VERSION 5.8 ;
BUSBITCHARS "[]" ;
DIVIDERCHAR "/" ;
UNITS
    DATABASE MICRONS 1000 ;
END UNITS

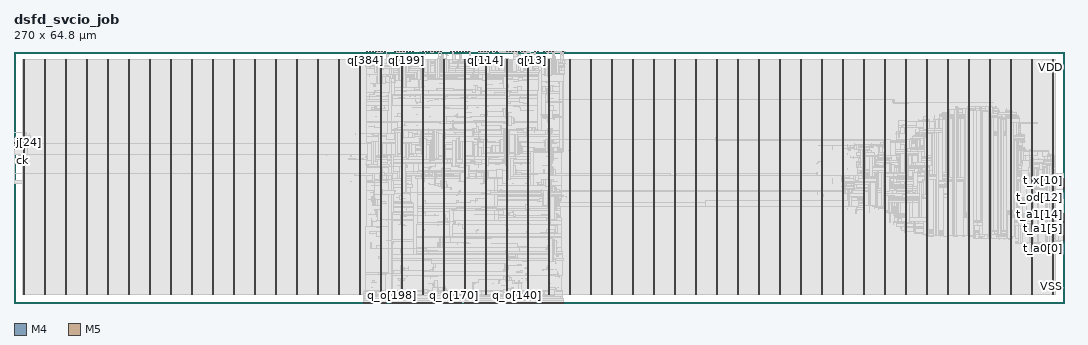
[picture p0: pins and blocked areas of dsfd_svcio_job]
MACRO dsfd_svcio_job
  FOREIGN dsfd_svcio_job 0 0 ;
  CLASS BLOCK ;
  SIZE 270 BY 64.8 ;
  PIN ck
    DIRECTION INPUT ;
    USE SIGNAL ;
    PORT
      LAYER M4 ;
        RECT  0 38.736 0.084 38.76 ;
    END
  END ck
  PIN j[0]
    DIRECTION INPUT ;
    USE SIGNAL ;
    PORT
      LAYER M4 ;
        RECT  0 38.832 0.084 38.856 ;
    END
  END j[0]
  PIN j[10]
    DIRECTION INPUT ;
    USE SIGNAL ;
    PORT
      LAYER M4 ;
        RECT  0 39.792 0.084 39.816 ;
    END
  END j[10]
  PIN j[11]
    DIRECTION INPUT ;
    USE SIGNAL ;
    PORT
      LAYER M4 ;
        RECT  0 39.888 0.084 39.912 ;
    END
  END j[11]
  PIN j[12]
    DIRECTION INPUT ;
    USE SIGNAL ;
    PORT
      LAYER M4 ;
        RECT  0 39.984 0.084 40.008 ;
    END
  END j[12]
  PIN j[13]
    DIRECTION INPUT ;
    USE SIGNAL ;
    PORT
      LAYER M4 ;
        RECT  0 40.08 0.084 40.104 ;
    END
  END j[13]
  PIN j[14]
    DIRECTION INPUT ;
    USE SIGNAL ;
    PORT
      LAYER M4 ;
        RECT  0 40.176 0.084 40.2 ;
    END
  END j[14]
  PIN j[15]
    DIRECTION INPUT ;
    USE SIGNAL ;
    PORT
      LAYER M4 ;
        RECT  0 40.272 0.084 40.296 ;
    END
  END j[15]
  PIN j[16]
    DIRECTION INPUT ;
    USE SIGNAL ;
    PORT
      LAYER M4 ;
        RECT  0 40.368 0.084 40.392 ;
    END
  END j[16]
  PIN j[17]
    DIRECTION INPUT ;
    USE SIGNAL ;
    PORT
      LAYER M4 ;
        RECT  0 40.464 0.084 40.488 ;
    END
  END j[17]
  PIN j[18]
    DIRECTION INPUT ;
    USE SIGNAL ;
    PORT
      LAYER M4 ;
        RECT  0 40.56 0.084 40.584 ;
    END
  END j[18]
  PIN j[19]
    DIRECTION INPUT ;
    USE SIGNAL ;
    PORT
      LAYER M4 ;
        RECT  0 40.656 0.084 40.68 ;
    END
  END j[19]
  PIN j[1]
    DIRECTION INPUT ;
    USE SIGNAL ;
    PORT
      LAYER M4 ;
        RECT  0 38.928 0.084 38.952 ;
    END
  END j[1]
  PIN j[20]
    DIRECTION INPUT ;
    USE SIGNAL ;
    PORT
      LAYER M4 ;
        RECT  0 40.752 0.084 40.776 ;
    END
  END j[20]
  PIN j[21]
    DIRECTION INPUT ;
    USE SIGNAL ;
    PORT
      LAYER M4 ;
        RECT  0 40.848 0.084 40.872 ;
    END
  END j[21]
  PIN j[22]
    DIRECTION INPUT ;
    USE SIGNAL ;
    PORT
      LAYER M4 ;
        RECT  0 40.944 0.084 40.968 ;
    END
  END j[22]
  PIN j[23]
    DIRECTION INPUT ;
    USE SIGNAL ;
    PORT
      LAYER M4 ;
        RECT  0 41.04 0.084 41.064 ;
    END
  END j[23]
  PIN j[24]
    DIRECTION INPUT ;
    USE SIGNAL ;
    PORT
      LAYER M4 ;
        RECT  0 41.136 0.084 41.16 ;
    END
  END j[24]
  PIN j[25]
    DIRECTION INPUT ;
    USE SIGNAL ;
    PORT
      LAYER M4 ;
        RECT  0 41.232 0.084 41.256 ;
    END
  END j[25]
  PIN j[26]
    DIRECTION INPUT ;
    USE SIGNAL ;
    PORT
      LAYER M4 ;
        RECT  0 41.328 0.084 41.352 ;
    END
  END j[26]
  PIN j[27]
    DIRECTION INPUT ;
    USE SIGNAL ;
    PORT
      LAYER M4 ;
        RECT  0 41.424 0.084 41.448 ;
    END
  END j[27]
  PIN j[28]
    DIRECTION INPUT ;
    USE SIGNAL ;
    PORT
      LAYER M4 ;
        RECT  0 41.52 0.084 41.544 ;
    END
  END j[28]
  PIN j[29]
    DIRECTION INPUT ;
    USE SIGNAL ;
    PORT
      LAYER M4 ;
        RECT  0 41.616 0.084 41.64 ;
    END
  END j[29]
  PIN j[2]
    DIRECTION INPUT ;
    USE SIGNAL ;
    PORT
      LAYER M4 ;
        RECT  0 39.024 0.084 39.048 ;
    END
  END j[2]
  PIN j[30]
    DIRECTION INPUT ;
    USE SIGNAL ;
    PORT
      LAYER M4 ;
        RECT  0 41.712 0.084 41.736 ;
    END
  END j[30]
  PIN j[31]
    DIRECTION INPUT ;
    USE SIGNAL ;
    PORT
      LAYER M4 ;
        RECT  0 38.256 0.084 38.28 ;
    END
  END j[31]
  PIN j[32]
    DIRECTION INPUT ;
    USE SIGNAL ;
    PORT
      LAYER M4 ;
        RECT  0 38.352 0.084 38.376 ;
    END
  END j[32]
  PIN j[3]
    DIRECTION INPUT ;
    USE SIGNAL ;
    PORT
      LAYER M4 ;
        RECT  0 39.12 0.084 39.144 ;
    END
  END j[3]
  PIN j[4]
    DIRECTION INPUT ;
    USE SIGNAL ;
    PORT
      LAYER M4 ;
        RECT  0 39.216 0.084 39.24 ;
    END
  END j[4]
  PIN j[5]
    DIRECTION INPUT ;
    USE SIGNAL ;
    PORT
      LAYER M4 ;
        RECT  0 39.312 0.084 39.336 ;
    END
  END j[5]
  PIN j[6]
    DIRECTION INPUT ;
    USE SIGNAL ;
    PORT
      LAYER M4 ;
        RECT  0 39.408 0.084 39.432 ;
    END
  END j[6]
  PIN j[7]
    DIRECTION INPUT ;
    USE SIGNAL ;
    PORT
      LAYER M4 ;
        RECT  0 39.504 0.084 39.528 ;
    END
  END j[7]
  PIN j[8]
    DIRECTION INPUT ;
    USE SIGNAL ;
    PORT
      LAYER M4 ;
        RECT  0 39.6 0.084 39.624 ;
    END
  END j[8]
  PIN j[9]
    DIRECTION INPUT ;
    USE SIGNAL ;
    PORT
      LAYER M4 ;
        RECT  0 39.696 0.084 39.72 ;
    END
  END j[9]
  PIN jd[0]
    DIRECTION OUTPUT ;
    USE SIGNAL ;
    PORT
      LAYER M4 ;
        RECT  0 38.448 0.084 38.472 ;
    END
  END jd[0]
  PIN jd[1]
    DIRECTION OUTPUT ;
    USE SIGNAL ;
    PORT
      LAYER M4 ;
        RECT  0 38.544 0.084 38.568 ;
    END
  END jd[1]
  PIN q[0]
    DIRECTION INPUT ;
    USE SIGNAL ;
    PORT
      LAYER M5 ;
        RECT  131.856 64.716 131.88 64.8 ;
    END
  END q[0]
  PIN q[100]
    DIRECTION INPUT ;
    USE SIGNAL ;
    PORT
      LAYER M5 ;
        RECT  119.952 64.716 119.976 64.8 ;
    END
  END q[100]
  PIN q[101]
    DIRECTION INPUT ;
    USE SIGNAL ;
    PORT
      LAYER M5 ;
        RECT  120.048 64.716 120.072 64.8 ;
    END
  END q[101]
  PIN q[102]
    DIRECTION INPUT ;
    USE SIGNAL ;
    PORT
      LAYER M5 ;
        RECT  120.144 64.716 120.168 64.8 ;
    END
  END q[102]
  PIN q[103]
    DIRECTION INPUT ;
    USE SIGNAL ;
    PORT
      LAYER M5 ;
        RECT  120.24 64.716 120.264 64.8 ;
    END
  END q[103]
  PIN q[104]
    DIRECTION INPUT ;
    USE SIGNAL ;
    PORT
      LAYER M5 ;
        RECT  120.336 64.716 120.36 64.8 ;
    END
  END q[104]
  PIN q[105]
    DIRECTION INPUT ;
    USE SIGNAL ;
    PORT
      LAYER M5 ;
        RECT  120.432 64.716 120.456 64.8 ;
    END
  END q[105]
  PIN q[106]
    DIRECTION INPUT ;
    USE SIGNAL ;
    PORT
      LAYER M5 ;
        RECT  120.528 64.716 120.552 64.8 ;
    END
  END q[106]
  PIN q[107]
    DIRECTION INPUT ;
    USE SIGNAL ;
    PORT
      LAYER M5 ;
        RECT  120.624 64.716 120.648 64.8 ;
    END
  END q[107]
  PIN q[108]
    DIRECTION INPUT ;
    USE SIGNAL ;
    PORT
      LAYER M5 ;
        RECT  120.72 64.716 120.744 64.8 ;
    END
  END q[108]
  PIN q[109]
    DIRECTION INPUT ;
    USE SIGNAL ;
    PORT
      LAYER M5 ;
        RECT  120.816 64.716 120.84 64.8 ;
    END
  END q[109]
  PIN q[10]
    DIRECTION INPUT ;
    USE SIGNAL ;
    PORT
      LAYER M5 ;
        RECT  132.816 64.716 132.84 64.8 ;
    END
  END q[10]
  PIN q[110]
    DIRECTION INPUT ;
    USE SIGNAL ;
    PORT
      LAYER M5 ;
        RECT  120.912 64.716 120.936 64.8 ;
    END
  END q[110]
  PIN q[111]
    DIRECTION INPUT ;
    USE SIGNAL ;
    PORT
      LAYER M5 ;
        RECT  121.008 64.716 121.032 64.8 ;
    END
  END q[111]
  PIN q[112]
    DIRECTION INPUT ;
    USE SIGNAL ;
    PORT
      LAYER M5 ;
        RECT  121.104 64.716 121.128 64.8 ;
    END
  END q[112]
  PIN q[113]
    DIRECTION INPUT ;
    USE SIGNAL ;
    PORT
      LAYER M5 ;
        RECT  121.2 64.716 121.224 64.8 ;
    END
  END q[113]
  PIN q[114]
    DIRECTION INPUT ;
    USE SIGNAL ;
    PORT
      LAYER M5 ;
        RECT  121.296 64.716 121.32 64.8 ;
    END
  END q[114]
  PIN q[115]
    DIRECTION INPUT ;
    USE SIGNAL ;
    PORT
      LAYER M5 ;
        RECT  121.392 64.716 121.416 64.8 ;
    END
  END q[115]
  PIN q[116]
    DIRECTION INPUT ;
    USE SIGNAL ;
    PORT
      LAYER M5 ;
        RECT  121.488 64.716 121.512 64.8 ;
    END
  END q[116]
  PIN q[117]
    DIRECTION INPUT ;
    USE SIGNAL ;
    PORT
      LAYER M5 ;
        RECT  121.584 64.716 121.608 64.8 ;
    END
  END q[117]
  PIN q[118]
    DIRECTION INPUT ;
    USE SIGNAL ;
    PORT
      LAYER M5 ;
        RECT  121.68 64.716 121.704 64.8 ;
    END
  END q[118]
  PIN q[119]
    DIRECTION INPUT ;
    USE SIGNAL ;
    PORT
      LAYER M5 ;
        RECT  121.776 64.716 121.8 64.8 ;
    END
  END q[119]
  PIN q[11]
    DIRECTION INPUT ;
    USE SIGNAL ;
    PORT
      LAYER M5 ;
        RECT  132.912 64.716 132.936 64.8 ;
    END
  END q[11]
  PIN q[120]
    DIRECTION INPUT ;
    USE SIGNAL ;
    PORT
      LAYER M5 ;
        RECT  121.872 64.716 121.896 64.8 ;
    END
  END q[120]
  PIN q[121]
    DIRECTION INPUT ;
    USE SIGNAL ;
    PORT
      LAYER M5 ;
        RECT  121.968 64.716 121.992 64.8 ;
    END
  END q[121]
  PIN q[122]
    DIRECTION INPUT ;
    USE SIGNAL ;
    PORT
      LAYER M5 ;
        RECT  122.064 64.716 122.088 64.8 ;
    END
  END q[122]
  PIN q[123]
    DIRECTION INPUT ;
    USE SIGNAL ;
    PORT
      LAYER M5 ;
        RECT  122.16 64.716 122.184 64.8 ;
    END
  END q[123]
  PIN q[124]
    DIRECTION INPUT ;
    USE SIGNAL ;
    PORT
      LAYER M5 ;
        RECT  122.256 64.716 122.28 64.8 ;
    END
  END q[124]
  PIN q[125]
    DIRECTION INPUT ;
    USE SIGNAL ;
    PORT
      LAYER M5 ;
        RECT  122.352 64.716 122.376 64.8 ;
    END
  END q[125]
  PIN q[126]
    DIRECTION INPUT ;
    USE SIGNAL ;
    PORT
      LAYER M5 ;
        RECT  122.448 64.716 122.472 64.8 ;
    END
  END q[126]
  PIN q[127]
    DIRECTION INPUT ;
    USE SIGNAL ;
    PORT
      LAYER M5 ;
        RECT  122.544 64.716 122.568 64.8 ;
    END
  END q[127]
  PIN q[128]
    DIRECTION INPUT ;
    USE SIGNAL ;
    PORT
      LAYER M5 ;
        RECT  122.64 64.716 122.664 64.8 ;
    END
  END q[128]
  PIN q[129]
    DIRECTION INPUT ;
    USE SIGNAL ;
    PORT
      LAYER M5 ;
        RECT  122.736 64.716 122.76 64.8 ;
    END
  END q[129]
  PIN q[12]
    DIRECTION INPUT ;
    USE SIGNAL ;
    PORT
      LAYER M5 ;
        RECT  133.008 64.716 133.032 64.8 ;
    END
  END q[12]
  PIN q[130]
    DIRECTION INPUT ;
    USE SIGNAL ;
    PORT
      LAYER M5 ;
        RECT  122.832 64.716 122.856 64.8 ;
    END
  END q[130]
  PIN q[131]
    DIRECTION INPUT ;
    USE SIGNAL ;
    PORT
      LAYER M5 ;
        RECT  122.928 64.716 122.952 64.8 ;
    END
  END q[131]
  PIN q[132]
    DIRECTION INPUT ;
    USE SIGNAL ;
    PORT
      LAYER M5 ;
        RECT  123.024 64.716 123.048 64.8 ;
    END
  END q[132]
  PIN q[133]
    DIRECTION INPUT ;
    USE SIGNAL ;
    PORT
      LAYER M5 ;
        RECT  123.12 64.716 123.144 64.8 ;
    END
  END q[133]
  PIN q[134]
    DIRECTION INPUT ;
    USE SIGNAL ;
    PORT
      LAYER M5 ;
        RECT  123.216 64.716 123.24 64.8 ;
    END
  END q[134]
  PIN q[135]
    DIRECTION INPUT ;
    USE SIGNAL ;
    PORT
      LAYER M5 ;
        RECT  123.312 64.716 123.336 64.8 ;
    END
  END q[135]
  PIN q[136]
    DIRECTION INPUT ;
    USE SIGNAL ;
    PORT
      LAYER M5 ;
        RECT  123.408 64.716 123.432 64.8 ;
    END
  END q[136]
  PIN q[137]
    DIRECTION INPUT ;
    USE SIGNAL ;
    PORT
      LAYER M5 ;
        RECT  123.504 64.716 123.528 64.8 ;
    END
  END q[137]
  PIN q[138]
    DIRECTION INPUT ;
    USE SIGNAL ;
    PORT
      LAYER M5 ;
        RECT  123.6 64.716 123.624 64.8 ;
    END
  END q[138]
  PIN q[139]
    DIRECTION INPUT ;
    USE SIGNAL ;
    PORT
      LAYER M5 ;
        RECT  123.696 64.716 123.72 64.8 ;
    END
  END q[139]
  PIN q[13]
    DIRECTION INPUT ;
    USE SIGNAL ;
    PORT
      LAYER M5 ;
        RECT  133.104 64.716 133.128 64.8 ;
    END
  END q[13]
  PIN q[140]
    DIRECTION INPUT ;
    USE SIGNAL ;
    PORT
      LAYER M5 ;
        RECT  123.792 64.716 123.816 64.8 ;
    END
  END q[140]
  PIN q[141]
    DIRECTION INPUT ;
    USE SIGNAL ;
    PORT
      LAYER M5 ;
        RECT  123.888 64.716 123.912 64.8 ;
    END
  END q[141]
  PIN q[142]
    DIRECTION INPUT ;
    USE SIGNAL ;
    PORT
      LAYER M5 ;
        RECT  123.984 64.716 124.008 64.8 ;
    END
  END q[142]
  PIN q[143]
    DIRECTION INPUT ;
    USE SIGNAL ;
    PORT
      LAYER M5 ;
        RECT  124.08 64.716 124.104 64.8 ;
    END
  END q[143]
  PIN q[144]
    DIRECTION INPUT ;
    USE SIGNAL ;
    PORT
      LAYER M5 ;
        RECT  124.176 64.716 124.2 64.8 ;
    END
  END q[144]
  PIN q[145]
    DIRECTION INPUT ;
    USE SIGNAL ;
    PORT
      LAYER M5 ;
        RECT  124.272 64.716 124.296 64.8 ;
    END
  END q[145]
  PIN q[146]
    DIRECTION INPUT ;
    USE SIGNAL ;
    PORT
      LAYER M5 ;
        RECT  124.368 64.716 124.392 64.8 ;
    END
  END q[146]
  PIN q[147]
    DIRECTION INPUT ;
    USE SIGNAL ;
    PORT
      LAYER M5 ;
        RECT  124.464 64.716 124.488 64.8 ;
    END
  END q[147]
  PIN q[148]
    DIRECTION INPUT ;
    USE SIGNAL ;
    PORT
      LAYER M5 ;
        RECT  124.56 64.716 124.584 64.8 ;
    END
  END q[148]
  PIN q[149]
    DIRECTION INPUT ;
    USE SIGNAL ;
    PORT
      LAYER M5 ;
        RECT  124.656 64.716 124.68 64.8 ;
    END
  END q[149]
  PIN q[14]
    DIRECTION INPUT ;
    USE SIGNAL ;
    PORT
      LAYER M5 ;
        RECT  133.2 64.716 133.224 64.8 ;
    END
  END q[14]
  PIN q[150]
    DIRECTION INPUT ;
    USE SIGNAL ;
    PORT
      LAYER M5 ;
        RECT  124.752 64.716 124.776 64.8 ;
    END
  END q[150]
  PIN q[151]
    DIRECTION INPUT ;
    USE SIGNAL ;
    PORT
      LAYER M5 ;
        RECT  124.848 64.716 124.872 64.8 ;
    END
  END q[151]
  PIN q[152]
    DIRECTION INPUT ;
    USE SIGNAL ;
    PORT
      LAYER M5 ;
        RECT  124.944 64.716 124.968 64.8 ;
    END
  END q[152]
  PIN q[153]
    DIRECTION INPUT ;
    USE SIGNAL ;
    PORT
      LAYER M5 ;
        RECT  125.04 64.716 125.064 64.8 ;
    END
  END q[153]
  PIN q[154]
    DIRECTION INPUT ;
    USE SIGNAL ;
    PORT
      LAYER M5 ;
        RECT  125.136 64.716 125.16 64.8 ;
    END
  END q[154]
  PIN q[155]
    DIRECTION INPUT ;
    USE SIGNAL ;
    PORT
      LAYER M5 ;
        RECT  125.232 64.716 125.256 64.8 ;
    END
  END q[155]
  PIN q[156]
    DIRECTION INPUT ;
    USE SIGNAL ;
    PORT
      LAYER M5 ;
        RECT  125.328 64.716 125.352 64.8 ;
    END
  END q[156]
  PIN q[157]
    DIRECTION INPUT ;
    USE SIGNAL ;
    PORT
      LAYER M5 ;
        RECT  125.424 64.716 125.448 64.8 ;
    END
  END q[157]
  PIN q[158]
    DIRECTION INPUT ;
    USE SIGNAL ;
    PORT
      LAYER M5 ;
        RECT  125.52 64.716 125.544 64.8 ;
    END
  END q[158]
  PIN q[159]
    DIRECTION INPUT ;
    USE SIGNAL ;
    PORT
      LAYER M5 ;
        RECT  125.616 64.716 125.64 64.8 ;
    END
  END q[159]
  PIN q[15]
    DIRECTION INPUT ;
    USE SIGNAL ;
    PORT
      LAYER M5 ;
        RECT  133.296 64.716 133.32 64.8 ;
    END
  END q[15]
  PIN q[160]
    DIRECTION INPUT ;
    USE SIGNAL ;
    PORT
      LAYER M5 ;
        RECT  112.656 64.716 112.68 64.8 ;
    END
  END q[160]
  PIN q[161]
    DIRECTION INPUT ;
    USE SIGNAL ;
    PORT
      LAYER M5 ;
        RECT  112.752 64.716 112.776 64.8 ;
    END
  END q[161]
  PIN q[162]
    DIRECTION INPUT ;
    USE SIGNAL ;
    PORT
      LAYER M5 ;
        RECT  112.848 64.716 112.872 64.8 ;
    END
  END q[162]
  PIN q[163]
    DIRECTION INPUT ;
    USE SIGNAL ;
    PORT
      LAYER M5 ;
        RECT  112.944 64.716 112.968 64.8 ;
    END
  END q[163]
  PIN q[164]
    DIRECTION INPUT ;
    USE SIGNAL ;
    PORT
      LAYER M5 ;
        RECT  113.04 64.716 113.064 64.8 ;
    END
  END q[164]
  PIN q[165]
    DIRECTION INPUT ;
    USE SIGNAL ;
    PORT
      LAYER M5 ;
        RECT  113.136 64.716 113.16 64.8 ;
    END
  END q[165]
  PIN q[166]
    DIRECTION INPUT ;
    USE SIGNAL ;
    PORT
      LAYER M5 ;
        RECT  113.232 64.716 113.256 64.8 ;
    END
  END q[166]
  PIN q[167]
    DIRECTION INPUT ;
    USE SIGNAL ;
    PORT
      LAYER M5 ;
        RECT  113.328 64.716 113.352 64.8 ;
    END
  END q[167]
  PIN q[168]
    DIRECTION INPUT ;
    USE SIGNAL ;
    PORT
      LAYER M5 ;
        RECT  113.424 64.716 113.448 64.8 ;
    END
  END q[168]
  PIN q[169]
    DIRECTION INPUT ;
    USE SIGNAL ;
    PORT
      LAYER M5 ;
        RECT  113.52 64.716 113.544 64.8 ;
    END
  END q[169]
  PIN q[16]
    DIRECTION INPUT ;
    USE SIGNAL ;
    PORT
      LAYER M5 ;
        RECT  133.392 64.716 133.416 64.8 ;
    END
  END q[16]
  PIN q[170]
    DIRECTION INPUT ;
    USE SIGNAL ;
    PORT
      LAYER M5 ;
        RECT  113.616 64.716 113.64 64.8 ;
    END
  END q[170]
  PIN q[171]
    DIRECTION INPUT ;
    USE SIGNAL ;
    PORT
      LAYER M5 ;
        RECT  113.712 64.716 113.736 64.8 ;
    END
  END q[171]
  PIN q[172]
    DIRECTION INPUT ;
    USE SIGNAL ;
    PORT
      LAYER M5 ;
        RECT  113.808 64.716 113.832 64.8 ;
    END
  END q[172]
  PIN q[173]
    DIRECTION INPUT ;
    USE SIGNAL ;
    PORT
      LAYER M5 ;
        RECT  113.904 64.716 113.928 64.8 ;
    END
  END q[173]
  PIN q[174]
    DIRECTION INPUT ;
    USE SIGNAL ;
    PORT
      LAYER M5 ;
        RECT  114 64.716 114.024 64.8 ;
    END
  END q[174]
  PIN q[175]
    DIRECTION INPUT ;
    USE SIGNAL ;
    PORT
      LAYER M5 ;
        RECT  114.096 64.716 114.12 64.8 ;
    END
  END q[175]
  PIN q[176]
    DIRECTION INPUT ;
    USE SIGNAL ;
    PORT
      LAYER M5 ;
        RECT  114.192 64.716 114.216 64.8 ;
    END
  END q[176]
  PIN q[177]
    DIRECTION INPUT ;
    USE SIGNAL ;
    PORT
      LAYER M5 ;
        RECT  114.288 64.716 114.312 64.8 ;
    END
  END q[177]
  PIN q[178]
    DIRECTION INPUT ;
    USE SIGNAL ;
    PORT
      LAYER M5 ;
        RECT  114.384 64.716 114.408 64.8 ;
    END
  END q[178]
  PIN q[179]
    DIRECTION INPUT ;
    USE SIGNAL ;
    PORT
      LAYER M5 ;
        RECT  114.48 64.716 114.504 64.8 ;
    END
  END q[179]
  PIN q[17]
    DIRECTION INPUT ;
    USE SIGNAL ;
    PORT
      LAYER M5 ;
        RECT  133.488 64.716 133.512 64.8 ;
    END
  END q[17]
  PIN q[180]
    DIRECTION INPUT ;
    USE SIGNAL ;
    PORT
      LAYER M5 ;
        RECT  114.576 64.716 114.6 64.8 ;
    END
  END q[180]
  PIN q[181]
    DIRECTION INPUT ;
    USE SIGNAL ;
    PORT
      LAYER M5 ;
        RECT  114.672 64.716 114.696 64.8 ;
    END
  END q[181]
  PIN q[182]
    DIRECTION INPUT ;
    USE SIGNAL ;
    PORT
      LAYER M5 ;
        RECT  114.768 64.716 114.792 64.8 ;
    END
  END q[182]
  PIN q[183]
    DIRECTION INPUT ;
    USE SIGNAL ;
    PORT
      LAYER M5 ;
        RECT  114.864 64.716 114.888 64.8 ;
    END
  END q[183]
  PIN q[184]
    DIRECTION INPUT ;
    USE SIGNAL ;
    PORT
      LAYER M5 ;
        RECT  114.96 64.716 114.984 64.8 ;
    END
  END q[184]
  PIN q[185]
    DIRECTION INPUT ;
    USE SIGNAL ;
    PORT
      LAYER M5 ;
        RECT  115.056 64.716 115.08 64.8 ;
    END
  END q[185]
  PIN q[186]
    DIRECTION INPUT ;
    USE SIGNAL ;
    PORT
      LAYER M5 ;
        RECT  115.152 64.716 115.176 64.8 ;
    END
  END q[186]
  PIN q[187]
    DIRECTION INPUT ;
    USE SIGNAL ;
    PORT
      LAYER M5 ;
        RECT  115.248 64.716 115.272 64.8 ;
    END
  END q[187]
  PIN q[188]
    DIRECTION INPUT ;
    USE SIGNAL ;
    PORT
      LAYER M5 ;
        RECT  115.344 64.716 115.368 64.8 ;
    END
  END q[188]
  PIN q[189]
    DIRECTION INPUT ;
    USE SIGNAL ;
    PORT
      LAYER M5 ;
        RECT  115.44 64.716 115.464 64.8 ;
    END
  END q[189]
  PIN q[18]
    DIRECTION INPUT ;
    USE SIGNAL ;
    PORT
      LAYER M5 ;
        RECT  133.584 64.716 133.608 64.8 ;
    END
  END q[18]
  PIN q[190]
    DIRECTION INPUT ;
    USE SIGNAL ;
    PORT
      LAYER M5 ;
        RECT  115.536 64.716 115.56 64.8 ;
    END
  END q[190]
  PIN q[191]
    DIRECTION INPUT ;
    USE SIGNAL ;
    PORT
      LAYER M5 ;
        RECT  115.632 64.716 115.656 64.8 ;
    END
  END q[191]
  PIN q[192]
    DIRECTION INPUT ;
    USE SIGNAL ;
    PORT
      LAYER M5 ;
        RECT  100.368 64.716 100.392 64.8 ;
    END
  END q[192]
  PIN q[193]
    DIRECTION INPUT ;
    USE SIGNAL ;
    PORT
      LAYER M5 ;
        RECT  100.464 64.716 100.488 64.8 ;
    END
  END q[193]
  PIN q[194]
    DIRECTION INPUT ;
    USE SIGNAL ;
    PORT
      LAYER M5 ;
        RECT  100.56 64.716 100.584 64.8 ;
    END
  END q[194]
  PIN q[195]
    DIRECTION INPUT ;
    USE SIGNAL ;
    PORT
      LAYER M5 ;
        RECT  100.656 64.716 100.68 64.8 ;
    END
  END q[195]
  PIN q[196]
    DIRECTION INPUT ;
    USE SIGNAL ;
    PORT
      LAYER M5 ;
        RECT  100.752 64.716 100.776 64.8 ;
    END
  END q[196]
  PIN q[197]
    DIRECTION INPUT ;
    USE SIGNAL ;
    PORT
      LAYER M5 ;
        RECT  100.848 64.716 100.872 64.8 ;
    END
  END q[197]
  PIN q[198]
    DIRECTION INPUT ;
    USE SIGNAL ;
    PORT
      LAYER M5 ;
        RECT  100.944 64.716 100.968 64.8 ;
    END
  END q[198]
  PIN q[199]
    DIRECTION INPUT ;
    USE SIGNAL ;
    PORT
      LAYER M5 ;
        RECT  101.04 64.716 101.064 64.8 ;
    END
  END q[199]
  PIN q[19]
    DIRECTION INPUT ;
    USE SIGNAL ;
    PORT
      LAYER M5 ;
        RECT  133.68 64.716 133.704 64.8 ;
    END
  END q[19]
  PIN q[1]
    DIRECTION INPUT ;
    USE SIGNAL ;
    PORT
      LAYER M5 ;
        RECT  131.952 64.716 131.976 64.8 ;
    END
  END q[1]
  PIN q[200]
    DIRECTION INPUT ;
    USE SIGNAL ;
    PORT
      LAYER M5 ;
        RECT  101.136 64.716 101.16 64.8 ;
    END
  END q[200]
  PIN q[201]
    DIRECTION INPUT ;
    USE SIGNAL ;
    PORT
      LAYER M5 ;
        RECT  101.232 64.716 101.256 64.8 ;
    END
  END q[201]
  PIN q[202]
    DIRECTION INPUT ;
    USE SIGNAL ;
    PORT
      LAYER M5 ;
        RECT  101.328 64.716 101.352 64.8 ;
    END
  END q[202]
  PIN q[203]
    DIRECTION INPUT ;
    USE SIGNAL ;
    PORT
      LAYER M5 ;
        RECT  101.424 64.716 101.448 64.8 ;
    END
  END q[203]
  PIN q[204]
    DIRECTION INPUT ;
    USE SIGNAL ;
    PORT
      LAYER M5 ;
        RECT  101.52 64.716 101.544 64.8 ;
    END
  END q[204]
  PIN q[205]
    DIRECTION INPUT ;
    USE SIGNAL ;
    PORT
      LAYER M5 ;
        RECT  101.616 64.716 101.64 64.8 ;
    END
  END q[205]
  PIN q[206]
    DIRECTION INPUT ;
    USE SIGNAL ;
    PORT
      LAYER M5 ;
        RECT  101.712 64.716 101.736 64.8 ;
    END
  END q[206]
  PIN q[207]
    DIRECTION INPUT ;
    USE SIGNAL ;
    PORT
      LAYER M5 ;
        RECT  101.808 64.716 101.832 64.8 ;
    END
  END q[207]
  PIN q[208]
    DIRECTION INPUT ;
    USE SIGNAL ;
    PORT
      LAYER M5 ;
        RECT  101.904 64.716 101.928 64.8 ;
    END
  END q[208]
  PIN q[209]
    DIRECTION INPUT ;
    USE SIGNAL ;
    PORT
      LAYER M5 ;
        RECT  102 64.716 102.024 64.8 ;
    END
  END q[209]
  PIN q[20]
    DIRECTION INPUT ;
    USE SIGNAL ;
    PORT
      LAYER M5 ;
        RECT  133.776 64.716 133.8 64.8 ;
    END
  END q[20]
  PIN q[210]
    DIRECTION INPUT ;
    USE SIGNAL ;
    PORT
      LAYER M5 ;
        RECT  102.096 64.716 102.12 64.8 ;
    END
  END q[210]
  PIN q[211]
    DIRECTION INPUT ;
    USE SIGNAL ;
    PORT
      LAYER M5 ;
        RECT  102.192 64.716 102.216 64.8 ;
    END
  END q[211]
  PIN q[212]
    DIRECTION INPUT ;
    USE SIGNAL ;
    PORT
      LAYER M5 ;
        RECT  102.288 64.716 102.312 64.8 ;
    END
  END q[212]
  PIN q[213]
    DIRECTION INPUT ;
    USE SIGNAL ;
    PORT
      LAYER M5 ;
        RECT  102.384 64.716 102.408 64.8 ;
    END
  END q[213]
  PIN q[214]
    DIRECTION INPUT ;
    USE SIGNAL ;
    PORT
      LAYER M5 ;
        RECT  102.48 64.716 102.504 64.8 ;
    END
  END q[214]
  PIN q[215]
    DIRECTION INPUT ;
    USE SIGNAL ;
    PORT
      LAYER M5 ;
        RECT  102.576 64.716 102.6 64.8 ;
    END
  END q[215]
  PIN q[216]
    DIRECTION INPUT ;
    USE SIGNAL ;
    PORT
      LAYER M5 ;
        RECT  102.672 64.716 102.696 64.8 ;
    END
  END q[216]
  PIN q[217]
    DIRECTION INPUT ;
    USE SIGNAL ;
    PORT
      LAYER M5 ;
        RECT  102.768 64.716 102.792 64.8 ;
    END
  END q[217]
  PIN q[218]
    DIRECTION INPUT ;
    USE SIGNAL ;
    PORT
      LAYER M5 ;
        RECT  102.864 64.716 102.888 64.8 ;
    END
  END q[218]
  PIN q[219]
    DIRECTION INPUT ;
    USE SIGNAL ;
    PORT
      LAYER M5 ;
        RECT  102.96 64.716 102.984 64.8 ;
    END
  END q[219]
  PIN q[21]
    DIRECTION INPUT ;
    USE SIGNAL ;
    PORT
      LAYER M5 ;
        RECT  133.872 64.716 133.896 64.8 ;
    END
  END q[21]
  PIN q[220]
    DIRECTION INPUT ;
    USE SIGNAL ;
    PORT
      LAYER M5 ;
        RECT  103.056 64.716 103.08 64.8 ;
    END
  END q[220]
  PIN q[221]
    DIRECTION INPUT ;
    USE SIGNAL ;
    PORT
      LAYER M5 ;
        RECT  103.152 64.716 103.176 64.8 ;
    END
  END q[221]
  PIN q[222]
    DIRECTION INPUT ;
    USE SIGNAL ;
    PORT
      LAYER M5 ;
        RECT  103.248 64.716 103.272 64.8 ;
    END
  END q[222]
  PIN q[223]
    DIRECTION INPUT ;
    USE SIGNAL ;
    PORT
      LAYER M5 ;
        RECT  103.344 64.716 103.368 64.8 ;
    END
  END q[223]
  PIN q[224]
    DIRECTION INPUT ;
    USE SIGNAL ;
    PORT
      LAYER M5 ;
        RECT  97.296 64.716 97.32 64.8 ;
    END
  END q[224]
  PIN q[225]
    DIRECTION INPUT ;
    USE SIGNAL ;
    PORT
      LAYER M5 ;
        RECT  97.392 64.716 97.416 64.8 ;
    END
  END q[225]
  PIN q[226]
    DIRECTION INPUT ;
    USE SIGNAL ;
    PORT
      LAYER M5 ;
        RECT  97.488 64.716 97.512 64.8 ;
    END
  END q[226]
  PIN q[227]
    DIRECTION INPUT ;
    USE SIGNAL ;
    PORT
      LAYER M5 ;
        RECT  97.584 64.716 97.608 64.8 ;
    END
  END q[227]
  PIN q[228]
    DIRECTION INPUT ;
    USE SIGNAL ;
    PORT
      LAYER M5 ;
        RECT  97.68 64.716 97.704 64.8 ;
    END
  END q[228]
  PIN q[229]
    DIRECTION INPUT ;
    USE SIGNAL ;
    PORT
      LAYER M5 ;
        RECT  97.776 64.716 97.8 64.8 ;
    END
  END q[229]
  PIN q[22]
    DIRECTION INPUT ;
    USE SIGNAL ;
    PORT
      LAYER M5 ;
        RECT  133.968 64.716 133.992 64.8 ;
    END
  END q[22]
  PIN q[230]
    DIRECTION INPUT ;
    USE SIGNAL ;
    PORT
      LAYER M5 ;
        RECT  97.872 64.716 97.896 64.8 ;
    END
  END q[230]
  PIN q[231]
    DIRECTION INPUT ;
    USE SIGNAL ;
    PORT
      LAYER M5 ;
        RECT  97.968 64.716 97.992 64.8 ;
    END
  END q[231]
  PIN q[232]
    DIRECTION INPUT ;
    USE SIGNAL ;
    PORT
      LAYER M5 ;
        RECT  98.064 64.716 98.088 64.8 ;
    END
  END q[232]
  PIN q[233]
    DIRECTION INPUT ;
    USE SIGNAL ;
    PORT
      LAYER M5 ;
        RECT  98.16 64.716 98.184 64.8 ;
    END
  END q[233]
  PIN q[234]
    DIRECTION INPUT ;
    USE SIGNAL ;
    PORT
      LAYER M5 ;
        RECT  98.256 64.716 98.28 64.8 ;
    END
  END q[234]
  PIN q[235]
    DIRECTION INPUT ;
    USE SIGNAL ;
    PORT
      LAYER M5 ;
        RECT  98.352 64.716 98.376 64.8 ;
    END
  END q[235]
  PIN q[236]
    DIRECTION INPUT ;
    USE SIGNAL ;
    PORT
      LAYER M5 ;
        RECT  98.448 64.716 98.472 64.8 ;
    END
  END q[236]
  PIN q[237]
    DIRECTION INPUT ;
    USE SIGNAL ;
    PORT
      LAYER M5 ;
        RECT  98.544 64.716 98.568 64.8 ;
    END
  END q[237]
  PIN q[238]
    DIRECTION INPUT ;
    USE SIGNAL ;
    PORT
      LAYER M5 ;
        RECT  98.64 64.716 98.664 64.8 ;
    END
  END q[238]
  PIN q[239]
    DIRECTION INPUT ;
    USE SIGNAL ;
    PORT
      LAYER M5 ;
        RECT  98.736 64.716 98.76 64.8 ;
    END
  END q[239]
  PIN q[23]
    DIRECTION INPUT ;
    USE SIGNAL ;
    PORT
      LAYER M5 ;
        RECT  134.064 64.716 134.088 64.8 ;
    END
  END q[23]
  PIN q[240]
    DIRECTION INPUT ;
    USE SIGNAL ;
    PORT
      LAYER M5 ;
        RECT  98.832 64.716 98.856 64.8 ;
    END
  END q[240]
  PIN q[241]
    DIRECTION INPUT ;
    USE SIGNAL ;
    PORT
      LAYER M5 ;
        RECT  98.928 64.716 98.952 64.8 ;
    END
  END q[241]
  PIN q[242]
    DIRECTION INPUT ;
    USE SIGNAL ;
    PORT
      LAYER M5 ;
        RECT  99.024 64.716 99.048 64.8 ;
    END
  END q[242]
  PIN q[243]
    DIRECTION INPUT ;
    USE SIGNAL ;
    PORT
      LAYER M5 ;
        RECT  99.12 64.716 99.144 64.8 ;
    END
  END q[243]
  PIN q[244]
    DIRECTION INPUT ;
    USE SIGNAL ;
    PORT
      LAYER M5 ;
        RECT  99.216 64.716 99.24 64.8 ;
    END
  END q[244]
  PIN q[245]
    DIRECTION INPUT ;
    USE SIGNAL ;
    PORT
      LAYER M5 ;
        RECT  99.312 64.716 99.336 64.8 ;
    END
  END q[245]
  PIN q[246]
    DIRECTION INPUT ;
    USE SIGNAL ;
    PORT
      LAYER M5 ;
        RECT  99.408 64.716 99.432 64.8 ;
    END
  END q[246]
  PIN q[247]
    DIRECTION INPUT ;
    USE SIGNAL ;
    PORT
      LAYER M5 ;
        RECT  99.504 64.716 99.528 64.8 ;
    END
  END q[247]
  PIN q[248]
    DIRECTION INPUT ;
    USE SIGNAL ;
    PORT
      LAYER M5 ;
        RECT  99.6 64.716 99.624 64.8 ;
    END
  END q[248]
  PIN q[249]
    DIRECTION INPUT ;
    USE SIGNAL ;
    PORT
      LAYER M5 ;
        RECT  99.696 64.716 99.72 64.8 ;
    END
  END q[249]
  PIN q[24]
    DIRECTION INPUT ;
    USE SIGNAL ;
    PORT
      LAYER M5 ;
        RECT  134.16 64.716 134.184 64.8 ;
    END
  END q[24]
  PIN q[250]
    DIRECTION INPUT ;
    USE SIGNAL ;
    PORT
      LAYER M5 ;
        RECT  99.792 64.716 99.816 64.8 ;
    END
  END q[250]
  PIN q[251]
    DIRECTION INPUT ;
    USE SIGNAL ;
    PORT
      LAYER M5 ;
        RECT  99.888 64.716 99.912 64.8 ;
    END
  END q[251]
  PIN q[252]
    DIRECTION INPUT ;
    USE SIGNAL ;
    PORT
      LAYER M5 ;
        RECT  99.984 64.716 100.008 64.8 ;
    END
  END q[252]
  PIN q[253]
    DIRECTION INPUT ;
    USE SIGNAL ;
    PORT
      LAYER M5 ;
        RECT  100.08 64.716 100.104 64.8 ;
    END
  END q[253]
  PIN q[254]
    DIRECTION INPUT ;
    USE SIGNAL ;
    PORT
      LAYER M5 ;
        RECT  100.176 64.716 100.2 64.8 ;
    END
  END q[254]
  PIN q[255]
    DIRECTION INPUT ;
    USE SIGNAL ;
    PORT
      LAYER M5 ;
        RECT  100.272 64.716 100.296 64.8 ;
    END
  END q[255]
  PIN q[256]
    DIRECTION INPUT ;
    USE SIGNAL ;
    PORT
      LAYER M5 ;
        RECT  103.44 64.716 103.464 64.8 ;
    END
  END q[256]
  PIN q[257]
    DIRECTION INPUT ;
    USE SIGNAL ;
    PORT
      LAYER M5 ;
        RECT  103.536 64.716 103.56 64.8 ;
    END
  END q[257]
  PIN q[258]
    DIRECTION INPUT ;
    USE SIGNAL ;
    PORT
      LAYER M5 ;
        RECT  103.632 64.716 103.656 64.8 ;
    END
  END q[258]
  PIN q[259]
    DIRECTION INPUT ;
    USE SIGNAL ;
    PORT
      LAYER M5 ;
        RECT  103.728 64.716 103.752 64.8 ;
    END
  END q[259]
  PIN q[25]
    DIRECTION INPUT ;
    USE SIGNAL ;
    PORT
      LAYER M5 ;
        RECT  134.256 64.716 134.28 64.8 ;
    END
  END q[25]
  PIN q[260]
    DIRECTION INPUT ;
    USE SIGNAL ;
    PORT
      LAYER M5 ;
        RECT  103.824 64.716 103.848 64.8 ;
    END
  END q[260]
  PIN q[261]
    DIRECTION INPUT ;
    USE SIGNAL ;
    PORT
      LAYER M5 ;
        RECT  103.92 64.716 103.944 64.8 ;
    END
  END q[261]
  PIN q[262]
    DIRECTION INPUT ;
    USE SIGNAL ;
    PORT
      LAYER M5 ;
        RECT  104.016 64.716 104.04 64.8 ;
    END
  END q[262]
  PIN q[263]
    DIRECTION INPUT ;
    USE SIGNAL ;
    PORT
      LAYER M5 ;
        RECT  104.112 64.716 104.136 64.8 ;
    END
  END q[263]
  PIN q[264]
    DIRECTION INPUT ;
    USE SIGNAL ;
    PORT
      LAYER M5 ;
        RECT  104.208 64.716 104.232 64.8 ;
    END
  END q[264]
  PIN q[265]
    DIRECTION INPUT ;
    USE SIGNAL ;
    PORT
      LAYER M5 ;
        RECT  104.304 64.716 104.328 64.8 ;
    END
  END q[265]
  PIN q[266]
    DIRECTION INPUT ;
    USE SIGNAL ;
    PORT
      LAYER M5 ;
        RECT  104.4 64.716 104.424 64.8 ;
    END
  END q[266]
  PIN q[267]
    DIRECTION INPUT ;
    USE SIGNAL ;
    PORT
      LAYER M5 ;
        RECT  104.496 64.716 104.52 64.8 ;
    END
  END q[267]
  PIN q[268]
    DIRECTION INPUT ;
    USE SIGNAL ;
    PORT
      LAYER M5 ;
        RECT  104.592 64.716 104.616 64.8 ;
    END
  END q[268]
  PIN q[269]
    DIRECTION INPUT ;
    USE SIGNAL ;
    PORT
      LAYER M5 ;
        RECT  104.688 64.716 104.712 64.8 ;
    END
  END q[269]
  PIN q[26]
    DIRECTION INPUT ;
    USE SIGNAL ;
    PORT
      LAYER M5 ;
        RECT  134.352 64.716 134.376 64.8 ;
    END
  END q[26]
  PIN q[270]
    DIRECTION INPUT ;
    USE SIGNAL ;
    PORT
      LAYER M5 ;
        RECT  104.784 64.716 104.808 64.8 ;
    END
  END q[270]
  PIN q[271]
    DIRECTION INPUT ;
    USE SIGNAL ;
    PORT
      LAYER M5 ;
        RECT  104.88 64.716 104.904 64.8 ;
    END
  END q[271]
  PIN q[272]
    DIRECTION INPUT ;
    USE SIGNAL ;
    PORT
      LAYER M5 ;
        RECT  104.976 64.716 105 64.8 ;
    END
  END q[272]
  PIN q[273]
    DIRECTION INPUT ;
    USE SIGNAL ;
    PORT
      LAYER M5 ;
        RECT  105.072 64.716 105.096 64.8 ;
    END
  END q[273]
  PIN q[274]
    DIRECTION INPUT ;
    USE SIGNAL ;
    PORT
      LAYER M5 ;
        RECT  105.168 64.716 105.192 64.8 ;
    END
  END q[274]
  PIN q[275]
    DIRECTION INPUT ;
    USE SIGNAL ;
    PORT
      LAYER M5 ;
        RECT  105.264 64.716 105.288 64.8 ;
    END
  END q[275]
  PIN q[276]
    DIRECTION INPUT ;
    USE SIGNAL ;
    PORT
      LAYER M5 ;
        RECT  105.36 64.716 105.384 64.8 ;
    END
  END q[276]
  PIN q[277]
    DIRECTION INPUT ;
    USE SIGNAL ;
    PORT
      LAYER M5 ;
        RECT  105.456 64.716 105.48 64.8 ;
    END
  END q[277]
  PIN q[278]
    DIRECTION INPUT ;
    USE SIGNAL ;
    PORT
      LAYER M5 ;
        RECT  105.552 64.716 105.576 64.8 ;
    END
  END q[278]
  PIN q[279]
    DIRECTION INPUT ;
    USE SIGNAL ;
    PORT
      LAYER M5 ;
        RECT  105.648 64.716 105.672 64.8 ;
    END
  END q[279]
  PIN q[27]
    DIRECTION INPUT ;
    USE SIGNAL ;
    PORT
      LAYER M5 ;
        RECT  134.448 64.716 134.472 64.8 ;
    END
  END q[27]
  PIN q[280]
    DIRECTION INPUT ;
    USE SIGNAL ;
    PORT
      LAYER M5 ;
        RECT  105.744 64.716 105.768 64.8 ;
    END
  END q[280]
  PIN q[281]
    DIRECTION INPUT ;
    USE SIGNAL ;
    PORT
      LAYER M5 ;
        RECT  105.84 64.716 105.864 64.8 ;
    END
  END q[281]
  PIN q[282]
    DIRECTION INPUT ;
    USE SIGNAL ;
    PORT
      LAYER M5 ;
        RECT  105.936 64.716 105.96 64.8 ;
    END
  END q[282]
  PIN q[283]
    DIRECTION INPUT ;
    USE SIGNAL ;
    PORT
      LAYER M5 ;
        RECT  106.032 64.716 106.056 64.8 ;
    END
  END q[283]
  PIN q[284]
    DIRECTION INPUT ;
    USE SIGNAL ;
    PORT
      LAYER M5 ;
        RECT  106.128 64.716 106.152 64.8 ;
    END
  END q[284]
  PIN q[285]
    DIRECTION INPUT ;
    USE SIGNAL ;
    PORT
      LAYER M5 ;
        RECT  106.224 64.716 106.248 64.8 ;
    END
  END q[285]
  PIN q[286]
    DIRECTION INPUT ;
    USE SIGNAL ;
    PORT
      LAYER M5 ;
        RECT  106.32 64.716 106.344 64.8 ;
    END
  END q[286]
  PIN q[287]
    DIRECTION INPUT ;
    USE SIGNAL ;
    PORT
      LAYER M5 ;
        RECT  106.416 64.716 106.44 64.8 ;
    END
  END q[287]
  PIN q[288]
    DIRECTION INPUT ;
    USE SIGNAL ;
    PORT
      LAYER M5 ;
        RECT  106.512 64.716 106.536 64.8 ;
    END
  END q[288]
  PIN q[289]
    DIRECTION INPUT ;
    USE SIGNAL ;
    PORT
      LAYER M5 ;
        RECT  106.608 64.716 106.632 64.8 ;
    END
  END q[289]
  PIN q[28]
    DIRECTION INPUT ;
    USE SIGNAL ;
    PORT
      LAYER M5 ;
        RECT  134.544 64.716 134.568 64.8 ;
    END
  END q[28]
  PIN q[290]
    DIRECTION INPUT ;
    USE SIGNAL ;
    PORT
      LAYER M5 ;
        RECT  106.704 64.716 106.728 64.8 ;
    END
  END q[290]
  PIN q[291]
    DIRECTION INPUT ;
    USE SIGNAL ;
    PORT
      LAYER M5 ;
        RECT  106.8 64.716 106.824 64.8 ;
    END
  END q[291]
  PIN q[292]
    DIRECTION INPUT ;
    USE SIGNAL ;
    PORT
      LAYER M5 ;
        RECT  106.896 64.716 106.92 64.8 ;
    END
  END q[292]
  PIN q[293]
    DIRECTION INPUT ;
    USE SIGNAL ;
    PORT
      LAYER M5 ;
        RECT  106.992 64.716 107.016 64.8 ;
    END
  END q[293]
  PIN q[294]
    DIRECTION INPUT ;
    USE SIGNAL ;
    PORT
      LAYER M5 ;
        RECT  107.088 64.716 107.112 64.8 ;
    END
  END q[294]
  PIN q[295]
    DIRECTION INPUT ;
    USE SIGNAL ;
    PORT
      LAYER M5 ;
        RECT  107.184 64.716 107.208 64.8 ;
    END
  END q[295]
  PIN q[296]
    DIRECTION INPUT ;
    USE SIGNAL ;
    PORT
      LAYER M5 ;
        RECT  107.28 64.716 107.304 64.8 ;
    END
  END q[296]
  PIN q[297]
    DIRECTION INPUT ;
    USE SIGNAL ;
    PORT
      LAYER M5 ;
        RECT  107.376 64.716 107.4 64.8 ;
    END
  END q[297]
  PIN q[298]
    DIRECTION INPUT ;
    USE SIGNAL ;
    PORT
      LAYER M5 ;
        RECT  107.472 64.716 107.496 64.8 ;
    END
  END q[298]
  PIN q[299]
    DIRECTION INPUT ;
    USE SIGNAL ;
    PORT
      LAYER M5 ;
        RECT  107.568 64.716 107.592 64.8 ;
    END
  END q[299]
  PIN q[29]
    DIRECTION INPUT ;
    USE SIGNAL ;
    PORT
      LAYER M5 ;
        RECT  134.64 64.716 134.664 64.8 ;
    END
  END q[29]
  PIN q[2]
    DIRECTION INPUT ;
    USE SIGNAL ;
    PORT
      LAYER M5 ;
        RECT  132.048 64.716 132.072 64.8 ;
    END
  END q[2]
  PIN q[300]
    DIRECTION INPUT ;
    USE SIGNAL ;
    PORT
      LAYER M5 ;
        RECT  107.664 64.716 107.688 64.8 ;
    END
  END q[300]
  PIN q[301]
    DIRECTION INPUT ;
    USE SIGNAL ;
    PORT
      LAYER M5 ;
        RECT  107.76 64.716 107.784 64.8 ;
    END
  END q[301]
  PIN q[302]
    DIRECTION INPUT ;
    USE SIGNAL ;
    PORT
      LAYER M5 ;
        RECT  107.856 64.716 107.88 64.8 ;
    END
  END q[302]
  PIN q[303]
    DIRECTION INPUT ;
    USE SIGNAL ;
    PORT
      LAYER M5 ;
        RECT  107.952 64.716 107.976 64.8 ;
    END
  END q[303]
  PIN q[304]
    DIRECTION INPUT ;
    USE SIGNAL ;
    PORT
      LAYER M5 ;
        RECT  108.048 64.716 108.072 64.8 ;
    END
  END q[304]
  PIN q[305]
    DIRECTION INPUT ;
    USE SIGNAL ;
    PORT
      LAYER M5 ;
        RECT  108.144 64.716 108.168 64.8 ;
    END
  END q[305]
  PIN q[306]
    DIRECTION INPUT ;
    USE SIGNAL ;
    PORT
      LAYER M5 ;
        RECT  108.24 64.716 108.264 64.8 ;
    END
  END q[306]
  PIN q[307]
    DIRECTION INPUT ;
    USE SIGNAL ;
    PORT
      LAYER M5 ;
        RECT  108.336 64.716 108.36 64.8 ;
    END
  END q[307]
  PIN q[308]
    DIRECTION INPUT ;
    USE SIGNAL ;
    PORT
      LAYER M5 ;
        RECT  108.432 64.716 108.456 64.8 ;
    END
  END q[308]
  PIN q[309]
    DIRECTION INPUT ;
    USE SIGNAL ;
    PORT
      LAYER M5 ;
        RECT  108.528 64.716 108.552 64.8 ;
    END
  END q[309]
  PIN q[30]
    DIRECTION INPUT ;
    USE SIGNAL ;
    PORT
      LAYER M5 ;
        RECT  134.736 64.716 134.76 64.8 ;
    END
  END q[30]
  PIN q[310]
    DIRECTION INPUT ;
    USE SIGNAL ;
    PORT
      LAYER M5 ;
        RECT  108.624 64.716 108.648 64.8 ;
    END
  END q[310]
  PIN q[311]
    DIRECTION INPUT ;
    USE SIGNAL ;
    PORT
      LAYER M5 ;
        RECT  108.72 64.716 108.744 64.8 ;
    END
  END q[311]
  PIN q[312]
    DIRECTION INPUT ;
    USE SIGNAL ;
    PORT
      LAYER M5 ;
        RECT  108.816 64.716 108.84 64.8 ;
    END
  END q[312]
  PIN q[313]
    DIRECTION INPUT ;
    USE SIGNAL ;
    PORT
      LAYER M5 ;
        RECT  108.912 64.716 108.936 64.8 ;
    END
  END q[313]
  PIN q[314]
    DIRECTION INPUT ;
    USE SIGNAL ;
    PORT
      LAYER M5 ;
        RECT  109.008 64.716 109.032 64.8 ;
    END
  END q[314]
  PIN q[315]
    DIRECTION INPUT ;
    USE SIGNAL ;
    PORT
      LAYER M5 ;
        RECT  109.104 64.716 109.128 64.8 ;
    END
  END q[315]
  PIN q[316]
    DIRECTION INPUT ;
    USE SIGNAL ;
    PORT
      LAYER M5 ;
        RECT  109.2 64.716 109.224 64.8 ;
    END
  END q[316]
  PIN q[317]
    DIRECTION INPUT ;
    USE SIGNAL ;
    PORT
      LAYER M5 ;
        RECT  109.296 64.716 109.32 64.8 ;
    END
  END q[317]
  PIN q[318]
    DIRECTION INPUT ;
    USE SIGNAL ;
    PORT
      LAYER M5 ;
        RECT  109.392 64.716 109.416 64.8 ;
    END
  END q[318]
  PIN q[319]
    DIRECTION INPUT ;
    USE SIGNAL ;
    PORT
      LAYER M5 ;
        RECT  109.488 64.716 109.512 64.8 ;
    END
  END q[319]
  PIN q[31]
    DIRECTION INPUT ;
    USE SIGNAL ;
    PORT
      LAYER M5 ;
        RECT  134.832 64.716 134.856 64.8 ;
    END
  END q[31]
  PIN q[320]
    DIRECTION INPUT ;
    USE SIGNAL ;
    PORT
      LAYER M5 ;
        RECT  109.584 64.716 109.608 64.8 ;
    END
  END q[320]
  PIN q[321]
    DIRECTION INPUT ;
    USE SIGNAL ;
    PORT
      LAYER M5 ;
        RECT  109.68 64.716 109.704 64.8 ;
    END
  END q[321]
  PIN q[322]
    DIRECTION INPUT ;
    USE SIGNAL ;
    PORT
      LAYER M5 ;
        RECT  109.776 64.716 109.8 64.8 ;
    END
  END q[322]
  PIN q[323]
    DIRECTION INPUT ;
    USE SIGNAL ;
    PORT
      LAYER M5 ;
        RECT  109.872 64.716 109.896 64.8 ;
    END
  END q[323]
  PIN q[324]
    DIRECTION INPUT ;
    USE SIGNAL ;
    PORT
      LAYER M5 ;
        RECT  109.968 64.716 109.992 64.8 ;
    END
  END q[324]
  PIN q[325]
    DIRECTION INPUT ;
    USE SIGNAL ;
    PORT
      LAYER M5 ;
        RECT  110.064 64.716 110.088 64.8 ;
    END
  END q[325]
  PIN q[326]
    DIRECTION INPUT ;
    USE SIGNAL ;
    PORT
      LAYER M5 ;
        RECT  110.16 64.716 110.184 64.8 ;
    END
  END q[326]
  PIN q[327]
    DIRECTION INPUT ;
    USE SIGNAL ;
    PORT
      LAYER M5 ;
        RECT  110.256 64.716 110.28 64.8 ;
    END
  END q[327]
  PIN q[328]
    DIRECTION INPUT ;
    USE SIGNAL ;
    PORT
      LAYER M5 ;
        RECT  110.352 64.716 110.376 64.8 ;
    END
  END q[328]
  PIN q[329]
    DIRECTION INPUT ;
    USE SIGNAL ;
    PORT
      LAYER M5 ;
        RECT  110.448 64.716 110.472 64.8 ;
    END
  END q[329]
  PIN q[32]
    DIRECTION INPUT ;
    USE SIGNAL ;
    PORT
      LAYER M5 ;
        RECT  128.784 64.716 128.808 64.8 ;
    END
  END q[32]
  PIN q[330]
    DIRECTION INPUT ;
    USE SIGNAL ;
    PORT
      LAYER M5 ;
        RECT  110.544 64.716 110.568 64.8 ;
    END
  END q[330]
  PIN q[331]
    DIRECTION INPUT ;
    USE SIGNAL ;
    PORT
      LAYER M5 ;
        RECT  110.64 64.716 110.664 64.8 ;
    END
  END q[331]
  PIN q[332]
    DIRECTION INPUT ;
    USE SIGNAL ;
    PORT
      LAYER M5 ;
        RECT  110.736 64.716 110.76 64.8 ;
    END
  END q[332]
  PIN q[333]
    DIRECTION INPUT ;
    USE SIGNAL ;
    PORT
      LAYER M5 ;
        RECT  110.832 64.716 110.856 64.8 ;
    END
  END q[333]
  PIN q[334]
    DIRECTION INPUT ;
    USE SIGNAL ;
    PORT
      LAYER M5 ;
        RECT  110.928 64.716 110.952 64.8 ;
    END
  END q[334]
  PIN q[335]
    DIRECTION INPUT ;
    USE SIGNAL ;
    PORT
      LAYER M5 ;
        RECT  111.024 64.716 111.048 64.8 ;
    END
  END q[335]
  PIN q[336]
    DIRECTION INPUT ;
    USE SIGNAL ;
    PORT
      LAYER M5 ;
        RECT  111.12 64.716 111.144 64.8 ;
    END
  END q[336]
  PIN q[337]
    DIRECTION INPUT ;
    USE SIGNAL ;
    PORT
      LAYER M5 ;
        RECT  111.216 64.716 111.24 64.8 ;
    END
  END q[337]
  PIN q[338]
    DIRECTION INPUT ;
    USE SIGNAL ;
    PORT
      LAYER M5 ;
        RECT  111.312 64.716 111.336 64.8 ;
    END
  END q[338]
  PIN q[339]
    DIRECTION INPUT ;
    USE SIGNAL ;
    PORT
      LAYER M5 ;
        RECT  111.408 64.716 111.432 64.8 ;
    END
  END q[339]
  PIN q[33]
    DIRECTION INPUT ;
    USE SIGNAL ;
    PORT
      LAYER M5 ;
        RECT  128.88 64.716 128.904 64.8 ;
    END
  END q[33]
  PIN q[340]
    DIRECTION INPUT ;
    USE SIGNAL ;
    PORT
      LAYER M5 ;
        RECT  111.504 64.716 111.528 64.8 ;
    END
  END q[340]
  PIN q[341]
    DIRECTION INPUT ;
    USE SIGNAL ;
    PORT
      LAYER M5 ;
        RECT  111.6 64.716 111.624 64.8 ;
    END
  END q[341]
  PIN q[342]
    DIRECTION INPUT ;
    USE SIGNAL ;
    PORT
      LAYER M5 ;
        RECT  111.696 64.716 111.72 64.8 ;
    END
  END q[342]
  PIN q[343]
    DIRECTION INPUT ;
    USE SIGNAL ;
    PORT
      LAYER M5 ;
        RECT  111.792 64.716 111.816 64.8 ;
    END
  END q[343]
  PIN q[344]
    DIRECTION INPUT ;
    USE SIGNAL ;
    PORT
      LAYER M5 ;
        RECT  111.888 64.716 111.912 64.8 ;
    END
  END q[344]
  PIN q[345]
    DIRECTION INPUT ;
    USE SIGNAL ;
    PORT
      LAYER M5 ;
        RECT  111.984 64.716 112.008 64.8 ;
    END
  END q[345]
  PIN q[346]
    DIRECTION INPUT ;
    USE SIGNAL ;
    PORT
      LAYER M5 ;
        RECT  112.08 64.716 112.104 64.8 ;
    END
  END q[346]
  PIN q[347]
    DIRECTION INPUT ;
    USE SIGNAL ;
    PORT
      LAYER M5 ;
        RECT  112.176 64.716 112.2 64.8 ;
    END
  END q[347]
  PIN q[348]
    DIRECTION INPUT ;
    USE SIGNAL ;
    PORT
      LAYER M5 ;
        RECT  112.272 64.716 112.296 64.8 ;
    END
  END q[348]
  PIN q[349]
    DIRECTION INPUT ;
    USE SIGNAL ;
    PORT
      LAYER M5 ;
        RECT  112.368 64.716 112.392 64.8 ;
    END
  END q[349]
  PIN q[34]
    DIRECTION INPUT ;
    USE SIGNAL ;
    PORT
      LAYER M5 ;
        RECT  128.976 64.716 129 64.8 ;
    END
  END q[34]
  PIN q[350]
    DIRECTION INPUT ;
    USE SIGNAL ;
    PORT
      LAYER M5 ;
        RECT  112.464 64.716 112.488 64.8 ;
    END
  END q[350]
  PIN q[351]
    DIRECTION INPUT ;
    USE SIGNAL ;
    PORT
      LAYER M5 ;
        RECT  112.56 64.716 112.584 64.8 ;
    END
  END q[351]
  PIN q[352]
    DIRECTION INPUT ;
    USE SIGNAL ;
    PORT
      LAYER M5 ;
        RECT  116.496 64.716 116.52 64.8 ;
    END
  END q[352]
  PIN q[353]
    DIRECTION INPUT ;
    USE SIGNAL ;
    PORT
      LAYER M5 ;
        RECT  116.592 64.716 116.616 64.8 ;
    END
  END q[353]
  PIN q[354]
    DIRECTION INPUT ;
    USE SIGNAL ;
    PORT
      LAYER M5 ;
        RECT  116.688 64.716 116.712 64.8 ;
    END
  END q[354]
  PIN q[355]
    DIRECTION INPUT ;
    USE SIGNAL ;
    PORT
      LAYER M5 ;
        RECT  116.784 64.716 116.808 64.8 ;
    END
  END q[355]
  PIN q[356]
    DIRECTION INPUT ;
    USE SIGNAL ;
    PORT
      LAYER M5 ;
        RECT  116.88 64.716 116.904 64.8 ;
    END
  END q[356]
  PIN q[357]
    DIRECTION INPUT ;
    USE SIGNAL ;
    PORT
      LAYER M5 ;
        RECT  116.976 64.716 117 64.8 ;
    END
  END q[357]
  PIN q[358]
    DIRECTION INPUT ;
    USE SIGNAL ;
    PORT
      LAYER M5 ;
        RECT  117.072 64.716 117.096 64.8 ;
    END
  END q[358]
  PIN q[359]
    DIRECTION INPUT ;
    USE SIGNAL ;
    PORT
      LAYER M5 ;
        RECT  117.168 64.716 117.192 64.8 ;
    END
  END q[359]
  PIN q[35]
    DIRECTION INPUT ;
    USE SIGNAL ;
    PORT
      LAYER M5 ;
        RECT  129.072 64.716 129.096 64.8 ;
    END
  END q[35]
  PIN q[360]
    DIRECTION INPUT ;
    USE SIGNAL ;
    PORT
      LAYER M5 ;
        RECT  117.264 64.716 117.288 64.8 ;
    END
  END q[360]
  PIN q[361]
    DIRECTION INPUT ;
    USE SIGNAL ;
    PORT
      LAYER M5 ;
        RECT  117.36 64.716 117.384 64.8 ;
    END
  END q[361]
  PIN q[362]
    DIRECTION INPUT ;
    USE SIGNAL ;
    PORT
      LAYER M5 ;
        RECT  117.456 64.716 117.48 64.8 ;
    END
  END q[362]
  PIN q[363]
    DIRECTION INPUT ;
    USE SIGNAL ;
    PORT
      LAYER M5 ;
        RECT  117.552 64.716 117.576 64.8 ;
    END
  END q[363]
  PIN q[364]
    DIRECTION INPUT ;
    USE SIGNAL ;
    PORT
      LAYER M5 ;
        RECT  117.648 64.716 117.672 64.8 ;
    END
  END q[364]
  PIN q[365]
    DIRECTION INPUT ;
    USE SIGNAL ;
    PORT
      LAYER M5 ;
        RECT  117.744 64.716 117.768 64.8 ;
    END
  END q[365]
  PIN q[366]
    DIRECTION INPUT ;
    USE SIGNAL ;
    PORT
      LAYER M5 ;
        RECT  117.84 64.716 117.864 64.8 ;
    END
  END q[366]
  PIN q[367]
    DIRECTION INPUT ;
    USE SIGNAL ;
    PORT
      LAYER M5 ;
        RECT  117.936 64.716 117.96 64.8 ;
    END
  END q[367]
  PIN q[368]
    DIRECTION INPUT ;
    USE SIGNAL ;
    PORT
      LAYER M5 ;
        RECT  118.032 64.716 118.056 64.8 ;
    END
  END q[368]
  PIN q[369]
    DIRECTION INPUT ;
    USE SIGNAL ;
    PORT
      LAYER M5 ;
        RECT  118.128 64.716 118.152 64.8 ;
    END
  END q[369]
  PIN q[36]
    DIRECTION INPUT ;
    USE SIGNAL ;
    PORT
      LAYER M5 ;
        RECT  129.168 64.716 129.192 64.8 ;
    END
  END q[36]
  PIN q[370]
    DIRECTION INPUT ;
    USE SIGNAL ;
    PORT
      LAYER M5 ;
        RECT  118.224 64.716 118.248 64.8 ;
    END
  END q[370]
  PIN q[371]
    DIRECTION INPUT ;
    USE SIGNAL ;
    PORT
      LAYER M5 ;
        RECT  118.32 64.716 118.344 64.8 ;
    END
  END q[371]
  PIN q[372]
    DIRECTION INPUT ;
    USE SIGNAL ;
    PORT
      LAYER M5 ;
        RECT  118.416 64.716 118.44 64.8 ;
    END
  END q[372]
  PIN q[373]
    DIRECTION INPUT ;
    USE SIGNAL ;
    PORT
      LAYER M5 ;
        RECT  118.512 64.716 118.536 64.8 ;
    END
  END q[373]
  PIN q[374]
    DIRECTION INPUT ;
    USE SIGNAL ;
    PORT
      LAYER M5 ;
        RECT  118.608 64.716 118.632 64.8 ;
    END
  END q[374]
  PIN q[375]
    DIRECTION INPUT ;
    USE SIGNAL ;
    PORT
      LAYER M5 ;
        RECT  118.704 64.716 118.728 64.8 ;
    END
  END q[375]
  PIN q[376]
    DIRECTION INPUT ;
    USE SIGNAL ;
    PORT
      LAYER M5 ;
        RECT  118.8 64.716 118.824 64.8 ;
    END
  END q[376]
  PIN q[377]
    DIRECTION INPUT ;
    USE SIGNAL ;
    PORT
      LAYER M5 ;
        RECT  118.896 64.716 118.92 64.8 ;
    END
  END q[377]
  PIN q[378]
    DIRECTION INPUT ;
    USE SIGNAL ;
    PORT
      LAYER M5 ;
        RECT  118.992 64.716 119.016 64.8 ;
    END
  END q[378]
  PIN q[379]
    DIRECTION INPUT ;
    USE SIGNAL ;
    PORT
      LAYER M5 ;
        RECT  119.088 64.716 119.112 64.8 ;
    END
  END q[379]
  PIN q[37]
    DIRECTION INPUT ;
    USE SIGNAL ;
    PORT
      LAYER M5 ;
        RECT  129.264 64.716 129.288 64.8 ;
    END
  END q[37]
  PIN q[380]
    DIRECTION INPUT ;
    USE SIGNAL ;
    PORT
      LAYER M5 ;
        RECT  119.184 64.716 119.208 64.8 ;
    END
  END q[380]
  PIN q[381]
    DIRECTION INPUT ;
    USE SIGNAL ;
    PORT
      LAYER M5 ;
        RECT  119.28 64.716 119.304 64.8 ;
    END
  END q[381]
  PIN q[382]
    DIRECTION INPUT ;
    USE SIGNAL ;
    PORT
      LAYER M5 ;
        RECT  119.376 64.716 119.4 64.8 ;
    END
  END q[382]
  PIN q[383]
    DIRECTION INPUT ;
    USE SIGNAL ;
    PORT
      LAYER M5 ;
        RECT  119.472 64.716 119.496 64.8 ;
    END
  END q[383]
  PIN q[384]
    DIRECTION INPUT ;
    USE SIGNAL ;
    PORT
      LAYER M5 ;
        RECT  90.384 64.716 90.408 64.8 ;
    END
  END q[384]
  PIN q[385]
    DIRECTION INPUT ;
    USE SIGNAL ;
    PORT
      LAYER M5 ;
        RECT  90.48 64.716 90.504 64.8 ;
    END
  END q[385]
  PIN q[386]
    DIRECTION INPUT ;
    USE SIGNAL ;
    PORT
      LAYER M5 ;
        RECT  90.576 64.716 90.6 64.8 ;
    END
  END q[386]
  PIN q[387]
    DIRECTION INPUT ;
    USE SIGNAL ;
    PORT
      LAYER M5 ;
        RECT  90.672 64.716 90.696 64.8 ;
    END
  END q[387]
  PIN q[388]
    DIRECTION INPUT ;
    USE SIGNAL ;
    PORT
      LAYER M5 ;
        RECT  90.768 64.716 90.792 64.8 ;
    END
  END q[388]
  PIN q[389]
    DIRECTION INPUT ;
    USE SIGNAL ;
    PORT
      LAYER M5 ;
        RECT  90.864 64.716 90.888 64.8 ;
    END
  END q[389]
  PIN q[38]
    DIRECTION INPUT ;
    USE SIGNAL ;
    PORT
      LAYER M5 ;
        RECT  129.36 64.716 129.384 64.8 ;
    END
  END q[38]
  PIN q[390]
    DIRECTION INPUT ;
    USE SIGNAL ;
    PORT
      LAYER M5 ;
        RECT  90.96 64.716 90.984 64.8 ;
    END
  END q[390]
  PIN q[391]
    DIRECTION INPUT ;
    USE SIGNAL ;
    PORT
      LAYER M5 ;
        RECT  91.056 64.716 91.08 64.8 ;
    END
  END q[391]
  PIN q[392]
    DIRECTION INPUT ;
    USE SIGNAL ;
    PORT
      LAYER M5 ;
        RECT  91.152 64.716 91.176 64.8 ;
    END
  END q[392]
  PIN q[393]
    DIRECTION INPUT ;
    USE SIGNAL ;
    PORT
      LAYER M5 ;
        RECT  91.248 64.716 91.272 64.8 ;
    END
  END q[393]
  PIN q[394]
    DIRECTION INPUT ;
    USE SIGNAL ;
    PORT
      LAYER M5 ;
        RECT  91.344 64.716 91.368 64.8 ;
    END
  END q[394]
  PIN q[395]
    DIRECTION INPUT ;
    USE SIGNAL ;
    PORT
      LAYER M5 ;
        RECT  91.44 64.716 91.464 64.8 ;
    END
  END q[395]
  PIN q[396]
    DIRECTION INPUT ;
    USE SIGNAL ;
    PORT
      LAYER M5 ;
        RECT  91.536 64.716 91.56 64.8 ;
    END
  END q[396]
  PIN q[397]
    DIRECTION INPUT ;
    USE SIGNAL ;
    PORT
      LAYER M5 ;
        RECT  91.632 64.716 91.656 64.8 ;
    END
  END q[397]
  PIN q[398]
    DIRECTION INPUT ;
    USE SIGNAL ;
    PORT
      LAYER M5 ;
        RECT  91.728 64.716 91.752 64.8 ;
    END
  END q[398]
  PIN q[399]
    DIRECTION INPUT ;
    USE SIGNAL ;
    PORT
      LAYER M5 ;
        RECT  91.824 64.716 91.848 64.8 ;
    END
  END q[399]
  PIN q[39]
    DIRECTION INPUT ;
    USE SIGNAL ;
    PORT
      LAYER M5 ;
        RECT  129.456 64.716 129.48 64.8 ;
    END
  END q[39]
  PIN q[3]
    DIRECTION INPUT ;
    USE SIGNAL ;
    PORT
      LAYER M5 ;
        RECT  132.144 64.716 132.168 64.8 ;
    END
  END q[3]
  PIN q[400]
    DIRECTION INPUT ;
    USE SIGNAL ;
    PORT
      LAYER M5 ;
        RECT  91.92 64.716 91.944 64.8 ;
    END
  END q[400]
  PIN q[401]
    DIRECTION INPUT ;
    USE SIGNAL ;
    PORT
      LAYER M5 ;
        RECT  92.016 64.716 92.04 64.8 ;
    END
  END q[401]
  PIN q[402]
    DIRECTION INPUT ;
    USE SIGNAL ;
    PORT
      LAYER M5 ;
        RECT  92.112 64.716 92.136 64.8 ;
    END
  END q[402]
  PIN q[403]
    DIRECTION INPUT ;
    USE SIGNAL ;
    PORT
      LAYER M5 ;
        RECT  92.208 64.716 92.232 64.8 ;
    END
  END q[403]
  PIN q[404]
    DIRECTION INPUT ;
    USE SIGNAL ;
    PORT
      LAYER M5 ;
        RECT  92.304 64.716 92.328 64.8 ;
    END
  END q[404]
  PIN q[405]
    DIRECTION INPUT ;
    USE SIGNAL ;
    PORT
      LAYER M5 ;
        RECT  92.4 64.716 92.424 64.8 ;
    END
  END q[405]
  PIN q[406]
    DIRECTION INPUT ;
    USE SIGNAL ;
    PORT
      LAYER M5 ;
        RECT  92.496 64.716 92.52 64.8 ;
    END
  END q[406]
  PIN q[407]
    DIRECTION INPUT ;
    USE SIGNAL ;
    PORT
      LAYER M5 ;
        RECT  92.592 64.716 92.616 64.8 ;
    END
  END q[407]
  PIN q[408]
    DIRECTION INPUT ;
    USE SIGNAL ;
    PORT
      LAYER M5 ;
        RECT  92.688 64.716 92.712 64.8 ;
    END
  END q[408]
  PIN q[409]
    DIRECTION INPUT ;
    USE SIGNAL ;
    PORT
      LAYER M5 ;
        RECT  92.784 64.716 92.808 64.8 ;
    END
  END q[409]
  PIN q[40]
    DIRECTION INPUT ;
    USE SIGNAL ;
    PORT
      LAYER M5 ;
        RECT  129.552 64.716 129.576 64.8 ;
    END
  END q[40]
  PIN q[410]
    DIRECTION INPUT ;
    USE SIGNAL ;
    PORT
      LAYER M5 ;
        RECT  92.88 64.716 92.904 64.8 ;
    END
  END q[410]
  PIN q[411]
    DIRECTION INPUT ;
    USE SIGNAL ;
    PORT
      LAYER M5 ;
        RECT  92.976 64.716 93 64.8 ;
    END
  END q[411]
  PIN q[412]
    DIRECTION INPUT ;
    USE SIGNAL ;
    PORT
      LAYER M5 ;
        RECT  93.072 64.716 93.096 64.8 ;
    END
  END q[412]
  PIN q[413]
    DIRECTION INPUT ;
    USE SIGNAL ;
    PORT
      LAYER M5 ;
        RECT  93.168 64.716 93.192 64.8 ;
    END
  END q[413]
  PIN q[414]
    DIRECTION INPUT ;
    USE SIGNAL ;
    PORT
      LAYER M5 ;
        RECT  93.264 64.716 93.288 64.8 ;
    END
  END q[414]
  PIN q[415]
    DIRECTION INPUT ;
    USE SIGNAL ;
    PORT
      LAYER M5 ;
        RECT  93.36 64.716 93.384 64.8 ;
    END
  END q[415]
  PIN q[416]
    DIRECTION INPUT ;
    USE SIGNAL ;
    PORT
      LAYER M5 ;
        RECT  93.456 64.716 93.48 64.8 ;
    END
  END q[416]
  PIN q[417]
    DIRECTION INPUT ;
    USE SIGNAL ;
    PORT
      LAYER M5 ;
        RECT  93.552 64.716 93.576 64.8 ;
    END
  END q[417]
  PIN q[418]
    DIRECTION INPUT ;
    USE SIGNAL ;
    PORT
      LAYER M5 ;
        RECT  93.648 64.716 93.672 64.8 ;
    END
  END q[418]
  PIN q[419]
    DIRECTION INPUT ;
    USE SIGNAL ;
    PORT
      LAYER M5 ;
        RECT  93.744 64.716 93.768 64.8 ;
    END
  END q[419]
  PIN q[41]
    DIRECTION INPUT ;
    USE SIGNAL ;
    PORT
      LAYER M5 ;
        RECT  129.648 64.716 129.672 64.8 ;
    END
  END q[41]
  PIN q[420]
    DIRECTION INPUT ;
    USE SIGNAL ;
    PORT
      LAYER M5 ;
        RECT  93.84 64.716 93.864 64.8 ;
    END
  END q[420]
  PIN q[421]
    DIRECTION INPUT ;
    USE SIGNAL ;
    PORT
      LAYER M5 ;
        RECT  93.936 64.716 93.96 64.8 ;
    END
  END q[421]
  PIN q[422]
    DIRECTION INPUT ;
    USE SIGNAL ;
    PORT
      LAYER M5 ;
        RECT  94.032 64.716 94.056 64.8 ;
    END
  END q[422]
  PIN q[423]
    DIRECTION INPUT ;
    USE SIGNAL ;
    PORT
      LAYER M5 ;
        RECT  94.128 64.716 94.152 64.8 ;
    END
  END q[423]
  PIN q[424]
    DIRECTION INPUT ;
    USE SIGNAL ;
    PORT
      LAYER M5 ;
        RECT  94.224 64.716 94.248 64.8 ;
    END
  END q[424]
  PIN q[425]
    DIRECTION INPUT ;
    USE SIGNAL ;
    PORT
      LAYER M5 ;
        RECT  94.32 64.716 94.344 64.8 ;
    END
  END q[425]
  PIN q[426]
    DIRECTION INPUT ;
    USE SIGNAL ;
    PORT
      LAYER M5 ;
        RECT  94.416 64.716 94.44 64.8 ;
    END
  END q[426]
  PIN q[427]
    DIRECTION INPUT ;
    USE SIGNAL ;
    PORT
      LAYER M5 ;
        RECT  94.512 64.716 94.536 64.8 ;
    END
  END q[427]
  PIN q[428]
    DIRECTION INPUT ;
    USE SIGNAL ;
    PORT
      LAYER M5 ;
        RECT  94.608 64.716 94.632 64.8 ;
    END
  END q[428]
  PIN q[429]
    DIRECTION INPUT ;
    USE SIGNAL ;
    PORT
      LAYER M5 ;
        RECT  94.704 64.716 94.728 64.8 ;
    END
  END q[429]
  PIN q[42]
    DIRECTION INPUT ;
    USE SIGNAL ;
    PORT
      LAYER M5 ;
        RECT  129.744 64.716 129.768 64.8 ;
    END
  END q[42]
  PIN q[430]
    DIRECTION INPUT ;
    USE SIGNAL ;
    PORT
      LAYER M5 ;
        RECT  94.8 64.716 94.824 64.8 ;
    END
  END q[430]
  PIN q[431]
    DIRECTION INPUT ;
    USE SIGNAL ;
    PORT
      LAYER M5 ;
        RECT  94.896 64.716 94.92 64.8 ;
    END
  END q[431]
  PIN q[432]
    DIRECTION INPUT ;
    USE SIGNAL ;
    PORT
      LAYER M5 ;
        RECT  94.992 64.716 95.016 64.8 ;
    END
  END q[432]
  PIN q[433]
    DIRECTION INPUT ;
    USE SIGNAL ;
    PORT
      LAYER M5 ;
        RECT  95.088 64.716 95.112 64.8 ;
    END
  END q[433]
  PIN q[434]
    DIRECTION INPUT ;
    USE SIGNAL ;
    PORT
      LAYER M5 ;
        RECT  95.184 64.716 95.208 64.8 ;
    END
  END q[434]
  PIN q[435]
    DIRECTION INPUT ;
    USE SIGNAL ;
    PORT
      LAYER M5 ;
        RECT  95.28 64.716 95.304 64.8 ;
    END
  END q[435]
  PIN q[436]
    DIRECTION INPUT ;
    USE SIGNAL ;
    PORT
      LAYER M5 ;
        RECT  95.376 64.716 95.4 64.8 ;
    END
  END q[436]
  PIN q[437]
    DIRECTION INPUT ;
    USE SIGNAL ;
    PORT
      LAYER M5 ;
        RECT  95.472 64.716 95.496 64.8 ;
    END
  END q[437]
  PIN q[438]
    DIRECTION INPUT ;
    USE SIGNAL ;
    PORT
      LAYER M5 ;
        RECT  95.568 64.716 95.592 64.8 ;
    END
  END q[438]
  PIN q[439]
    DIRECTION INPUT ;
    USE SIGNAL ;
    PORT
      LAYER M5 ;
        RECT  95.664 64.716 95.688 64.8 ;
    END
  END q[439]
  PIN q[43]
    DIRECTION INPUT ;
    USE SIGNAL ;
    PORT
      LAYER M5 ;
        RECT  129.84 64.716 129.864 64.8 ;
    END
  END q[43]
  PIN q[440]
    DIRECTION INPUT ;
    USE SIGNAL ;
    PORT
      LAYER M5 ;
        RECT  95.76 64.716 95.784 64.8 ;
    END
  END q[440]
  PIN q[441]
    DIRECTION INPUT ;
    USE SIGNAL ;
    PORT
      LAYER M5 ;
        RECT  95.856 64.716 95.88 64.8 ;
    END
  END q[441]
  PIN q[442]
    DIRECTION INPUT ;
    USE SIGNAL ;
    PORT
      LAYER M5 ;
        RECT  95.952 64.716 95.976 64.8 ;
    END
  END q[442]
  PIN q[443]
    DIRECTION INPUT ;
    USE SIGNAL ;
    PORT
      LAYER M5 ;
        RECT  96.048 64.716 96.072 64.8 ;
    END
  END q[443]
  PIN q[444]
    DIRECTION INPUT ;
    USE SIGNAL ;
    PORT
      LAYER M5 ;
        RECT  96.144 64.716 96.168 64.8 ;
    END
  END q[444]
  PIN q[445]
    DIRECTION INPUT ;
    USE SIGNAL ;
    PORT
      LAYER M5 ;
        RECT  96.24 64.716 96.264 64.8 ;
    END
  END q[445]
  PIN q[446]
    DIRECTION INPUT ;
    USE SIGNAL ;
    PORT
      LAYER M5 ;
        RECT  96.336 64.716 96.36 64.8 ;
    END
  END q[446]
  PIN q[447]
    DIRECTION INPUT ;
    USE SIGNAL ;
    PORT
      LAYER M5 ;
        RECT  96.432 64.716 96.456 64.8 ;
    END
  END q[447]
  PIN q[448]
    DIRECTION INPUT ;
    USE SIGNAL ;
    PORT
      LAYER M5 ;
        RECT  138.768 64.716 138.792 64.8 ;
    END
  END q[448]
  PIN q[449]
    DIRECTION INPUT ;
    USE SIGNAL ;
    PORT
      LAYER M5 ;
        RECT  138.864 64.716 138.888 64.8 ;
    END
  END q[449]
  PIN q[44]
    DIRECTION INPUT ;
    USE SIGNAL ;
    PORT
      LAYER M5 ;
        RECT  129.936 64.716 129.96 64.8 ;
    END
  END q[44]
  PIN q[450]
    DIRECTION INPUT ;
    USE SIGNAL ;
    PORT
      LAYER M5 ;
        RECT  138.96 64.716 138.984 64.8 ;
    END
  END q[450]
  PIN q[451]
    DIRECTION INPUT ;
    USE SIGNAL ;
    PORT
      LAYER M5 ;
        RECT  139.056 64.716 139.08 64.8 ;
    END
  END q[451]
  PIN q[452]
    DIRECTION INPUT ;
    USE SIGNAL ;
    PORT
      LAYER M5 ;
        RECT  139.152 64.716 139.176 64.8 ;
    END
  END q[452]
  PIN q[453]
    DIRECTION INPUT ;
    USE SIGNAL ;
    PORT
      LAYER M5 ;
        RECT  139.248 64.716 139.272 64.8 ;
    END
  END q[453]
  PIN q[454]
    DIRECTION INPUT ;
    USE SIGNAL ;
    PORT
      LAYER M5 ;
        RECT  139.344 64.716 139.368 64.8 ;
    END
  END q[454]
  PIN q[455]
    DIRECTION INPUT ;
    USE SIGNAL ;
    PORT
      LAYER M5 ;
        RECT  139.44 64.716 139.464 64.8 ;
    END
  END q[455]
  PIN q[456]
    DIRECTION INPUT ;
    USE SIGNAL ;
    PORT
      LAYER M5 ;
        RECT  139.536 64.716 139.56 64.8 ;
    END
  END q[456]
  PIN q[457]
    DIRECTION INPUT ;
    USE SIGNAL ;
    PORT
      LAYER M5 ;
        RECT  139.632 64.716 139.656 64.8 ;
    END
  END q[457]
  PIN q[458]
    DIRECTION INPUT ;
    USE SIGNAL ;
    PORT
      LAYER M5 ;
        RECT  139.728 64.716 139.752 64.8 ;
    END
  END q[458]
  PIN q[459]
    DIRECTION INPUT ;
    USE SIGNAL ;
    PORT
      LAYER M5 ;
        RECT  139.824 64.716 139.848 64.8 ;
    END
  END q[459]
  PIN q[45]
    DIRECTION INPUT ;
    USE SIGNAL ;
    PORT
      LAYER M5 ;
        RECT  130.032 64.716 130.056 64.8 ;
    END
  END q[45]
  PIN q[460]
    DIRECTION INPUT ;
    USE SIGNAL ;
    PORT
      LAYER M5 ;
        RECT  139.92 64.716 139.944 64.8 ;
    END
  END q[460]
  PIN q[461]
    DIRECTION INPUT ;
    USE SIGNAL ;
    PORT
      LAYER M5 ;
        RECT  140.016 64.716 140.04 64.8 ;
    END
  END q[461]
  PIN q[462]
    DIRECTION INPUT ;
    USE SIGNAL ;
    PORT
      LAYER M5 ;
        RECT  140.112 64.716 140.136 64.8 ;
    END
  END q[462]
  PIN q[463]
    DIRECTION INPUT ;
    USE SIGNAL ;
    PORT
      LAYER M5 ;
        RECT  140.208 64.716 140.232 64.8 ;
    END
  END q[463]
  PIN q[464]
    DIRECTION INPUT ;
    USE SIGNAL ;
    PORT
      LAYER M5 ;
        RECT  140.304 64.716 140.328 64.8 ;
    END
  END q[464]
  PIN q[465]
    DIRECTION INPUT ;
    USE SIGNAL ;
    PORT
      LAYER M5 ;
        RECT  140.4 64.716 140.424 64.8 ;
    END
  END q[465]
  PIN q[466]
    DIRECTION INPUT ;
    USE SIGNAL ;
    PORT
      LAYER M5 ;
        RECT  140.496 64.716 140.52 64.8 ;
    END
  END q[466]
  PIN q[467]
    DIRECTION INPUT ;
    USE SIGNAL ;
    PORT
      LAYER M5 ;
        RECT  140.592 64.716 140.616 64.8 ;
    END
  END q[467]
  PIN q[468]
    DIRECTION INPUT ;
    USE SIGNAL ;
    PORT
      LAYER M5 ;
        RECT  140.688 64.716 140.712 64.8 ;
    END
  END q[468]
  PIN q[469]
    DIRECTION INPUT ;
    USE SIGNAL ;
    PORT
      LAYER M5 ;
        RECT  140.784 64.716 140.808 64.8 ;
    END
  END q[469]
  PIN q[46]
    DIRECTION INPUT ;
    USE SIGNAL ;
    PORT
      LAYER M5 ;
        RECT  130.128 64.716 130.152 64.8 ;
    END
  END q[46]
  PIN q[470]
    DIRECTION INPUT ;
    USE SIGNAL ;
    PORT
      LAYER M5 ;
        RECT  140.88 64.716 140.904 64.8 ;
    END
  END q[470]
  PIN q[471]
    DIRECTION INPUT ;
    USE SIGNAL ;
    PORT
      LAYER M5 ;
        RECT  140.976 64.716 141 64.8 ;
    END
  END q[471]
  PIN q[472]
    DIRECTION INPUT ;
    USE SIGNAL ;
    PORT
      LAYER M5 ;
        RECT  141.072 64.716 141.096 64.8 ;
    END
  END q[472]
  PIN q[473]
    DIRECTION INPUT ;
    USE SIGNAL ;
    PORT
      LAYER M5 ;
        RECT  141.168 64.716 141.192 64.8 ;
    END
  END q[473]
  PIN q[474]
    DIRECTION INPUT ;
    USE SIGNAL ;
    PORT
      LAYER M5 ;
        RECT  141.264 64.716 141.288 64.8 ;
    END
  END q[474]
  PIN q[475]
    DIRECTION INPUT ;
    USE SIGNAL ;
    PORT
      LAYER M5 ;
        RECT  141.36 64.716 141.384 64.8 ;
    END
  END q[475]
  PIN q[476]
    DIRECTION INPUT ;
    USE SIGNAL ;
    PORT
      LAYER M5 ;
        RECT  141.456 64.716 141.48 64.8 ;
    END
  END q[476]
  PIN q[477]
    DIRECTION INPUT ;
    USE SIGNAL ;
    PORT
      LAYER M5 ;
        RECT  141.552 64.716 141.576 64.8 ;
    END
  END q[477]
  PIN q[478]
    DIRECTION INPUT ;
    USE SIGNAL ;
    PORT
      LAYER M5 ;
        RECT  141.648 64.716 141.672 64.8 ;
    END
  END q[478]
  PIN q[479]
    DIRECTION INPUT ;
    USE SIGNAL ;
    PORT
      LAYER M5 ;
        RECT  141.744 64.716 141.768 64.8 ;
    END
  END q[479]
  PIN q[47]
    DIRECTION INPUT ;
    USE SIGNAL ;
    PORT
      LAYER M5 ;
        RECT  130.224 64.716 130.248 64.8 ;
    END
  END q[47]
  PIN q[480]
    DIRECTION INPUT ;
    USE SIGNAL ;
    PORT
      LAYER M5 ;
        RECT  135.696 64.716 135.72 64.8 ;
    END
  END q[480]
  PIN q[481]
    DIRECTION INPUT ;
    USE SIGNAL ;
    PORT
      LAYER M5 ;
        RECT  135.792 64.716 135.816 64.8 ;
    END
  END q[481]
  PIN q[482]
    DIRECTION INPUT ;
    USE SIGNAL ;
    PORT
      LAYER M5 ;
        RECT  135.888 64.716 135.912 64.8 ;
    END
  END q[482]
  PIN q[483]
    DIRECTION INPUT ;
    USE SIGNAL ;
    PORT
      LAYER M5 ;
        RECT  135.984 64.716 136.008 64.8 ;
    END
  END q[483]
  PIN q[484]
    DIRECTION INPUT ;
    USE SIGNAL ;
    PORT
      LAYER M5 ;
        RECT  136.08 64.716 136.104 64.8 ;
    END
  END q[484]
  PIN q[485]
    DIRECTION INPUT ;
    USE SIGNAL ;
    PORT
      LAYER M5 ;
        RECT  136.176 64.716 136.2 64.8 ;
    END
  END q[485]
  PIN q[486]
    DIRECTION INPUT ;
    USE SIGNAL ;
    PORT
      LAYER M5 ;
        RECT  136.272 64.716 136.296 64.8 ;
    END
  END q[486]
  PIN q[487]
    DIRECTION INPUT ;
    USE SIGNAL ;
    PORT
      LAYER M5 ;
        RECT  136.368 64.716 136.392 64.8 ;
    END
  END q[487]
  PIN q[488]
    DIRECTION INPUT ;
    USE SIGNAL ;
    PORT
      LAYER M5 ;
        RECT  136.464 64.716 136.488 64.8 ;
    END
  END q[488]
  PIN q[489]
    DIRECTION INPUT ;
    USE SIGNAL ;
    PORT
      LAYER M5 ;
        RECT  136.56 64.716 136.584 64.8 ;
    END
  END q[489]
  PIN q[48]
    DIRECTION INPUT ;
    USE SIGNAL ;
    PORT
      LAYER M5 ;
        RECT  130.32 64.716 130.344 64.8 ;
    END
  END q[48]
  PIN q[490]
    DIRECTION INPUT ;
    USE SIGNAL ;
    PORT
      LAYER M5 ;
        RECT  136.656 64.716 136.68 64.8 ;
    END
  END q[490]
  PIN q[491]
    DIRECTION INPUT ;
    USE SIGNAL ;
    PORT
      LAYER M5 ;
        RECT  136.752 64.716 136.776 64.8 ;
    END
  END q[491]
  PIN q[492]
    DIRECTION INPUT ;
    USE SIGNAL ;
    PORT
      LAYER M5 ;
        RECT  136.848 64.716 136.872 64.8 ;
    END
  END q[492]
  PIN q[493]
    DIRECTION INPUT ;
    USE SIGNAL ;
    PORT
      LAYER M5 ;
        RECT  136.944 64.716 136.968 64.8 ;
    END
  END q[493]
  PIN q[494]
    DIRECTION INPUT ;
    USE SIGNAL ;
    PORT
      LAYER M5 ;
        RECT  137.04 64.716 137.064 64.8 ;
    END
  END q[494]
  PIN q[495]
    DIRECTION INPUT ;
    USE SIGNAL ;
    PORT
      LAYER M5 ;
        RECT  137.136 64.716 137.16 64.8 ;
    END
  END q[495]
  PIN q[496]
    DIRECTION INPUT ;
    USE SIGNAL ;
    PORT
      LAYER M5 ;
        RECT  137.232 64.716 137.256 64.8 ;
    END
  END q[496]
  PIN q[497]
    DIRECTION INPUT ;
    USE SIGNAL ;
    PORT
      LAYER M5 ;
        RECT  137.328 64.716 137.352 64.8 ;
    END
  END q[497]
  PIN q[498]
    DIRECTION INPUT ;
    USE SIGNAL ;
    PORT
      LAYER M5 ;
        RECT  137.424 64.716 137.448 64.8 ;
    END
  END q[498]
  PIN q[499]
    DIRECTION INPUT ;
    USE SIGNAL ;
    PORT
      LAYER M5 ;
        RECT  137.52 64.716 137.544 64.8 ;
    END
  END q[499]
  PIN q[49]
    DIRECTION INPUT ;
    USE SIGNAL ;
    PORT
      LAYER M5 ;
        RECT  130.416 64.716 130.44 64.8 ;
    END
  END q[49]
  PIN q[4]
    DIRECTION INPUT ;
    USE SIGNAL ;
    PORT
      LAYER M5 ;
        RECT  132.24 64.716 132.264 64.8 ;
    END
  END q[4]
  PIN q[500]
    DIRECTION INPUT ;
    USE SIGNAL ;
    PORT
      LAYER M5 ;
        RECT  137.616 64.716 137.64 64.8 ;
    END
  END q[500]
  PIN q[501]
    DIRECTION INPUT ;
    USE SIGNAL ;
    PORT
      LAYER M5 ;
        RECT  137.712 64.716 137.736 64.8 ;
    END
  END q[501]
  PIN q[502]
    DIRECTION INPUT ;
    USE SIGNAL ;
    PORT
      LAYER M5 ;
        RECT  137.808 64.716 137.832 64.8 ;
    END
  END q[502]
  PIN q[503]
    DIRECTION INPUT ;
    USE SIGNAL ;
    PORT
      LAYER M5 ;
        RECT  137.904 64.716 137.928 64.8 ;
    END
  END q[503]
  PIN q[504]
    DIRECTION INPUT ;
    USE SIGNAL ;
    PORT
      LAYER M5 ;
        RECT  138 64.716 138.024 64.8 ;
    END
  END q[504]
  PIN q[505]
    DIRECTION INPUT ;
    USE SIGNAL ;
    PORT
      LAYER M5 ;
        RECT  138.096 64.716 138.12 64.8 ;
    END
  END q[505]
  PIN q[506]
    DIRECTION INPUT ;
    USE SIGNAL ;
    PORT
      LAYER M5 ;
        RECT  138.192 64.716 138.216 64.8 ;
    END
  END q[506]
  PIN q[507]
    DIRECTION INPUT ;
    USE SIGNAL ;
    PORT
      LAYER M5 ;
        RECT  138.288 64.716 138.312 64.8 ;
    END
  END q[507]
  PIN q[508]
    DIRECTION INPUT ;
    USE SIGNAL ;
    PORT
      LAYER M5 ;
        RECT  138.384 64.716 138.408 64.8 ;
    END
  END q[508]
  PIN q[509]
    DIRECTION INPUT ;
    USE SIGNAL ;
    PORT
      LAYER M5 ;
        RECT  138.48 64.716 138.504 64.8 ;
    END
  END q[509]
  PIN q[50]
    DIRECTION INPUT ;
    USE SIGNAL ;
    PORT
      LAYER M5 ;
        RECT  130.512 64.716 130.536 64.8 ;
    END
  END q[50]
  PIN q[510]
    DIRECTION INPUT ;
    USE SIGNAL ;
    PORT
      LAYER M5 ;
        RECT  138.576 64.716 138.6 64.8 ;
    END
  END q[510]
  PIN q[511]
    DIRECTION INPUT ;
    USE SIGNAL ;
    PORT
      LAYER M5 ;
        RECT  138.672 64.716 138.696 64.8 ;
    END
  END q[511]
  PIN q[512]
    DIRECTION INPUT ;
    USE SIGNAL ;
    PORT
      LAYER M5 ;
        RECT  116.208 64.716 116.232 64.8 ;
    END
  END q[512]
  PIN q[513]
    DIRECTION INPUT ;
    USE SIGNAL ;
    PORT
      LAYER M5 ;
        RECT  116.304 64.716 116.328 64.8 ;
    END
  END q[513]
  PIN q[514]
    DIRECTION INPUT ;
    USE SIGNAL ;
    PORT
      LAYER M5 ;
        RECT  116.4 64.716 116.424 64.8 ;
    END
  END q[514]
  PIN q[51]
    DIRECTION INPUT ;
    USE SIGNAL ;
    PORT
      LAYER M5 ;
        RECT  130.608 64.716 130.632 64.8 ;
    END
  END q[51]
  PIN q[52]
    DIRECTION INPUT ;
    USE SIGNAL ;
    PORT
      LAYER M5 ;
        RECT  130.704 64.716 130.728 64.8 ;
    END
  END q[52]
  PIN q[53]
    DIRECTION INPUT ;
    USE SIGNAL ;
    PORT
      LAYER M5 ;
        RECT  130.8 64.716 130.824 64.8 ;
    END
  END q[53]
  PIN q[54]
    DIRECTION INPUT ;
    USE SIGNAL ;
    PORT
      LAYER M5 ;
        RECT  130.896 64.716 130.92 64.8 ;
    END
  END q[54]
  PIN q[55]
    DIRECTION INPUT ;
    USE SIGNAL ;
    PORT
      LAYER M5 ;
        RECT  130.992 64.716 131.016 64.8 ;
    END
  END q[55]
  PIN q[56]
    DIRECTION INPUT ;
    USE SIGNAL ;
    PORT
      LAYER M5 ;
        RECT  131.088 64.716 131.112 64.8 ;
    END
  END q[56]
  PIN q[57]
    DIRECTION INPUT ;
    USE SIGNAL ;
    PORT
      LAYER M5 ;
        RECT  131.184 64.716 131.208 64.8 ;
    END
  END q[57]
  PIN q[58]
    DIRECTION INPUT ;
    USE SIGNAL ;
    PORT
      LAYER M5 ;
        RECT  131.28 64.716 131.304 64.8 ;
    END
  END q[58]
  PIN q[59]
    DIRECTION INPUT ;
    USE SIGNAL ;
    PORT
      LAYER M5 ;
        RECT  131.376 64.716 131.4 64.8 ;
    END
  END q[59]
  PIN q[5]
    DIRECTION INPUT ;
    USE SIGNAL ;
    PORT
      LAYER M5 ;
        RECT  132.336 64.716 132.36 64.8 ;
    END
  END q[5]
  PIN q[60]
    DIRECTION INPUT ;
    USE SIGNAL ;
    PORT
      LAYER M5 ;
        RECT  131.472 64.716 131.496 64.8 ;
    END
  END q[60]
  PIN q[61]
    DIRECTION INPUT ;
    USE SIGNAL ;
    PORT
      LAYER M5 ;
        RECT  131.568 64.716 131.592 64.8 ;
    END
  END q[61]
  PIN q[62]
    DIRECTION INPUT ;
    USE SIGNAL ;
    PORT
      LAYER M5 ;
        RECT  131.664 64.716 131.688 64.8 ;
    END
  END q[62]
  PIN q[63]
    DIRECTION INPUT ;
    USE SIGNAL ;
    PORT
      LAYER M5 ;
        RECT  131.76 64.716 131.784 64.8 ;
    END
  END q[63]
  PIN q[64]
    DIRECTION INPUT ;
    USE SIGNAL ;
    PORT
      LAYER M5 ;
        RECT  125.712 64.716 125.736 64.8 ;
    END
  END q[64]
  PIN q[65]
    DIRECTION INPUT ;
    USE SIGNAL ;
    PORT
      LAYER M5 ;
        RECT  125.808 64.716 125.832 64.8 ;
    END
  END q[65]
  PIN q[66]
    DIRECTION INPUT ;
    USE SIGNAL ;
    PORT
      LAYER M5 ;
        RECT  125.904 64.716 125.928 64.8 ;
    END
  END q[66]
  PIN q[67]
    DIRECTION INPUT ;
    USE SIGNAL ;
    PORT
      LAYER M5 ;
        RECT  126 64.716 126.024 64.8 ;
    END
  END q[67]
  PIN q[68]
    DIRECTION INPUT ;
    USE SIGNAL ;
    PORT
      LAYER M5 ;
        RECT  126.096 64.716 126.12 64.8 ;
    END
  END q[68]
  PIN q[69]
    DIRECTION INPUT ;
    USE SIGNAL ;
    PORT
      LAYER M5 ;
        RECT  126.192 64.716 126.216 64.8 ;
    END
  END q[69]
  PIN q[6]
    DIRECTION INPUT ;
    USE SIGNAL ;
    PORT
      LAYER M5 ;
        RECT  132.432 64.716 132.456 64.8 ;
    END
  END q[6]
  PIN q[70]
    DIRECTION INPUT ;
    USE SIGNAL ;
    PORT
      LAYER M5 ;
        RECT  126.288 64.716 126.312 64.8 ;
    END
  END q[70]
  PIN q[71]
    DIRECTION INPUT ;
    USE SIGNAL ;
    PORT
      LAYER M5 ;
        RECT  126.384 64.716 126.408 64.8 ;
    END
  END q[71]
  PIN q[72]
    DIRECTION INPUT ;
    USE SIGNAL ;
    PORT
      LAYER M5 ;
        RECT  126.48 64.716 126.504 64.8 ;
    END
  END q[72]
  PIN q[73]
    DIRECTION INPUT ;
    USE SIGNAL ;
    PORT
      LAYER M5 ;
        RECT  126.576 64.716 126.6 64.8 ;
    END
  END q[73]
  PIN q[74]
    DIRECTION INPUT ;
    USE SIGNAL ;
    PORT
      LAYER M5 ;
        RECT  126.672 64.716 126.696 64.8 ;
    END
  END q[74]
  PIN q[75]
    DIRECTION INPUT ;
    USE SIGNAL ;
    PORT
      LAYER M5 ;
        RECT  126.768 64.716 126.792 64.8 ;
    END
  END q[75]
  PIN q[76]
    DIRECTION INPUT ;
    USE SIGNAL ;
    PORT
      LAYER M5 ;
        RECT  126.864 64.716 126.888 64.8 ;
    END
  END q[76]
  PIN q[77]
    DIRECTION INPUT ;
    USE SIGNAL ;
    PORT
      LAYER M5 ;
        RECT  126.96 64.716 126.984 64.8 ;
    END
  END q[77]
  PIN q[78]
    DIRECTION INPUT ;
    USE SIGNAL ;
    PORT
      LAYER M5 ;
        RECT  127.056 64.716 127.08 64.8 ;
    END
  END q[78]
  PIN q[79]
    DIRECTION INPUT ;
    USE SIGNAL ;
    PORT
      LAYER M5 ;
        RECT  127.152 64.716 127.176 64.8 ;
    END
  END q[79]
  PIN q[7]
    DIRECTION INPUT ;
    USE SIGNAL ;
    PORT
      LAYER M5 ;
        RECT  132.528 64.716 132.552 64.8 ;
    END
  END q[7]
  PIN q[80]
    DIRECTION INPUT ;
    USE SIGNAL ;
    PORT
      LAYER M5 ;
        RECT  127.248 64.716 127.272 64.8 ;
    END
  END q[80]
  PIN q[81]
    DIRECTION INPUT ;
    USE SIGNAL ;
    PORT
      LAYER M5 ;
        RECT  127.344 64.716 127.368 64.8 ;
    END
  END q[81]
  PIN q[82]
    DIRECTION INPUT ;
    USE SIGNAL ;
    PORT
      LAYER M5 ;
        RECT  127.44 64.716 127.464 64.8 ;
    END
  END q[82]
  PIN q[83]
    DIRECTION INPUT ;
    USE SIGNAL ;
    PORT
      LAYER M5 ;
        RECT  127.536 64.716 127.56 64.8 ;
    END
  END q[83]
  PIN q[84]
    DIRECTION INPUT ;
    USE SIGNAL ;
    PORT
      LAYER M5 ;
        RECT  127.632 64.716 127.656 64.8 ;
    END
  END q[84]
  PIN q[85]
    DIRECTION INPUT ;
    USE SIGNAL ;
    PORT
      LAYER M5 ;
        RECT  127.728 64.716 127.752 64.8 ;
    END
  END q[85]
  PIN q[86]
    DIRECTION INPUT ;
    USE SIGNAL ;
    PORT
      LAYER M5 ;
        RECT  127.824 64.716 127.848 64.8 ;
    END
  END q[86]
  PIN q[87]
    DIRECTION INPUT ;
    USE SIGNAL ;
    PORT
      LAYER M5 ;
        RECT  127.92 64.716 127.944 64.8 ;
    END
  END q[87]
  PIN q[88]
    DIRECTION INPUT ;
    USE SIGNAL ;
    PORT
      LAYER M5 ;
        RECT  128.016 64.716 128.04 64.8 ;
    END
  END q[88]
  PIN q[89]
    DIRECTION INPUT ;
    USE SIGNAL ;
    PORT
      LAYER M5 ;
        RECT  128.112 64.716 128.136 64.8 ;
    END
  END q[89]
  PIN q[8]
    DIRECTION INPUT ;
    USE SIGNAL ;
    PORT
      LAYER M5 ;
        RECT  132.624 64.716 132.648 64.8 ;
    END
  END q[8]
  PIN q[90]
    DIRECTION INPUT ;
    USE SIGNAL ;
    PORT
      LAYER M5 ;
        RECT  128.208 64.716 128.232 64.8 ;
    END
  END q[90]
  PIN q[91]
    DIRECTION INPUT ;
    USE SIGNAL ;
    PORT
      LAYER M5 ;
        RECT  128.304 64.716 128.328 64.8 ;
    END
  END q[91]
  PIN q[92]
    DIRECTION INPUT ;
    USE SIGNAL ;
    PORT
      LAYER M5 ;
        RECT  128.4 64.716 128.424 64.8 ;
    END
  END q[92]
  PIN q[93]
    DIRECTION INPUT ;
    USE SIGNAL ;
    PORT
      LAYER M5 ;
        RECT  128.496 64.716 128.52 64.8 ;
    END
  END q[93]
  PIN q[94]
    DIRECTION INPUT ;
    USE SIGNAL ;
    PORT
      LAYER M5 ;
        RECT  128.592 64.716 128.616 64.8 ;
    END
  END q[94]
  PIN q[95]
    DIRECTION INPUT ;
    USE SIGNAL ;
    PORT
      LAYER M5 ;
        RECT  128.688 64.716 128.712 64.8 ;
    END
  END q[95]
  PIN q[96]
    DIRECTION INPUT ;
    USE SIGNAL ;
    PORT
      LAYER M5 ;
        RECT  119.568 64.716 119.592 64.8 ;
    END
  END q[96]
  PIN q[97]
    DIRECTION INPUT ;
    USE SIGNAL ;
    PORT
      LAYER M5 ;
        RECT  119.664 64.716 119.688 64.8 ;
    END
  END q[97]
  PIN q[98]
    DIRECTION INPUT ;
    USE SIGNAL ;
    PORT
      LAYER M5 ;
        RECT  119.76 64.716 119.784 64.8 ;
    END
  END q[98]
  PIN q[99]
    DIRECTION INPUT ;
    USE SIGNAL ;
    PORT
      LAYER M5 ;
        RECT  119.856 64.716 119.88 64.8 ;
    END
  END q[99]
  PIN q[9]
    DIRECTION INPUT ;
    USE SIGNAL ;
    PORT
      LAYER M5 ;
        RECT  132.72 64.716 132.744 64.8 ;
    END
  END q[9]
  PIN q_o[0]
    DIRECTION OUTPUT ;
    USE SIGNAL ;
    PORT
      LAYER M5 ;
        RECT  125.136 0 125.16 0.084 ;
    END
  END q_o[0]
  PIN q_o[100]
    DIRECTION OUTPUT ;
    USE SIGNAL ;
    PORT
      LAYER M5 ;
        RECT  119.376 0 119.4 0.084 ;
    END
  END q_o[100]
  PIN q_o[101]
    DIRECTION OUTPUT ;
    USE SIGNAL ;
    PORT
      LAYER M5 ;
        RECT  119.472 0 119.496 0.084 ;
    END
  END q_o[101]
  PIN q_o[102]
    DIRECTION OUTPUT ;
    USE SIGNAL ;
    PORT
      LAYER M5 ;
        RECT  119.568 0 119.592 0.084 ;
    END
  END q_o[102]
  PIN q_o[103]
    DIRECTION OUTPUT ;
    USE SIGNAL ;
    PORT
      LAYER M5 ;
        RECT  119.664 0 119.688 0.084 ;
    END
  END q_o[103]
  PIN q_o[104]
    DIRECTION OUTPUT ;
    USE SIGNAL ;
    PORT
      LAYER M5 ;
        RECT  119.76 0 119.784 0.084 ;
    END
  END q_o[104]
  PIN q_o[105]
    DIRECTION OUTPUT ;
    USE SIGNAL ;
    PORT
      LAYER M5 ;
        RECT  119.856 0 119.88 0.084 ;
    END
  END q_o[105]
  PIN q_o[106]
    DIRECTION OUTPUT ;
    USE SIGNAL ;
    PORT
      LAYER M5 ;
        RECT  119.952 0 119.976 0.084 ;
    END
  END q_o[106]
  PIN q_o[107]
    DIRECTION OUTPUT ;
    USE SIGNAL ;
    PORT
      LAYER M5 ;
        RECT  120.048 0 120.072 0.084 ;
    END
  END q_o[107]
  PIN q_o[108]
    DIRECTION OUTPUT ;
    USE SIGNAL ;
    PORT
      LAYER M5 ;
        RECT  120.144 0 120.168 0.084 ;
    END
  END q_o[108]
  PIN q_o[109]
    DIRECTION OUTPUT ;
    USE SIGNAL ;
    PORT
      LAYER M5 ;
        RECT  120.24 0 120.264 0.084 ;
    END
  END q_o[109]
  PIN q_o[10]
    DIRECTION OUTPUT ;
    USE SIGNAL ;
    PORT
      LAYER M5 ;
        RECT  126.096 0 126.12 0.084 ;
    END
  END q_o[10]
  PIN q_o[110]
    DIRECTION OUTPUT ;
    USE SIGNAL ;
    PORT
      LAYER M5 ;
        RECT  120.336 0 120.36 0.084 ;
    END
  END q_o[110]
  PIN q_o[111]
    DIRECTION OUTPUT ;
    USE SIGNAL ;
    PORT
      LAYER M5 ;
        RECT  120.432 0 120.456 0.084 ;
    END
  END q_o[111]
  PIN q_o[112]
    DIRECTION OUTPUT ;
    USE SIGNAL ;
    PORT
      LAYER M5 ;
        RECT  120.528 0 120.552 0.084 ;
    END
  END q_o[112]
  PIN q_o[113]
    DIRECTION OUTPUT ;
    USE SIGNAL ;
    PORT
      LAYER M5 ;
        RECT  120.624 0 120.648 0.084 ;
    END
  END q_o[113]
  PIN q_o[114]
    DIRECTION OUTPUT ;
    USE SIGNAL ;
    PORT
      LAYER M5 ;
        RECT  120.72 0 120.744 0.084 ;
    END
  END q_o[114]
  PIN q_o[115]
    DIRECTION OUTPUT ;
    USE SIGNAL ;
    PORT
      LAYER M5 ;
        RECT  120.816 0 120.84 0.084 ;
    END
  END q_o[115]
  PIN q_o[116]
    DIRECTION OUTPUT ;
    USE SIGNAL ;
    PORT
      LAYER M5 ;
        RECT  120.912 0 120.936 0.084 ;
    END
  END q_o[116]
  PIN q_o[117]
    DIRECTION OUTPUT ;
    USE SIGNAL ;
    PORT
      LAYER M5 ;
        RECT  121.008 0 121.032 0.084 ;
    END
  END q_o[117]
  PIN q_o[118]
    DIRECTION OUTPUT ;
    USE SIGNAL ;
    PORT
      LAYER M5 ;
        RECT  121.104 0 121.128 0.084 ;
    END
  END q_o[118]
  PIN q_o[119]
    DIRECTION OUTPUT ;
    USE SIGNAL ;
    PORT
      LAYER M5 ;
        RECT  121.2 0 121.224 0.084 ;
    END
  END q_o[119]
  PIN q_o[11]
    DIRECTION OUTPUT ;
    USE SIGNAL ;
    PORT
      LAYER M5 ;
        RECT  126.192 0 126.216 0.084 ;
    END
  END q_o[11]
  PIN q_o[120]
    DIRECTION OUTPUT ;
    USE SIGNAL ;
    PORT
      LAYER M5 ;
        RECT  121.296 0 121.32 0.084 ;
    END
  END q_o[120]
  PIN q_o[121]
    DIRECTION OUTPUT ;
    USE SIGNAL ;
    PORT
      LAYER M5 ;
        RECT  121.392 0 121.416 0.084 ;
    END
  END q_o[121]
  PIN q_o[122]
    DIRECTION OUTPUT ;
    USE SIGNAL ;
    PORT
      LAYER M5 ;
        RECT  121.488 0 121.512 0.084 ;
    END
  END q_o[122]
  PIN q_o[123]
    DIRECTION OUTPUT ;
    USE SIGNAL ;
    PORT
      LAYER M5 ;
        RECT  121.584 0 121.608 0.084 ;
    END
  END q_o[123]
  PIN q_o[124]
    DIRECTION OUTPUT ;
    USE SIGNAL ;
    PORT
      LAYER M5 ;
        RECT  121.68 0 121.704 0.084 ;
    END
  END q_o[124]
  PIN q_o[125]
    DIRECTION OUTPUT ;
    USE SIGNAL ;
    PORT
      LAYER M5 ;
        RECT  121.776 0 121.8 0.084 ;
    END
  END q_o[125]
  PIN q_o[126]
    DIRECTION OUTPUT ;
    USE SIGNAL ;
    PORT
      LAYER M5 ;
        RECT  121.872 0 121.896 0.084 ;
    END
  END q_o[126]
  PIN q_o[127]
    DIRECTION OUTPUT ;
    USE SIGNAL ;
    PORT
      LAYER M5 ;
        RECT  121.968 0 121.992 0.084 ;
    END
  END q_o[127]
  PIN q_o[128]
    DIRECTION OUTPUT ;
    USE SIGNAL ;
    PORT
      LAYER M5 ;
        RECT  128.208 0 128.232 0.084 ;
    END
  END q_o[128]
  PIN q_o[129]
    DIRECTION OUTPUT ;
    USE SIGNAL ;
    PORT
      LAYER M5 ;
        RECT  128.304 0 128.328 0.084 ;
    END
  END q_o[129]
  PIN q_o[12]
    DIRECTION OUTPUT ;
    USE SIGNAL ;
    PORT
      LAYER M5 ;
        RECT  126.288 0 126.312 0.084 ;
    END
  END q_o[12]
  PIN q_o[130]
    DIRECTION OUTPUT ;
    USE SIGNAL ;
    PORT
      LAYER M5 ;
        RECT  128.4 0 128.424 0.084 ;
    END
  END q_o[130]
  PIN q_o[131]
    DIRECTION OUTPUT ;
    USE SIGNAL ;
    PORT
      LAYER M5 ;
        RECT  128.496 0 128.52 0.084 ;
    END
  END q_o[131]
  PIN q_o[132]
    DIRECTION OUTPUT ;
    USE SIGNAL ;
    PORT
      LAYER M5 ;
        RECT  128.592 0 128.616 0.084 ;
    END
  END q_o[132]
  PIN q_o[133]
    DIRECTION OUTPUT ;
    USE SIGNAL ;
    PORT
      LAYER M5 ;
        RECT  128.688 0 128.712 0.084 ;
    END
  END q_o[133]
  PIN q_o[134]
    DIRECTION OUTPUT ;
    USE SIGNAL ;
    PORT
      LAYER M5 ;
        RECT  128.784 0 128.808 0.084 ;
    END
  END q_o[134]
  PIN q_o[135]
    DIRECTION OUTPUT ;
    USE SIGNAL ;
    PORT
      LAYER M5 ;
        RECT  128.88 0 128.904 0.084 ;
    END
  END q_o[135]
  PIN q_o[136]
    DIRECTION OUTPUT ;
    USE SIGNAL ;
    PORT
      LAYER M5 ;
        RECT  128.976 0 129 0.084 ;
    END
  END q_o[136]
  PIN q_o[137]
    DIRECTION OUTPUT ;
    USE SIGNAL ;
    PORT
      LAYER M5 ;
        RECT  129.072 0 129.096 0.084 ;
    END
  END q_o[137]
  PIN q_o[138]
    DIRECTION OUTPUT ;
    USE SIGNAL ;
    PORT
      LAYER M5 ;
        RECT  129.168 0 129.192 0.084 ;
    END
  END q_o[138]
  PIN q_o[139]
    DIRECTION OUTPUT ;
    USE SIGNAL ;
    PORT
      LAYER M5 ;
        RECT  129.264 0 129.288 0.084 ;
    END
  END q_o[139]
  PIN q_o[13]
    DIRECTION OUTPUT ;
    USE SIGNAL ;
    PORT
      LAYER M5 ;
        RECT  126.384 0 126.408 0.084 ;
    END
  END q_o[13]
  PIN q_o[140]
    DIRECTION OUTPUT ;
    USE SIGNAL ;
    PORT
      LAYER M5 ;
        RECT  129.36 0 129.384 0.084 ;
    END
  END q_o[140]
  PIN q_o[141]
    DIRECTION OUTPUT ;
    USE SIGNAL ;
    PORT
      LAYER M5 ;
        RECT  129.456 0 129.48 0.084 ;
    END
  END q_o[141]
  PIN q_o[142]
    DIRECTION OUTPUT ;
    USE SIGNAL ;
    PORT
      LAYER M5 ;
        RECT  129.552 0 129.576 0.084 ;
    END
  END q_o[142]
  PIN q_o[143]
    DIRECTION OUTPUT ;
    USE SIGNAL ;
    PORT
      LAYER M5 ;
        RECT  129.648 0 129.672 0.084 ;
    END
  END q_o[143]
  PIN q_o[144]
    DIRECTION OUTPUT ;
    USE SIGNAL ;
    PORT
      LAYER M5 ;
        RECT  129.744 0 129.768 0.084 ;
    END
  END q_o[144]
  PIN q_o[145]
    DIRECTION OUTPUT ;
    USE SIGNAL ;
    PORT
      LAYER M5 ;
        RECT  129.84 0 129.864 0.084 ;
    END
  END q_o[145]
  PIN q_o[146]
    DIRECTION OUTPUT ;
    USE SIGNAL ;
    PORT
      LAYER M5 ;
        RECT  129.936 0 129.96 0.084 ;
    END
  END q_o[146]
  PIN q_o[147]
    DIRECTION OUTPUT ;
    USE SIGNAL ;
    PORT
      LAYER M5 ;
        RECT  130.032 0 130.056 0.084 ;
    END
  END q_o[147]
  PIN q_o[148]
    DIRECTION OUTPUT ;
    USE SIGNAL ;
    PORT
      LAYER M5 ;
        RECT  130.128 0 130.152 0.084 ;
    END
  END q_o[148]
  PIN q_o[149]
    DIRECTION OUTPUT ;
    USE SIGNAL ;
    PORT
      LAYER M5 ;
        RECT  130.224 0 130.248 0.084 ;
    END
  END q_o[149]
  PIN q_o[14]
    DIRECTION OUTPUT ;
    USE SIGNAL ;
    PORT
      LAYER M5 ;
        RECT  126.48 0 126.504 0.084 ;
    END
  END q_o[14]
  PIN q_o[150]
    DIRECTION OUTPUT ;
    USE SIGNAL ;
    PORT
      LAYER M5 ;
        RECT  130.32 0 130.344 0.084 ;
    END
  END q_o[150]
  PIN q_o[151]
    DIRECTION OUTPUT ;
    USE SIGNAL ;
    PORT
      LAYER M5 ;
        RECT  130.416 0 130.44 0.084 ;
    END
  END q_o[151]
  PIN q_o[152]
    DIRECTION OUTPUT ;
    USE SIGNAL ;
    PORT
      LAYER M5 ;
        RECT  130.512 0 130.536 0.084 ;
    END
  END q_o[152]
  PIN q_o[153]
    DIRECTION OUTPUT ;
    USE SIGNAL ;
    PORT
      LAYER M5 ;
        RECT  130.608 0 130.632 0.084 ;
    END
  END q_o[153]
  PIN q_o[154]
    DIRECTION OUTPUT ;
    USE SIGNAL ;
    PORT
      LAYER M5 ;
        RECT  130.704 0 130.728 0.084 ;
    END
  END q_o[154]
  PIN q_o[155]
    DIRECTION OUTPUT ;
    USE SIGNAL ;
    PORT
      LAYER M5 ;
        RECT  130.8 0 130.824 0.084 ;
    END
  END q_o[155]
  PIN q_o[156]
    DIRECTION OUTPUT ;
    USE SIGNAL ;
    PORT
      LAYER M5 ;
        RECT  130.896 0 130.92 0.084 ;
    END
  END q_o[156]
  PIN q_o[157]
    DIRECTION OUTPUT ;
    USE SIGNAL ;
    PORT
      LAYER M5 ;
        RECT  130.992 0 131.016 0.084 ;
    END
  END q_o[157]
  PIN q_o[158]
    DIRECTION OUTPUT ;
    USE SIGNAL ;
    PORT
      LAYER M5 ;
        RECT  131.088 0 131.112 0.084 ;
    END
  END q_o[158]
  PIN q_o[159]
    DIRECTION OUTPUT ;
    USE SIGNAL ;
    PORT
      LAYER M5 ;
        RECT  131.184 0 131.208 0.084 ;
    END
  END q_o[159]
  PIN q_o[15]
    DIRECTION OUTPUT ;
    USE SIGNAL ;
    PORT
      LAYER M5 ;
        RECT  126.576 0 126.6 0.084 ;
    END
  END q_o[15]
  PIN q_o[160]
    DIRECTION OUTPUT ;
    USE SIGNAL ;
    PORT
      LAYER M5 ;
        RECT  112.08 0 112.104 0.084 ;
    END
  END q_o[160]
  PIN q_o[161]
    DIRECTION OUTPUT ;
    USE SIGNAL ;
    PORT
      LAYER M5 ;
        RECT  112.176 0 112.2 0.084 ;
    END
  END q_o[161]
  PIN q_o[162]
    DIRECTION OUTPUT ;
    USE SIGNAL ;
    PORT
      LAYER M5 ;
        RECT  112.272 0 112.296 0.084 ;
    END
  END q_o[162]
  PIN q_o[163]
    DIRECTION OUTPUT ;
    USE SIGNAL ;
    PORT
      LAYER M5 ;
        RECT  112.368 0 112.392 0.084 ;
    END
  END q_o[163]
  PIN q_o[164]
    DIRECTION OUTPUT ;
    USE SIGNAL ;
    PORT
      LAYER M5 ;
        RECT  112.464 0 112.488 0.084 ;
    END
  END q_o[164]
  PIN q_o[165]
    DIRECTION OUTPUT ;
    USE SIGNAL ;
    PORT
      LAYER M5 ;
        RECT  112.56 0 112.584 0.084 ;
    END
  END q_o[165]
  PIN q_o[166]
    DIRECTION OUTPUT ;
    USE SIGNAL ;
    PORT
      LAYER M5 ;
        RECT  112.656 0 112.68 0.084 ;
    END
  END q_o[166]
  PIN q_o[167]
    DIRECTION OUTPUT ;
    USE SIGNAL ;
    PORT
      LAYER M5 ;
        RECT  112.752 0 112.776 0.084 ;
    END
  END q_o[167]
  PIN q_o[168]
    DIRECTION OUTPUT ;
    USE SIGNAL ;
    PORT
      LAYER M5 ;
        RECT  112.848 0 112.872 0.084 ;
    END
  END q_o[168]
  PIN q_o[169]
    DIRECTION OUTPUT ;
    USE SIGNAL ;
    PORT
      LAYER M5 ;
        RECT  112.944 0 112.968 0.084 ;
    END
  END q_o[169]
  PIN q_o[16]
    DIRECTION OUTPUT ;
    USE SIGNAL ;
    PORT
      LAYER M5 ;
        RECT  126.672 0 126.696 0.084 ;
    END
  END q_o[16]
  PIN q_o[170]
    DIRECTION OUTPUT ;
    USE SIGNAL ;
    PORT
      LAYER M5 ;
        RECT  113.04 0 113.064 0.084 ;
    END
  END q_o[170]
  PIN q_o[171]
    DIRECTION OUTPUT ;
    USE SIGNAL ;
    PORT
      LAYER M5 ;
        RECT  113.136 0 113.16 0.084 ;
    END
  END q_o[171]
  PIN q_o[172]
    DIRECTION OUTPUT ;
    USE SIGNAL ;
    PORT
      LAYER M5 ;
        RECT  113.232 0 113.256 0.084 ;
    END
  END q_o[172]
  PIN q_o[173]
    DIRECTION OUTPUT ;
    USE SIGNAL ;
    PORT
      LAYER M5 ;
        RECT  113.328 0 113.352 0.084 ;
    END
  END q_o[173]
  PIN q_o[174]
    DIRECTION OUTPUT ;
    USE SIGNAL ;
    PORT
      LAYER M5 ;
        RECT  113.424 0 113.448 0.084 ;
    END
  END q_o[174]
  PIN q_o[175]
    DIRECTION OUTPUT ;
    USE SIGNAL ;
    PORT
      LAYER M5 ;
        RECT  113.52 0 113.544 0.084 ;
    END
  END q_o[175]
  PIN q_o[176]
    DIRECTION OUTPUT ;
    USE SIGNAL ;
    PORT
      LAYER M5 ;
        RECT  113.616 0 113.64 0.084 ;
    END
  END q_o[176]
  PIN q_o[177]
    DIRECTION OUTPUT ;
    USE SIGNAL ;
    PORT
      LAYER M5 ;
        RECT  113.712 0 113.736 0.084 ;
    END
  END q_o[177]
  PIN q_o[178]
    DIRECTION OUTPUT ;
    USE SIGNAL ;
    PORT
      LAYER M5 ;
        RECT  113.808 0 113.832 0.084 ;
    END
  END q_o[178]
  PIN q_o[179]
    DIRECTION OUTPUT ;
    USE SIGNAL ;
    PORT
      LAYER M5 ;
        RECT  113.904 0 113.928 0.084 ;
    END
  END q_o[179]
  PIN q_o[17]
    DIRECTION OUTPUT ;
    USE SIGNAL ;
    PORT
      LAYER M5 ;
        RECT  126.768 0 126.792 0.084 ;
    END
  END q_o[17]
  PIN q_o[180]
    DIRECTION OUTPUT ;
    USE SIGNAL ;
    PORT
      LAYER M5 ;
        RECT  114 0 114.024 0.084 ;
    END
  END q_o[180]
  PIN q_o[181]
    DIRECTION OUTPUT ;
    USE SIGNAL ;
    PORT
      LAYER M5 ;
        RECT  114.096 0 114.12 0.084 ;
    END
  END q_o[181]
  PIN q_o[182]
    DIRECTION OUTPUT ;
    USE SIGNAL ;
    PORT
      LAYER M5 ;
        RECT  114.192 0 114.216 0.084 ;
    END
  END q_o[182]
  PIN q_o[183]
    DIRECTION OUTPUT ;
    USE SIGNAL ;
    PORT
      LAYER M5 ;
        RECT  114.288 0 114.312 0.084 ;
    END
  END q_o[183]
  PIN q_o[184]
    DIRECTION OUTPUT ;
    USE SIGNAL ;
    PORT
      LAYER M5 ;
        RECT  114.384 0 114.408 0.084 ;
    END
  END q_o[184]
  PIN q_o[185]
    DIRECTION OUTPUT ;
    USE SIGNAL ;
    PORT
      LAYER M5 ;
        RECT  114.48 0 114.504 0.084 ;
    END
  END q_o[185]
  PIN q_o[186]
    DIRECTION OUTPUT ;
    USE SIGNAL ;
    PORT
      LAYER M5 ;
        RECT  114.576 0 114.6 0.084 ;
    END
  END q_o[186]
  PIN q_o[187]
    DIRECTION OUTPUT ;
    USE SIGNAL ;
    PORT
      LAYER M5 ;
        RECT  114.672 0 114.696 0.084 ;
    END
  END q_o[187]
  PIN q_o[188]
    DIRECTION OUTPUT ;
    USE SIGNAL ;
    PORT
      LAYER M5 ;
        RECT  114.768 0 114.792 0.084 ;
    END
  END q_o[188]
  PIN q_o[189]
    DIRECTION OUTPUT ;
    USE SIGNAL ;
    PORT
      LAYER M5 ;
        RECT  114.864 0 114.888 0.084 ;
    END
  END q_o[189]
  PIN q_o[18]
    DIRECTION OUTPUT ;
    USE SIGNAL ;
    PORT
      LAYER M5 ;
        RECT  126.864 0 126.888 0.084 ;
    END
  END q_o[18]
  PIN q_o[190]
    DIRECTION OUTPUT ;
    USE SIGNAL ;
    PORT
      LAYER M5 ;
        RECT  114.96 0 114.984 0.084 ;
    END
  END q_o[190]
  PIN q_o[191]
    DIRECTION OUTPUT ;
    USE SIGNAL ;
    PORT
      LAYER M5 ;
        RECT  115.056 0 115.08 0.084 ;
    END
  END q_o[191]
  PIN q_o[192]
    DIRECTION OUTPUT ;
    USE SIGNAL ;
    PORT
      LAYER M5 ;
        RECT  96.72 0 96.744 0.084 ;
    END
  END q_o[192]
  PIN q_o[193]
    DIRECTION OUTPUT ;
    USE SIGNAL ;
    PORT
      LAYER M5 ;
        RECT  96.816 0 96.84 0.084 ;
    END
  END q_o[193]
  PIN q_o[194]
    DIRECTION OUTPUT ;
    USE SIGNAL ;
    PORT
      LAYER M5 ;
        RECT  96.912 0 96.936 0.084 ;
    END
  END q_o[194]
  PIN q_o[195]
    DIRECTION OUTPUT ;
    USE SIGNAL ;
    PORT
      LAYER M5 ;
        RECT  97.008 0 97.032 0.084 ;
    END
  END q_o[195]
  PIN q_o[196]
    DIRECTION OUTPUT ;
    USE SIGNAL ;
    PORT
      LAYER M5 ;
        RECT  97.104 0 97.128 0.084 ;
    END
  END q_o[196]
  PIN q_o[197]
    DIRECTION OUTPUT ;
    USE SIGNAL ;
    PORT
      LAYER M5 ;
        RECT  97.2 0 97.224 0.084 ;
    END
  END q_o[197]
  PIN q_o[198]
    DIRECTION OUTPUT ;
    USE SIGNAL ;
    PORT
      LAYER M5 ;
        RECT  97.296 0 97.32 0.084 ;
    END
  END q_o[198]
  PIN q_o[199]
    DIRECTION OUTPUT ;
    USE SIGNAL ;
    PORT
      LAYER M5 ;
        RECT  97.392 0 97.416 0.084 ;
    END
  END q_o[199]
  PIN q_o[19]
    DIRECTION OUTPUT ;
    USE SIGNAL ;
    PORT
      LAYER M5 ;
        RECT  126.96 0 126.984 0.084 ;
    END
  END q_o[19]
  PIN q_o[1]
    DIRECTION OUTPUT ;
    USE SIGNAL ;
    PORT
      LAYER M5 ;
        RECT  125.232 0 125.256 0.084 ;
    END
  END q_o[1]
  PIN q_o[200]
    DIRECTION OUTPUT ;
    USE SIGNAL ;
    PORT
      LAYER M5 ;
        RECT  97.488 0 97.512 0.084 ;
    END
  END q_o[200]
  PIN q_o[201]
    DIRECTION OUTPUT ;
    USE SIGNAL ;
    PORT
      LAYER M5 ;
        RECT  97.584 0 97.608 0.084 ;
    END
  END q_o[201]
  PIN q_o[202]
    DIRECTION OUTPUT ;
    USE SIGNAL ;
    PORT
      LAYER M5 ;
        RECT  97.68 0 97.704 0.084 ;
    END
  END q_o[202]
  PIN q_o[203]
    DIRECTION OUTPUT ;
    USE SIGNAL ;
    PORT
      LAYER M5 ;
        RECT  97.776 0 97.8 0.084 ;
    END
  END q_o[203]
  PIN q_o[204]
    DIRECTION OUTPUT ;
    USE SIGNAL ;
    PORT
      LAYER M5 ;
        RECT  97.872 0 97.896 0.084 ;
    END
  END q_o[204]
  PIN q_o[205]
    DIRECTION OUTPUT ;
    USE SIGNAL ;
    PORT
      LAYER M5 ;
        RECT  97.968 0 97.992 0.084 ;
    END
  END q_o[205]
  PIN q_o[206]
    DIRECTION OUTPUT ;
    USE SIGNAL ;
    PORT
      LAYER M5 ;
        RECT  98.064 0 98.088 0.084 ;
    END
  END q_o[206]
  PIN q_o[207]
    DIRECTION OUTPUT ;
    USE SIGNAL ;
    PORT
      LAYER M5 ;
        RECT  98.16 0 98.184 0.084 ;
    END
  END q_o[207]
  PIN q_o[208]
    DIRECTION OUTPUT ;
    USE SIGNAL ;
    PORT
      LAYER M5 ;
        RECT  98.256 0 98.28 0.084 ;
    END
  END q_o[208]
  PIN q_o[209]
    DIRECTION OUTPUT ;
    USE SIGNAL ;
    PORT
      LAYER M5 ;
        RECT  98.352 0 98.376 0.084 ;
    END
  END q_o[209]
  PIN q_o[20]
    DIRECTION OUTPUT ;
    USE SIGNAL ;
    PORT
      LAYER M5 ;
        RECT  127.056 0 127.08 0.084 ;
    END
  END q_o[20]
  PIN q_o[210]
    DIRECTION OUTPUT ;
    USE SIGNAL ;
    PORT
      LAYER M5 ;
        RECT  98.448 0 98.472 0.084 ;
    END
  END q_o[210]
  PIN q_o[211]
    DIRECTION OUTPUT ;
    USE SIGNAL ;
    PORT
      LAYER M5 ;
        RECT  98.544 0 98.568 0.084 ;
    END
  END q_o[211]
  PIN q_o[212]
    DIRECTION OUTPUT ;
    USE SIGNAL ;
    PORT
      LAYER M5 ;
        RECT  98.64 0 98.664 0.084 ;
    END
  END q_o[212]
  PIN q_o[213]
    DIRECTION OUTPUT ;
    USE SIGNAL ;
    PORT
      LAYER M5 ;
        RECT  98.736 0 98.76 0.084 ;
    END
  END q_o[213]
  PIN q_o[214]
    DIRECTION OUTPUT ;
    USE SIGNAL ;
    PORT
      LAYER M5 ;
        RECT  98.832 0 98.856 0.084 ;
    END
  END q_o[214]
  PIN q_o[215]
    DIRECTION OUTPUT ;
    USE SIGNAL ;
    PORT
      LAYER M5 ;
        RECT  98.928 0 98.952 0.084 ;
    END
  END q_o[215]
  PIN q_o[216]
    DIRECTION OUTPUT ;
    USE SIGNAL ;
    PORT
      LAYER M5 ;
        RECT  99.024 0 99.048 0.084 ;
    END
  END q_o[216]
  PIN q_o[217]
    DIRECTION OUTPUT ;
    USE SIGNAL ;
    PORT
      LAYER M5 ;
        RECT  99.12 0 99.144 0.084 ;
    END
  END q_o[217]
  PIN q_o[218]
    DIRECTION OUTPUT ;
    USE SIGNAL ;
    PORT
      LAYER M5 ;
        RECT  99.216 0 99.24 0.084 ;
    END
  END q_o[218]
  PIN q_o[219]
    DIRECTION OUTPUT ;
    USE SIGNAL ;
    PORT
      LAYER M5 ;
        RECT  99.312 0 99.336 0.084 ;
    END
  END q_o[219]
  PIN q_o[21]
    DIRECTION OUTPUT ;
    USE SIGNAL ;
    PORT
      LAYER M5 ;
        RECT  127.152 0 127.176 0.084 ;
    END
  END q_o[21]
  PIN q_o[220]
    DIRECTION OUTPUT ;
    USE SIGNAL ;
    PORT
      LAYER M5 ;
        RECT  99.408 0 99.432 0.084 ;
    END
  END q_o[220]
  PIN q_o[221]
    DIRECTION OUTPUT ;
    USE SIGNAL ;
    PORT
      LAYER M5 ;
        RECT  99.504 0 99.528 0.084 ;
    END
  END q_o[221]
  PIN q_o[222]
    DIRECTION OUTPUT ;
    USE SIGNAL ;
    PORT
      LAYER M5 ;
        RECT  99.6 0 99.624 0.084 ;
    END
  END q_o[222]
  PIN q_o[223]
    DIRECTION OUTPUT ;
    USE SIGNAL ;
    PORT
      LAYER M5 ;
        RECT  99.696 0 99.72 0.084 ;
    END
  END q_o[223]
  PIN q_o[224]
    DIRECTION OUTPUT ;
    USE SIGNAL ;
    PORT
      LAYER M5 ;
        RECT  99.792 0 99.816 0.084 ;
    END
  END q_o[224]
  PIN q_o[225]
    DIRECTION OUTPUT ;
    USE SIGNAL ;
    PORT
      LAYER M5 ;
        RECT  99.888 0 99.912 0.084 ;
    END
  END q_o[225]
  PIN q_o[226]
    DIRECTION OUTPUT ;
    USE SIGNAL ;
    PORT
      LAYER M5 ;
        RECT  99.984 0 100.008 0.084 ;
    END
  END q_o[226]
  PIN q_o[227]
    DIRECTION OUTPUT ;
    USE SIGNAL ;
    PORT
      LAYER M5 ;
        RECT  100.08 0 100.104 0.084 ;
    END
  END q_o[227]
  PIN q_o[228]
    DIRECTION OUTPUT ;
    USE SIGNAL ;
    PORT
      LAYER M5 ;
        RECT  100.176 0 100.2 0.084 ;
    END
  END q_o[228]
  PIN q_o[229]
    DIRECTION OUTPUT ;
    USE SIGNAL ;
    PORT
      LAYER M5 ;
        RECT  100.272 0 100.296 0.084 ;
    END
  END q_o[229]
  PIN q_o[22]
    DIRECTION OUTPUT ;
    USE SIGNAL ;
    PORT
      LAYER M5 ;
        RECT  127.248 0 127.272 0.084 ;
    END
  END q_o[22]
  PIN q_o[230]
    DIRECTION OUTPUT ;
    USE SIGNAL ;
    PORT
      LAYER M5 ;
        RECT  100.368 0 100.392 0.084 ;
    END
  END q_o[230]
  PIN q_o[231]
    DIRECTION OUTPUT ;
    USE SIGNAL ;
    PORT
      LAYER M5 ;
        RECT  100.464 0 100.488 0.084 ;
    END
  END q_o[231]
  PIN q_o[232]
    DIRECTION OUTPUT ;
    USE SIGNAL ;
    PORT
      LAYER M5 ;
        RECT  100.56 0 100.584 0.084 ;
    END
  END q_o[232]
  PIN q_o[233]
    DIRECTION OUTPUT ;
    USE SIGNAL ;
    PORT
      LAYER M5 ;
        RECT  100.656 0 100.68 0.084 ;
    END
  END q_o[233]
  PIN q_o[234]
    DIRECTION OUTPUT ;
    USE SIGNAL ;
    PORT
      LAYER M5 ;
        RECT  100.752 0 100.776 0.084 ;
    END
  END q_o[234]
  PIN q_o[235]
    DIRECTION OUTPUT ;
    USE SIGNAL ;
    PORT
      LAYER M5 ;
        RECT  100.848 0 100.872 0.084 ;
    END
  END q_o[235]
  PIN q_o[236]
    DIRECTION OUTPUT ;
    USE SIGNAL ;
    PORT
      LAYER M5 ;
        RECT  100.944 0 100.968 0.084 ;
    END
  END q_o[236]
  PIN q_o[237]
    DIRECTION OUTPUT ;
    USE SIGNAL ;
    PORT
      LAYER M5 ;
        RECT  101.04 0 101.064 0.084 ;
    END
  END q_o[237]
  PIN q_o[238]
    DIRECTION OUTPUT ;
    USE SIGNAL ;
    PORT
      LAYER M5 ;
        RECT  101.136 0 101.16 0.084 ;
    END
  END q_o[238]
  PIN q_o[239]
    DIRECTION OUTPUT ;
    USE SIGNAL ;
    PORT
      LAYER M5 ;
        RECT  101.232 0 101.256 0.084 ;
    END
  END q_o[239]
  PIN q_o[23]
    DIRECTION OUTPUT ;
    USE SIGNAL ;
    PORT
      LAYER M5 ;
        RECT  127.344 0 127.368 0.084 ;
    END
  END q_o[23]
  PIN q_o[240]
    DIRECTION OUTPUT ;
    USE SIGNAL ;
    PORT
      LAYER M5 ;
        RECT  101.328 0 101.352 0.084 ;
    END
  END q_o[240]
  PIN q_o[241]
    DIRECTION OUTPUT ;
    USE SIGNAL ;
    PORT
      LAYER M5 ;
        RECT  101.424 0 101.448 0.084 ;
    END
  END q_o[241]
  PIN q_o[242]
    DIRECTION OUTPUT ;
    USE SIGNAL ;
    PORT
      LAYER M5 ;
        RECT  101.52 0 101.544 0.084 ;
    END
  END q_o[242]
  PIN q_o[243]
    DIRECTION OUTPUT ;
    USE SIGNAL ;
    PORT
      LAYER M5 ;
        RECT  101.616 0 101.64 0.084 ;
    END
  END q_o[243]
  PIN q_o[244]
    DIRECTION OUTPUT ;
    USE SIGNAL ;
    PORT
      LAYER M5 ;
        RECT  101.712 0 101.736 0.084 ;
    END
  END q_o[244]
  PIN q_o[245]
    DIRECTION OUTPUT ;
    USE SIGNAL ;
    PORT
      LAYER M5 ;
        RECT  101.808 0 101.832 0.084 ;
    END
  END q_o[245]
  PIN q_o[246]
    DIRECTION OUTPUT ;
    USE SIGNAL ;
    PORT
      LAYER M5 ;
        RECT  101.904 0 101.928 0.084 ;
    END
  END q_o[246]
  PIN q_o[247]
    DIRECTION OUTPUT ;
    USE SIGNAL ;
    PORT
      LAYER M5 ;
        RECT  102 0 102.024 0.084 ;
    END
  END q_o[247]
  PIN q_o[248]
    DIRECTION OUTPUT ;
    USE SIGNAL ;
    PORT
      LAYER M5 ;
        RECT  102.096 0 102.12 0.084 ;
    END
  END q_o[248]
  PIN q_o[249]
    DIRECTION OUTPUT ;
    USE SIGNAL ;
    PORT
      LAYER M5 ;
        RECT  102.192 0 102.216 0.084 ;
    END
  END q_o[249]
  PIN q_o[24]
    DIRECTION OUTPUT ;
    USE SIGNAL ;
    PORT
      LAYER M5 ;
        RECT  127.44 0 127.464 0.084 ;
    END
  END q_o[24]
  PIN q_o[250]
    DIRECTION OUTPUT ;
    USE SIGNAL ;
    PORT
      LAYER M5 ;
        RECT  102.288 0 102.312 0.084 ;
    END
  END q_o[250]
  PIN q_o[251]
    DIRECTION OUTPUT ;
    USE SIGNAL ;
    PORT
      LAYER M5 ;
        RECT  102.384 0 102.408 0.084 ;
    END
  END q_o[251]
  PIN q_o[252]
    DIRECTION OUTPUT ;
    USE SIGNAL ;
    PORT
      LAYER M5 ;
        RECT  102.48 0 102.504 0.084 ;
    END
  END q_o[252]
  PIN q_o[253]
    DIRECTION OUTPUT ;
    USE SIGNAL ;
    PORT
      LAYER M5 ;
        RECT  102.576 0 102.6 0.084 ;
    END
  END q_o[253]
  PIN q_o[254]
    DIRECTION OUTPUT ;
    USE SIGNAL ;
    PORT
      LAYER M5 ;
        RECT  102.672 0 102.696 0.084 ;
    END
  END q_o[254]
  PIN q_o[255]
    DIRECTION OUTPUT ;
    USE SIGNAL ;
    PORT
      LAYER M5 ;
        RECT  102.768 0 102.792 0.084 ;
    END
  END q_o[255]
  PIN q_o[256]
    DIRECTION OUTPUT ;
    USE SIGNAL ;
    PORT
      LAYER M5 ;
        RECT  105.936 0 105.96 0.084 ;
    END
  END q_o[256]
  PIN q_o[257]
    DIRECTION OUTPUT ;
    USE SIGNAL ;
    PORT
      LAYER M5 ;
        RECT  106.032 0 106.056 0.084 ;
    END
  END q_o[257]
  PIN q_o[258]
    DIRECTION OUTPUT ;
    USE SIGNAL ;
    PORT
      LAYER M5 ;
        RECT  106.128 0 106.152 0.084 ;
    END
  END q_o[258]
  PIN q_o[259]
    DIRECTION OUTPUT ;
    USE SIGNAL ;
    PORT
      LAYER M5 ;
        RECT  106.224 0 106.248 0.084 ;
    END
  END q_o[259]
  PIN q_o[25]
    DIRECTION OUTPUT ;
    USE SIGNAL ;
    PORT
      LAYER M5 ;
        RECT  127.536 0 127.56 0.084 ;
    END
  END q_o[25]
  PIN q_o[260]
    DIRECTION OUTPUT ;
    USE SIGNAL ;
    PORT
      LAYER M5 ;
        RECT  106.32 0 106.344 0.084 ;
    END
  END q_o[260]
  PIN q_o[261]
    DIRECTION OUTPUT ;
    USE SIGNAL ;
    PORT
      LAYER M5 ;
        RECT  106.416 0 106.44 0.084 ;
    END
  END q_o[261]
  PIN q_o[262]
    DIRECTION OUTPUT ;
    USE SIGNAL ;
    PORT
      LAYER M5 ;
        RECT  106.512 0 106.536 0.084 ;
    END
  END q_o[262]
  PIN q_o[263]
    DIRECTION OUTPUT ;
    USE SIGNAL ;
    PORT
      LAYER M5 ;
        RECT  106.608 0 106.632 0.084 ;
    END
  END q_o[263]
  PIN q_o[264]
    DIRECTION OUTPUT ;
    USE SIGNAL ;
    PORT
      LAYER M5 ;
        RECT  106.704 0 106.728 0.084 ;
    END
  END q_o[264]
  PIN q_o[265]
    DIRECTION OUTPUT ;
    USE SIGNAL ;
    PORT
      LAYER M5 ;
        RECT  106.8 0 106.824 0.084 ;
    END
  END q_o[265]
  PIN q_o[266]
    DIRECTION OUTPUT ;
    USE SIGNAL ;
    PORT
      LAYER M5 ;
        RECT  106.896 0 106.92 0.084 ;
    END
  END q_o[266]
  PIN q_o[267]
    DIRECTION OUTPUT ;
    USE SIGNAL ;
    PORT
      LAYER M5 ;
        RECT  106.992 0 107.016 0.084 ;
    END
  END q_o[267]
  PIN q_o[268]
    DIRECTION OUTPUT ;
    USE SIGNAL ;
    PORT
      LAYER M5 ;
        RECT  107.088 0 107.112 0.084 ;
    END
  END q_o[268]
  PIN q_o[269]
    DIRECTION OUTPUT ;
    USE SIGNAL ;
    PORT
      LAYER M5 ;
        RECT  107.184 0 107.208 0.084 ;
    END
  END q_o[269]
  PIN q_o[26]
    DIRECTION OUTPUT ;
    USE SIGNAL ;
    PORT
      LAYER M5 ;
        RECT  127.632 0 127.656 0.084 ;
    END
  END q_o[26]
  PIN q_o[270]
    DIRECTION OUTPUT ;
    USE SIGNAL ;
    PORT
      LAYER M5 ;
        RECT  107.28 0 107.304 0.084 ;
    END
  END q_o[270]
  PIN q_o[271]
    DIRECTION OUTPUT ;
    USE SIGNAL ;
    PORT
      LAYER M5 ;
        RECT  107.376 0 107.4 0.084 ;
    END
  END q_o[271]
  PIN q_o[272]
    DIRECTION OUTPUT ;
    USE SIGNAL ;
    PORT
      LAYER M5 ;
        RECT  107.472 0 107.496 0.084 ;
    END
  END q_o[272]
  PIN q_o[273]
    DIRECTION OUTPUT ;
    USE SIGNAL ;
    PORT
      LAYER M5 ;
        RECT  107.568 0 107.592 0.084 ;
    END
  END q_o[273]
  PIN q_o[274]
    DIRECTION OUTPUT ;
    USE SIGNAL ;
    PORT
      LAYER M5 ;
        RECT  107.664 0 107.688 0.084 ;
    END
  END q_o[274]
  PIN q_o[275]
    DIRECTION OUTPUT ;
    USE SIGNAL ;
    PORT
      LAYER M5 ;
        RECT  107.76 0 107.784 0.084 ;
    END
  END q_o[275]
  PIN q_o[276]
    DIRECTION OUTPUT ;
    USE SIGNAL ;
    PORT
      LAYER M5 ;
        RECT  107.856 0 107.88 0.084 ;
    END
  END q_o[276]
  PIN q_o[277]
    DIRECTION OUTPUT ;
    USE SIGNAL ;
    PORT
      LAYER M5 ;
        RECT  107.952 0 107.976 0.084 ;
    END
  END q_o[277]
  PIN q_o[278]
    DIRECTION OUTPUT ;
    USE SIGNAL ;
    PORT
      LAYER M5 ;
        RECT  108.048 0 108.072 0.084 ;
    END
  END q_o[278]
  PIN q_o[279]
    DIRECTION OUTPUT ;
    USE SIGNAL ;
    PORT
      LAYER M5 ;
        RECT  108.144 0 108.168 0.084 ;
    END
  END q_o[279]
  PIN q_o[27]
    DIRECTION OUTPUT ;
    USE SIGNAL ;
    PORT
      LAYER M5 ;
        RECT  127.728 0 127.752 0.084 ;
    END
  END q_o[27]
  PIN q_o[280]
    DIRECTION OUTPUT ;
    USE SIGNAL ;
    PORT
      LAYER M5 ;
        RECT  108.24 0 108.264 0.084 ;
    END
  END q_o[280]
  PIN q_o[281]
    DIRECTION OUTPUT ;
    USE SIGNAL ;
    PORT
      LAYER M5 ;
        RECT  108.336 0 108.36 0.084 ;
    END
  END q_o[281]
  PIN q_o[282]
    DIRECTION OUTPUT ;
    USE SIGNAL ;
    PORT
      LAYER M5 ;
        RECT  108.432 0 108.456 0.084 ;
    END
  END q_o[282]
  PIN q_o[283]
    DIRECTION OUTPUT ;
    USE SIGNAL ;
    PORT
      LAYER M5 ;
        RECT  108.528 0 108.552 0.084 ;
    END
  END q_o[283]
  PIN q_o[284]
    DIRECTION OUTPUT ;
    USE SIGNAL ;
    PORT
      LAYER M5 ;
        RECT  108.624 0 108.648 0.084 ;
    END
  END q_o[284]
  PIN q_o[285]
    DIRECTION OUTPUT ;
    USE SIGNAL ;
    PORT
      LAYER M5 ;
        RECT  108.72 0 108.744 0.084 ;
    END
  END q_o[285]
  PIN q_o[286]
    DIRECTION OUTPUT ;
    USE SIGNAL ;
    PORT
      LAYER M5 ;
        RECT  108.816 0 108.84 0.084 ;
    END
  END q_o[286]
  PIN q_o[287]
    DIRECTION OUTPUT ;
    USE SIGNAL ;
    PORT
      LAYER M5 ;
        RECT  108.912 0 108.936 0.084 ;
    END
  END q_o[287]
  PIN q_o[288]
    DIRECTION OUTPUT ;
    USE SIGNAL ;
    PORT
      LAYER M5 ;
        RECT  109.008 0 109.032 0.084 ;
    END
  END q_o[288]
  PIN q_o[289]
    DIRECTION OUTPUT ;
    USE SIGNAL ;
    PORT
      LAYER M5 ;
        RECT  109.104 0 109.128 0.084 ;
    END
  END q_o[289]
  PIN q_o[28]
    DIRECTION OUTPUT ;
    USE SIGNAL ;
    PORT
      LAYER M5 ;
        RECT  127.824 0 127.848 0.084 ;
    END
  END q_o[28]
  PIN q_o[290]
    DIRECTION OUTPUT ;
    USE SIGNAL ;
    PORT
      LAYER M5 ;
        RECT  109.2 0 109.224 0.084 ;
    END
  END q_o[290]
  PIN q_o[291]
    DIRECTION OUTPUT ;
    USE SIGNAL ;
    PORT
      LAYER M5 ;
        RECT  109.296 0 109.32 0.084 ;
    END
  END q_o[291]
  PIN q_o[292]
    DIRECTION OUTPUT ;
    USE SIGNAL ;
    PORT
      LAYER M5 ;
        RECT  109.392 0 109.416 0.084 ;
    END
  END q_o[292]
  PIN q_o[293]
    DIRECTION OUTPUT ;
    USE SIGNAL ;
    PORT
      LAYER M5 ;
        RECT  109.488 0 109.512 0.084 ;
    END
  END q_o[293]
  PIN q_o[294]
    DIRECTION OUTPUT ;
    USE SIGNAL ;
    PORT
      LAYER M5 ;
        RECT  109.584 0 109.608 0.084 ;
    END
  END q_o[294]
  PIN q_o[295]
    DIRECTION OUTPUT ;
    USE SIGNAL ;
    PORT
      LAYER M5 ;
        RECT  109.68 0 109.704 0.084 ;
    END
  END q_o[295]
  PIN q_o[296]
    DIRECTION OUTPUT ;
    USE SIGNAL ;
    PORT
      LAYER M5 ;
        RECT  109.776 0 109.8 0.084 ;
    END
  END q_o[296]
  PIN q_o[297]
    DIRECTION OUTPUT ;
    USE SIGNAL ;
    PORT
      LAYER M5 ;
        RECT  109.872 0 109.896 0.084 ;
    END
  END q_o[297]
  PIN q_o[298]
    DIRECTION OUTPUT ;
    USE SIGNAL ;
    PORT
      LAYER M5 ;
        RECT  109.968 0 109.992 0.084 ;
    END
  END q_o[298]
  PIN q_o[299]
    DIRECTION OUTPUT ;
    USE SIGNAL ;
    PORT
      LAYER M5 ;
        RECT  110.064 0 110.088 0.084 ;
    END
  END q_o[299]
  PIN q_o[29]
    DIRECTION OUTPUT ;
    USE SIGNAL ;
    PORT
      LAYER M5 ;
        RECT  127.92 0 127.944 0.084 ;
    END
  END q_o[29]
  PIN q_o[2]
    DIRECTION OUTPUT ;
    USE SIGNAL ;
    PORT
      LAYER M5 ;
        RECT  125.328 0 125.352 0.084 ;
    END
  END q_o[2]
  PIN q_o[300]
    DIRECTION OUTPUT ;
    USE SIGNAL ;
    PORT
      LAYER M5 ;
        RECT  110.16 0 110.184 0.084 ;
    END
  END q_o[300]
  PIN q_o[301]
    DIRECTION OUTPUT ;
    USE SIGNAL ;
    PORT
      LAYER M5 ;
        RECT  110.256 0 110.28 0.084 ;
    END
  END q_o[301]
  PIN q_o[302]
    DIRECTION OUTPUT ;
    USE SIGNAL ;
    PORT
      LAYER M5 ;
        RECT  110.352 0 110.376 0.084 ;
    END
  END q_o[302]
  PIN q_o[303]
    DIRECTION OUTPUT ;
    USE SIGNAL ;
    PORT
      LAYER M5 ;
        RECT  110.448 0 110.472 0.084 ;
    END
  END q_o[303]
  PIN q_o[304]
    DIRECTION OUTPUT ;
    USE SIGNAL ;
    PORT
      LAYER M5 ;
        RECT  110.544 0 110.568 0.084 ;
    END
  END q_o[304]
  PIN q_o[305]
    DIRECTION OUTPUT ;
    USE SIGNAL ;
    PORT
      LAYER M5 ;
        RECT  110.64 0 110.664 0.084 ;
    END
  END q_o[305]
  PIN q_o[306]
    DIRECTION OUTPUT ;
    USE SIGNAL ;
    PORT
      LAYER M5 ;
        RECT  110.736 0 110.76 0.084 ;
    END
  END q_o[306]
  PIN q_o[307]
    DIRECTION OUTPUT ;
    USE SIGNAL ;
    PORT
      LAYER M5 ;
        RECT  110.832 0 110.856 0.084 ;
    END
  END q_o[307]
  PIN q_o[308]
    DIRECTION OUTPUT ;
    USE SIGNAL ;
    PORT
      LAYER M5 ;
        RECT  110.928 0 110.952 0.084 ;
    END
  END q_o[308]
  PIN q_o[309]
    DIRECTION OUTPUT ;
    USE SIGNAL ;
    PORT
      LAYER M5 ;
        RECT  111.024 0 111.048 0.084 ;
    END
  END q_o[309]
  PIN q_o[30]
    DIRECTION OUTPUT ;
    USE SIGNAL ;
    PORT
      LAYER M5 ;
        RECT  128.016 0 128.04 0.084 ;
    END
  END q_o[30]
  PIN q_o[310]
    DIRECTION OUTPUT ;
    USE SIGNAL ;
    PORT
      LAYER M5 ;
        RECT  111.12 0 111.144 0.084 ;
    END
  END q_o[310]
  PIN q_o[311]
    DIRECTION OUTPUT ;
    USE SIGNAL ;
    PORT
      LAYER M5 ;
        RECT  111.216 0 111.24 0.084 ;
    END
  END q_o[311]
  PIN q_o[312]
    DIRECTION OUTPUT ;
    USE SIGNAL ;
    PORT
      LAYER M5 ;
        RECT  111.312 0 111.336 0.084 ;
    END
  END q_o[312]
  PIN q_o[313]
    DIRECTION OUTPUT ;
    USE SIGNAL ;
    PORT
      LAYER M5 ;
        RECT  111.408 0 111.432 0.084 ;
    END
  END q_o[313]
  PIN q_o[314]
    DIRECTION OUTPUT ;
    USE SIGNAL ;
    PORT
      LAYER M5 ;
        RECT  111.504 0 111.528 0.084 ;
    END
  END q_o[314]
  PIN q_o[315]
    DIRECTION OUTPUT ;
    USE SIGNAL ;
    PORT
      LAYER M5 ;
        RECT  111.6 0 111.624 0.084 ;
    END
  END q_o[315]
  PIN q_o[316]
    DIRECTION OUTPUT ;
    USE SIGNAL ;
    PORT
      LAYER M5 ;
        RECT  111.696 0 111.72 0.084 ;
    END
  END q_o[316]
  PIN q_o[317]
    DIRECTION OUTPUT ;
    USE SIGNAL ;
    PORT
      LAYER M5 ;
        RECT  111.792 0 111.816 0.084 ;
    END
  END q_o[317]
  PIN q_o[318]
    DIRECTION OUTPUT ;
    USE SIGNAL ;
    PORT
      LAYER M5 ;
        RECT  111.888 0 111.912 0.084 ;
    END
  END q_o[318]
  PIN q_o[319]
    DIRECTION OUTPUT ;
    USE SIGNAL ;
    PORT
      LAYER M5 ;
        RECT  111.984 0 112.008 0.084 ;
    END
  END q_o[319]
  PIN q_o[31]
    DIRECTION OUTPUT ;
    USE SIGNAL ;
    PORT
      LAYER M5 ;
        RECT  128.112 0 128.136 0.084 ;
    END
  END q_o[31]
  PIN q_o[320]
    DIRECTION OUTPUT ;
    USE SIGNAL ;
    PORT
      LAYER M5 ;
        RECT  102.864 0 102.888 0.084 ;
    END
  END q_o[320]
  PIN q_o[321]
    DIRECTION OUTPUT ;
    USE SIGNAL ;
    PORT
      LAYER M5 ;
        RECT  102.96 0 102.984 0.084 ;
    END
  END q_o[321]
  PIN q_o[322]
    DIRECTION OUTPUT ;
    USE SIGNAL ;
    PORT
      LAYER M5 ;
        RECT  103.056 0 103.08 0.084 ;
    END
  END q_o[322]
  PIN q_o[323]
    DIRECTION OUTPUT ;
    USE SIGNAL ;
    PORT
      LAYER M5 ;
        RECT  103.152 0 103.176 0.084 ;
    END
  END q_o[323]
  PIN q_o[324]
    DIRECTION OUTPUT ;
    USE SIGNAL ;
    PORT
      LAYER M5 ;
        RECT  103.248 0 103.272 0.084 ;
    END
  END q_o[324]
  PIN q_o[325]
    DIRECTION OUTPUT ;
    USE SIGNAL ;
    PORT
      LAYER M5 ;
        RECT  103.344 0 103.368 0.084 ;
    END
  END q_o[325]
  PIN q_o[326]
    DIRECTION OUTPUT ;
    USE SIGNAL ;
    PORT
      LAYER M5 ;
        RECT  103.44 0 103.464 0.084 ;
    END
  END q_o[326]
  PIN q_o[327]
    DIRECTION OUTPUT ;
    USE SIGNAL ;
    PORT
      LAYER M5 ;
        RECT  103.536 0 103.56 0.084 ;
    END
  END q_o[327]
  PIN q_o[328]
    DIRECTION OUTPUT ;
    USE SIGNAL ;
    PORT
      LAYER M5 ;
        RECT  103.632 0 103.656 0.084 ;
    END
  END q_o[328]
  PIN q_o[329]
    DIRECTION OUTPUT ;
    USE SIGNAL ;
    PORT
      LAYER M5 ;
        RECT  103.728 0 103.752 0.084 ;
    END
  END q_o[329]
  PIN q_o[32]
    DIRECTION OUTPUT ;
    USE SIGNAL ;
    PORT
      LAYER M5 ;
        RECT  122.064 0 122.088 0.084 ;
    END
  END q_o[32]
  PIN q_o[330]
    DIRECTION OUTPUT ;
    USE SIGNAL ;
    PORT
      LAYER M5 ;
        RECT  103.824 0 103.848 0.084 ;
    END
  END q_o[330]
  PIN q_o[331]
    DIRECTION OUTPUT ;
    USE SIGNAL ;
    PORT
      LAYER M5 ;
        RECT  103.92 0 103.944 0.084 ;
    END
  END q_o[331]
  PIN q_o[332]
    DIRECTION OUTPUT ;
    USE SIGNAL ;
    PORT
      LAYER M5 ;
        RECT  104.016 0 104.04 0.084 ;
    END
  END q_o[332]
  PIN q_o[333]
    DIRECTION OUTPUT ;
    USE SIGNAL ;
    PORT
      LAYER M5 ;
        RECT  104.112 0 104.136 0.084 ;
    END
  END q_o[333]
  PIN q_o[334]
    DIRECTION OUTPUT ;
    USE SIGNAL ;
    PORT
      LAYER M5 ;
        RECT  104.208 0 104.232 0.084 ;
    END
  END q_o[334]
  PIN q_o[335]
    DIRECTION OUTPUT ;
    USE SIGNAL ;
    PORT
      LAYER M5 ;
        RECT  104.304 0 104.328 0.084 ;
    END
  END q_o[335]
  PIN q_o[336]
    DIRECTION OUTPUT ;
    USE SIGNAL ;
    PORT
      LAYER M5 ;
        RECT  104.4 0 104.424 0.084 ;
    END
  END q_o[336]
  PIN q_o[337]
    DIRECTION OUTPUT ;
    USE SIGNAL ;
    PORT
      LAYER M5 ;
        RECT  104.496 0 104.52 0.084 ;
    END
  END q_o[337]
  PIN q_o[338]
    DIRECTION OUTPUT ;
    USE SIGNAL ;
    PORT
      LAYER M5 ;
        RECT  104.592 0 104.616 0.084 ;
    END
  END q_o[338]
  PIN q_o[339]
    DIRECTION OUTPUT ;
    USE SIGNAL ;
    PORT
      LAYER M5 ;
        RECT  104.688 0 104.712 0.084 ;
    END
  END q_o[339]
  PIN q_o[33]
    DIRECTION OUTPUT ;
    USE SIGNAL ;
    PORT
      LAYER M5 ;
        RECT  122.16 0 122.184 0.084 ;
    END
  END q_o[33]
  PIN q_o[340]
    DIRECTION OUTPUT ;
    USE SIGNAL ;
    PORT
      LAYER M5 ;
        RECT  104.784 0 104.808 0.084 ;
    END
  END q_o[340]
  PIN q_o[341]
    DIRECTION OUTPUT ;
    USE SIGNAL ;
    PORT
      LAYER M5 ;
        RECT  104.88 0 104.904 0.084 ;
    END
  END q_o[341]
  PIN q_o[342]
    DIRECTION OUTPUT ;
    USE SIGNAL ;
    PORT
      LAYER M5 ;
        RECT  104.976 0 105 0.084 ;
    END
  END q_o[342]
  PIN q_o[343]
    DIRECTION OUTPUT ;
    USE SIGNAL ;
    PORT
      LAYER M5 ;
        RECT  105.072 0 105.096 0.084 ;
    END
  END q_o[343]
  PIN q_o[344]
    DIRECTION OUTPUT ;
    USE SIGNAL ;
    PORT
      LAYER M5 ;
        RECT  105.168 0 105.192 0.084 ;
    END
  END q_o[344]
  PIN q_o[345]
    DIRECTION OUTPUT ;
    USE SIGNAL ;
    PORT
      LAYER M5 ;
        RECT  105.264 0 105.288 0.084 ;
    END
  END q_o[345]
  PIN q_o[346]
    DIRECTION OUTPUT ;
    USE SIGNAL ;
    PORT
      LAYER M5 ;
        RECT  105.36 0 105.384 0.084 ;
    END
  END q_o[346]
  PIN q_o[347]
    DIRECTION OUTPUT ;
    USE SIGNAL ;
    PORT
      LAYER M5 ;
        RECT  105.456 0 105.48 0.084 ;
    END
  END q_o[347]
  PIN q_o[348]
    DIRECTION OUTPUT ;
    USE SIGNAL ;
    PORT
      LAYER M5 ;
        RECT  105.552 0 105.576 0.084 ;
    END
  END q_o[348]
  PIN q_o[349]
    DIRECTION OUTPUT ;
    USE SIGNAL ;
    PORT
      LAYER M5 ;
        RECT  105.648 0 105.672 0.084 ;
    END
  END q_o[349]
  PIN q_o[34]
    DIRECTION OUTPUT ;
    USE SIGNAL ;
    PORT
      LAYER M5 ;
        RECT  122.256 0 122.28 0.084 ;
    END
  END q_o[34]
  PIN q_o[350]
    DIRECTION OUTPUT ;
    USE SIGNAL ;
    PORT
      LAYER M5 ;
        RECT  105.744 0 105.768 0.084 ;
    END
  END q_o[350]
  PIN q_o[351]
    DIRECTION OUTPUT ;
    USE SIGNAL ;
    PORT
      LAYER M5 ;
        RECT  105.84 0 105.864 0.084 ;
    END
  END q_o[351]
  PIN q_o[352]
    DIRECTION OUTPUT ;
    USE SIGNAL ;
    PORT
      LAYER M5 ;
        RECT  115.92 0 115.944 0.084 ;
    END
  END q_o[352]
  PIN q_o[353]
    DIRECTION OUTPUT ;
    USE SIGNAL ;
    PORT
      LAYER M5 ;
        RECT  116.016 0 116.04 0.084 ;
    END
  END q_o[353]
  PIN q_o[354]
    DIRECTION OUTPUT ;
    USE SIGNAL ;
    PORT
      LAYER M5 ;
        RECT  116.112 0 116.136 0.084 ;
    END
  END q_o[354]
  PIN q_o[355]
    DIRECTION OUTPUT ;
    USE SIGNAL ;
    PORT
      LAYER M5 ;
        RECT  116.208 0 116.232 0.084 ;
    END
  END q_o[355]
  PIN q_o[356]
    DIRECTION OUTPUT ;
    USE SIGNAL ;
    PORT
      LAYER M5 ;
        RECT  116.304 0 116.328 0.084 ;
    END
  END q_o[356]
  PIN q_o[357]
    DIRECTION OUTPUT ;
    USE SIGNAL ;
    PORT
      LAYER M5 ;
        RECT  116.4 0 116.424 0.084 ;
    END
  END q_o[357]
  PIN q_o[358]
    DIRECTION OUTPUT ;
    USE SIGNAL ;
    PORT
      LAYER M5 ;
        RECT  116.496 0 116.52 0.084 ;
    END
  END q_o[358]
  PIN q_o[359]
    DIRECTION OUTPUT ;
    USE SIGNAL ;
    PORT
      LAYER M5 ;
        RECT  116.592 0 116.616 0.084 ;
    END
  END q_o[359]
  PIN q_o[35]
    DIRECTION OUTPUT ;
    USE SIGNAL ;
    PORT
      LAYER M5 ;
        RECT  122.352 0 122.376 0.084 ;
    END
  END q_o[35]
  PIN q_o[360]
    DIRECTION OUTPUT ;
    USE SIGNAL ;
    PORT
      LAYER M5 ;
        RECT  116.688 0 116.712 0.084 ;
    END
  END q_o[360]
  PIN q_o[361]
    DIRECTION OUTPUT ;
    USE SIGNAL ;
    PORT
      LAYER M5 ;
        RECT  116.784 0 116.808 0.084 ;
    END
  END q_o[361]
  PIN q_o[362]
    DIRECTION OUTPUT ;
    USE SIGNAL ;
    PORT
      LAYER M5 ;
        RECT  116.88 0 116.904 0.084 ;
    END
  END q_o[362]
  PIN q_o[363]
    DIRECTION OUTPUT ;
    USE SIGNAL ;
    PORT
      LAYER M5 ;
        RECT  116.976 0 117 0.084 ;
    END
  END q_o[363]
  PIN q_o[364]
    DIRECTION OUTPUT ;
    USE SIGNAL ;
    PORT
      LAYER M5 ;
        RECT  117.072 0 117.096 0.084 ;
    END
  END q_o[364]
  PIN q_o[365]
    DIRECTION OUTPUT ;
    USE SIGNAL ;
    PORT
      LAYER M5 ;
        RECT  117.168 0 117.192 0.084 ;
    END
  END q_o[365]
  PIN q_o[366]
    DIRECTION OUTPUT ;
    USE SIGNAL ;
    PORT
      LAYER M5 ;
        RECT  117.264 0 117.288 0.084 ;
    END
  END q_o[366]
  PIN q_o[367]
    DIRECTION OUTPUT ;
    USE SIGNAL ;
    PORT
      LAYER M5 ;
        RECT  117.36 0 117.384 0.084 ;
    END
  END q_o[367]
  PIN q_o[368]
    DIRECTION OUTPUT ;
    USE SIGNAL ;
    PORT
      LAYER M5 ;
        RECT  117.456 0 117.48 0.084 ;
    END
  END q_o[368]
  PIN q_o[369]
    DIRECTION OUTPUT ;
    USE SIGNAL ;
    PORT
      LAYER M5 ;
        RECT  117.552 0 117.576 0.084 ;
    END
  END q_o[369]
  PIN q_o[36]
    DIRECTION OUTPUT ;
    USE SIGNAL ;
    PORT
      LAYER M5 ;
        RECT  122.448 0 122.472 0.084 ;
    END
  END q_o[36]
  PIN q_o[370]
    DIRECTION OUTPUT ;
    USE SIGNAL ;
    PORT
      LAYER M5 ;
        RECT  117.648 0 117.672 0.084 ;
    END
  END q_o[370]
  PIN q_o[371]
    DIRECTION OUTPUT ;
    USE SIGNAL ;
    PORT
      LAYER M5 ;
        RECT  117.744 0 117.768 0.084 ;
    END
  END q_o[371]
  PIN q_o[372]
    DIRECTION OUTPUT ;
    USE SIGNAL ;
    PORT
      LAYER M5 ;
        RECT  117.84 0 117.864 0.084 ;
    END
  END q_o[372]
  PIN q_o[373]
    DIRECTION OUTPUT ;
    USE SIGNAL ;
    PORT
      LAYER M5 ;
        RECT  117.936 0 117.96 0.084 ;
    END
  END q_o[373]
  PIN q_o[374]
    DIRECTION OUTPUT ;
    USE SIGNAL ;
    PORT
      LAYER M5 ;
        RECT  118.032 0 118.056 0.084 ;
    END
  END q_o[374]
  PIN q_o[375]
    DIRECTION OUTPUT ;
    USE SIGNAL ;
    PORT
      LAYER M5 ;
        RECT  118.128 0 118.152 0.084 ;
    END
  END q_o[375]
  PIN q_o[376]
    DIRECTION OUTPUT ;
    USE SIGNAL ;
    PORT
      LAYER M5 ;
        RECT  118.224 0 118.248 0.084 ;
    END
  END q_o[376]
  PIN q_o[377]
    DIRECTION OUTPUT ;
    USE SIGNAL ;
    PORT
      LAYER M5 ;
        RECT  118.32 0 118.344 0.084 ;
    END
  END q_o[377]
  PIN q_o[378]
    DIRECTION OUTPUT ;
    USE SIGNAL ;
    PORT
      LAYER M5 ;
        RECT  118.416 0 118.44 0.084 ;
    END
  END q_o[378]
  PIN q_o[379]
    DIRECTION OUTPUT ;
    USE SIGNAL ;
    PORT
      LAYER M5 ;
        RECT  118.512 0 118.536 0.084 ;
    END
  END q_o[379]
  PIN q_o[37]
    DIRECTION OUTPUT ;
    USE SIGNAL ;
    PORT
      LAYER M5 ;
        RECT  122.544 0 122.568 0.084 ;
    END
  END q_o[37]
  PIN q_o[380]
    DIRECTION OUTPUT ;
    USE SIGNAL ;
    PORT
      LAYER M5 ;
        RECT  118.608 0 118.632 0.084 ;
    END
  END q_o[380]
  PIN q_o[381]
    DIRECTION OUTPUT ;
    USE SIGNAL ;
    PORT
      LAYER M5 ;
        RECT  118.704 0 118.728 0.084 ;
    END
  END q_o[381]
  PIN q_o[382]
    DIRECTION OUTPUT ;
    USE SIGNAL ;
    PORT
      LAYER M5 ;
        RECT  118.8 0 118.824 0.084 ;
    END
  END q_o[382]
  PIN q_o[383]
    DIRECTION OUTPUT ;
    USE SIGNAL ;
    PORT
      LAYER M5 ;
        RECT  118.896 0 118.92 0.084 ;
    END
  END q_o[383]
  PIN q_o[384]
    DIRECTION OUTPUT ;
    USE SIGNAL ;
    PORT
      LAYER M5 ;
        RECT  92.88 0 92.904 0.084 ;
    END
  END q_o[384]
  PIN q_o[385]
    DIRECTION OUTPUT ;
    USE SIGNAL ;
    PORT
      LAYER M5 ;
        RECT  92.976 0 93 0.084 ;
    END
  END q_o[385]
  PIN q_o[386]
    DIRECTION OUTPUT ;
    USE SIGNAL ;
    PORT
      LAYER M5 ;
        RECT  93.072 0 93.096 0.084 ;
    END
  END q_o[386]
  PIN q_o[387]
    DIRECTION OUTPUT ;
    USE SIGNAL ;
    PORT
      LAYER M5 ;
        RECT  93.168 0 93.192 0.084 ;
    END
  END q_o[387]
  PIN q_o[388]
    DIRECTION OUTPUT ;
    USE SIGNAL ;
    PORT
      LAYER M5 ;
        RECT  93.264 0 93.288 0.084 ;
    END
  END q_o[388]
  PIN q_o[389]
    DIRECTION OUTPUT ;
    USE SIGNAL ;
    PORT
      LAYER M5 ;
        RECT  93.36 0 93.384 0.084 ;
    END
  END q_o[389]
  PIN q_o[38]
    DIRECTION OUTPUT ;
    USE SIGNAL ;
    PORT
      LAYER M5 ;
        RECT  122.64 0 122.664 0.084 ;
    END
  END q_o[38]
  PIN q_o[390]
    DIRECTION OUTPUT ;
    USE SIGNAL ;
    PORT
      LAYER M5 ;
        RECT  93.456 0 93.48 0.084 ;
    END
  END q_o[390]
  PIN q_o[391]
    DIRECTION OUTPUT ;
    USE SIGNAL ;
    PORT
      LAYER M5 ;
        RECT  93.552 0 93.576 0.084 ;
    END
  END q_o[391]
  PIN q_o[392]
    DIRECTION OUTPUT ;
    USE SIGNAL ;
    PORT
      LAYER M5 ;
        RECT  93.648 0 93.672 0.084 ;
    END
  END q_o[392]
  PIN q_o[393]
    DIRECTION OUTPUT ;
    USE SIGNAL ;
    PORT
      LAYER M5 ;
        RECT  93.744 0 93.768 0.084 ;
    END
  END q_o[393]
  PIN q_o[394]
    DIRECTION OUTPUT ;
    USE SIGNAL ;
    PORT
      LAYER M5 ;
        RECT  93.84 0 93.864 0.084 ;
    END
  END q_o[394]
  PIN q_o[395]
    DIRECTION OUTPUT ;
    USE SIGNAL ;
    PORT
      LAYER M5 ;
        RECT  93.936 0 93.96 0.084 ;
    END
  END q_o[395]
  PIN q_o[396]
    DIRECTION OUTPUT ;
    USE SIGNAL ;
    PORT
      LAYER M5 ;
        RECT  94.032 0 94.056 0.084 ;
    END
  END q_o[396]
  PIN q_o[397]
    DIRECTION OUTPUT ;
    USE SIGNAL ;
    PORT
      LAYER M5 ;
        RECT  94.128 0 94.152 0.084 ;
    END
  END q_o[397]
  PIN q_o[398]
    DIRECTION OUTPUT ;
    USE SIGNAL ;
    PORT
      LAYER M5 ;
        RECT  94.224 0 94.248 0.084 ;
    END
  END q_o[398]
  PIN q_o[399]
    DIRECTION OUTPUT ;
    USE SIGNAL ;
    PORT
      LAYER M5 ;
        RECT  94.32 0 94.344 0.084 ;
    END
  END q_o[399]
  PIN q_o[39]
    DIRECTION OUTPUT ;
    USE SIGNAL ;
    PORT
      LAYER M5 ;
        RECT  122.736 0 122.76 0.084 ;
    END
  END q_o[39]
  PIN q_o[3]
    DIRECTION OUTPUT ;
    USE SIGNAL ;
    PORT
      LAYER M5 ;
        RECT  125.424 0 125.448 0.084 ;
    END
  END q_o[3]
  PIN q_o[400]
    DIRECTION OUTPUT ;
    USE SIGNAL ;
    PORT
      LAYER M5 ;
        RECT  94.416 0 94.44 0.084 ;
    END
  END q_o[400]
  PIN q_o[401]
    DIRECTION OUTPUT ;
    USE SIGNAL ;
    PORT
      LAYER M5 ;
        RECT  94.512 0 94.536 0.084 ;
    END
  END q_o[401]
  PIN q_o[402]
    DIRECTION OUTPUT ;
    USE SIGNAL ;
    PORT
      LAYER M5 ;
        RECT  94.608 0 94.632 0.084 ;
    END
  END q_o[402]
  PIN q_o[403]
    DIRECTION OUTPUT ;
    USE SIGNAL ;
    PORT
      LAYER M5 ;
        RECT  94.704 0 94.728 0.084 ;
    END
  END q_o[403]
  PIN q_o[404]
    DIRECTION OUTPUT ;
    USE SIGNAL ;
    PORT
      LAYER M5 ;
        RECT  94.8 0 94.824 0.084 ;
    END
  END q_o[404]
  PIN q_o[405]
    DIRECTION OUTPUT ;
    USE SIGNAL ;
    PORT
      LAYER M5 ;
        RECT  94.896 0 94.92 0.084 ;
    END
  END q_o[405]
  PIN q_o[406]
    DIRECTION OUTPUT ;
    USE SIGNAL ;
    PORT
      LAYER M5 ;
        RECT  94.992 0 95.016 0.084 ;
    END
  END q_o[406]
  PIN q_o[407]
    DIRECTION OUTPUT ;
    USE SIGNAL ;
    PORT
      LAYER M5 ;
        RECT  95.088 0 95.112 0.084 ;
    END
  END q_o[407]
  PIN q_o[408]
    DIRECTION OUTPUT ;
    USE SIGNAL ;
    PORT
      LAYER M5 ;
        RECT  95.184 0 95.208 0.084 ;
    END
  END q_o[408]
  PIN q_o[409]
    DIRECTION OUTPUT ;
    USE SIGNAL ;
    PORT
      LAYER M5 ;
        RECT  95.28 0 95.304 0.084 ;
    END
  END q_o[409]
  PIN q_o[40]
    DIRECTION OUTPUT ;
    USE SIGNAL ;
    PORT
      LAYER M5 ;
        RECT  122.832 0 122.856 0.084 ;
    END
  END q_o[40]
  PIN q_o[410]
    DIRECTION OUTPUT ;
    USE SIGNAL ;
    PORT
      LAYER M5 ;
        RECT  95.376 0 95.4 0.084 ;
    END
  END q_o[410]
  PIN q_o[411]
    DIRECTION OUTPUT ;
    USE SIGNAL ;
    PORT
      LAYER M5 ;
        RECT  95.472 0 95.496 0.084 ;
    END
  END q_o[411]
  PIN q_o[412]
    DIRECTION OUTPUT ;
    USE SIGNAL ;
    PORT
      LAYER M5 ;
        RECT  95.568 0 95.592 0.084 ;
    END
  END q_o[412]
  PIN q_o[413]
    DIRECTION OUTPUT ;
    USE SIGNAL ;
    PORT
      LAYER M5 ;
        RECT  95.664 0 95.688 0.084 ;
    END
  END q_o[413]
  PIN q_o[414]
    DIRECTION OUTPUT ;
    USE SIGNAL ;
    PORT
      LAYER M5 ;
        RECT  95.76 0 95.784 0.084 ;
    END
  END q_o[414]
  PIN q_o[415]
    DIRECTION OUTPUT ;
    USE SIGNAL ;
    PORT
      LAYER M5 ;
        RECT  95.856 0 95.88 0.084 ;
    END
  END q_o[415]
  PIN q_o[416]
    DIRECTION OUTPUT ;
    USE SIGNAL ;
    PORT
      LAYER M5 ;
        RECT  89.808 0 89.832 0.084 ;
    END
  END q_o[416]
  PIN q_o[417]
    DIRECTION OUTPUT ;
    USE SIGNAL ;
    PORT
      LAYER M5 ;
        RECT  89.904 0 89.928 0.084 ;
    END
  END q_o[417]
  PIN q_o[418]
    DIRECTION OUTPUT ;
    USE SIGNAL ;
    PORT
      LAYER M5 ;
        RECT  90 0 90.024 0.084 ;
    END
  END q_o[418]
  PIN q_o[419]
    DIRECTION OUTPUT ;
    USE SIGNAL ;
    PORT
      LAYER M5 ;
        RECT  90.096 0 90.12 0.084 ;
    END
  END q_o[419]
  PIN q_o[41]
    DIRECTION OUTPUT ;
    USE SIGNAL ;
    PORT
      LAYER M5 ;
        RECT  122.928 0 122.952 0.084 ;
    END
  END q_o[41]
  PIN q_o[420]
    DIRECTION OUTPUT ;
    USE SIGNAL ;
    PORT
      LAYER M5 ;
        RECT  90.192 0 90.216 0.084 ;
    END
  END q_o[420]
  PIN q_o[421]
    DIRECTION OUTPUT ;
    USE SIGNAL ;
    PORT
      LAYER M5 ;
        RECT  90.288 0 90.312 0.084 ;
    END
  END q_o[421]
  PIN q_o[422]
    DIRECTION OUTPUT ;
    USE SIGNAL ;
    PORT
      LAYER M5 ;
        RECT  90.384 0 90.408 0.084 ;
    END
  END q_o[422]
  PIN q_o[423]
    DIRECTION OUTPUT ;
    USE SIGNAL ;
    PORT
      LAYER M5 ;
        RECT  90.48 0 90.504 0.084 ;
    END
  END q_o[423]
  PIN q_o[424]
    DIRECTION OUTPUT ;
    USE SIGNAL ;
    PORT
      LAYER M5 ;
        RECT  90.576 0 90.6 0.084 ;
    END
  END q_o[424]
  PIN q_o[425]
    DIRECTION OUTPUT ;
    USE SIGNAL ;
    PORT
      LAYER M5 ;
        RECT  90.672 0 90.696 0.084 ;
    END
  END q_o[425]
  PIN q_o[426]
    DIRECTION OUTPUT ;
    USE SIGNAL ;
    PORT
      LAYER M5 ;
        RECT  90.768 0 90.792 0.084 ;
    END
  END q_o[426]
  PIN q_o[427]
    DIRECTION OUTPUT ;
    USE SIGNAL ;
    PORT
      LAYER M5 ;
        RECT  90.864 0 90.888 0.084 ;
    END
  END q_o[427]
  PIN q_o[428]
    DIRECTION OUTPUT ;
    USE SIGNAL ;
    PORT
      LAYER M5 ;
        RECT  90.96 0 90.984 0.084 ;
    END
  END q_o[428]
  PIN q_o[429]
    DIRECTION OUTPUT ;
    USE SIGNAL ;
    PORT
      LAYER M5 ;
        RECT  91.056 0 91.08 0.084 ;
    END
  END q_o[429]
  PIN q_o[42]
    DIRECTION OUTPUT ;
    USE SIGNAL ;
    PORT
      LAYER M5 ;
        RECT  123.024 0 123.048 0.084 ;
    END
  END q_o[42]
  PIN q_o[430]
    DIRECTION OUTPUT ;
    USE SIGNAL ;
    PORT
      LAYER M5 ;
        RECT  91.152 0 91.176 0.084 ;
    END
  END q_o[430]
  PIN q_o[431]
    DIRECTION OUTPUT ;
    USE SIGNAL ;
    PORT
      LAYER M5 ;
        RECT  91.248 0 91.272 0.084 ;
    END
  END q_o[431]
  PIN q_o[432]
    DIRECTION OUTPUT ;
    USE SIGNAL ;
    PORT
      LAYER M5 ;
        RECT  91.344 0 91.368 0.084 ;
    END
  END q_o[432]
  PIN q_o[433]
    DIRECTION OUTPUT ;
    USE SIGNAL ;
    PORT
      LAYER M5 ;
        RECT  91.44 0 91.464 0.084 ;
    END
  END q_o[433]
  PIN q_o[434]
    DIRECTION OUTPUT ;
    USE SIGNAL ;
    PORT
      LAYER M5 ;
        RECT  91.536 0 91.56 0.084 ;
    END
  END q_o[434]
  PIN q_o[435]
    DIRECTION OUTPUT ;
    USE SIGNAL ;
    PORT
      LAYER M5 ;
        RECT  91.632 0 91.656 0.084 ;
    END
  END q_o[435]
  PIN q_o[436]
    DIRECTION OUTPUT ;
    USE SIGNAL ;
    PORT
      LAYER M5 ;
        RECT  91.728 0 91.752 0.084 ;
    END
  END q_o[436]
  PIN q_o[437]
    DIRECTION OUTPUT ;
    USE SIGNAL ;
    PORT
      LAYER M5 ;
        RECT  91.824 0 91.848 0.084 ;
    END
  END q_o[437]
  PIN q_o[438]
    DIRECTION OUTPUT ;
    USE SIGNAL ;
    PORT
      LAYER M5 ;
        RECT  91.92 0 91.944 0.084 ;
    END
  END q_o[438]
  PIN q_o[439]
    DIRECTION OUTPUT ;
    USE SIGNAL ;
    PORT
      LAYER M5 ;
        RECT  92.016 0 92.04 0.084 ;
    END
  END q_o[439]
  PIN q_o[43]
    DIRECTION OUTPUT ;
    USE SIGNAL ;
    PORT
      LAYER M5 ;
        RECT  123.12 0 123.144 0.084 ;
    END
  END q_o[43]
  PIN q_o[440]
    DIRECTION OUTPUT ;
    USE SIGNAL ;
    PORT
      LAYER M5 ;
        RECT  92.112 0 92.136 0.084 ;
    END
  END q_o[440]
  PIN q_o[441]
    DIRECTION OUTPUT ;
    USE SIGNAL ;
    PORT
      LAYER M5 ;
        RECT  92.208 0 92.232 0.084 ;
    END
  END q_o[441]
  PIN q_o[442]
    DIRECTION OUTPUT ;
    USE SIGNAL ;
    PORT
      LAYER M5 ;
        RECT  92.304 0 92.328 0.084 ;
    END
  END q_o[442]
  PIN q_o[443]
    DIRECTION OUTPUT ;
    USE SIGNAL ;
    PORT
      LAYER M5 ;
        RECT  92.4 0 92.424 0.084 ;
    END
  END q_o[443]
  PIN q_o[444]
    DIRECTION OUTPUT ;
    USE SIGNAL ;
    PORT
      LAYER M5 ;
        RECT  92.496 0 92.52 0.084 ;
    END
  END q_o[444]
  PIN q_o[445]
    DIRECTION OUTPUT ;
    USE SIGNAL ;
    PORT
      LAYER M5 ;
        RECT  92.592 0 92.616 0.084 ;
    END
  END q_o[445]
  PIN q_o[446]
    DIRECTION OUTPUT ;
    USE SIGNAL ;
    PORT
      LAYER M5 ;
        RECT  92.688 0 92.712 0.084 ;
    END
  END q_o[446]
  PIN q_o[447]
    DIRECTION OUTPUT ;
    USE SIGNAL ;
    PORT
      LAYER M5 ;
        RECT  92.784 0 92.808 0.084 ;
    END
  END q_o[447]
  PIN q_o[448]
    DIRECTION OUTPUT ;
    USE SIGNAL ;
    PORT
      LAYER M5 ;
        RECT  135.12 0 135.144 0.084 ;
    END
  END q_o[448]
  PIN q_o[449]
    DIRECTION OUTPUT ;
    USE SIGNAL ;
    PORT
      LAYER M5 ;
        RECT  135.216 0 135.24 0.084 ;
    END
  END q_o[449]
  PIN q_o[44]
    DIRECTION OUTPUT ;
    USE SIGNAL ;
    PORT
      LAYER M5 ;
        RECT  123.216 0 123.24 0.084 ;
    END
  END q_o[44]
  PIN q_o[450]
    DIRECTION OUTPUT ;
    USE SIGNAL ;
    PORT
      LAYER M5 ;
        RECT  135.312 0 135.336 0.084 ;
    END
  END q_o[450]
  PIN q_o[451]
    DIRECTION OUTPUT ;
    USE SIGNAL ;
    PORT
      LAYER M5 ;
        RECT  135.408 0 135.432 0.084 ;
    END
  END q_o[451]
  PIN q_o[452]
    DIRECTION OUTPUT ;
    USE SIGNAL ;
    PORT
      LAYER M5 ;
        RECT  135.504 0 135.528 0.084 ;
    END
  END q_o[452]
  PIN q_o[453]
    DIRECTION OUTPUT ;
    USE SIGNAL ;
    PORT
      LAYER M5 ;
        RECT  135.6 0 135.624 0.084 ;
    END
  END q_o[453]
  PIN q_o[454]
    DIRECTION OUTPUT ;
    USE SIGNAL ;
    PORT
      LAYER M5 ;
        RECT  135.696 0 135.72 0.084 ;
    END
  END q_o[454]
  PIN q_o[455]
    DIRECTION OUTPUT ;
    USE SIGNAL ;
    PORT
      LAYER M5 ;
        RECT  135.792 0 135.816 0.084 ;
    END
  END q_o[455]
  PIN q_o[456]
    DIRECTION OUTPUT ;
    USE SIGNAL ;
    PORT
      LAYER M5 ;
        RECT  135.888 0 135.912 0.084 ;
    END
  END q_o[456]
  PIN q_o[457]
    DIRECTION OUTPUT ;
    USE SIGNAL ;
    PORT
      LAYER M5 ;
        RECT  135.984 0 136.008 0.084 ;
    END
  END q_o[457]
  PIN q_o[458]
    DIRECTION OUTPUT ;
    USE SIGNAL ;
    PORT
      LAYER M5 ;
        RECT  136.08 0 136.104 0.084 ;
    END
  END q_o[458]
  PIN q_o[459]
    DIRECTION OUTPUT ;
    USE SIGNAL ;
    PORT
      LAYER M5 ;
        RECT  136.176 0 136.2 0.084 ;
    END
  END q_o[459]
  PIN q_o[45]
    DIRECTION OUTPUT ;
    USE SIGNAL ;
    PORT
      LAYER M5 ;
        RECT  123.312 0 123.336 0.084 ;
    END
  END q_o[45]
  PIN q_o[460]
    DIRECTION OUTPUT ;
    USE SIGNAL ;
    PORT
      LAYER M5 ;
        RECT  136.272 0 136.296 0.084 ;
    END
  END q_o[460]
  PIN q_o[461]
    DIRECTION OUTPUT ;
    USE SIGNAL ;
    PORT
      LAYER M5 ;
        RECT  136.368 0 136.392 0.084 ;
    END
  END q_o[461]
  PIN q_o[462]
    DIRECTION OUTPUT ;
    USE SIGNAL ;
    PORT
      LAYER M5 ;
        RECT  136.464 0 136.488 0.084 ;
    END
  END q_o[462]
  PIN q_o[463]
    DIRECTION OUTPUT ;
    USE SIGNAL ;
    PORT
      LAYER M5 ;
        RECT  136.56 0 136.584 0.084 ;
    END
  END q_o[463]
  PIN q_o[464]
    DIRECTION OUTPUT ;
    USE SIGNAL ;
    PORT
      LAYER M5 ;
        RECT  136.656 0 136.68 0.084 ;
    END
  END q_o[464]
  PIN q_o[465]
    DIRECTION OUTPUT ;
    USE SIGNAL ;
    PORT
      LAYER M5 ;
        RECT  136.752 0 136.776 0.084 ;
    END
  END q_o[465]
  PIN q_o[466]
    DIRECTION OUTPUT ;
    USE SIGNAL ;
    PORT
      LAYER M5 ;
        RECT  136.848 0 136.872 0.084 ;
    END
  END q_o[466]
  PIN q_o[467]
    DIRECTION OUTPUT ;
    USE SIGNAL ;
    PORT
      LAYER M5 ;
        RECT  136.944 0 136.968 0.084 ;
    END
  END q_o[467]
  PIN q_o[468]
    DIRECTION OUTPUT ;
    USE SIGNAL ;
    PORT
      LAYER M5 ;
        RECT  137.04 0 137.064 0.084 ;
    END
  END q_o[468]
  PIN q_o[469]
    DIRECTION OUTPUT ;
    USE SIGNAL ;
    PORT
      LAYER M5 ;
        RECT  137.136 0 137.16 0.084 ;
    END
  END q_o[469]
  PIN q_o[46]
    DIRECTION OUTPUT ;
    USE SIGNAL ;
    PORT
      LAYER M5 ;
        RECT  123.408 0 123.432 0.084 ;
    END
  END q_o[46]
  PIN q_o[470]
    DIRECTION OUTPUT ;
    USE SIGNAL ;
    PORT
      LAYER M5 ;
        RECT  137.232 0 137.256 0.084 ;
    END
  END q_o[470]
  PIN q_o[471]
    DIRECTION OUTPUT ;
    USE SIGNAL ;
    PORT
      LAYER M5 ;
        RECT  137.328 0 137.352 0.084 ;
    END
  END q_o[471]
  PIN q_o[472]
    DIRECTION OUTPUT ;
    USE SIGNAL ;
    PORT
      LAYER M5 ;
        RECT  137.424 0 137.448 0.084 ;
    END
  END q_o[472]
  PIN q_o[473]
    DIRECTION OUTPUT ;
    USE SIGNAL ;
    PORT
      LAYER M5 ;
        RECT  137.52 0 137.544 0.084 ;
    END
  END q_o[473]
  PIN q_o[474]
    DIRECTION OUTPUT ;
    USE SIGNAL ;
    PORT
      LAYER M5 ;
        RECT  137.616 0 137.64 0.084 ;
    END
  END q_o[474]
  PIN q_o[475]
    DIRECTION OUTPUT ;
    USE SIGNAL ;
    PORT
      LAYER M5 ;
        RECT  137.712 0 137.736 0.084 ;
    END
  END q_o[475]
  PIN q_o[476]
    DIRECTION OUTPUT ;
    USE SIGNAL ;
    PORT
      LAYER M5 ;
        RECT  137.808 0 137.832 0.084 ;
    END
  END q_o[476]
  PIN q_o[477]
    DIRECTION OUTPUT ;
    USE SIGNAL ;
    PORT
      LAYER M5 ;
        RECT  137.904 0 137.928 0.084 ;
    END
  END q_o[477]
  PIN q_o[478]
    DIRECTION OUTPUT ;
    USE SIGNAL ;
    PORT
      LAYER M5 ;
        RECT  138 0 138.024 0.084 ;
    END
  END q_o[478]
  PIN q_o[479]
    DIRECTION OUTPUT ;
    USE SIGNAL ;
    PORT
      LAYER M5 ;
        RECT  138.096 0 138.12 0.084 ;
    END
  END q_o[479]
  PIN q_o[47]
    DIRECTION OUTPUT ;
    USE SIGNAL ;
    PORT
      LAYER M5 ;
        RECT  123.504 0 123.528 0.084 ;
    END
  END q_o[47]
  PIN q_o[480]
    DIRECTION OUTPUT ;
    USE SIGNAL ;
    PORT
      LAYER M5 ;
        RECT  138.192 0 138.216 0.084 ;
    END
  END q_o[480]
  PIN q_o[481]
    DIRECTION OUTPUT ;
    USE SIGNAL ;
    PORT
      LAYER M5 ;
        RECT  138.288 0 138.312 0.084 ;
    END
  END q_o[481]
  PIN q_o[482]
    DIRECTION OUTPUT ;
    USE SIGNAL ;
    PORT
      LAYER M5 ;
        RECT  138.384 0 138.408 0.084 ;
    END
  END q_o[482]
  PIN q_o[483]
    DIRECTION OUTPUT ;
    USE SIGNAL ;
    PORT
      LAYER M5 ;
        RECT  138.48 0 138.504 0.084 ;
    END
  END q_o[483]
  PIN q_o[484]
    DIRECTION OUTPUT ;
    USE SIGNAL ;
    PORT
      LAYER M5 ;
        RECT  138.576 0 138.6 0.084 ;
    END
  END q_o[484]
  PIN q_o[485]
    DIRECTION OUTPUT ;
    USE SIGNAL ;
    PORT
      LAYER M5 ;
        RECT  138.672 0 138.696 0.084 ;
    END
  END q_o[485]
  PIN q_o[486]
    DIRECTION OUTPUT ;
    USE SIGNAL ;
    PORT
      LAYER M5 ;
        RECT  138.768 0 138.792 0.084 ;
    END
  END q_o[486]
  PIN q_o[487]
    DIRECTION OUTPUT ;
    USE SIGNAL ;
    PORT
      LAYER M5 ;
        RECT  138.864 0 138.888 0.084 ;
    END
  END q_o[487]
  PIN q_o[488]
    DIRECTION OUTPUT ;
    USE SIGNAL ;
    PORT
      LAYER M5 ;
        RECT  138.96 0 138.984 0.084 ;
    END
  END q_o[488]
  PIN q_o[489]
    DIRECTION OUTPUT ;
    USE SIGNAL ;
    PORT
      LAYER M5 ;
        RECT  139.056 0 139.08 0.084 ;
    END
  END q_o[489]
  PIN q_o[48]
    DIRECTION OUTPUT ;
    USE SIGNAL ;
    PORT
      LAYER M5 ;
        RECT  123.6 0 123.624 0.084 ;
    END
  END q_o[48]
  PIN q_o[490]
    DIRECTION OUTPUT ;
    USE SIGNAL ;
    PORT
      LAYER M5 ;
        RECT  139.152 0 139.176 0.084 ;
    END
  END q_o[490]
  PIN q_o[491]
    DIRECTION OUTPUT ;
    USE SIGNAL ;
    PORT
      LAYER M5 ;
        RECT  139.248 0 139.272 0.084 ;
    END
  END q_o[491]
  PIN q_o[492]
    DIRECTION OUTPUT ;
    USE SIGNAL ;
    PORT
      LAYER M5 ;
        RECT  139.344 0 139.368 0.084 ;
    END
  END q_o[492]
  PIN q_o[493]
    DIRECTION OUTPUT ;
    USE SIGNAL ;
    PORT
      LAYER M5 ;
        RECT  139.44 0 139.464 0.084 ;
    END
  END q_o[493]
  PIN q_o[494]
    DIRECTION OUTPUT ;
    USE SIGNAL ;
    PORT
      LAYER M5 ;
        RECT  139.536 0 139.56 0.084 ;
    END
  END q_o[494]
  PIN q_o[495]
    DIRECTION OUTPUT ;
    USE SIGNAL ;
    PORT
      LAYER M5 ;
        RECT  139.632 0 139.656 0.084 ;
    END
  END q_o[495]
  PIN q_o[496]
    DIRECTION OUTPUT ;
    USE SIGNAL ;
    PORT
      LAYER M5 ;
        RECT  139.728 0 139.752 0.084 ;
    END
  END q_o[496]
  PIN q_o[497]
    DIRECTION OUTPUT ;
    USE SIGNAL ;
    PORT
      LAYER M5 ;
        RECT  139.824 0 139.848 0.084 ;
    END
  END q_o[497]
  PIN q_o[498]
    DIRECTION OUTPUT ;
    USE SIGNAL ;
    PORT
      LAYER M5 ;
        RECT  139.92 0 139.944 0.084 ;
    END
  END q_o[498]
  PIN q_o[499]
    DIRECTION OUTPUT ;
    USE SIGNAL ;
    PORT
      LAYER M5 ;
        RECT  140.016 0 140.04 0.084 ;
    END
  END q_o[499]
  PIN q_o[49]
    DIRECTION OUTPUT ;
    USE SIGNAL ;
    PORT
      LAYER M5 ;
        RECT  123.696 0 123.72 0.084 ;
    END
  END q_o[49]
  PIN q_o[4]
    DIRECTION OUTPUT ;
    USE SIGNAL ;
    PORT
      LAYER M5 ;
        RECT  125.52 0 125.544 0.084 ;
    END
  END q_o[4]
  PIN q_o[500]
    DIRECTION OUTPUT ;
    USE SIGNAL ;
    PORT
      LAYER M5 ;
        RECT  140.112 0 140.136 0.084 ;
    END
  END q_o[500]
  PIN q_o[501]
    DIRECTION OUTPUT ;
    USE SIGNAL ;
    PORT
      LAYER M5 ;
        RECT  140.208 0 140.232 0.084 ;
    END
  END q_o[501]
  PIN q_o[502]
    DIRECTION OUTPUT ;
    USE SIGNAL ;
    PORT
      LAYER M5 ;
        RECT  140.304 0 140.328 0.084 ;
    END
  END q_o[502]
  PIN q_o[503]
    DIRECTION OUTPUT ;
    USE SIGNAL ;
    PORT
      LAYER M5 ;
        RECT  140.4 0 140.424 0.084 ;
    END
  END q_o[503]
  PIN q_o[504]
    DIRECTION OUTPUT ;
    USE SIGNAL ;
    PORT
      LAYER M5 ;
        RECT  140.496 0 140.52 0.084 ;
    END
  END q_o[504]
  PIN q_o[505]
    DIRECTION OUTPUT ;
    USE SIGNAL ;
    PORT
      LAYER M5 ;
        RECT  140.592 0 140.616 0.084 ;
    END
  END q_o[505]
  PIN q_o[506]
    DIRECTION OUTPUT ;
    USE SIGNAL ;
    PORT
      LAYER M5 ;
        RECT  140.688 0 140.712 0.084 ;
    END
  END q_o[506]
  PIN q_o[507]
    DIRECTION OUTPUT ;
    USE SIGNAL ;
    PORT
      LAYER M5 ;
        RECT  140.784 0 140.808 0.084 ;
    END
  END q_o[507]
  PIN q_o[508]
    DIRECTION OUTPUT ;
    USE SIGNAL ;
    PORT
      LAYER M5 ;
        RECT  140.88 0 140.904 0.084 ;
    END
  END q_o[508]
  PIN q_o[509]
    DIRECTION OUTPUT ;
    USE SIGNAL ;
    PORT
      LAYER M5 ;
        RECT  140.976 0 141 0.084 ;
    END
  END q_o[509]
  PIN q_o[50]
    DIRECTION OUTPUT ;
    USE SIGNAL ;
    PORT
      LAYER M5 ;
        RECT  123.792 0 123.816 0.084 ;
    END
  END q_o[50]
  PIN q_o[510]
    DIRECTION OUTPUT ;
    USE SIGNAL ;
    PORT
      LAYER M5 ;
        RECT  141.072 0 141.096 0.084 ;
    END
  END q_o[510]
  PIN q_o[511]
    DIRECTION OUTPUT ;
    USE SIGNAL ;
    PORT
      LAYER M5 ;
        RECT  141.168 0 141.192 0.084 ;
    END
  END q_o[511]
  PIN q_o[512]
    DIRECTION OUTPUT ;
    USE SIGNAL ;
    PORT
      LAYER M5 ;
        RECT  134.352 0 134.376 0.084 ;
    END
  END q_o[512]
  PIN q_o[513]
    DIRECTION OUTPUT ;
    USE SIGNAL ;
    PORT
      LAYER M5 ;
        RECT  134.448 0 134.472 0.084 ;
    END
  END q_o[513]
  PIN q_o[514]
    DIRECTION OUTPUT ;
    USE SIGNAL ;
    PORT
      LAYER M5 ;
        RECT  134.544 0 134.568 0.084 ;
    END
  END q_o[514]
  PIN q_o[51]
    DIRECTION OUTPUT ;
    USE SIGNAL ;
    PORT
      LAYER M5 ;
        RECT  123.888 0 123.912 0.084 ;
    END
  END q_o[51]
  PIN q_o[52]
    DIRECTION OUTPUT ;
    USE SIGNAL ;
    PORT
      LAYER M5 ;
        RECT  123.984 0 124.008 0.084 ;
    END
  END q_o[52]
  PIN q_o[53]
    DIRECTION OUTPUT ;
    USE SIGNAL ;
    PORT
      LAYER M5 ;
        RECT  124.08 0 124.104 0.084 ;
    END
  END q_o[53]
  PIN q_o[54]
    DIRECTION OUTPUT ;
    USE SIGNAL ;
    PORT
      LAYER M5 ;
        RECT  124.176 0 124.2 0.084 ;
    END
  END q_o[54]
  PIN q_o[55]
    DIRECTION OUTPUT ;
    USE SIGNAL ;
    PORT
      LAYER M5 ;
        RECT  124.272 0 124.296 0.084 ;
    END
  END q_o[55]
  PIN q_o[56]
    DIRECTION OUTPUT ;
    USE SIGNAL ;
    PORT
      LAYER M5 ;
        RECT  124.368 0 124.392 0.084 ;
    END
  END q_o[56]
  PIN q_o[57]
    DIRECTION OUTPUT ;
    USE SIGNAL ;
    PORT
      LAYER M5 ;
        RECT  124.464 0 124.488 0.084 ;
    END
  END q_o[57]
  PIN q_o[58]
    DIRECTION OUTPUT ;
    USE SIGNAL ;
    PORT
      LAYER M5 ;
        RECT  124.56 0 124.584 0.084 ;
    END
  END q_o[58]
  PIN q_o[59]
    DIRECTION OUTPUT ;
    USE SIGNAL ;
    PORT
      LAYER M5 ;
        RECT  124.656 0 124.68 0.084 ;
    END
  END q_o[59]
  PIN q_o[5]
    DIRECTION OUTPUT ;
    USE SIGNAL ;
    PORT
      LAYER M5 ;
        RECT  125.616 0 125.64 0.084 ;
    END
  END q_o[5]
  PIN q_o[60]
    DIRECTION OUTPUT ;
    USE SIGNAL ;
    PORT
      LAYER M5 ;
        RECT  124.752 0 124.776 0.084 ;
    END
  END q_o[60]
  PIN q_o[61]
    DIRECTION OUTPUT ;
    USE SIGNAL ;
    PORT
      LAYER M5 ;
        RECT  124.848 0 124.872 0.084 ;
    END
  END q_o[61]
  PIN q_o[62]
    DIRECTION OUTPUT ;
    USE SIGNAL ;
    PORT
      LAYER M5 ;
        RECT  124.944 0 124.968 0.084 ;
    END
  END q_o[62]
  PIN q_o[63]
    DIRECTION OUTPUT ;
    USE SIGNAL ;
    PORT
      LAYER M5 ;
        RECT  125.04 0 125.064 0.084 ;
    END
  END q_o[63]
  PIN q_o[64]
    DIRECTION OUTPUT ;
    USE SIGNAL ;
    PORT
      LAYER M5 ;
        RECT  131.28 0 131.304 0.084 ;
    END
  END q_o[64]
  PIN q_o[65]
    DIRECTION OUTPUT ;
    USE SIGNAL ;
    PORT
      LAYER M5 ;
        RECT  131.376 0 131.4 0.084 ;
    END
  END q_o[65]
  PIN q_o[66]
    DIRECTION OUTPUT ;
    USE SIGNAL ;
    PORT
      LAYER M5 ;
        RECT  131.472 0 131.496 0.084 ;
    END
  END q_o[66]
  PIN q_o[67]
    DIRECTION OUTPUT ;
    USE SIGNAL ;
    PORT
      LAYER M5 ;
        RECT  131.568 0 131.592 0.084 ;
    END
  END q_o[67]
  PIN q_o[68]
    DIRECTION OUTPUT ;
    USE SIGNAL ;
    PORT
      LAYER M5 ;
        RECT  131.664 0 131.688 0.084 ;
    END
  END q_o[68]
  PIN q_o[69]
    DIRECTION OUTPUT ;
    USE SIGNAL ;
    PORT
      LAYER M5 ;
        RECT  131.76 0 131.784 0.084 ;
    END
  END q_o[69]
  PIN q_o[6]
    DIRECTION OUTPUT ;
    USE SIGNAL ;
    PORT
      LAYER M5 ;
        RECT  125.712 0 125.736 0.084 ;
    END
  END q_o[6]
  PIN q_o[70]
    DIRECTION OUTPUT ;
    USE SIGNAL ;
    PORT
      LAYER M5 ;
        RECT  131.856 0 131.88 0.084 ;
    END
  END q_o[70]
  PIN q_o[71]
    DIRECTION OUTPUT ;
    USE SIGNAL ;
    PORT
      LAYER M5 ;
        RECT  131.952 0 131.976 0.084 ;
    END
  END q_o[71]
  PIN q_o[72]
    DIRECTION OUTPUT ;
    USE SIGNAL ;
    PORT
      LAYER M5 ;
        RECT  132.048 0 132.072 0.084 ;
    END
  END q_o[72]
  PIN q_o[73]
    DIRECTION OUTPUT ;
    USE SIGNAL ;
    PORT
      LAYER M5 ;
        RECT  132.144 0 132.168 0.084 ;
    END
  END q_o[73]
  PIN q_o[74]
    DIRECTION OUTPUT ;
    USE SIGNAL ;
    PORT
      LAYER M5 ;
        RECT  132.24 0 132.264 0.084 ;
    END
  END q_o[74]
  PIN q_o[75]
    DIRECTION OUTPUT ;
    USE SIGNAL ;
    PORT
      LAYER M5 ;
        RECT  132.336 0 132.36 0.084 ;
    END
  END q_o[75]
  PIN q_o[76]
    DIRECTION OUTPUT ;
    USE SIGNAL ;
    PORT
      LAYER M5 ;
        RECT  132.432 0 132.456 0.084 ;
    END
  END q_o[76]
  PIN q_o[77]
    DIRECTION OUTPUT ;
    USE SIGNAL ;
    PORT
      LAYER M5 ;
        RECT  132.528 0 132.552 0.084 ;
    END
  END q_o[77]
  PIN q_o[78]
    DIRECTION OUTPUT ;
    USE SIGNAL ;
    PORT
      LAYER M5 ;
        RECT  132.624 0 132.648 0.084 ;
    END
  END q_o[78]
  PIN q_o[79]
    DIRECTION OUTPUT ;
    USE SIGNAL ;
    PORT
      LAYER M5 ;
        RECT  132.72 0 132.744 0.084 ;
    END
  END q_o[79]
  PIN q_o[7]
    DIRECTION OUTPUT ;
    USE SIGNAL ;
    PORT
      LAYER M5 ;
        RECT  125.808 0 125.832 0.084 ;
    END
  END q_o[7]
  PIN q_o[80]
    DIRECTION OUTPUT ;
    USE SIGNAL ;
    PORT
      LAYER M5 ;
        RECT  132.816 0 132.84 0.084 ;
    END
  END q_o[80]
  PIN q_o[81]
    DIRECTION OUTPUT ;
    USE SIGNAL ;
    PORT
      LAYER M5 ;
        RECT  132.912 0 132.936 0.084 ;
    END
  END q_o[81]
  PIN q_o[82]
    DIRECTION OUTPUT ;
    USE SIGNAL ;
    PORT
      LAYER M5 ;
        RECT  133.008 0 133.032 0.084 ;
    END
  END q_o[82]
  PIN q_o[83]
    DIRECTION OUTPUT ;
    USE SIGNAL ;
    PORT
      LAYER M5 ;
        RECT  133.104 0 133.128 0.084 ;
    END
  END q_o[83]
  PIN q_o[84]
    DIRECTION OUTPUT ;
    USE SIGNAL ;
    PORT
      LAYER M5 ;
        RECT  133.2 0 133.224 0.084 ;
    END
  END q_o[84]
  PIN q_o[85]
    DIRECTION OUTPUT ;
    USE SIGNAL ;
    PORT
      LAYER M5 ;
        RECT  133.296 0 133.32 0.084 ;
    END
  END q_o[85]
  PIN q_o[86]
    DIRECTION OUTPUT ;
    USE SIGNAL ;
    PORT
      LAYER M5 ;
        RECT  133.392 0 133.416 0.084 ;
    END
  END q_o[86]
  PIN q_o[87]
    DIRECTION OUTPUT ;
    USE SIGNAL ;
    PORT
      LAYER M5 ;
        RECT  133.488 0 133.512 0.084 ;
    END
  END q_o[87]
  PIN q_o[88]
    DIRECTION OUTPUT ;
    USE SIGNAL ;
    PORT
      LAYER M5 ;
        RECT  133.584 0 133.608 0.084 ;
    END
  END q_o[88]
  PIN q_o[89]
    DIRECTION OUTPUT ;
    USE SIGNAL ;
    PORT
      LAYER M5 ;
        RECT  133.68 0 133.704 0.084 ;
    END
  END q_o[89]
  PIN q_o[8]
    DIRECTION OUTPUT ;
    USE SIGNAL ;
    PORT
      LAYER M5 ;
        RECT  125.904 0 125.928 0.084 ;
    END
  END q_o[8]
  PIN q_o[90]
    DIRECTION OUTPUT ;
    USE SIGNAL ;
    PORT
      LAYER M5 ;
        RECT  133.776 0 133.8 0.084 ;
    END
  END q_o[90]
  PIN q_o[91]
    DIRECTION OUTPUT ;
    USE SIGNAL ;
    PORT
      LAYER M5 ;
        RECT  133.872 0 133.896 0.084 ;
    END
  END q_o[91]
  PIN q_o[92]
    DIRECTION OUTPUT ;
    USE SIGNAL ;
    PORT
      LAYER M5 ;
        RECT  133.968 0 133.992 0.084 ;
    END
  END q_o[92]
  PIN q_o[93]
    DIRECTION OUTPUT ;
    USE SIGNAL ;
    PORT
      LAYER M5 ;
        RECT  134.064 0 134.088 0.084 ;
    END
  END q_o[93]
  PIN q_o[94]
    DIRECTION OUTPUT ;
    USE SIGNAL ;
    PORT
      LAYER M5 ;
        RECT  134.16 0 134.184 0.084 ;
    END
  END q_o[94]
  PIN q_o[95]
    DIRECTION OUTPUT ;
    USE SIGNAL ;
    PORT
      LAYER M5 ;
        RECT  134.256 0 134.28 0.084 ;
    END
  END q_o[95]
  PIN q_o[96]
    DIRECTION OUTPUT ;
    USE SIGNAL ;
    PORT
      LAYER M5 ;
        RECT  118.992 0 119.016 0.084 ;
    END
  END q_o[96]
  PIN q_o[97]
    DIRECTION OUTPUT ;
    USE SIGNAL ;
    PORT
      LAYER M5 ;
        RECT  119.088 0 119.112 0.084 ;
    END
  END q_o[97]
  PIN q_o[98]
    DIRECTION OUTPUT ;
    USE SIGNAL ;
    PORT
      LAYER M5 ;
        RECT  119.184 0 119.208 0.084 ;
    END
  END q_o[98]
  PIN q_o[99]
    DIRECTION OUTPUT ;
    USE SIGNAL ;
    PORT
      LAYER M5 ;
        RECT  119.28 0 119.304 0.084 ;
    END
  END q_o[99]
  PIN q_o[9]
    DIRECTION OUTPUT ;
    USE SIGNAL ;
    PORT
      LAYER M5 ;
        RECT  126 0 126.024 0.084 ;
    END
  END q_o[9]
  PIN rst
    DIRECTION INPUT ;
    USE SIGNAL ;
    PORT
      LAYER M4 ;
        RECT  0 38.64 0.084 38.664 ;
    END
  END rst
  PIN t_a0[0]
    DIRECTION INPUT ;
    USE SIGNAL ;
    PORT
      LAYER M4 ;
        RECT  269.916 16.08 270 16.104 ;
    END
  END t_a0[0]
  PIN t_a0[10]
    DIRECTION INPUT ;
    USE SIGNAL ;
    PORT
      LAYER M4 ;
        RECT  269.916 17.04 270 17.064 ;
    END
  END t_a0[10]
  PIN t_a0[11]
    DIRECTION INPUT ;
    USE SIGNAL ;
    PORT
      LAYER M4 ;
        RECT  269.916 17.136 270 17.16 ;
    END
  END t_a0[11]
  PIN t_a0[12]
    DIRECTION INPUT ;
    USE SIGNAL ;
    PORT
      LAYER M4 ;
        RECT  269.916 17.232 270 17.256 ;
    END
  END t_a0[12]
  PIN t_a0[13]
    DIRECTION INPUT ;
    USE SIGNAL ;
    PORT
      LAYER M4 ;
        RECT  269.916 17.328 270 17.352 ;
    END
  END t_a0[13]
  PIN t_a0[14]
    DIRECTION INPUT ;
    USE SIGNAL ;
    PORT
      LAYER M4 ;
        RECT  269.916 17.424 270 17.448 ;
    END
  END t_a0[14]
  PIN t_a0[15]
    DIRECTION INPUT ;
    USE SIGNAL ;
    PORT
      LAYER M4 ;
        RECT  269.916 17.52 270 17.544 ;
    END
  END t_a0[15]
  PIN t_a0[16]
    DIRECTION INPUT ;
    USE SIGNAL ;
    PORT
      LAYER M4 ;
        RECT  269.916 17.616 270 17.64 ;
    END
  END t_a0[16]
  PIN t_a0[17]
    DIRECTION INPUT ;
    USE SIGNAL ;
    PORT
      LAYER M4 ;
        RECT  269.916 17.712 270 17.736 ;
    END
  END t_a0[17]
  PIN t_a0[18]
    DIRECTION INPUT ;
    USE SIGNAL ;
    PORT
      LAYER M4 ;
        RECT  269.916 17.808 270 17.832 ;
    END
  END t_a0[18]
  PIN t_a0[19]
    DIRECTION INPUT ;
    USE SIGNAL ;
    PORT
      LAYER M4 ;
        RECT  269.916 17.904 270 17.928 ;
    END
  END t_a0[19]
  PIN t_a0[1]
    DIRECTION INPUT ;
    USE SIGNAL ;
    PORT
      LAYER M4 ;
        RECT  269.916 16.176 270 16.2 ;
    END
  END t_a0[1]
  PIN t_a0[20]
    DIRECTION INPUT ;
    USE SIGNAL ;
    PORT
      LAYER M4 ;
        RECT  269.916 18 270 18.024 ;
    END
  END t_a0[20]
  PIN t_a0[21]
    DIRECTION INPUT ;
    USE SIGNAL ;
    PORT
      LAYER M4 ;
        RECT  269.916 18.096 270 18.12 ;
    END
  END t_a0[21]
  PIN t_a0[22]
    DIRECTION INPUT ;
    USE SIGNAL ;
    PORT
      LAYER M4 ;
        RECT  269.916 18.192 270 18.216 ;
    END
  END t_a0[22]
  PIN t_a0[23]
    DIRECTION INPUT ;
    USE SIGNAL ;
    PORT
      LAYER M4 ;
        RECT  269.916 18.288 270 18.312 ;
    END
  END t_a0[23]
  PIN t_a0[24]
    DIRECTION INPUT ;
    USE SIGNAL ;
    PORT
      LAYER M4 ;
        RECT  269.916 18.384 270 18.408 ;
    END
  END t_a0[24]
  PIN t_a0[25]
    DIRECTION INPUT ;
    USE SIGNAL ;
    PORT
      LAYER M4 ;
        RECT  269.916 18.48 270 18.504 ;
    END
  END t_a0[25]
  PIN t_a0[2]
    DIRECTION INPUT ;
    USE SIGNAL ;
    PORT
      LAYER M4 ;
        RECT  269.916 16.272 270 16.296 ;
    END
  END t_a0[2]
  PIN t_a0[3]
    DIRECTION INPUT ;
    USE SIGNAL ;
    PORT
      LAYER M4 ;
        RECT  269.916 16.368 270 16.392 ;
    END
  END t_a0[3]
  PIN t_a0[4]
    DIRECTION INPUT ;
    USE SIGNAL ;
    PORT
      LAYER M4 ;
        RECT  269.916 16.464 270 16.488 ;
    END
  END t_a0[4]
  PIN t_a0[5]
    DIRECTION INPUT ;
    USE SIGNAL ;
    PORT
      LAYER M4 ;
        RECT  269.916 16.56 270 16.584 ;
    END
  END t_a0[5]
  PIN t_a0[6]
    DIRECTION INPUT ;
    USE SIGNAL ;
    PORT
      LAYER M4 ;
        RECT  269.916 16.656 270 16.68 ;
    END
  END t_a0[6]
  PIN t_a0[7]
    DIRECTION INPUT ;
    USE SIGNAL ;
    PORT
      LAYER M4 ;
        RECT  269.916 16.752 270 16.776 ;
    END
  END t_a0[7]
  PIN t_a0[8]
    DIRECTION INPUT ;
    USE SIGNAL ;
    PORT
      LAYER M4 ;
        RECT  269.916 16.848 270 16.872 ;
    END
  END t_a0[8]
  PIN t_a0[9]
    DIRECTION INPUT ;
    USE SIGNAL ;
    PORT
      LAYER M4 ;
        RECT  269.916 16.944 270 16.968 ;
    END
  END t_a0[9]
  PIN t_a1[0]
    DIRECTION INPUT ;
    USE SIGNAL ;
    PORT
      LAYER M4 ;
        RECT  269.916 18.576 270 18.6 ;
    END
  END t_a1[0]
  PIN t_a1[10]
    DIRECTION INPUT ;
    USE SIGNAL ;
    PORT
      LAYER M4 ;
        RECT  269.916 20.304 270 20.328 ;
    END
  END t_a1[10]
  PIN t_a1[11]
    DIRECTION INPUT ;
    USE SIGNAL ;
    PORT
      LAYER M4 ;
        RECT  269.916 20.4 270 20.424 ;
    END
  END t_a1[11]
  PIN t_a1[12]
    DIRECTION INPUT ;
    USE SIGNAL ;
    PORT
      LAYER M4 ;
        RECT  269.916 20.496 270 20.52 ;
    END
  END t_a1[12]
  PIN t_a1[13]
    DIRECTION INPUT ;
    USE SIGNAL ;
    PORT
      LAYER M4 ;
        RECT  269.916 20.592 270 20.616 ;
    END
  END t_a1[13]
  PIN t_a1[14]
    DIRECTION INPUT ;
    USE SIGNAL ;
    PORT
      LAYER M4 ;
        RECT  269.916 20.688 270 20.712 ;
    END
  END t_a1[14]
  PIN t_a1[15]
    DIRECTION INPUT ;
    USE SIGNAL ;
    PORT
      LAYER M4 ;
        RECT  269.916 20.784 270 20.808 ;
    END
  END t_a1[15]
  PIN t_a1[16]
    DIRECTION INPUT ;
    USE SIGNAL ;
    PORT
      LAYER M4 ;
        RECT  269.916 20.88 270 20.904 ;
    END
  END t_a1[16]
  PIN t_a1[17]
    DIRECTION INPUT ;
    USE SIGNAL ;
    PORT
      LAYER M4 ;
        RECT  269.916 20.976 270 21 ;
    END
  END t_a1[17]
  PIN t_a1[18]
    DIRECTION INPUT ;
    USE SIGNAL ;
    PORT
      LAYER M4 ;
        RECT  269.916 21.072 270 21.096 ;
    END
  END t_a1[18]
  PIN t_a1[19]
    DIRECTION INPUT ;
    USE SIGNAL ;
    PORT
      LAYER M4 ;
        RECT  269.916 21.168 270 21.192 ;
    END
  END t_a1[19]
  PIN t_a1[1]
    DIRECTION INPUT ;
    USE SIGNAL ;
    PORT
      LAYER M4 ;
        RECT  269.916 18.672 270 18.696 ;
    END
  END t_a1[1]
  PIN t_a1[20]
    DIRECTION INPUT ;
    USE SIGNAL ;
    PORT
      LAYER M4 ;
        RECT  269.916 21.264 270 21.288 ;
    END
  END t_a1[20]
  PIN t_a1[21]
    DIRECTION INPUT ;
    USE SIGNAL ;
    PORT
      LAYER M4 ;
        RECT  269.916 21.36 270 21.384 ;
    END
  END t_a1[21]
  PIN t_a1[22]
    DIRECTION INPUT ;
    USE SIGNAL ;
    PORT
      LAYER M4 ;
        RECT  269.916 21.456 270 21.48 ;
    END
  END t_a1[22]
  PIN t_a1[23]
    DIRECTION INPUT ;
    USE SIGNAL ;
    PORT
      LAYER M4 ;
        RECT  269.916 21.552 270 21.576 ;
    END
  END t_a1[23]
  PIN t_a1[24]
    DIRECTION INPUT ;
    USE SIGNAL ;
    PORT
      LAYER M4 ;
        RECT  269.916 21.648 270 21.672 ;
    END
  END t_a1[24]
  PIN t_a1[25]
    DIRECTION INPUT ;
    USE SIGNAL ;
    PORT
      LAYER M4 ;
        RECT  269.916 21.744 270 21.768 ;
    END
  END t_a1[25]
  PIN t_a1[2]
    DIRECTION INPUT ;
    USE SIGNAL ;
    PORT
      LAYER M4 ;
        RECT  269.916 18.768 270 18.792 ;
    END
  END t_a1[2]
  PIN t_a1[3]
    DIRECTION INPUT ;
    USE SIGNAL ;
    PORT
      LAYER M4 ;
        RECT  269.916 18.864 270 18.888 ;
    END
  END t_a1[3]
  PIN t_a1[4]
    DIRECTION INPUT ;
    USE SIGNAL ;
    PORT
      LAYER M4 ;
        RECT  269.916 18.96 270 18.984 ;
    END
  END t_a1[4]
  PIN t_a1[5]
    DIRECTION INPUT ;
    USE SIGNAL ;
    PORT
      LAYER M4 ;
        RECT  269.916 19.056 270 19.08 ;
    END
  END t_a1[5]
  PIN t_a1[6]
    DIRECTION INPUT ;
    USE SIGNAL ;
    PORT
      LAYER M4 ;
        RECT  269.916 19.92 270 19.944 ;
    END
  END t_a1[6]
  PIN t_a1[7]
    DIRECTION INPUT ;
    USE SIGNAL ;
    PORT
      LAYER M4 ;
        RECT  269.916 20.016 270 20.04 ;
    END
  END t_a1[7]
  PIN t_a1[8]
    DIRECTION INPUT ;
    USE SIGNAL ;
    PORT
      LAYER M4 ;
        RECT  269.916 20.112 270 20.136 ;
    END
  END t_a1[8]
  PIN t_a1[9]
    DIRECTION INPUT ;
    USE SIGNAL ;
    PORT
      LAYER M4 ;
        RECT  269.916 20.208 270 20.232 ;
    END
  END t_a1[9]
  PIN t_od[0]
    DIRECTION INPUT ;
    USE SIGNAL ;
    PORT
      LAYER M4 ;
        RECT  269.916 21.84 270 21.864 ;
    END
  END t_od[0]
  PIN t_od[10]
    DIRECTION INPUT ;
    USE SIGNAL ;
    PORT
      LAYER M4 ;
        RECT  269.916 22.8 270 22.824 ;
    END
  END t_od[10]
  PIN t_od[11]
    DIRECTION INPUT ;
    USE SIGNAL ;
    PORT
      LAYER M4 ;
        RECT  269.916 22.896 270 22.92 ;
    END
  END t_od[11]
  PIN t_od[12]
    DIRECTION INPUT ;
    USE SIGNAL ;
    PORT
      LAYER M4 ;
        RECT  269.916 29.136 270 29.16 ;
    END
  END t_od[12]
  PIN t_od[13]
    DIRECTION INPUT ;
    USE SIGNAL ;
    PORT
      LAYER M4 ;
        RECT  269.916 29.232 270 29.256 ;
    END
  END t_od[13]
  PIN t_od[14]
    DIRECTION INPUT ;
    USE SIGNAL ;
    PORT
      LAYER M4 ;
        RECT  269.916 29.328 270 29.352 ;
    END
  END t_od[14]
  PIN t_od[15]
    DIRECTION INPUT ;
    USE SIGNAL ;
    PORT
      LAYER M4 ;
        RECT  269.916 29.424 270 29.448 ;
    END
  END t_od[15]
  PIN t_od[16]
    DIRECTION INPUT ;
    USE SIGNAL ;
    PORT
      LAYER M4 ;
        RECT  269.916 29.52 270 29.544 ;
    END
  END t_od[16]
  PIN t_od[17]
    DIRECTION INPUT ;
    USE SIGNAL ;
    PORT
      LAYER M4 ;
        RECT  269.916 29.616 270 29.64 ;
    END
  END t_od[17]
  PIN t_od[18]
    DIRECTION INPUT ;
    USE SIGNAL ;
    PORT
      LAYER M4 ;
        RECT  269.916 29.712 270 29.736 ;
    END
  END t_od[18]
  PIN t_od[19]
    DIRECTION INPUT ;
    USE SIGNAL ;
    PORT
      LAYER M4 ;
        RECT  269.916 29.808 270 29.832 ;
    END
  END t_od[19]
  PIN t_od[1]
    DIRECTION INPUT ;
    USE SIGNAL ;
    PORT
      LAYER M4 ;
        RECT  269.916 21.936 270 21.96 ;
    END
  END t_od[1]
  PIN t_od[20]
    DIRECTION INPUT ;
    USE SIGNAL ;
    PORT
      LAYER M4 ;
        RECT  269.916 29.904 270 29.928 ;
    END
  END t_od[20]
  PIN t_od[21]
    DIRECTION INPUT ;
    USE SIGNAL ;
    PORT
      LAYER M4 ;
        RECT  269.916 30 270 30.024 ;
    END
  END t_od[21]
  PIN t_od[22]
    DIRECTION INPUT ;
    USE SIGNAL ;
    PORT
      LAYER M4 ;
        RECT  269.916 30.096 270 30.12 ;
    END
  END t_od[22]
  PIN t_od[23]
    DIRECTION INPUT ;
    USE SIGNAL ;
    PORT
      LAYER M4 ;
        RECT  269.916 30.192 270 30.216 ;
    END
  END t_od[23]
  PIN t_od[24]
    DIRECTION INPUT ;
    USE SIGNAL ;
    PORT
      LAYER M4 ;
        RECT  269.916 30.288 270 30.312 ;
    END
  END t_od[24]
  PIN t_od[25]
    DIRECTION INPUT ;
    USE SIGNAL ;
    PORT
      LAYER M4 ;
        RECT  269.916 30.384 270 30.408 ;
    END
  END t_od[25]
  PIN t_od[2]
    DIRECTION INPUT ;
    USE SIGNAL ;
    PORT
      LAYER M4 ;
        RECT  269.916 22.032 270 22.056 ;
    END
  END t_od[2]
  PIN t_od[3]
    DIRECTION INPUT ;
    USE SIGNAL ;
    PORT
      LAYER M4 ;
        RECT  269.916 22.128 270 22.152 ;
    END
  END t_od[3]
  PIN t_od[4]
    DIRECTION INPUT ;
    USE SIGNAL ;
    PORT
      LAYER M4 ;
        RECT  269.916 22.224 270 22.248 ;
    END
  END t_od[4]
  PIN t_od[5]
    DIRECTION INPUT ;
    USE SIGNAL ;
    PORT
      LAYER M4 ;
        RECT  269.916 22.32 270 22.344 ;
    END
  END t_od[5]
  PIN t_od[6]
    DIRECTION INPUT ;
    USE SIGNAL ;
    PORT
      LAYER M4 ;
        RECT  269.916 22.416 270 22.44 ;
    END
  END t_od[6]
  PIN t_od[7]
    DIRECTION INPUT ;
    USE SIGNAL ;
    PORT
      LAYER M4 ;
        RECT  269.916 22.512 270 22.536 ;
    END
  END t_od[7]
  PIN t_od[8]
    DIRECTION INPUT ;
    USE SIGNAL ;
    PORT
      LAYER M4 ;
        RECT  269.916 22.608 270 22.632 ;
    END
  END t_od[8]
  PIN t_od[9]
    DIRECTION INPUT ;
    USE SIGNAL ;
    PORT
      LAYER M4 ;
        RECT  269.916 22.704 270 22.728 ;
    END
  END t_od[9]
  PIN t_x[0]
    DIRECTION INPUT ;
    USE SIGNAL ;
    PORT
      LAYER M4 ;
        RECT  269.916 30.48 270 30.504 ;
    END
  END t_x[0]
  PIN t_x[10]
    DIRECTION INPUT ;
    USE SIGNAL ;
    PORT
      LAYER M4 ;
        RECT  269.916 31.44 270 31.464 ;
    END
  END t_x[10]
  PIN t_x[11]
    DIRECTION INPUT ;
    USE SIGNAL ;
    PORT
      LAYER M4 ;
        RECT  269.916 31.536 270 31.56 ;
    END
  END t_x[11]
  PIN t_x[12]
    DIRECTION INPUT ;
    USE SIGNAL ;
    PORT
      LAYER M4 ;
        RECT  269.916 31.632 270 31.656 ;
    END
  END t_x[12]
  PIN t_x[13]
    DIRECTION INPUT ;
    USE SIGNAL ;
    PORT
      LAYER M4 ;
        RECT  269.916 31.728 270 31.752 ;
    END
  END t_x[13]
  PIN t_x[14]
    DIRECTION INPUT ;
    USE SIGNAL ;
    PORT
      LAYER M4 ;
        RECT  269.916 31.824 270 31.848 ;
    END
  END t_x[14]
  PIN t_x[15]
    DIRECTION INPUT ;
    USE SIGNAL ;
    PORT
      LAYER M4 ;
        RECT  269.916 31.92 270 31.944 ;
    END
  END t_x[15]
  PIN t_x[16]
    DIRECTION INPUT ;
    USE SIGNAL ;
    PORT
      LAYER M4 ;
        RECT  269.916 32.016 270 32.04 ;
    END
  END t_x[16]
  PIN t_x[17]
    DIRECTION INPUT ;
    USE SIGNAL ;
    PORT
      LAYER M4 ;
        RECT  269.916 32.112 270 32.136 ;
    END
  END t_x[17]
  PIN t_x[18]
    DIRECTION INPUT ;
    USE SIGNAL ;
    PORT
      LAYER M4 ;
        RECT  269.916 19.152 270 19.176 ;
    END
  END t_x[18]
  PIN t_x[19]
    DIRECTION INPUT ;
    USE SIGNAL ;
    PORT
      LAYER M4 ;
        RECT  269.916 19.248 270 19.272 ;
    END
  END t_x[19]
  PIN t_x[1]
    DIRECTION INPUT ;
    USE SIGNAL ;
    PORT
      LAYER M4 ;
        RECT  269.916 30.576 270 30.6 ;
    END
  END t_x[1]
  PIN t_x[20]
    DIRECTION INPUT ;
    USE SIGNAL ;
    PORT
      LAYER M4 ;
        RECT  269.916 19.344 270 19.368 ;
    END
  END t_x[20]
  PIN t_x[21]
    DIRECTION INPUT ;
    USE SIGNAL ;
    PORT
      LAYER M4 ;
        RECT  269.916 19.44 270 19.464 ;
    END
  END t_x[21]
  PIN t_x[22]
    DIRECTION INPUT ;
    USE SIGNAL ;
    PORT
      LAYER M4 ;
        RECT  269.916 19.536 270 19.56 ;
    END
  END t_x[22]
  PIN t_x[23]
    DIRECTION INPUT ;
    USE SIGNAL ;
    PORT
      LAYER M4 ;
        RECT  269.916 19.632 270 19.656 ;
    END
  END t_x[23]
  PIN t_x[24]
    DIRECTION INPUT ;
    USE SIGNAL ;
    PORT
      LAYER M4 ;
        RECT  269.916 19.728 270 19.752 ;
    END
  END t_x[24]
  PIN t_x[25]
    DIRECTION INPUT ;
    USE SIGNAL ;
    PORT
      LAYER M4 ;
        RECT  269.916 19.824 270 19.848 ;
    END
  END t_x[25]
  PIN t_x[2]
    DIRECTION INPUT ;
    USE SIGNAL ;
    PORT
      LAYER M4 ;
        RECT  269.916 30.672 270 30.696 ;
    END
  END t_x[2]
  PIN t_x[3]
    DIRECTION INPUT ;
    USE SIGNAL ;
    PORT
      LAYER M4 ;
        RECT  269.916 30.768 270 30.792 ;
    END
  END t_x[3]
  PIN t_x[4]
    DIRECTION INPUT ;
    USE SIGNAL ;
    PORT
      LAYER M4 ;
        RECT  269.916 30.864 270 30.888 ;
    END
  END t_x[4]
  PIN t_x[5]
    DIRECTION INPUT ;
    USE SIGNAL ;
    PORT
      LAYER M4 ;
        RECT  269.916 30.96 270 30.984 ;
    END
  END t_x[5]
  PIN t_x[6]
    DIRECTION INPUT ;
    USE SIGNAL ;
    PORT
      LAYER M4 ;
        RECT  269.916 31.056 270 31.08 ;
    END
  END t_x[6]
  PIN t_x[7]
    DIRECTION INPUT ;
    USE SIGNAL ;
    PORT
      LAYER M4 ;
        RECT  269.916 31.152 270 31.176 ;
    END
  END t_x[7]
  PIN t_x[8]
    DIRECTION INPUT ;
    USE SIGNAL ;
    PORT
      LAYER M4 ;
        RECT  269.916 31.248 270 31.272 ;
    END
  END t_x[8]
  PIN t_x[9]
    DIRECTION INPUT ;
    USE SIGNAL ;
    PORT
      LAYER M4 ;
        RECT  269.916 31.344 270 31.368 ;
    END
  END t_x[9]
  PIN VDD
    DIRECTION INOUT ;
    USE POWER ;
    PORT
      LAYER M5 ;
        RECT  267.192 2.151 267.312 62.649 ;
        RECT  261.792 2.151 261.912 62.649 ;
        RECT  256.392 2.151 256.512 62.649 ;
        RECT  250.992 2.151 251.112 62.649 ;
        RECT  245.592 2.151 245.712 62.649 ;
        RECT  240.192 2.151 240.312 62.649 ;
        RECT  234.792 2.151 234.912 62.649 ;
        RECT  229.392 2.151 229.512 62.649 ;
        RECT  223.992 2.151 224.112 62.649 ;
        RECT  218.592 2.151 218.712 62.649 ;
        RECT  213.192 2.151 213.312 62.649 ;
        RECT  207.792 2.151 207.912 62.649 ;
        RECT  202.392 2.151 202.512 62.649 ;
        RECT  196.992 2.151 197.112 62.649 ;
        RECT  191.592 2.151 191.712 62.649 ;
        RECT  186.192 2.151 186.312 62.649 ;
        RECT  180.792 2.151 180.912 62.649 ;
        RECT  175.392 2.151 175.512 62.649 ;
        RECT  169.992 2.151 170.112 62.649 ;
        RECT  164.592 2.151 164.712 62.649 ;
        RECT  159.192 2.151 159.312 62.649 ;
        RECT  153.792 2.151 153.912 62.649 ;
        RECT  148.392 2.151 148.512 62.649 ;
        RECT  142.992 2.151 143.112 62.649 ;
        RECT  137.592 2.151 137.712 62.649 ;
        RECT  132.192 2.151 132.312 62.649 ;
        RECT  126.792 2.151 126.912 62.649 ;
        RECT  121.392 2.151 121.512 62.649 ;
        RECT  115.992 2.151 116.112 62.649 ;
        RECT  110.592 2.151 110.712 62.649 ;
        RECT  105.192 2.151 105.312 62.649 ;
        RECT  99.792 2.151 99.912 62.649 ;
        RECT  94.392 2.151 94.512 62.649 ;
        RECT  88.992 2.151 89.112 62.649 ;
        RECT  83.592 2.151 83.712 62.649 ;
        RECT  78.192 2.151 78.312 62.649 ;
        RECT  72.792 2.151 72.912 62.649 ;
        RECT  67.392 2.151 67.512 62.649 ;
        RECT  61.992 2.151 62.112 62.649 ;
        RECT  56.592 2.151 56.712 62.649 ;
        RECT  51.192 2.151 51.312 62.649 ;
        RECT  45.792 2.151 45.912 62.649 ;
        RECT  40.392 2.151 40.512 62.649 ;
        RECT  34.992 2.151 35.112 62.649 ;
        RECT  29.592 2.151 29.712 62.649 ;
        RECT  24.192 2.151 24.312 62.649 ;
        RECT  18.792 2.151 18.912 62.649 ;
        RECT  13.392 2.151 13.512 62.649 ;
        RECT  7.992 2.151 8.112 62.649 ;
        RECT  2.592 2.151 2.712 62.649 ;
    END
  END VDD
  PIN VSS
    DIRECTION INOUT ;
    USE GROUND ;
    PORT
      LAYER M5 ;
        RECT  267 2.137 267.12 62.663 ;
        RECT  261.6 2.137 261.72 62.663 ;
        RECT  256.2 2.137 256.32 62.663 ;
        RECT  250.8 2.137 250.92 62.663 ;
        RECT  245.4 2.137 245.52 62.663 ;
        RECT  240 2.137 240.12 62.663 ;
        RECT  234.6 2.137 234.72 62.663 ;
        RECT  229.2 2.137 229.32 62.663 ;
        RECT  223.8 2.137 223.92 62.663 ;
        RECT  218.4 2.137 218.52 62.663 ;
        RECT  213 2.137 213.12 62.663 ;
        RECT  207.6 2.137 207.72 62.663 ;
        RECT  202.2 2.137 202.32 62.663 ;
        RECT  196.8 2.137 196.92 62.663 ;
        RECT  191.4 2.137 191.52 62.663 ;
        RECT  186 2.137 186.12 62.663 ;
        RECT  180.6 2.137 180.72 62.663 ;
        RECT  175.2 2.137 175.32 62.663 ;
        RECT  169.8 2.137 169.92 62.663 ;
        RECT  164.4 2.137 164.52 62.663 ;
        RECT  159 2.137 159.12 62.663 ;
        RECT  153.6 2.137 153.72 62.663 ;
        RECT  148.2 2.137 148.32 62.663 ;
        RECT  142.8 2.137 142.92 62.663 ;
        RECT  137.4 2.137 137.52 62.663 ;
        RECT  132 2.137 132.12 62.663 ;
        RECT  126.6 2.137 126.72 62.663 ;
        RECT  121.2 2.137 121.32 62.663 ;
        RECT  115.8 2.137 115.92 62.663 ;
        RECT  110.4 2.137 110.52 62.663 ;
        RECT  105 2.137 105.12 62.663 ;
        RECT  99.6 2.137 99.72 62.663 ;
        RECT  94.2 2.137 94.32 62.663 ;
        RECT  88.8 2.137 88.92 62.663 ;
        RECT  83.4 2.137 83.52 62.663 ;
        RECT  78 2.137 78.12 62.663 ;
        RECT  72.6 2.137 72.72 62.663 ;
        RECT  67.2 2.137 67.32 62.663 ;
        RECT  61.8 2.137 61.92 62.663 ;
        RECT  56.4 2.137 56.52 62.663 ;
        RECT  51 2.137 51.12 62.663 ;
        RECT  45.6 2.137 45.72 62.663 ;
        RECT  40.2 2.137 40.32 62.663 ;
        RECT  34.8 2.137 34.92 62.663 ;
        RECT  29.4 2.137 29.52 62.663 ;
        RECT  24 2.137 24.12 62.663 ;
        RECT  18.6 2.137 18.72 62.663 ;
        RECT  13.2 2.137 13.32 62.663 ;
        RECT  7.8 2.137 7.92 62.663 ;
        RECT  2.4 2.137 2.52 62.663 ;
    END
  END VSS
  OBS
    LAYER RVTN ;
     RECT  2.16 2.16 267.84 2.295 ;
     RECT  2.16 2.565 267.84 2.835 ;
     RECT  2.16 3.105 267.84 3.375 ;
     RECT  2.16 3.645 267.84 3.915 ;
     RECT  2.16 4.185 267.84 4.455 ;
     RECT  2.16 4.725 267.84 4.995 ;
     RECT  2.16 5.265 267.84 5.535 ;
     RECT  2.16 5.805 267.84 6.075 ;
     RECT  2.16 6.345 267.84 6.615 ;
     RECT  2.16 6.885 267.84 7.155 ;
     RECT  2.16 7.425 267.84 7.695 ;
     RECT  2.16 7.965 267.84 8.235 ;
     RECT  2.16 8.505 267.84 8.775 ;
     RECT  2.16 9.045 267.84 9.315 ;
     RECT  2.16 9.585 267.84 9.855 ;
     RECT  2.16 10.125 267.84 10.395 ;
     RECT  2.16 10.665 267.84 10.935 ;
     RECT  2.16 11.205 267.84 11.475 ;
     RECT  2.16 11.745 267.84 12.015 ;
     RECT  2.16 12.285 267.84 12.555 ;
     RECT  2.16 12.825 267.84 13.095 ;
     RECT  2.16 13.365 267.84 13.635 ;
     RECT  2.16 13.905 267.84 14.175 ;
     RECT  2.16 14.445 267.84 14.715 ;
     RECT  2.16 14.985 267.84 15.255 ;
     RECT  2.16 15.525 267.84 15.795 ;
     RECT  2.16 16.065 267.84 16.335 ;
     RECT  2.16 16.605 267.84 16.875 ;
     RECT  2.16 17.145 267.84 17.415 ;
     RECT  2.16 17.685 267.84 17.955 ;
     RECT  2.16 18.225 267.84 18.495 ;
     RECT  2.16 18.765 267.84 19.035 ;
     RECT  2.16 19.305 267.84 19.575 ;
     RECT  2.16 19.845 267.84 20.115 ;
     RECT  2.16 20.385 267.84 20.655 ;
     RECT  2.16 20.925 267.84 21.195 ;
     RECT  2.16 21.465 267.84 21.735 ;
     RECT  2.16 22.005 267.84 22.275 ;
     RECT  2.16 22.545 267.84 22.815 ;
     RECT  2.16 23.085 267.84 23.355 ;
     RECT  2.16 23.625 267.84 23.895 ;
     RECT  2.16 24.165 267.84 24.435 ;
     RECT  2.16 24.705 267.84 24.975 ;
     RECT  2.16 25.245 267.84 25.515 ;
     RECT  2.16 25.785 267.84 26.055 ;
     RECT  2.16 26.325 267.84 26.595 ;
     RECT  2.16 26.865 267.84 27.135 ;
     RECT  2.16 27.405 267.84 27.675 ;
     RECT  2.16 27.945 267.84 28.215 ;
     RECT  2.16 28.485 267.84 28.755 ;
     RECT  2.16 29.025 267.84 29.295 ;
     RECT  2.16 29.565 267.84 29.835 ;
     RECT  2.16 30.105 267.84 30.375 ;
     RECT  2.16 30.645 267.84 30.915 ;
     RECT  2.16 31.185 267.84 31.455 ;
     RECT  2.16 31.725 267.84 31.995 ;
     RECT  2.16 32.265 267.84 32.535 ;
     RECT  2.16 32.805 267.84 33.075 ;
     RECT  2.16 33.345 267.84 33.615 ;
     RECT  2.16 33.885 267.84 34.155 ;
     RECT  2.16 34.425 267.84 34.695 ;
     RECT  2.16 34.965 267.84 35.235 ;
     RECT  2.16 35.505 267.84 35.775 ;
     RECT  2.16 36.045 267.84 36.315 ;
     RECT  2.16 36.585 267.84 36.855 ;
     RECT  2.16 37.125 267.84 37.395 ;
     RECT  2.16 37.665 267.84 37.935 ;
     RECT  2.16 38.205 267.84 38.475 ;
     RECT  2.16 38.745 267.84 39.015 ;
     RECT  2.16 39.285 267.84 39.555 ;
     RECT  2.16 39.825 267.84 40.095 ;
     RECT  2.16 40.365 267.84 40.635 ;
     RECT  2.16 40.905 267.84 41.175 ;
     RECT  2.16 41.445 267.84 41.715 ;
     RECT  2.16 41.985 267.84 42.255 ;
     RECT  2.16 42.525 267.84 42.795 ;
     RECT  2.16 43.065 267.84 43.335 ;
     RECT  2.16 43.605 267.84 43.875 ;
     RECT  2.16 44.145 267.84 44.415 ;
     RECT  2.16 44.685 267.84 44.955 ;
     RECT  2.16 45.225 267.84 45.495 ;
     RECT  2.16 45.765 267.84 46.035 ;
     RECT  2.16 46.305 267.84 46.575 ;
     RECT  2.16 46.845 267.84 47.115 ;
     RECT  2.16 47.385 267.84 47.655 ;
     RECT  2.16 47.925 267.84 48.195 ;
     RECT  2.16 48.465 267.84 48.735 ;
     RECT  2.16 49.005 267.84 49.275 ;
     RECT  2.16 49.545 267.84 49.815 ;
     RECT  2.16 50.085 267.84 50.355 ;
     RECT  2.16 50.625 267.84 50.895 ;
     RECT  2.16 51.165 267.84 51.435 ;
     RECT  2.16 51.705 267.84 51.975 ;
     RECT  2.16 52.245 267.84 52.515 ;
     RECT  2.16 52.785 267.84 53.055 ;
     RECT  2.16 53.325 267.84 53.595 ;
     RECT  2.16 53.865 267.84 54.135 ;
     RECT  2.16 54.405 267.84 54.675 ;
     RECT  2.16 54.945 267.84 55.215 ;
     RECT  2.16 55.485 267.84 55.755 ;
     RECT  2.16 56.025 267.84 56.295 ;
     RECT  2.16 56.565 267.84 56.835 ;
     RECT  2.16 57.105 267.84 57.375 ;
     RECT  2.16 57.645 267.84 57.915 ;
     RECT  2.16 58.185 267.84 58.455 ;
     RECT  2.16 58.725 267.84 58.995 ;
     RECT  2.16 59.265 267.84 59.535 ;
     RECT  2.16 59.805 267.84 60.075 ;
     RECT  2.16 60.345 267.84 60.615 ;
     RECT  2.16 60.885 267.84 61.155 ;
     RECT  2.16 61.425 267.84 61.695 ;
     RECT  2.16 61.965 267.84 62.235 ;
     RECT  2.16 62.505 267.84 62.64 ;
    LAYER RVTP ;
     RECT  2.16 2.295 267.84 2.565 ;
     RECT  2.16 2.835 267.84 3.105 ;
     RECT  2.16 3.375 267.84 3.645 ;
     RECT  2.16 3.915 267.84 4.185 ;
     RECT  2.16 4.455 267.84 4.725 ;
     RECT  2.16 4.995 267.84 5.265 ;
     RECT  2.16 5.535 267.84 5.805 ;
     RECT  2.16 6.075 267.84 6.345 ;
     RECT  2.16 6.615 267.84 6.885 ;
     RECT  2.16 7.155 267.84 7.425 ;
     RECT  2.16 7.695 267.84 7.965 ;
     RECT  2.16 8.235 267.84 8.505 ;
     RECT  2.16 8.775 267.84 9.045 ;
     RECT  2.16 9.315 267.84 9.585 ;
     RECT  2.16 9.855 267.84 10.125 ;
     RECT  2.16 10.395 267.84 10.665 ;
     RECT  2.16 10.935 267.84 11.205 ;
     RECT  2.16 11.475 267.84 11.745 ;
     RECT  2.16 12.015 267.84 12.285 ;
     RECT  2.16 12.555 267.84 12.825 ;
     RECT  2.16 13.095 267.84 13.365 ;
     RECT  2.16 13.635 267.84 13.905 ;
     RECT  2.16 14.175 267.84 14.445 ;
     RECT  2.16 14.715 267.84 14.985 ;
     RECT  2.16 15.255 267.84 15.525 ;
     RECT  2.16 15.795 267.84 16.065 ;
     RECT  2.16 16.335 267.84 16.605 ;
     RECT  2.16 16.875 267.84 17.145 ;
     RECT  2.16 17.415 267.84 17.685 ;
     RECT  2.16 17.955 267.84 18.225 ;
     RECT  2.16 18.495 267.84 18.765 ;
     RECT  2.16 19.035 267.84 19.305 ;
     RECT  2.16 19.575 267.84 19.845 ;
     RECT  2.16 20.115 267.84 20.385 ;
     RECT  2.16 20.655 267.84 20.925 ;
     RECT  2.16 21.195 267.84 21.465 ;
     RECT  2.16 21.735 267.84 22.005 ;
     RECT  2.16 22.275 267.84 22.545 ;
     RECT  2.16 22.815 267.84 23.085 ;
     RECT  2.16 23.355 267.84 23.625 ;
     RECT  2.16 23.895 267.84 24.165 ;
     RECT  2.16 24.435 267.84 24.705 ;
     RECT  2.16 24.975 267.84 25.245 ;
     RECT  2.16 25.515 267.84 25.785 ;
     RECT  2.16 26.055 267.84 26.325 ;
     RECT  2.16 26.595 267.84 26.865 ;
     RECT  2.16 27.135 267.84 27.405 ;
     RECT  2.16 27.675 267.84 27.945 ;
     RECT  2.16 28.215 267.84 28.485 ;
     RECT  2.16 28.755 267.84 29.025 ;
     RECT  2.16 29.295 267.84 29.565 ;
     RECT  2.16 29.835 267.84 30.105 ;
     RECT  2.16 30.375 267.84 30.645 ;
     RECT  2.16 30.915 267.84 31.185 ;
     RECT  2.16 31.455 267.84 31.725 ;
     RECT  2.16 31.995 267.84 32.265 ;
     RECT  2.16 32.535 267.84 32.805 ;
     RECT  2.16 33.075 267.84 33.345 ;
     RECT  2.16 33.615 267.84 33.885 ;
     RECT  2.16 34.155 267.84 34.425 ;
     RECT  2.16 34.695 267.84 34.965 ;
     RECT  2.16 35.235 267.84 35.505 ;
     RECT  2.16 35.775 267.84 36.045 ;
     RECT  2.16 36.315 267.84 36.585 ;
     RECT  2.16 36.855 267.84 37.125 ;
     RECT  2.16 37.395 267.84 37.665 ;
     RECT  2.16 37.935 267.84 38.205 ;
     RECT  2.16 38.475 267.84 38.745 ;
     RECT  2.16 39.015 267.84 39.285 ;
     RECT  2.16 39.555 267.84 39.825 ;
     RECT  2.16 40.095 267.84 40.365 ;
     RECT  2.16 40.635 267.84 40.905 ;
     RECT  2.16 41.175 267.84 41.445 ;
     RECT  2.16 41.715 267.84 41.985 ;
     RECT  2.16 42.255 267.84 42.525 ;
     RECT  2.16 42.795 267.84 43.065 ;
     RECT  2.16 43.335 267.84 43.605 ;
     RECT  2.16 43.875 267.84 44.145 ;
     RECT  2.16 44.415 267.84 44.685 ;
     RECT  2.16 44.955 267.84 45.225 ;
     RECT  2.16 45.495 267.84 45.765 ;
     RECT  2.16 46.035 267.84 46.305 ;
     RECT  2.16 46.575 267.84 46.845 ;
     RECT  2.16 47.115 267.84 47.385 ;
     RECT  2.16 47.655 267.84 47.925 ;
     RECT  2.16 48.195 267.84 48.465 ;
     RECT  2.16 48.735 267.84 49.005 ;
     RECT  2.16 49.275 267.84 49.545 ;
     RECT  2.16 49.815 267.84 50.085 ;
     RECT  2.16 50.355 267.84 50.625 ;
     RECT  2.16 50.895 267.84 51.165 ;
     RECT  2.16 51.435 267.84 51.705 ;
     RECT  2.16 51.975 267.84 52.245 ;
     RECT  2.16 52.515 267.84 52.785 ;
     RECT  2.16 53.055 267.84 53.325 ;
     RECT  2.16 53.595 267.84 53.865 ;
     RECT  2.16 54.135 267.84 54.405 ;
     RECT  2.16 54.675 267.84 54.945 ;
     RECT  2.16 55.215 267.84 55.485 ;
     RECT  2.16 55.755 267.84 56.025 ;
     RECT  2.16 56.295 267.84 56.565 ;
     RECT  2.16 56.835 267.84 57.105 ;
     RECT  2.16 57.375 267.84 57.645 ;
     RECT  2.16 57.915 267.84 58.185 ;
     RECT  2.16 58.455 267.84 58.725 ;
     RECT  2.16 58.995 267.84 59.265 ;
     RECT  2.16 59.535 267.84 59.805 ;
     RECT  2.16 60.075 267.84 60.345 ;
     RECT  2.16 60.615 267.84 60.885 ;
     RECT  2.16 61.155 267.84 61.425 ;
     RECT  2.16 61.695 267.84 61.965 ;
     RECT  2.16 62.235 267.84 62.505 ;
    LAYER M1 ;
     RECT  2.16 2.151 267.84 62.649 ;
    LAYER M2 ;
     RECT  0.031 30.654 0.103 30.672 ;
     RECT  0.031 34.866 0.103 34.884 ;
     RECT  0.103 34.776 0.131 34.884 ;
     RECT  0.103 39.024 0.139 39.042 ;
     RECT  0.103 30.654 0.175 31.212 ;
     RECT  0.131 34.776 0.239 34.794 ;
     RECT  0.139 38.754 0.283 39.042 ;
     RECT  0.283 38.601 0.535 39.042 ;
     RECT  0.535 38.601 1.075 39.114 ;
     RECT  1.075 38.016 2.155 39.114 ;
     RECT  0.175 30.654 2.16 31.446 ;
     RECT  2.155 38.016 2.16 39.312 ;
     RECT  2.155 43.074 2.16 43.092 ;
     RECT  2.16 2.151 90.787 62.649 ;
     RECT  90.787 2.106 91.751 62.649 ;
     RECT  91.751 2.151 97.123 62.649 ;
     RECT  97.123 2.106 97.871 62.649 ;
     RECT  97.871 2.151 104.143 62.649 ;
     RECT  104.143 2.106 105.187 62.649 ;
     RECT  105.187 2.034 109.571 62.649 ;
     RECT  109.571 2.151 113.719 62.649 ;
     RECT  113.719 2.106 114.539 62.649 ;
     RECT  114.539 2.151 116.635 62.649 ;
     RECT  116.635 2.106 117.671 62.649 ;
     RECT  117.671 2.151 121.891 62.649 ;
     RECT  121.891 2.106 122.531 62.649 ;
     RECT  124.087 1.152 124.187 1.17 ;
     RECT  122.531 2.151 126.751 62.649 ;
     RECT  126.751 2.106 129.703 62.649 ;
     RECT  129.703 2.07 130.091 62.649 ;
     RECT  130.891 1.152 130.991 1.17 ;
     RECT  130.091 2.106 131.135 62.649 ;
     RECT  132.367 1.152 132.467 1.17 ;
     RECT  131.135 2.151 267.84 62.649 ;
     RECT  267.84 15.84 267.863 24.12 ;
     RECT  267.84 29.34 267.863 33.84 ;
     RECT  267.863 29.34 267.899 33.3 ;
     RECT  267.899 29.34 269.051 31.014 ;
     RECT  267.863 15.84 269.087 23.58 ;
     RECT  269.051 29.34 269.087 29.79 ;
     RECT  269.051 30.654 269.087 31.014 ;
     RECT  269.087 16.002 269.123 17.136 ;
     RECT  269.087 17.928 269.123 22.536 ;
     RECT  269.123 20.862 269.807 22.536 ;
     RECT  269.807 21.942 269.815 22.536 ;
     RECT  269.087 23.292 269.815 23.58 ;
     RECT  269.123 16.542 269.843 17.136 ;
     RECT  269.815 21.942 269.843 23.58 ;
     RECT  267.899 31.932 269.843 33.3 ;
     RECT  269.843 16.542 269.879 16.632 ;
     RECT  269.123 17.928 269.879 19.8 ;
     RECT  269.807 20.862 269.879 20.88 ;
     RECT  269.843 22.788 269.879 23.31 ;
     RECT  269.843 32.202 269.879 33.3 ;
     RECT  269.087 29.772 269.887 29.79 ;
     RECT  269.879 16.542 269.915 16.56 ;
     RECT  269.879 17.928 269.915 19.026 ;
     RECT  269.879 19.782 269.915 19.8 ;
     RECT  269.843 21.942 269.915 21.96 ;
     RECT  269.879 22.788 269.915 22.806 ;
     RECT  267.84 26.532 269.915 26.55 ;
     RECT  269.887 29.772 269.915 30.249 ;
     RECT  269.087 30.996 269.915 31.014 ;
     RECT  269.879 32.202 269.915 32.76 ;
     RECT  269.915 30.231 269.987 30.249 ;
     RECT  269.915 32.202 269.987 32.22 ;
    LAYER M3 ;
     RECT  138.132 0.043 138.15 0.091 ;
     RECT  139.752 0.043 139.77 0.091 ;
     RECT  93.276 0.091 93.294 0.139 ;
     RECT  94.032 0.091 95.886 0.139 ;
     RECT  103.5 0.091 104.238 0.139 ;
     RECT  113.976 0.091 114.318 0.139 ;
     RECT  123.048 0.091 123.066 0.139 ;
     RECT  138.888 0.091 140.31 0.139 ;
     RECT  141.048 0.091 141.066 0.139 ;
     RECT  125.172 0.043 125.19 0.173 ;
     RECT  137.88 0.091 138.15 0.173 ;
     RECT  102.384 0.091 102.582 0.187 ;
     RECT  132.372 0.091 132.966 0.187 ;
     RECT  132.372 0.187 133.182 0.235 ;
     RECT  137.88 0.173 137.898 0.317 ;
     RECT  100.044 0.091 101.61 0.427 ;
     RECT  102.348 0.187 102.582 0.427 ;
     RECT  106.344 0.091 109.35 0.475 ;
     RECT  100.044 0.427 102.582 0.523 ;
     RECT  110.88 0.091 111.042 0.523 ;
     RECT  113.652 0.139 114.318 0.523 ;
     RECT  115.056 0.091 115.074 0.523 ;
     RECT  117.72 0.091 118.278 0.523 ;
     RECT  123.048 0.139 123.462 0.523 ;
     RECT  134.172 0.091 134.19 0.523 ;
     RECT  138.888 0.139 141.066 0.523 ;
     RECT  90 0.091 90.99 0.571 ;
     RECT  99.324 0.523 102.582 0.571 ;
     RECT  103.5 0.139 104.562 0.571 ;
     RECT  110.232 0.523 111.042 0.571 ;
     RECT  111.888 0.091 112.266 0.571 ;
     RECT  113.652 0.523 115.074 0.571 ;
     RECT  116.316 0.091 116.334 0.571 ;
     RECT  121.104 0.091 121.59 0.571 ;
     RECT  122.4 0.523 123.462 0.571 ;
     RECT  127.044 0.091 127.746 0.571 ;
     RECT  129.348 0.091 130.518 0.571 ;
     RECT  131.544 0.091 131.562 0.571 ;
     RECT  132.372 0.235 133.29 0.571 ;
     RECT  134.064 0.523 134.19 0.571 ;
     RECT  135.108 0.043 135.126 0.571 ;
     RECT  121.104 0.571 121.662 0.619 ;
     RECT  122.4 0.571 125.082 0.619 ;
     RECT  128.592 0.091 128.61 1.051 ;
     RECT  129.348 0.571 135.126 1.051 ;
     RECT  137.808 0.571 137.826 1.051 ;
     RECT  138.852 0.523 141.066 1.051 ;
     RECT  93.276 0.139 95.886 1.099 ;
     RECT  105.948 0.475 109.35 1.099 ;
     RECT  110.232 0.571 112.878 1.099 ;
     RECT  117.216 0.523 118.278 1.099 ;
     RECT  119.268 0.091 120.006 1.099 ;
     RECT  121.104 0.619 125.082 1.099 ;
     RECT  128.592 1.051 135.126 1.099 ;
     RECT  137.808 1.051 141.066 1.099 ;
     RECT  97.02 0.571 97.038 1.147 ;
     RECT  98.316 0.091 98.334 1.147 ;
     RECT  117.216 1.099 125.082 1.147 ;
     RECT  126.396 0.571 127.746 1.147 ;
     RECT  136.08 0.091 136.098 1.147 ;
     RECT  137.052 0.571 137.07 1.147 ;
     RECT  137.808 1.099 141.138 1.147 ;
     RECT  99.324 0.571 104.562 1.675 ;
     RECT  89.964 0.571 90.99 1.723 ;
     RECT  92.952 1.099 95.886 1.723 ;
     RECT  97.02 1.147 98.478 1.723 ;
     RECT  99.216 1.675 104.562 1.723 ;
     RECT  105.588 1.099 112.878 1.723 ;
     RECT  113.652 0.571 115.146 1.723 ;
     RECT  115.956 0.571 116.334 1.723 ;
     RECT  117.216 1.147 127.746 1.723 ;
     RECT  128.556 1.099 135.126 1.723 ;
     RECT  89.964 1.723 91.098 1.771 ;
     RECT  92.556 1.723 95.886 1.771 ;
     RECT  115.956 1.723 127.746 1.771 ;
     RECT  128.484 1.723 135.162 1.771 ;
     RECT  136.08 1.147 141.138 1.771 ;
     RECT  89.964 1.771 91.494 1.819 ;
     RECT  92.232 1.771 95.886 1.819 ;
     RECT  96.84 1.723 98.478 1.819 ;
     RECT  99.216 1.723 115.146 1.819 ;
     RECT  96.84 1.819 115.146 2.143 ;
     RECT  115.956 1.771 141.138 2.143 ;
     RECT  2.415 2.143 2.505 2.413 ;
     RECT  7.815 2.143 7.905 2.413 ;
     RECT  13.215 2.143 13.305 2.413 ;
     RECT  18.615 2.143 18.705 2.413 ;
     RECT  24.015 2.143 24.105 2.413 ;
     RECT  29.415 2.143 29.505 2.413 ;
     RECT  34.815 2.143 34.905 2.413 ;
     RECT  40.215 2.143 40.305 2.413 ;
     RECT  45.615 2.143 45.705 2.413 ;
     RECT  51.015 2.143 51.105 2.413 ;
     RECT  56.415 2.143 56.505 2.413 ;
     RECT  61.815 2.143 61.905 2.413 ;
     RECT  67.215 2.143 67.305 2.413 ;
     RECT  72.615 2.143 72.705 2.413 ;
     RECT  78.015 2.143 78.105 2.413 ;
     RECT  83.415 2.143 83.505 2.413 ;
     RECT  88.815 2.143 88.905 2.413 ;
     RECT  142.815 2.143 142.905 2.413 ;
     RECT  148.215 2.143 148.305 2.413 ;
     RECT  153.615 2.143 153.705 2.413 ;
     RECT  159.015 2.143 159.105 2.413 ;
     RECT  164.415 2.143 164.505 2.413 ;
     RECT  169.815 2.143 169.905 2.413 ;
     RECT  175.215 2.143 175.305 2.413 ;
     RECT  180.615 2.143 180.705 2.413 ;
     RECT  186.015 2.143 186.105 2.413 ;
     RECT  191.415 2.143 191.505 2.413 ;
     RECT  196.815 2.143 196.905 2.413 ;
     RECT  202.215 2.143 202.305 2.413 ;
     RECT  207.615 2.143 207.705 2.413 ;
     RECT  213.015 2.143 213.105 2.413 ;
     RECT  218.415 2.143 218.505 2.413 ;
     RECT  223.815 2.143 223.905 2.413 ;
     RECT  229.215 2.143 229.305 2.413 ;
     RECT  234.615 2.143 234.705 2.413 ;
     RECT  240.015 2.143 240.105 2.413 ;
     RECT  245.415 2.143 245.505 2.413 ;
     RECT  250.815 2.143 250.905 2.413 ;
     RECT  256.215 2.143 256.305 2.413 ;
     RECT  261.615 2.143 261.705 2.413 ;
     RECT  267.015 2.143 267.105 2.413 ;
     RECT  89.964 1.819 95.886 2.489 ;
     RECT  89.964 2.489 95.742 3.029 ;
     RECT  96.84 2.143 141.138 3.029 ;
     RECT  90.18 3.029 95.742 3.209 ;
     RECT  90.36 3.209 95.742 3.299 ;
     RECT  96.84 3.029 140.958 3.299 ;
     RECT  97.308 3.299 140.886 7.195 ;
     RECT  90.36 3.299 95.634 7.321 ;
     RECT  90.36 7.321 95.814 7.861 ;
     RECT  97.308 7.195 140.922 10.831 ;
     RECT  97.308 10.831 141.174 11.399 ;
     RECT  97.308 11.399 140.994 12.361 ;
     RECT  97.308 12.361 141.03 12.479 ;
     RECT  103.608 12.479 141.03 12.623 ;
     RECT  103.608 12.623 140.958 13.289 ;
     RECT  267.015 2.413 267.297 13.801 ;
     RECT  267.015 13.801 267.642 14.071 ;
     RECT  266.868 14.071 267.642 14.203 ;
     RECT  266.868 14.203 267.714 14.243 ;
     RECT  103.608 13.289 140.85 14.369 ;
     RECT  264.06 14.521 264.078 14.611 ;
     RECT  264.816 14.521 264.834 14.639 ;
     RECT  266.868 14.243 267.642 14.647 ;
     RECT  263.88 14.611 264.078 14.719 ;
     RECT  263.88 14.719 264.582 14.755 ;
     RECT  266.688 14.647 267.642 14.881 ;
     RECT  263.304 14.755 264.582 14.989 ;
     RECT  266.22 14.881 267.642 14.989 ;
     RECT  265.32 14.881 265.338 15.163 ;
     RECT  266.22 14.989 267.714 15.163 ;
     RECT  263.16 14.989 264.582 15.259 ;
     RECT  259.02 15.259 259.254 15.295 ;
     RECT  258.696 15.295 259.542 15.331 ;
     RECT  261.615 2.413 261.897 15.421 ;
     RECT  263.088 15.259 264.582 15.421 ;
     RECT  265.32 15.163 267.714 15.421 ;
     RECT  257.616 15.403 257.634 15.601 ;
     RECT  258.696 15.331 260.622 15.601 ;
     RECT  258.66 15.601 260.802 15.787 ;
     RECT  257.616 15.601 257.778 15.835 ;
     RECT  258.552 15.787 260.802 15.835 ;
     RECT  257.616 15.835 260.802 15.863 ;
     RECT  97.308 12.479 102.798 15.871 ;
     RECT  258.228 15.863 260.802 15.997 ;
     RECT  269.064 15.835 269.082 15.997 ;
     RECT  258.228 15.997 260.838 16.069 ;
     RECT  261.615 15.421 267.714 16.069 ;
     RECT  97.164 15.871 102.798 16.205 ;
     RECT  256.215 2.413 256.497 16.339 ;
     RECT  269.064 15.997 269.118 16.493 ;
     RECT  253.332 16.375 253.35 16.501 ;
     RECT  253.332 16.501 253.998 16.537 ;
     RECT  254.736 16.411 254.754 16.537 ;
     RECT  255.6 16.339 256.497 16.537 ;
     RECT  253.188 16.537 253.998 16.555 ;
     RECT  254.736 16.537 256.497 16.555 ;
     RECT  269.892 16.363 269.91 16.555 ;
     RECT  269.856 16.555 269.91 16.565 ;
     RECT  269.856 16.565 269.874 16.637 ;
     RECT  258.228 16.069 267.714 16.645 ;
     RECT  253.188 16.555 256.497 16.681 ;
     RECT  249.084 16.807 249.102 16.843 ;
     RECT  248.796 16.843 249.102 16.879 ;
     RECT  248.04 16.879 249.102 16.915 ;
     RECT  103.608 14.369 109.422 16.951 ;
     RECT  110.16 14.369 140.742 16.951 ;
     RECT  103.608 16.951 140.742 16.979 ;
     RECT  248.04 16.915 249.138 17.041 ;
     RECT  248.04 17.041 249.246 17.069 ;
     RECT  253.188 16.681 256.842 17.083 ;
     RECT  257.688 16.645 267.714 17.083 ;
     RECT  234.615 2.413 234.897 17.113 ;
     RECT  245.415 2.413 245.697 17.113 ;
     RECT  248.148 17.069 249.246 17.113 ;
     RECT  253.188 17.083 267.714 17.131 ;
     RECT  234.615 17.113 235.386 17.149 ;
     RECT  240.015 2.413 240.297 17.149 ;
     RECT  244.512 17.113 244.53 17.149 ;
     RECT  253.188 17.131 267.93 17.149 ;
     RECT  239.184 17.149 240.297 17.179 ;
     RECT  242.64 17.113 242.658 17.185 ;
     RECT  234.615 17.149 235.926 17.221 ;
     RECT  250.815 2.413 251.097 17.221 ;
     RECT  243.792 17.149 244.53 17.311 ;
     RECT  245.415 17.113 246.366 17.311 ;
     RECT  234.576 17.221 236.538 17.347 ;
     RECT  237.276 17.311 237.294 17.347 ;
     RECT  238.176 17.185 238.194 17.347 ;
     RECT  239.004 17.179 240.297 17.347 ;
     RECT  241.668 17.185 242.658 17.347 ;
     RECT  234.576 17.347 237.294 17.383 ;
     RECT  238.176 17.347 240.297 17.383 ;
     RECT  247.284 16.951 247.302 17.411 ;
     RECT  234.468 17.383 237.294 17.455 ;
     RECT  243.792 17.311 246.366 17.455 ;
     RECT  247.104 17.419 247.122 17.455 ;
     RECT  252.792 17.149 267.93 17.467 ;
     RECT  252.72 17.467 267.93 17.483 ;
     RECT  234.36 17.455 237.294 17.491 ;
     RECT  250.344 17.221 251.097 17.491 ;
     RECT  252.72 17.483 267.714 17.491 ;
     RECT  252.576 17.491 267.714 17.563 ;
     RECT  252.468 17.563 267.714 17.609 ;
     RECT  248.148 17.113 249.606 17.617 ;
     RECT  250.344 17.491 251.334 17.617 ;
     RECT  252.468 17.609 258.318 17.645 ;
     RECT  238.176 17.383 240.57 17.689 ;
     RECT  241.668 17.347 242.694 17.689 ;
     RECT  238.176 17.689 242.694 17.707 ;
     RECT  243.792 17.455 247.122 17.707 ;
     RECT  259.092 17.609 267.714 17.753 ;
     RECT  233.676 17.491 237.294 17.761 ;
     RECT  238.176 17.707 247.122 17.761 ;
     RECT  231.48 17.761 231.498 17.851 ;
     RECT  233.244 17.761 237.33 17.851 ;
     RECT  238.104 17.761 247.122 17.851 ;
     RECT  248.148 17.617 251.334 17.851 ;
     RECT  112.824 16.979 140.742 17.879 ;
     RECT  233.244 17.851 247.122 17.887 ;
     RECT  269.82 16.939 269.838 17.899 ;
     RECT  252.468 17.645 255.294 17.923 ;
     RECT  231.48 17.851 232.002 17.959 ;
     RECT  233.028 17.887 247.122 17.959 ;
     RECT  231.48 17.959 247.122 17.995 ;
     RECT  269.064 16.493 269.082 17.995 ;
     RECT  229.215 2.413 229.497 18.031 ;
     RECT  231.444 17.995 247.122 18.157 ;
     RECT  247.932 17.851 251.334 18.157 ;
     RECT  269.028 17.995 269.082 18.221 ;
     RECT  228.96 18.031 229.497 18.427 ;
     RECT  231.444 18.157 251.334 18.427 ;
     RECT  252.108 17.923 255.294 18.427 ;
     RECT  269.82 17.899 269.91 18.475 ;
     RECT  228.96 18.427 229.554 18.571 ;
     RECT  231.444 18.427 255.294 18.571 ;
     RECT  256.215 17.645 258.21 18.571 ;
     RECT  228.96 18.571 229.698 18.697 ;
     RECT  230.544 18.571 255.294 18.697 ;
     RECT  256.215 18.571 258.246 18.763 ;
     RECT  259.236 17.753 267.714 18.763 ;
     RECT  268.452 18.571 268.47 18.797 ;
     RECT  228.96 18.697 255.294 18.805 ;
     RECT  256.215 18.763 267.714 18.805 ;
     RECT  228.96 18.805 267.714 18.845 ;
     RECT  228.96 18.845 260.802 18.959 ;
     RECT  228.96 18.959 260.694 19.103 ;
     RECT  228.96 19.103 259.29 19.111 ;
     RECT  269.712 18.475 269.91 19.243 ;
     RECT  228.924 19.111 259.29 19.337 ;
     RECT  260.028 19.103 260.694 19.337 ;
     RECT  227.988 19.201 228.006 19.381 ;
     RECT  228.924 19.337 258.246 19.381 ;
     RECT  269.1 19.243 269.91 19.531 ;
     RECT  227.988 19.381 258.246 19.543 ;
     RECT  261.615 18.845 267.714 19.579 ;
     RECT  227.412 19.543 258.246 19.741 ;
     RECT  227.016 19.741 258.246 19.757 ;
     RECT  90.36 7.861 96.21 19.769 ;
     RECT  268.452 19.531 269.91 19.805 ;
     RECT  259.236 19.337 259.29 19.849 ;
     RECT  260.028 19.337 260.478 19.849 ;
     RECT  261.612 19.579 267.714 19.963 ;
     RECT  268.452 19.805 269.874 19.963 ;
     RECT  103.608 16.979 112.086 20.147 ;
     RECT  112.824 17.879 140.706 20.219 ;
     RECT  227.016 19.757 246.834 20.317 ;
     RECT  261.612 19.963 269.874 20.381 ;
     RECT  268.452 20.381 269.874 20.417 ;
     RECT  259.236 19.849 260.478 20.461 ;
     RECT  261.612 20.381 267.714 20.461 ;
     RECT  268.452 20.417 268.506 20.477 ;
     RECT  103.86 20.147 112.086 20.579 ;
     RECT  226.08 20.281 226.098 20.587 ;
     RECT  226.836 20.317 246.834 20.587 ;
     RECT  247.788 19.757 258.246 20.587 ;
     RECT  269.712 20.417 269.874 20.587 ;
     RECT  226.08 20.587 258.246 20.759 ;
     RECT  268.488 20.477 268.506 20.813 ;
     RECT  225.144 20.695 225.162 20.821 ;
     RECT  226.224 20.759 258.246 20.849 ;
     RECT  226.296 20.849 258.246 20.857 ;
     RECT  269.712 20.587 269.91 20.909 ;
     RECT  259.236 20.461 267.714 20.965 ;
     RECT  226.296 20.857 258.318 21.001 ;
     RECT  259.128 20.965 267.714 21.001 ;
     RECT  226.296 21.001 267.714 21.005 ;
     RECT  112.932 20.219 140.706 21.227 ;
     RECT  97.308 16.205 102.798 21.271 ;
     RECT  97.272 21.271 102.798 21.437 ;
     RECT  268.452 21.211 268.47 21.437 ;
     RECT  269.784 20.909 269.91 21.643 ;
     RECT  269.712 21.643 269.91 21.773 ;
     RECT  124.56 21.227 140.706 21.929 ;
     RECT  226.836 21.005 267.714 21.973 ;
     RECT  226.404 21.973 267.714 22.351 ;
     RECT  226.368 22.351 267.714 22.459 ;
     RECT  124.56 21.929 140.634 22.469 ;
     RECT  97.308 21.437 102.798 22.649 ;
     RECT  269.064 22.603 269.082 22.795 ;
     RECT  226.296 22.459 267.714 22.883 ;
     RECT  225.144 20.821 225.45 22.891 ;
     RECT  226.296 22.883 257.094 22.891 ;
     RECT  268.452 22.795 269.082 22.925 ;
     RECT  269.064 22.925 269.082 23.045 ;
     RECT  225.144 22.891 257.094 23.053 ;
     RECT  223.815 2.413 224.097 23.161 ;
     RECT  224.856 23.053 257.094 23.161 ;
     RECT  97.344 22.649 102.798 23.189 ;
     RECT  216.504 23.089 216.522 23.323 ;
     RECT  216.504 23.323 216.738 23.395 ;
     RECT  97.524 23.189 102.798 23.549 ;
     RECT  103.86 20.579 111.87 23.557 ;
     RECT  269.82 21.773 269.91 23.585 ;
     RECT  223.815 23.161 257.094 23.629 ;
     RECT  257.868 22.883 267.714 23.629 ;
     RECT  216.288 23.395 216.738 23.729 ;
     RECT  216.36 23.729 216.738 23.791 ;
     RECT  112.932 21.227 123.534 23.899 ;
     RECT  124.56 22.469 140.562 23.899 ;
     RECT  223.815 23.629 267.714 23.947 ;
     RECT  217.548 23.971 217.566 24.061 ;
     RECT  218.415 2.413 218.697 24.061 ;
     RECT  216.36 23.791 216.774 24.089 ;
     RECT  216.576 24.089 216.774 24.097 ;
     RECT  217.548 24.061 218.697 24.097 ;
     RECT  223.815 23.947 267.858 24.125 ;
     RECT  214.416 23.971 214.434 24.133 ;
     RECT  214.344 24.133 214.434 24.161 ;
     RECT  223.815 24.125 267.714 24.205 ;
     RECT  214.344 24.161 214.362 24.233 ;
     RECT  222.3 23.971 222.426 24.241 ;
     RECT  223.632 24.205 267.714 24.241 ;
     RECT  222.3 24.241 267.714 24.359 ;
     RECT  103.824 23.557 111.87 24.367 ;
     RECT  112.608 23.899 140.562 24.367 ;
     RECT  216.576 24.097 218.697 24.503 ;
     RECT  221.22 24.403 221.238 24.601 ;
     RECT  222.3 24.359 260.298 24.601 ;
     RECT  97.668 23.549 102.798 24.629 ;
     RECT  142.815 2.413 143.097 24.763 ;
     RECT  153.615 2.413 153.897 24.763 ;
     RECT  164.415 2.413 164.697 24.763 ;
     RECT  175.215 2.413 175.497 24.763 ;
     RECT  186.015 2.413 186.297 24.763 ;
     RECT  196.815 2.413 197.097 24.763 ;
     RECT  207.615 2.413 207.897 24.763 ;
     RECT  103.824 24.367 140.562 24.809 ;
     RECT  142.704 24.763 143.097 24.809 ;
     RECT  153.504 24.763 153.897 24.809 ;
     RECT  164.304 24.763 164.697 24.809 ;
     RECT  175.104 24.763 175.497 24.809 ;
     RECT  185.904 24.763 186.297 24.809 ;
     RECT  196.704 24.763 197.097 24.809 ;
     RECT  207.504 24.763 207.897 24.809 ;
     RECT  97.668 24.629 102.726 24.899 ;
     RECT  221.22 24.601 260.298 24.907 ;
     RECT  216.72 24.503 218.697 25.015 ;
     RECT  216.72 25.015 219.294 25.051 ;
     RECT  220.032 23.323 220.05 25.051 ;
     RECT  220.86 24.907 260.298 25.051 ;
     RECT  216.72 25.051 260.298 25.079 ;
     RECT  216.972 25.079 260.298 25.141 ;
     RECT  261.036 24.359 267.714 25.141 ;
     RECT  177.192 24.907 177.21 25.277 ;
     RECT  214.344 25.411 214.362 25.511 ;
     RECT  216.972 25.141 267.714 25.583 ;
     RECT  216.972 25.583 262.71 25.619 ;
     RECT  97.668 24.899 102.69 25.709 ;
     RECT  97.668 25.709 102.474 25.745 ;
     RECT  97.668 25.745 102.186 25.979 ;
     RECT  216.972 25.619 262.53 26.365 ;
     RECT  263.448 25.583 267.642 26.365 ;
     RECT  124.38 24.809 140.562 26.401 ;
     RECT  269.892 23.585 269.91 26.555 ;
     RECT  214.344 26.329 214.362 26.563 ;
     RECT  124.38 26.401 140.886 26.627 ;
     RECT  214.344 26.563 214.398 26.627 ;
     RECT  216.972 26.365 267.642 26.635 ;
     RECT  216.9 26.635 267.642 26.827 ;
     RECT  216.9 26.827 267.714 27.095 ;
     RECT  216.036 27.139 216.054 27.175 ;
     RECT  216 27.175 216.054 27.211 ;
     RECT  216.9 27.095 233.766 27.211 ;
     RECT  214.38 26.627 214.398 27.307 ;
     RECT  215.244 27.211 233.766 27.307 ;
     RECT  141.984 27.211 142.002 27.337 ;
     RECT  207.615 24.809 207.897 27.355 ;
     RECT  141.912 27.337 142.002 27.365 ;
     RECT  214.38 27.307 233.766 27.409 ;
     RECT  141.912 27.365 141.93 27.437 ;
     RECT  124.38 26.627 140.814 27.445 ;
     RECT  124.38 27.445 141.354 27.599 ;
     RECT  206.532 27.835 206.55 27.869 ;
     RECT  207.615 27.355 208.098 27.869 ;
     RECT  103.824 24.809 123.534 27.949 ;
     RECT  124.38 27.599 140.886 27.949 ;
     RECT  234.615 27.095 267.714 27.977 ;
     RECT  214.344 27.409 233.766 28.139 ;
     RECT  97.668 25.979 102.006 28.147 ;
     RECT  214.344 28.139 225.918 28.171 ;
     RECT  213.015 2.413 213.297 28.255 ;
     RECT  214.164 28.171 225.918 28.255 ;
     RECT  103.824 27.949 140.886 28.409 ;
     RECT  124.38 28.409 140.886 28.561 ;
     RECT  124.38 28.561 140.922 28.679 ;
     RECT  226.98 28.139 233.766 28.687 ;
     RECT  234.615 27.977 252.63 28.687 ;
     RECT  226.98 28.687 252.63 28.751 ;
     RECT  213.015 28.255 225.918 28.921 ;
     RECT  226.98 28.751 251.73 28.921 ;
     RECT  90.648 19.769 96.21 28.949 ;
     RECT  252.468 28.751 252.63 29.083 ;
     RECT  253.368 27.977 267.714 29.083 ;
     RECT  269.064 29.335 269.082 29.497 ;
     RECT  213.015 28.921 251.73 29.533 ;
     RECT  252.468 29.083 267.714 29.533 ;
     RECT  268.488 29.497 269.082 29.645 ;
     RECT  97.668 28.147 102.078 29.767 ;
     RECT  269.028 29.645 269.082 29.837 ;
     RECT  213.015 29.533 267.714 29.875 ;
     RECT  212.796 29.875 267.714 29.933 ;
     RECT  213.015 29.933 267.714 30.065 ;
     RECT  269.028 29.837 269.046 30.125 ;
     RECT  213.015 30.065 263.286 30.137 ;
     RECT  269.892 29.323 269.91 30.226 ;
     RECT  269.892 30.226 269.982 30.283 ;
     RECT  124.38 28.679 140.85 30.299 ;
     RECT  213.015 30.137 243.198 30.371 ;
     RECT  228.744 30.371 243.198 30.407 ;
     RECT  97.668 29.767 102.402 30.569 ;
     RECT  269.064 30.571 269.082 30.677 ;
     RECT  264.06 30.065 267.714 30.859 ;
     RECT  243.936 30.137 263.286 30.955 ;
     RECT  264.06 30.859 267.894 30.955 ;
     RECT  90.684 28.949 96.21 30.991 ;
     RECT  213.015 30.371 227.898 30.991 ;
     RECT  213.012 30.991 227.898 31.019 ;
     RECT  228.996 30.407 243.198 31.181 ;
     RECT  0.036 30.649 0.054 31.189 ;
     RECT  213.012 31.019 226.134 31.189 ;
     RECT  226.944 31.019 227.898 31.189 ;
     RECT  228.996 31.181 232.29 31.189 ;
     RECT  212.832 31.189 226.134 31.229 ;
     RECT  233.064 31.181 243.198 31.253 ;
     RECT  86.652 31.189 86.67 31.289 ;
     RECT  233.676 31.253 243.198 31.351 ;
     RECT  243.936 30.955 267.894 31.351 ;
     RECT  233.676 31.351 267.894 31.379 ;
     RECT  263.664 31.379 267.894 31.415 ;
     RECT  0.036 31.189 0.126 31.423 ;
     RECT  90.648 30.991 96.21 31.523 ;
     RECT  97.668 30.569 102.33 31.531 ;
     RECT  226.944 31.189 232.29 31.649 ;
     RECT  233.676 31.379 262.602 31.649 ;
     RECT  233.676 31.649 259.182 31.721 ;
     RECT  233.676 31.721 252.27 31.793 ;
     RECT  213.015 31.229 226.134 31.915 ;
     RECT  226.944 31.649 232.182 31.915 ;
     RECT  210.348 30.811 210.366 31.919 ;
     RECT  259.92 31.649 262.602 31.919 ;
     RECT  97.38 31.531 102.33 31.949 ;
     RECT  269.82 30.283 269.982 31.955 ;
     RECT  103.824 28.409 123.57 32.035 ;
     RECT  103.32 32.035 123.57 32.071 ;
     RECT  124.38 30.299 132.822 32.071 ;
     RECT  269.856 31.955 269.982 32.225 ;
     RECT  213.015 31.915 232.182 32.261 ;
     RECT  213.015 32.261 215.478 32.369 ;
     RECT  103.32 32.071 132.822 32.459 ;
     RECT  214.812 32.369 215.478 32.495 ;
     RECT  216.288 32.261 232.182 32.495 ;
     RECT  97.668 31.949 102.33 32.531 ;
     RECT  234.18 31.793 252.27 32.539 ;
     RECT  215.28 32.495 215.478 32.567 ;
     RECT  233.64 32.539 252.27 32.575 ;
     RECT  253.044 31.721 259.182 32.575 ;
     RECT  261 31.919 262.602 32.575 ;
     RECT  263.664 31.415 267.714 32.575 ;
     RECT  213.015 32.369 213.894 32.603 ;
     RECT  215.28 32.567 215.298 32.603 ;
     RECT  227.088 32.495 232.182 32.611 ;
     RECT  233.64 32.575 259.182 32.611 ;
     RECT  261 32.575 262.746 32.701 ;
     RECT  263.556 32.575 267.714 32.701 ;
     RECT  103.32 32.459 123.57 32.729 ;
     RECT  97.704 32.531 102.33 32.731 ;
     RECT  227.088 32.611 259.182 32.765 ;
     RECT  269.856 32.225 269.91 32.765 ;
     RECT  97.704 32.731 102.366 32.881 ;
     RECT  234.144 32.765 259.182 32.881 ;
     RECT  261 32.701 267.714 32.881 ;
     RECT  260.964 32.881 267.714 33.067 ;
     RECT  97.704 32.881 102.546 33.079 ;
     RECT  234.144 32.881 259.326 33.107 ;
     RECT  260.964 33.067 267.894 33.107 ;
     RECT  260.964 33.107 267.858 33.115 ;
     RECT  169.815 2.413 170.097 33.241 ;
     RECT  227.088 32.765 233.226 33.269 ;
     RECT  260.748 33.115 267.858 33.305 ;
     RECT  269.856 32.765 269.874 33.305 ;
     RECT  216.936 32.495 226.278 33.313 ;
     RECT  227.088 33.269 231.822 33.313 ;
     RECT  168.768 33.307 168.786 33.341 ;
     RECT  169.815 33.241 170.334 33.341 ;
     RECT  260.748 33.305 263.358 33.341 ;
     RECT  124.38 32.459 132.822 33.385 ;
     RECT  232.704 33.269 233.226 33.547 ;
     RECT  234.144 33.107 259.182 33.547 ;
     RECT  232.704 33.547 259.182 33.575 ;
     RECT  216.936 33.313 231.822 33.629 ;
     RECT  261 33.341 263.358 33.629 ;
     RECT  97.704 33.079 102.798 33.691 ;
     RECT  103.824 32.729 123.57 33.691 ;
     RECT  97.704 33.691 123.57 33.809 ;
     RECT  264.276 33.305 267.858 33.845 ;
     RECT  216.936 33.629 231.57 34.079 ;
     RECT  232.704 33.575 248.13 34.079 ;
     RECT  264.276 33.845 267.714 34.079 ;
     RECT  103.896 33.809 123.57 34.123 ;
     RECT  124.308 33.385 132.822 34.123 ;
     RECT  234.288 34.079 248.13 34.151 ;
     RECT  232.704 34.079 233.514 34.195 ;
     RECT  261.216 33.629 263.358 34.393 ;
     RECT  214.344 34.231 214.362 34.493 ;
     RECT  261.216 34.393 263.61 34.501 ;
     RECT  226.98 34.079 231.57 34.627 ;
     RECT  232.524 34.195 233.514 34.627 ;
     RECT  236.232 34.151 248.13 34.627 ;
     RECT  248.868 33.575 259.182 34.627 ;
     RECT  264.348 34.079 267.714 34.727 ;
     RECT  261.072 34.501 263.61 34.735 ;
     RECT  0.036 31.423 0.198 34.771 ;
     RECT  260.892 34.735 263.61 34.781 ;
     RECT  90.684 31.523 96.21 34.843 ;
     RECT  226.98 34.627 233.514 34.861 ;
     RECT  234.288 34.151 235.458 34.861 ;
     RECT  0.036 34.771 0.234 34.889 ;
     RECT  216.936 34.079 226.17 34.933 ;
     RECT  216.612 34.933 226.17 35.005 ;
     RECT  226.98 34.861 235.458 35.005 ;
     RECT  264.384 34.727 267.714 35.033 ;
     RECT  216.612 35.005 235.458 35.069 ;
     RECT  216.684 35.069 235.458 35.159 ;
     RECT  90.684 34.843 96.39 35.203 ;
     RECT  236.232 34.627 259.182 35.311 ;
     RECT  217.512 35.159 235.458 35.339 ;
     RECT  231.912 35.339 235.458 35.419 ;
     RECT  90.684 35.203 96.642 35.563 ;
     RECT  261.216 34.781 263.61 35.581 ;
     RECT  90.432 35.563 96.642 35.699 ;
     RECT  264.492 35.033 267.714 35.699 ;
     RECT  90.432 35.699 95.994 35.735 ;
     RECT  261.216 35.581 263.682 35.815 ;
     RECT  264.492 35.699 267.642 35.815 ;
     RECT  97.704 33.809 102.798 35.899 ;
     RECT  103.896 34.123 132.822 35.899 ;
     RECT  206.604 35.899 206.622 35.904 ;
     RECT  206.601 35.904 206.625 36.003 ;
     RECT  206.604 36.003 206.625 36.005 ;
     RECT  231.912 35.419 235.494 36.013 ;
     RECT  236.232 35.311 259.362 36.013 ;
     RECT  217.512 35.339 231.174 36.121 ;
     RECT  231.912 36.013 259.362 36.121 ;
     RECT  217.512 36.121 259.362 36.149 ;
     RECT  216.684 35.159 216.702 36.211 ;
     RECT  217.512 36.149 221.166 36.211 ;
     RECT  96.84 35.815 96.858 36.239 ;
     RECT  97.704 35.899 132.822 36.239 ;
     RECT  216.684 36.211 221.166 36.275 ;
     RECT  206.784 36.121 206.802 36.461 ;
     RECT  221.904 36.149 259.362 36.545 ;
     RECT  261.216 35.815 267.642 36.545 ;
     RECT  226.908 36.545 259.362 36.553 ;
     RECT  264.384 36.545 267.642 36.581 ;
     RECT  226.908 36.553 259.506 36.625 ;
     RECT  264.96 36.581 267.642 36.625 ;
     RECT  226.908 36.625 259.578 36.661 ;
     RECT  90.684 35.735 95.994 36.763 ;
     RECT  264.96 36.625 267.714 36.779 ;
     RECT  88.815 2.413 89.097 36.787 ;
     RECT  261.216 36.545 263.394 36.815 ;
     RECT  264.96 36.779 267.642 36.815 ;
     RECT  263.34 36.815 263.394 36.887 ;
     RECT  264.96 36.815 265.842 36.941 ;
     RECT  87.48 36.859 87.498 36.959 ;
     RECT  97.704 36.239 111.366 37.021 ;
     RECT  112.14 36.239 132.822 37.021 ;
     RECT  85.932 36.895 85.95 37.037 ;
     RECT  88.815 36.787 89.766 37.049 ;
     RECT  221.904 36.545 225.63 37.049 ;
     RECT  263.34 36.887 263.358 37.049 ;
     RECT  221.904 37.049 225.594 37.121 ;
     RECT  217.224 36.275 221.166 37.129 ;
     RECT  221.904 37.121 225.558 37.129 ;
     RECT  226.908 36.661 259.722 37.201 ;
     RECT  90.576 36.763 95.994 37.327 ;
     RECT  226.908 37.201 259.866 37.399 ;
     RECT  217.224 37.129 225.558 37.435 ;
     RECT  226.908 37.399 259.938 37.435 ;
     RECT  215.028 37.435 215.046 37.471 ;
     RECT  226.908 37.435 260.154 37.499 ;
     RECT  261.216 36.815 262.278 37.499 ;
     RECT  90.504 37.327 95.994 37.589 ;
     RECT  97.704 37.021 132.822 37.589 ;
     RECT  215.028 37.471 215.19 37.589 ;
     RECT  215.964 37.201 215.982 37.589 ;
     RECT  265.068 36.941 265.842 37.705 ;
     RECT  264.528 37.705 265.842 37.741 ;
     RECT  266.616 36.815 267.642 37.741 ;
     RECT  264.528 37.741 267.642 37.757 ;
     RECT  2.415 2.413 2.697 37.831 ;
     RECT  226.908 37.499 259.794 37.859 ;
     RECT  216.792 37.435 225.558 37.895 ;
     RECT  86.652 37.741 86.67 37.931 ;
     RECT  265.644 37.757 267.642 37.931 ;
     RECT  216.792 37.895 221.202 37.939 ;
     RECT  222.084 37.895 225.558 37.939 ;
     RECT  226.908 37.859 259.65 37.949 ;
     RECT  222.084 37.939 225.882 37.963 ;
     RECT  226.908 37.949 259.614 37.963 ;
     RECT  90.54 37.589 95.994 38.011 ;
     RECT  96.876 37.471 96.894 38.011 ;
     RECT  264.528 37.757 264.546 38.011 ;
     RECT  265.644 37.931 267.297 38.129 ;
     RECT  90.54 38.011 96.894 38.165 ;
     RECT  265.644 38.129 266.274 38.165 ;
     RECT  0.108 34.889 0.234 38.203 ;
     RECT  90.72 38.165 96.894 38.209 ;
     RECT  97.704 37.589 102.798 38.209 ;
     RECT  2.34 37.831 2.697 38.245 ;
     RECT  222.084 37.963 259.614 38.309 ;
     RECT  264.492 38.011 264.546 38.309 ;
     RECT  0.108 38.203 0.27 38.347 ;
     RECT  0.108 38.347 0.306 38.395 ;
     RECT  1.08 38.011 1.098 38.395 ;
     RECT  222.264 38.309 259.614 38.399 ;
     RECT  266.004 38.165 266.274 38.399 ;
     RECT  266.004 38.399 266.202 38.435 ;
     RECT  214.344 38.281 214.362 38.471 ;
     RECT  90.72 38.209 102.798 38.491 ;
     RECT  103.536 37.589 132.822 38.491 ;
     RECT  2.304 38.245 2.697 38.515 ;
     RECT  3.42 38.371 3.438 38.515 ;
     RECT  2.304 38.515 3.438 38.539 ;
     RECT  0.108 38.395 1.098 38.551 ;
     RECT  263.232 37.963 263.25 38.621 ;
     RECT  81.504 38.395 81.522 38.669 ;
     RECT  82.296 38.281 82.314 38.669 ;
     RECT  216.612 37.939 221.202 38.669 ;
     RECT  222.264 38.399 225.414 38.669 ;
     RECT  264.492 38.309 264.51 38.669 ;
     RECT  133.596 30.299 140.85 38.713 ;
     RECT  80.352 37.903 80.37 38.821 ;
     RECT  226.152 38.399 259.614 38.849 ;
     RECT  13.215 2.413 13.497 38.911 ;
     RECT  24.015 2.413 24.297 38.911 ;
     RECT  34.815 2.413 35.097 38.911 ;
     RECT  45.615 2.413 45.897 38.911 ;
     RECT  56.415 2.413 56.697 38.911 ;
     RECT  67.215 2.413 67.497 38.911 ;
     RECT  78.015 2.413 78.297 38.911 ;
     RECT  88.815 37.049 89.097 38.911 ;
     RECT  80.352 38.821 80.406 38.939 ;
     RECT  13.104 38.911 13.497 38.957 ;
     RECT  23.904 38.911 24.297 38.957 ;
     RECT  34.704 38.911 35.097 38.957 ;
     RECT  45.504 38.911 45.897 38.957 ;
     RECT  56.304 38.911 56.697 38.957 ;
     RECT  67.104 38.911 67.497 38.957 ;
     RECT  77.904 38.911 78.297 38.957 ;
     RECT  88.704 38.911 89.097 38.957 ;
     RECT  90.72 38.491 132.822 38.983 ;
     RECT  222.264 38.669 222.462 39.047 ;
     RECT  0.108 38.551 1.134 39.053 ;
     RECT  133.596 38.713 141.03 39.055 ;
     RECT  29.415 2.413 29.697 39.067 ;
     RECT  2.268 38.539 3.438 39.091 ;
     RECT  4.5 38.749 4.518 39.091 ;
     RECT  266.004 38.435 266.022 39.101 ;
     RECT  2.268 39.091 4.518 39.119 ;
     RECT  142.815 24.809 143.097 39.181 ;
     RECT  29.415 39.067 30.186 39.209 ;
     RECT  80.352 38.939 80.37 39.209 ;
     RECT  0.144 39.053 1.134 39.245 ;
     RECT  90.72 38.983 132.858 39.253 ;
     RECT  133.596 39.055 141.246 39.253 ;
     RECT  2.268 39.119 4.41 39.289 ;
     RECT  142.524 39.181 143.097 39.317 ;
     RECT  217.08 38.669 220.626 39.317 ;
     RECT  0.144 39.245 1.098 39.341 ;
     RECT  90.72 39.253 141.246 39.361 ;
     RECT  214.596 39.325 215.046 39.361 ;
     RECT  261.216 37.499 261.897 39.389 ;
     RECT  0.144 39.341 0.558 39.437 ;
     RECT  210.384 39.361 210.402 39.451 ;
     RECT  216.072 39.403 216.09 39.451 ;
     RECT  217.08 39.317 219.906 39.451 ;
     RECT  230.544 38.849 259.614 39.451 ;
     RECT  213.015 32.603 213.297 39.523 ;
     RECT  0.144 39.437 0.522 39.533 ;
     RECT  210.348 39.451 210.402 39.551 ;
     RECT  216.072 39.451 219.906 39.551 ;
     RECT  230.544 39.451 260.046 39.551 ;
     RECT  83.415 2.413 83.697 39.631 ;
     RECT  216.072 39.551 216.378 39.631 ;
     RECT  213.015 39.523 213.426 39.721 ;
     RECT  214.236 39.361 215.046 39.721 ;
     RECT  82.08 39.547 82.098 39.749 ;
     RECT  83.124 39.631 83.697 39.749 ;
     RECT  230.544 39.551 259.974 39.749 ;
     RECT  90.648 39.361 141.246 39.785 ;
     RECT  90.648 39.785 96.426 39.787 ;
     RECT  90.36 39.787 96.426 39.821 ;
     RECT  213.015 39.721 215.046 39.829 ;
     RECT  215.784 39.631 216.378 39.829 ;
     RECT  226.152 38.849 229.77 39.829 ;
     RECT  230.544 39.749 259.758 39.829 ;
     RECT  97.308 39.785 141.246 39.857 ;
     RECT  213.015 39.829 216.378 39.857 ;
     RECT  223.236 38.669 225.414 39.865 ;
     RECT  226.152 39.829 259.758 39.865 ;
     RECT  13.215 38.957 13.497 39.883 ;
     RECT  24.015 38.957 24.297 39.883 ;
     RECT  45.615 38.957 45.897 39.883 ;
     RECT  56.415 38.957 56.697 39.883 ;
     RECT  61.815 2.413 62.097 39.883 ;
     RECT  78.015 38.957 78.297 39.883 ;
     RECT  223.236 39.865 259.758 39.893 ;
     RECT  13.104 39.883 13.497 39.929 ;
     RECT  23.904 39.883 24.297 39.929 ;
     RECT  45.504 39.883 45.897 39.929 ;
     RECT  56.304 39.883 56.697 39.929 ;
     RECT  223.236 39.893 259.578 39.929 ;
     RECT  80.28 39.883 80.298 40.019 ;
     RECT  30.888 39.883 30.906 40.027 ;
     RECT  34.815 38.957 35.097 40.027 ;
     RECT  46.872 39.883 46.89 40.027 ;
     RECT  51.015 2.413 51.297 40.027 ;
     RECT  67.215 38.957 67.497 40.027 ;
     RECT  77.904 39.883 78.297 40.027 ;
     RECT  30.78 40.027 30.906 40.061 ;
     RECT  46.764 40.027 46.89 40.061 ;
     RECT  61.815 39.883 62.802 40.061 ;
     RECT  217.116 39.551 219.906 40.063 ;
     RECT  220.86 39.901 220.914 40.063 ;
     RECT  214.344 39.857 216.378 40.091 ;
     RECT  223.236 39.929 259.254 40.123 ;
     RECT  222.336 39.047 222.462 40.135 ;
     RECT  14.832 40.027 14.85 40.157 ;
     RECT  30.78 40.061 30.798 40.157 ;
     RECT  34.815 40.027 35.118 40.157 ;
     RECT  46.764 40.061 46.782 40.157 ;
     RECT  51.015 40.027 51.318 40.157 ;
     RECT  58.716 40.027 58.734 40.157 ;
     RECT  67.215 40.027 67.518 40.157 ;
     RECT  217.116 40.063 220.914 40.199 ;
     RECT  77.292 40.027 78.297 40.289 ;
     RECT  210.348 39.551 210.366 40.289 ;
     RECT  214.344 40.091 214.434 40.289 ;
     RECT  221.868 40.135 222.462 40.289 ;
     RECT  223.2 40.123 259.254 40.297 ;
     RECT  0.144 39.533 0.414 40.397 ;
     RECT  6.804 40.171 6.822 40.397 ;
     RECT  215.172 40.091 216.378 40.397 ;
     RECT  217.584 40.199 220.914 40.397 ;
     RECT  217.584 40.397 220.626 40.433 ;
     RECT  2.16 39.289 4.41 40.441 ;
     RECT  215.82 40.397 216.378 40.459 ;
     RECT  81.072 40.171 81.09 40.469 ;
     RECT  217.584 40.433 218.697 40.469 ;
     RECT  219.636 40.433 220.626 40.469 ;
     RECT  217.584 40.469 217.602 40.559 ;
     RECT  222.588 40.297 259.254 40.559 ;
     RECT  215.82 40.459 216.63 40.595 ;
     RECT  2.16 40.441 4.95 40.603 ;
     RECT  216.036 40.595 216.63 40.637 ;
     RECT  90.72 39.821 96.426 40.711 ;
     RECT  2.16 40.603 5.346 40.739 ;
     RECT  214.344 40.289 214.362 40.739 ;
     RECT  220.032 40.469 220.626 40.829 ;
     RECT  0.144 40.397 0.342 40.925 ;
     RECT  2.16 40.739 5.274 40.937 ;
     RECT  0.216 40.925 0.342 40.973 ;
     RECT  216.036 40.637 216.054 40.973 ;
     RECT  220.608 40.829 220.626 41.009 ;
     RECT  2.16 40.937 4.842 41.099 ;
     RECT  222.876 40.559 259.254 41.179 ;
     RECT  90.72 40.711 96.462 41.215 ;
     RECT  97.308 39.857 140.202 41.215 ;
     RECT  222.876 41.179 259.866 41.279 ;
     RECT  2.16 41.099 4.266 41.369 ;
     RECT  223.596 41.279 259.866 41.369 ;
     RECT  223.815 41.369 259.866 41.449 ;
     RECT  223.815 41.449 260.118 41.549 ;
     RECT  2.16 41.369 4.23 41.639 ;
     RECT  223.815 41.549 259.794 41.675 ;
     RECT  224.892 41.675 259.794 41.711 ;
     RECT  225.432 41.711 259.794 41.747 ;
     RECT  0.108 41.707 0.126 41.837 ;
     RECT  180.615 2.413 180.897 41.899 ;
     RECT  225.432 41.747 225.846 41.909 ;
     RECT  225.432 41.909 225.45 41.933 ;
     RECT  226.908 41.747 259.794 42.029 ;
     RECT  142.815 39.317 143.097 42.043 ;
     RECT  153.615 24.809 153.897 42.043 ;
     RECT  164.415 24.809 164.697 42.043 ;
     RECT  175.215 24.809 175.497 42.043 ;
     RECT  186.015 24.809 186.297 42.043 ;
     RECT  196.815 24.809 197.097 42.043 ;
     RECT  142.704 42.043 143.097 42.089 ;
     RECT  153.504 42.043 153.897 42.089 ;
     RECT  164.304 42.043 164.697 42.089 ;
     RECT  175.104 42.043 175.497 42.089 ;
     RECT  185.904 42.043 186.297 42.089 ;
     RECT  196.704 42.043 197.097 42.089 ;
     RECT  230.472 42.029 259.794 42.179 ;
     RECT  180.288 41.899 180.897 42.449 ;
     RECT  231.12 42.179 259.794 42.719 ;
     RECT  90.72 41.215 140.202 42.755 ;
     RECT  2.16 41.639 4.122 42.989 ;
     RECT  2.16 42.989 4.014 43.097 ;
     RECT  231.336 42.719 259.794 43.097 ;
     RECT  2.196 43.097 4.014 43.169 ;
     RECT  96.948 42.755 140.202 43.325 ;
     RECT  87.768 43.339 87.786 43.344 ;
     RECT  231.84 43.097 259.794 43.439 ;
     RECT  88.815 38.957 89.097 43.501 ;
     RECT  87.765 43.344 87.789 43.527 ;
     RECT  3.996 43.169 4.014 43.529 ;
     RECT  87.768 43.527 87.786 43.529 ;
     RECT  231.84 43.439 259.182 43.529 ;
     RECT  226.908 42.029 229.497 43.531 ;
     RECT  88.815 43.501 89.334 43.565 ;
     RECT  226.62 43.531 229.497 43.565 ;
     RECT  2.196 43.169 3.186 43.637 ;
     RECT  2.232 43.637 3.186 43.709 ;
     RECT  226.872 43.565 229.497 43.709 ;
     RECT  231.84 43.529 258.93 43.805 ;
     RECT  2.232 43.709 3.15 43.835 ;
     RECT  232.776 43.805 258.93 43.835 ;
     RECT  2.304 43.835 3.15 43.871 ;
     RECT  2.304 43.871 2.718 43.943 ;
     RECT  226.872 43.709 227.934 44.213 ;
     RECT  2.304 43.943 2.697 44.339 ;
     RECT  232.884 43.835 258.93 44.339 ;
     RECT  2.376 44.339 2.697 44.375 ;
     RECT  97.092 43.325 140.202 44.375 ;
     RECT  97.092 44.375 134.838 44.609 ;
     RECT  231.84 43.805 231.858 44.609 ;
     RECT  232.884 44.339 258.822 44.851 ;
     RECT  227.412 44.213 227.934 45.023 ;
     RECT  228.96 43.709 229.497 45.211 ;
     RECT  232.56 44.851 258.822 45.301 ;
     RECT  228.276 45.211 229.497 45.419 ;
     RECT  232.56 45.301 258.894 45.455 ;
     RECT  232.56 45.455 258.714 45.535 ;
     RECT  232.524 45.535 258.714 45.733 ;
     RECT  228.348 45.419 229.497 45.773 ;
     RECT  228.528 45.773 229.497 45.833 ;
     RECT  232.416 45.733 258.714 46.201 ;
     RECT  232.092 46.201 258.714 46.253 ;
     RECT  232.596 46.253 258.714 46.409 ;
     RECT  90.72 42.755 96.066 46.507 ;
     RECT  97.092 44.609 134.73 46.507 ;
     RECT  232.596 46.409 258.642 46.535 ;
     RECT  232.596 46.535 254.07 46.679 ;
     RECT  232.596 46.679 235.53 46.733 ;
     RECT  229.215 45.833 229.497 46.747 ;
     RECT  90.72 46.507 134.73 46.781 ;
     RECT  232.668 46.733 235.53 46.841 ;
     RECT  229.215 46.747 229.59 46.877 ;
     RECT  227.412 45.023 227.43 46.913 ;
     RECT  236.34 46.679 254.07 47.075 ;
     RECT  236.448 47.075 254.07 47.111 ;
     RECT  236.484 47.111 254.07 47.147 ;
     RECT  232.668 46.841 232.686 47.219 ;
     RECT  236.484 47.147 236.97 47.219 ;
     RECT  237.708 47.147 254.07 47.219 ;
     RECT  233.496 46.841 235.53 47.309 ;
     RECT  236.556 47.219 236.826 47.309 ;
     RECT  237.708 47.219 238.05 47.309 ;
     RECT  236.628 47.309 236.718 47.381 ;
     RECT  237.744 47.309 238.05 47.381 ;
     RECT  238.86 47.219 254.07 47.389 ;
     RECT  254.808 46.535 258.642 47.389 ;
     RECT  237.852 47.381 238.05 47.453 ;
     RECT  238.86 47.389 258.642 47.579 ;
     RECT  238.86 47.579 258.534 47.615 ;
     RECT  238.86 47.615 254.25 47.651 ;
     RECT  254.988 47.615 258.534 47.723 ;
     RECT  135.72 44.375 140.202 47.731 ;
     RECT  141.012 39.857 141.246 47.731 ;
     RECT  135.72 47.731 141.246 47.849 ;
     RECT  238.86 47.651 254.106 47.849 ;
     RECT  254.988 47.723 258.282 47.885 ;
     RECT  237.996 47.453 238.05 47.921 ;
     RECT  238.86 47.849 253.89 47.993 ;
     RECT  238.032 47.921 238.05 48.001 ;
     RECT  238.86 47.993 253.026 48.001 ;
     RECT  233.964 47.309 234.954 48.029 ;
     RECT  254.988 47.885 258.174 48.119 ;
     RECT  135.72 47.849 140.202 48.271 ;
     RECT  236.7 47.381 236.718 48.299 ;
     RECT  238.032 48.001 253.026 48.299 ;
     RECT  135.612 48.271 140.202 48.379 ;
     RECT  135.468 48.379 140.202 48.389 ;
     RECT  135.468 48.389 135.738 48.425 ;
     RECT  254.988 48.119 257.886 48.427 ;
     RECT  254.88 48.427 257.886 48.461 ;
     RECT  238.032 48.299 247.23 48.497 ;
     RECT  234.615 48.029 234.954 48.533 ;
     RECT  248.148 48.299 253.026 48.739 ;
     RECT  253.872 47.993 253.89 48.767 ;
     RECT  254.916 48.461 257.886 48.929 ;
     RECT  238.716 48.497 247.23 48.941 ;
     RECT  239.256 48.941 247.23 48.989 ;
     RECT  239.76 48.989 247.23 49.001 ;
     RECT  254.916 48.929 257.49 49.001 ;
     RECT  254.916 49.001 256.77 49.199 ;
     RECT  248.148 48.739 253.062 49.315 ;
     RECT  254.916 49.199 256.497 49.343 ;
     RECT  248.148 49.315 253.134 49.351 ;
     RECT  255.06 49.343 256.497 49.469 ;
     RECT  90.72 46.781 96.066 49.513 ;
     RECT  248.148 49.351 253.458 49.541 ;
     RECT  250.488 49.541 253.134 49.613 ;
     RECT  240.015 49.001 247.23 49.811 ;
     RECT  241.236 49.811 247.23 49.847 ;
     RECT  241.452 49.847 247.23 49.883 ;
     RECT  241.992 49.883 247.23 49.891 ;
     RECT  248.148 49.541 249.75 49.891 ;
     RECT  241.992 49.891 249.75 49.901 ;
     RECT  255.204 49.469 255.222 49.919 ;
     RECT  241.992 49.901 243.234 50.009 ;
     RECT  244.332 49.901 249.75 50.009 ;
     RECT  250.488 49.613 253.062 50.009 ;
     RECT  244.332 50.009 244.35 50.081 ;
     RECT  250.488 50.009 252.81 50.081 ;
     RECT  241.992 50.009 242.982 50.093 ;
     RECT  241.992 50.093 242.91 50.279 ;
     RECT  250.488 50.081 252.738 50.279 ;
     RECT  241.992 50.279 242.766 50.387 ;
     RECT  241.992 50.387 242.694 50.423 ;
     RECT  252.468 50.279 252.666 50.423 ;
     RECT  248.22 50.009 249.75 50.459 ;
     RECT  250.488 50.279 251.73 50.539 ;
     RECT  245.124 50.009 247.302 50.549 ;
     RECT  248.22 50.459 249.39 50.549 ;
     RECT  250.308 50.539 251.73 50.573 ;
     RECT  249.012 50.549 249.318 50.585 ;
     RECT  250.308 50.573 251.298 50.585 ;
     RECT  245.415 50.549 246.222 50.621 ;
     RECT  248.22 50.549 248.238 50.621 ;
     RECT  249.156 50.585 249.318 50.621 ;
     RECT  250.815 50.585 251.298 50.621 ;
     RECT  252.648 50.423 252.666 50.621 ;
     RECT  90.72 49.513 96.246 50.791 ;
     RECT  97.092 46.781 134.73 50.891 ;
     RECT  136.548 48.389 140.202 51.475 ;
     RECT  141.012 47.849 141.246 51.475 ;
     RECT  226.296 51.403 226.314 51.499 ;
     RECT  226.008 51.499 226.314 51.533 ;
     RECT  226.008 51.533 226.026 51.629 ;
     RECT  227.556 51.601 227.574 51.677 ;
     RECT  136.548 51.475 141.246 51.869 ;
     RECT  90.72 50.791 96.318 51.883 ;
     RECT  226.044 52.267 226.062 52.313 ;
     RECT  90.72 51.883 96.354 52.439 ;
     RECT  97.272 50.891 134.73 52.555 ;
     RECT  97.236 52.555 134.73 52.589 ;
     RECT  90.72 52.439 96.318 53.051 ;
     RECT  97.272 52.589 134.73 53.429 ;
     RECT  97.452 53.429 134.73 53.597 ;
     RECT  135.72 48.425 135.738 53.905 ;
     RECT  136.548 51.869 140.202 53.905 ;
     RECT  90.72 53.051 96.282 54.103 ;
     RECT  135.72 53.905 140.202 54.337 ;
     RECT  135.684 54.337 140.202 54.461 ;
     RECT  97.884 53.597 134.73 54.643 ;
     RECT  135.684 54.461 135.774 54.701 ;
     RECT  97.884 54.643 134.874 54.707 ;
     RECT  97.884 54.707 104.094 55.525 ;
     RECT  135.756 54.701 135.774 55.525 ;
     RECT  135.756 55.525 135.81 55.561 ;
     RECT  136.548 54.461 140.202 55.561 ;
     RECT  135.756 55.561 140.202 56.875 ;
     RECT  141.012 51.869 141.246 56.875 ;
     RECT  97.812 55.525 104.094 57.595 ;
     RECT  104.904 54.707 134.874 57.595 ;
     RECT  97.812 57.595 134.874 58.123 ;
     RECT  97.452 58.123 134.874 58.603 ;
     RECT  90.72 54.103 96.498 58.693 ;
     RECT  97.272 58.603 134.874 58.693 ;
     RECT  135.756 56.875 141.246 58.693 ;
     RECT  90.72 58.693 134.874 58.733 ;
     RECT  90.72 58.733 96.57 58.757 ;
     RECT  135.756 58.693 141.57 59.035 ;
     RECT  135.72 59.035 141.57 59.069 ;
     RECT  97.488 58.733 134.874 59.269 ;
     RECT  97.488 59.269 135.018 59.729 ;
     RECT  135.792 59.069 141.57 59.765 ;
     RECT  90.756 58.757 96.57 60.427 ;
     RECT  97.488 59.729 134.838 60.427 ;
     RECT  135.936 59.765 141.57 60.523 ;
     RECT  90.756 60.427 134.838 60.809 ;
     RECT  135.936 60.523 141.606 60.817 ;
     RECT  90.756 60.809 96.57 60.925 ;
     RECT  135.9 60.817 141.606 60.961 ;
     RECT  135.828 60.961 141.606 61.003 ;
     RECT  90.468 60.925 96.57 61.195 ;
     RECT  135.648 61.003 141.606 61.195 ;
     RECT  90.396 61.195 96.57 61.465 ;
     RECT  97.488 60.809 134.838 61.465 ;
     RECT  135.648 61.195 141.642 61.465 ;
     RECT  97.488 61.465 141.642 61.517 ;
     RECT  97.488 61.517 134.838 61.735 ;
     RECT  90.252 61.465 96.57 61.889 ;
     RECT  90.252 61.889 96.39 62.005 ;
     RECT  97.452 61.735 134.838 62.005 ;
     RECT  90.216 62.005 96.39 62.141 ;
     RECT  97.344 62.005 134.838 62.275 ;
     RECT  135.576 61.517 141.642 62.275 ;
     RECT  2.415 44.375 2.697 62.387 ;
     RECT  7.815 2.413 8.097 62.387 ;
     RECT  13.215 39.929 13.497 62.387 ;
     RECT  18.615 2.413 18.897 62.387 ;
     RECT  24.015 39.929 24.297 62.387 ;
     RECT  29.415 39.209 29.697 62.387 ;
     RECT  34.815 40.157 35.097 62.387 ;
     RECT  40.215 2.413 40.497 62.387 ;
     RECT  45.615 39.929 45.897 62.387 ;
     RECT  51.015 40.157 51.297 62.387 ;
     RECT  56.415 39.929 56.697 62.387 ;
     RECT  61.815 40.061 62.097 62.387 ;
     RECT  67.215 40.157 67.497 62.387 ;
     RECT  72.615 2.413 72.897 62.387 ;
     RECT  78.015 40.289 78.297 62.387 ;
     RECT  83.415 39.749 83.697 62.387 ;
     RECT  88.815 43.565 89.097 62.387 ;
     RECT  97.344 62.275 141.822 62.387 ;
     RECT  142.815 42.089 143.097 62.387 ;
     RECT  148.215 2.413 148.497 62.387 ;
     RECT  153.615 42.089 153.897 62.387 ;
     RECT  159.015 2.413 159.297 62.387 ;
     RECT  164.415 42.089 164.697 62.387 ;
     RECT  169.815 33.341 170.097 62.387 ;
     RECT  175.215 42.089 175.497 62.387 ;
     RECT  180.615 42.449 180.897 62.387 ;
     RECT  186.015 42.089 186.297 62.387 ;
     RECT  191.415 2.413 191.697 62.387 ;
     RECT  196.815 42.089 197.097 62.387 ;
     RECT  202.215 2.413 202.497 62.387 ;
     RECT  207.615 27.869 207.897 62.387 ;
     RECT  213.015 39.857 213.297 62.387 ;
     RECT  218.415 40.469 218.697 62.387 ;
     RECT  223.815 41.675 224.097 62.387 ;
     RECT  229.215 46.877 229.497 62.387 ;
     RECT  234.615 48.533 234.897 62.387 ;
     RECT  240.015 49.811 240.297 62.387 ;
     RECT  245.415 50.621 245.697 62.387 ;
     RECT  250.815 50.621 251.097 62.387 ;
     RECT  256.215 49.469 256.497 62.387 ;
     RECT  261.615 39.389 261.897 62.387 ;
     RECT  267.015 38.129 267.297 62.387 ;
     RECT  90.324 62.141 96.318 62.429 ;
     RECT  116.676 62.387 141.822 62.429 ;
     RECT  90.432 62.429 96.318 62.501 ;
     RECT  116.676 62.429 141.75 62.525 ;
     RECT  116.712 62.525 141.75 62.573 ;
     RECT  128.448 62.573 139.338 62.609 ;
     RECT  116.712 62.573 127.422 62.621 ;
     RECT  128.448 62.609 134.838 62.621 ;
     RECT  135.576 62.609 139.302 62.621 ;
     RECT  140.364 62.573 141.75 62.621 ;
     RECT  2.415 62.387 2.505 62.657 ;
     RECT  7.815 62.387 7.905 62.657 ;
     RECT  13.215 62.387 13.305 62.657 ;
     RECT  18.615 62.387 18.705 62.657 ;
     RECT  24.015 62.387 24.105 62.657 ;
     RECT  29.415 62.387 29.505 62.657 ;
     RECT  34.815 62.387 34.905 62.657 ;
     RECT  40.215 62.387 40.305 62.657 ;
     RECT  45.615 62.387 45.705 62.657 ;
     RECT  51.015 62.387 51.105 62.657 ;
     RECT  56.415 62.387 56.505 62.657 ;
     RECT  61.815 62.387 61.905 62.657 ;
     RECT  67.215 62.387 67.305 62.657 ;
     RECT  72.615 62.387 72.705 62.657 ;
     RECT  78.015 62.387 78.105 62.657 ;
     RECT  83.415 62.387 83.505 62.657 ;
     RECT  88.815 62.387 88.905 62.657 ;
     RECT  97.344 62.387 115.905 62.657 ;
     RECT  116.784 62.621 124.83 62.657 ;
     RECT  131.76 62.621 132.105 62.657 ;
     RECT  142.815 62.387 142.905 62.657 ;
     RECT  148.215 62.387 148.305 62.657 ;
     RECT  153.615 62.387 153.705 62.657 ;
     RECT  159.015 62.387 159.105 62.657 ;
     RECT  164.415 62.387 164.505 62.657 ;
     RECT  169.815 62.387 169.905 62.657 ;
     RECT  175.215 62.387 175.305 62.657 ;
     RECT  180.615 62.387 180.705 62.657 ;
     RECT  186.015 62.387 186.105 62.657 ;
     RECT  191.415 62.387 191.505 62.657 ;
     RECT  196.815 62.387 196.905 62.657 ;
     RECT  202.215 62.387 202.305 62.657 ;
     RECT  207.615 62.387 207.705 62.657 ;
     RECT  213.015 62.387 213.105 62.657 ;
     RECT  218.415 62.387 218.505 62.657 ;
     RECT  223.815 62.387 223.905 62.657 ;
     RECT  229.215 62.387 229.305 62.657 ;
     RECT  234.615 62.387 234.705 62.657 ;
     RECT  240.015 62.387 240.105 62.657 ;
     RECT  245.415 62.387 245.505 62.657 ;
     RECT  250.815 62.387 250.905 62.657 ;
     RECT  256.215 62.387 256.305 62.657 ;
     RECT  261.615 62.387 261.705 62.657 ;
     RECT  267.015 62.387 267.105 62.657 ;
     RECT  97.344 62.657 115.506 62.669 ;
     RECT  116.784 62.657 120.618 62.669 ;
     RECT  121.392 62.657 124.83 62.669 ;
     RECT  126.288 62.621 127.098 62.669 ;
     RECT  135.576 62.621 139.086 62.669 ;
     RECT  140.544 62.621 141.75 62.669 ;
     RECT  90.54 62.501 96.318 62.717 ;
     RECT  97.344 62.669 106.542 62.717 ;
     RECT  107.316 62.669 115.506 62.717 ;
     RECT  116.928 62.669 120.618 62.717 ;
     RECT  121.392 62.669 124.686 62.717 ;
     RECT  133.524 62.621 134.838 62.717 ;
     RECT  135.72 62.669 139.086 62.717 ;
     RECT  104.544 62.717 105.606 62.765 ;
     RECT  108.936 62.717 111.114 62.765 ;
     RECT  121.392 62.717 121.986 62.765 ;
     RECT  122.94 62.717 122.958 62.765 ;
     RECT  126.468 62.669 127.098 62.765 ;
     RECT  131.76 62.657 131.994 62.765 ;
     RECT  135.72 62.717 135.738 62.765 ;
     RECT  136.98 62.717 139.086 62.765 ;
     RECT  94.032 62.717 94.734 62.813 ;
     RECT  99.756 62.717 100.026 62.813 ;
     RECT  126.576 62.765 127.098 62.813 ;
     RECT  137.664 62.765 139.086 62.813 ;
     RECT  104.544 62.765 105.39 62.861 ;
     RECT  126.576 62.813 126.594 62.861 ;
     RECT  104.796 62.861 104.814 62.909 ;
     RECT  109.188 62.765 111.114 62.909 ;
     RECT  95.688 62.717 96.318 63.293 ;
     RECT  109.188 62.909 110.034 63.293 ;
     RECT  128.448 62.621 129.726 63.293 ;
     RECT  130.824 62.621 130.842 63.293 ;
     RECT  131.832 62.765 131.994 63.293 ;
     RECT  138.384 62.813 139.086 63.341 ;
     RECT  109.944 63.293 110.034 63.821 ;
     RECT  95.688 63.293 96.282 63.869 ;
     RECT  110.016 63.821 110.034 63.869 ;
     RECT  111.096 62.909 111.114 63.869 ;
     RECT  112.824 62.717 113.49 63.869 ;
     RECT  114.444 62.717 115.146 63.869 ;
     RECT  119.052 62.717 119.07 63.869 ;
     RECT  133.524 62.717 133.974 63.869 ;
     RECT  138.384 63.341 138.654 63.869 ;
     RECT  140.652 62.669 141.39 63.869 ;
     RECT  131.832 63.293 131.85 64.219 ;
     RECT  128.448 63.293 129.546 64.363 ;
     RECT  137.268 64.267 137.286 64.363 ;
     RECT  131.292 64.219 131.85 64.397 ;
     RECT  132.84 64.219 132.858 64.397 ;
     RECT  128.052 64.363 129.546 64.411 ;
     RECT  137.16 64.363 137.286 64.411 ;
     RECT  95.688 63.869 95.706 64.445 ;
     RECT  98.856 64.411 98.874 64.459 ;
     RECT  121.968 62.765 121.986 64.459 ;
     RECT  127.512 64.411 129.546 64.459 ;
     RECT  131.832 64.397 131.85 64.493 ;
     RECT  98.856 64.459 99.126 64.507 ;
     RECT  100.26 64.459 100.278 64.507 ;
     RECT  121.032 64.315 121.05 64.507 ;
     RECT  121.788 64.459 121.986 64.507 ;
     RECT  137.16 64.411 137.862 64.507 ;
     RECT  130.716 64.411 130.914 64.541 ;
     RECT  141.084 63.869 141.39 64.541 ;
     RECT  125.028 64.459 125.046 64.555 ;
     RECT  126.216 64.459 126.234 64.555 ;
     RECT  138.6 63.869 138.654 64.555 ;
     RECT  139.644 64.459 139.662 64.555 ;
     RECT  123.228 64.411 123.606 64.589 ;
     RECT  130.716 64.541 130.734 64.589 ;
     RECT  138.6 64.555 139.662 64.589 ;
     RECT  100.152 64.507 100.278 64.637 ;
     RECT  117 62.717 117.486 64.637 ;
     RECT  121.032 64.507 121.986 64.637 ;
     RECT  127.368 64.459 129.546 64.637 ;
     RECT  137.016 64.507 137.862 64.637 ;
     RECT  93.456 64.459 93.474 64.685 ;
     RECT  94.68 64.459 94.698 64.685 ;
     RECT  98.424 64.507 99.126 64.685 ;
     RECT  100.152 64.637 100.17 64.685 ;
     RECT  105.876 63.835 105.894 64.685 ;
     RECT  107.352 64.507 107.37 64.685 ;
     RECT  109.188 63.293 109.206 64.685 ;
     RECT  112.968 63.869 112.986 64.685 ;
     RECT  117.468 64.637 117.486 64.685 ;
     RECT  121.644 64.637 121.986 64.685 ;
     RECT  123.3 64.589 123.606 64.685 ;
     RECT  125.028 64.555 126.234 64.685 ;
     RECT  127.368 64.637 129.366 64.685 ;
     RECT  132.444 64.555 132.462 64.685 ;
     RECT  133.956 63.869 133.974 64.685 ;
     RECT  137.016 64.637 137.034 64.685 ;
     RECT  137.772 64.637 137.79 64.685 ;
     RECT  138.636 64.589 139.194 64.685 ;
     RECT  141.084 64.541 141.282 64.685 ;
    LAYER M4 ;
     RECT  0.06 38.256 0.097 41.736 ;
     RECT  0.097 38.256 0.133 41.832 ;
     RECT  0.133 38.256 0.241 42.312 ;
     RECT  0.133 43.92 2.293 43.944 ;
     RECT  0.241 38.208 2.329 42.312 ;
     RECT  2.329 38.208 2.365 42.504 ;
     RECT  2.293 43.92 2.365 43.992 ;
     RECT  0.181 33.312 2.408 33.336 ;
     RECT  2.365 38.208 2.408 43.992 ;
     RECT  2.408 2.148 2.512 62.652 ;
     RECT  2.512 2.418 2.704 62.382 ;
     RECT  2.704 38.208 2.819 43.368 ;
     RECT  2.819 43.344 2.867 43.368 ;
     RECT  2.819 38.208 3.485 42.216 ;
     RECT  3.485 38.208 3.557 41.592 ;
     RECT  2.704 33.312 7.808 33.336 ;
     RECT  3.557 38.208 7.808 40.968 ;
     RECT  7.808 2.148 7.912 62.652 ;
     RECT  7.912 2.418 8.104 62.382 ;
     RECT  8.104 33.312 13.208 33.336 ;
     RECT  8.104 38.208 13.208 40.968 ;
     RECT  13.208 2.148 13.312 62.652 ;
     RECT  13.312 2.418 13.504 62.382 ;
     RECT  13.504 33.312 18.608 33.336 ;
     RECT  13.504 38.208 18.608 40.968 ;
     RECT  18.608 2.148 18.712 62.652 ;
     RECT  18.712 2.418 18.904 62.382 ;
     RECT  18.904 33.312 24.008 33.336 ;
     RECT  18.904 38.208 24.008 40.968 ;
     RECT  24.008 2.148 24.112 62.652 ;
     RECT  24.112 2.418 24.304 62.382 ;
     RECT  24.304 33.312 29.408 33.336 ;
     RECT  24.304 38.208 29.408 40.968 ;
     RECT  29.408 2.148 29.512 62.652 ;
     RECT  29.512 2.418 29.704 62.382 ;
     RECT  29.704 33.312 34.808 33.336 ;
     RECT  29.704 38.208 34.808 40.968 ;
     RECT  34.808 2.148 34.912 62.652 ;
     RECT  34.912 2.418 35.104 62.382 ;
     RECT  35.104 33.312 40.208 33.336 ;
     RECT  35.104 38.208 40.208 40.968 ;
     RECT  40.208 2.148 40.312 62.652 ;
     RECT  40.312 2.418 40.504 62.382 ;
     RECT  40.504 33.312 45.608 33.336 ;
     RECT  40.504 38.208 45.608 40.968 ;
     RECT  45.608 2.148 45.712 62.652 ;
     RECT  45.712 2.418 45.904 62.382 ;
     RECT  45.904 33.312 51.008 33.336 ;
     RECT  45.904 38.208 51.008 40.968 ;
     RECT  51.008 2.148 51.112 62.652 ;
     RECT  51.112 2.418 51.304 62.382 ;
     RECT  51.304 33.312 56.408 33.336 ;
     RECT  51.304 38.208 56.408 40.968 ;
     RECT  56.408 2.148 56.512 62.652 ;
     RECT  56.512 2.418 56.704 62.382 ;
     RECT  56.704 33.312 61.808 33.336 ;
     RECT  56.704 38.208 61.808 40.968 ;
     RECT  61.808 2.148 61.912 62.652 ;
     RECT  61.912 2.418 62.104 62.382 ;
     RECT  62.104 33.312 67.208 33.336 ;
     RECT  62.104 38.208 67.208 40.968 ;
     RECT  67.208 2.148 67.312 62.652 ;
     RECT  67.312 2.418 67.504 62.382 ;
     RECT  67.504 33.312 72.608 33.336 ;
     RECT  67.504 38.208 72.608 40.968 ;
     RECT  72.608 2.148 72.712 62.652 ;
     RECT  72.712 2.418 72.904 62.382 ;
     RECT  72.904 33.312 78.008 33.336 ;
     RECT  72.904 38.208 78.008 40.968 ;
     RECT  78.008 2.148 78.112 62.652 ;
     RECT  78.112 2.418 78.304 62.382 ;
     RECT  78.304 33.312 83.408 33.336 ;
     RECT  78.304 38.208 83.408 40.968 ;
     RECT  83.408 2.148 83.512 62.652 ;
     RECT  83.512 2.418 83.704 62.382 ;
     RECT  85.921 37.008 85.961 37.032 ;
     RECT  83.704 33.312 87.445 33.336 ;
     RECT  85.961 37.011 87.445 37.029 ;
     RECT  87.445 37.008 87.469 37.032 ;
     RECT  87.445 32.784 87.491 33.336 ;
     RECT  87.469 36.864 87.779 37.032 ;
     RECT  87.733 43.344 87.797 43.368 ;
     RECT  87.491 32.787 88.808 33.336 ;
     RECT  87.779 36.864 88.808 36.888 ;
     RECT  83.704 38.208 88.808 40.968 ;
     RECT  88.808 2.148 88.912 62.652 ;
     RECT  88.912 2.418 89.104 62.382 ;
     RECT  89.797 0.096 89.893 0.12 ;
     RECT  89.893 0.096 89.993 0.6 ;
     RECT  89.989 1.728 90.085 1.752 ;
     RECT  90.205 62.112 90.241 62.136 ;
     RECT  90.085 1.728 90.373 1.8 ;
     RECT  90.241 61.488 90.469 62.136 ;
     RECT  90.373 1.728 90.529 1.848 ;
     RECT  90.469 2.88 90.529 2.904 ;
     RECT  89.104 36.864 90.565 36.888 ;
     RECT  90.565 36.768 90.709 36.888 ;
     RECT  90.421 35.568 90.853 35.592 ;
     RECT  90.709 36.768 90.853 37.032 ;
     RECT  89.104 38.208 90.853 40.968 ;
     RECT  89.993 0.096 91.001 0.12 ;
     RECT  90.853 35.328 91.145 35.592 ;
     RECT  90.745 58.704 91.249 58.728 ;
     RECT  91.213 16.128 91.283 16.152 ;
     RECT  91.249 58.656 91.333 58.728 ;
     RECT  90.781 60.384 91.333 60.408 ;
     RECT  90.469 61.488 91.333 62.712 ;
     RECT  91.381 52.848 91.393 52.872 ;
     RECT  91.393 52.848 91.429 53.592 ;
     RECT  91.333 58.56 91.429 58.728 ;
     RECT  91.429 18.24 91.465 18.264 ;
     RECT  91.429 52.56 91.475 53.592 ;
     RECT  91.429 58.56 91.477 58.824 ;
     RECT  91.475 52.56 91.523 52.584 ;
     RECT  91.477 58.128 91.541 58.824 ;
     RECT  91.333 60.384 91.577 62.712 ;
     RECT  91.541 58.704 91.613 58.824 ;
     RECT  91.237 22.8 91.645 22.824 ;
     RECT  91.613 58.704 91.649 58.728 ;
     RECT  91.577 60.384 91.681 61.032 ;
     RECT  91.645 22.8 91.715 22.92 ;
     RECT  91.681 60.288 91.717 61.032 ;
     RECT  91.715 22.8 91.753 22.824 ;
     RECT  91.717 60.192 91.763 61.032 ;
     RECT  91.681 14.112 91.765 14.712 ;
     RECT  91.765 14.112 91.811 15.432 ;
     RECT  90.529 1.728 91.813 2.904 ;
     RECT  91.811 15.312 91.829 15.432 ;
     RECT  89.104 43.536 91.897 43.56 ;
     RECT  91.753 22.752 91.901 22.824 ;
     RECT  91.829 15.312 91.907 15.336 ;
     RECT  91.861 21.024 91.933 21.144 ;
     RECT  91.033 26.64 91.933 26.664 ;
     RECT  91.145 35.568 91.969 35.592 ;
     RECT  90.853 36.768 91.969 40.968 ;
     RECT  91.933 21.024 92.003 21.672 ;
     RECT  92.003 21.024 92.005 21.144 ;
     RECT  91.933 26.208 92.005 26.664 ;
     RECT  91.933 50.256 92.005 50.28 ;
     RECT  92.005 26.208 92.041 27.384 ;
     RECT  92.005 46.464 92.051 46.488 ;
     RECT  92.005 20.16 92.053 21.144 ;
     RECT  91.969 35.568 92.053 40.968 ;
     RECT  92.053 19.968 92.081 21.144 ;
     RECT  92.041 3.936 92.099 3.96 ;
     RECT  92.005 5.232 92.101 5.256 ;
     RECT  90.745 31.248 92.149 31.272 ;
     RECT  92.081 21.024 92.153 21.144 ;
     RECT  92.149 31.248 92.185 31.656 ;
     RECT  89.104 32.787 92.185 33.336 ;
     RECT  92.081 19.968 92.189 19.992 ;
     RECT  92.149 25.056 92.293 25.08 ;
     RECT  92.041 26.16 92.293 27.384 ;
     RECT  92.293 25.056 92.365 27.384 ;
     RECT  91.669 28.512 92.365 28.536 ;
     RECT  92.053 35.568 92.405 41.64 ;
     RECT  91.897 43.248 92.437 43.56 ;
     RECT  92.365 25.056 92.473 28.536 ;
     RECT  91.475 53.568 92.533 53.592 ;
     RECT  91.609 56.448 92.533 56.472 ;
     RECT  91.861 30.144 92.545 30.168 ;
     RECT  92.473 25.056 92.579 28.824 ;
     RECT  91.813 1.728 92.581 2.952 ;
     RECT  92.545 30.144 92.581 30.216 ;
     RECT  92.185 31.248 92.581 33.336 ;
     RECT  92.533 53.568 92.581 54.216 ;
     RECT  91.763 60.192 92.617 60.312 ;
     RECT  92.581 53.568 92.629 54.312 ;
     RECT  92.533 55.776 92.629 56.472 ;
     RECT  92.617 60.144 92.629 60.312 ;
     RECT  92.629 59.904 92.653 60.312 ;
     RECT  92.629 53.568 92.675 54.696 ;
     RECT  92.579 27.888 92.677 28.824 ;
     RECT  91.285 45.36 92.677 45.384 ;
     RECT  92.005 49.872 92.725 50.28 ;
     RECT  91.577 62.112 92.725 62.712 ;
     RECT  92.101 5.232 92.729 5.736 ;
     RECT  92.677 45.024 92.729 45.576 ;
     RECT  92.675 54.288 92.729 54.696 ;
     RECT  92.677 27.888 92.761 29.064 ;
     RECT  92.581 30.144 92.761 33.336 ;
     RECT  92.653 59.28 92.773 60.312 ;
     RECT  92.725 61.584 92.773 62.712 ;
     RECT  92.761 27.888 92.801 33.336 ;
     RECT  92.629 55.68 92.837 56.472 ;
     RECT  92.725 49.872 92.867 50.76 ;
     RECT  92.729 54.384 92.867 54.696 ;
     RECT  92.579 25.056 92.873 26.808 ;
     RECT  91.901 22.752 92.917 22.776 ;
     RECT  92.653 23.904 92.917 23.928 ;
     RECT  92.581 1.728 92.941 3.048 ;
     RECT  92.405 36.48 93.017 41.64 ;
     RECT  92.837 55.872 93.053 56.472 ;
     RECT  93.049 47.856 93.107 47.88 ;
     RECT  93.053 56.448 93.109 56.472 ;
     RECT  92.773 59.28 93.109 62.712 ;
     RECT  92.153 21.024 93.121 21.048 ;
     RECT  93.121 21.024 93.161 21.144 ;
     RECT  92.867 49.872 93.161 50.712 ;
     RECT  93.109 56.448 93.205 57.048 ;
     RECT  93.205 56.448 93.229 57.624 ;
     RECT  92.729 5.232 93.233 5.256 ;
     RECT  93.205 19.632 93.253 19.656 ;
     RECT  91.811 14.112 93.265 14.136 ;
     RECT  92.917 22.752 93.265 23.928 ;
     RECT  91.465 17.856 93.301 18.264 ;
     RECT  93.253 64.368 93.301 64.392 ;
     RECT  93.253 0.096 93.337 0.12 ;
     RECT  92.941 1.104 93.337 3.048 ;
     RECT  93.301 64.368 93.349 64.488 ;
     RECT  93.161 21.12 93.373 21.144 ;
     RECT  93.265 22.32 93.373 23.928 ;
     RECT  93.301 35.184 93.373 35.208 ;
     RECT  93.017 36.48 93.373 36.792 ;
     RECT  93.229 56.448 93.373 58.152 ;
     RECT  93.109 59.232 93.373 62.712 ;
     RECT  93.349 64.368 93.445 64.584 ;
     RECT  93.445 64.368 93.491 64.68 ;
     RECT  92.873 25.056 93.493 26.616 ;
     RECT  93.253 7.248 93.637 7.272 ;
     RECT  93.017 37.968 93.661 41.64 ;
     RECT  92.437 43.008 93.661 43.56 ;
     RECT  93.625 11.424 93.769 11.448 ;
     RECT  92.867 54.672 93.913 54.696 ;
     RECT  93.373 56.448 94.021 62.712 ;
     RECT  92.801 31.632 94.057 33.336 ;
     RECT  93.337 0.096 94.208 3.048 ;
     RECT  93.637 7.248 94.208 7.944 ;
     RECT  93.769 11.424 94.208 11.976 ;
     RECT  93.265 14.112 94.208 14.856 ;
     RECT  93.301 17.088 94.208 18.408 ;
     RECT  93.253 19.392 94.208 19.656 ;
     RECT  93.373 21.12 94.208 23.928 ;
     RECT  93.493 24.96 94.208 26.616 ;
     RECT  92.801 27.888 94.208 30.216 ;
     RECT  94.057 31.248 94.208 33.672 ;
     RECT  93.373 35.184 94.208 36.792 ;
     RECT  93.661 37.968 94.208 43.56 ;
     RECT  92.729 45.024 94.208 45.048 ;
     RECT  93.161 49.872 94.208 49.896 ;
     RECT  93.157 53.28 94.208 53.304 ;
     RECT  93.913 54.672 94.208 54.744 ;
     RECT  94.021 56.448 94.208 62.808 ;
     RECT  94.208 0.096 94.504 62.808 ;
     RECT  94.504 27.936 94.565 29.592 ;
     RECT  94.504 22.8 94.601 22.824 ;
     RECT  94.504 2.88 94.637 2.904 ;
     RECT  94.504 7.344 94.637 7.656 ;
     RECT  94.504 31.728 94.643 35.208 ;
     RECT  94.504 37.968 94.643 41.16 ;
     RECT  94.504 60.096 94.643 62.808 ;
     RECT  93.491 64.368 94.643 64.632 ;
     RECT  94.643 64.464 94.669 64.632 ;
     RECT  94.643 37.968 94.673 41.016 ;
     RECT  94.504 56.496 94.673 58.68 ;
     RECT  94.565 27.936 94.691 29.112 ;
     RECT  94.643 60.096 94.691 60.408 ;
     RECT  94.669 64.464 94.709 64.68 ;
     RECT  94.643 61.44 94.739 62.808 ;
     RECT  94.709 64.56 94.739 64.68 ;
     RECT  94.739 61.488 94.745 62.808 ;
     RECT  94.643 31.728 94.781 33.576 ;
     RECT  94.643 34.752 94.781 35.208 ;
     RECT  94.691 60.144 94.931 60.408 ;
     RECT  94.931 60.144 95.075 60.168 ;
     RECT  94.745 61.488 95.105 62.712 ;
     RECT  94.781 32.787 95.213 33.576 ;
     RECT  94.504 50.064 95.219 50.712 ;
     RECT  94.504 25.68 95.459 26.04 ;
     RECT  95.219 50.064 95.459 50.136 ;
     RECT  94.673 56.496 95.533 58.152 ;
     RECT  95.533 56.352 95.537 58.152 ;
     RECT  94.504 0.096 95.603 1.752 ;
     RECT  95.537 56.352 95.603 57.048 ;
     RECT  95.605 49.536 95.651 49.56 ;
     RECT  94.504 43.008 95.677 43.56 ;
     RECT  95.105 61.584 95.681 62.712 ;
     RECT  95.603 0.096 95.699 1.128 ;
     RECT  94.504 21.408 95.701 21.432 ;
     RECT  95.537 58.128 95.713 58.152 ;
     RECT  95.459 25.68 95.747 25.704 ;
     RECT  95.701 21.264 95.753 21.432 ;
     RECT  94.673 38.208 95.789 41.016 ;
     RECT  95.699 0.096 95.795 1.08 ;
     RECT  94.781 31.728 95.797 31.752 ;
     RECT  95.797 31.344 95.821 31.752 ;
     RECT  95.213 32.787 95.821 33.336 ;
     RECT  95.603 56.736 95.825 57.048 ;
     RECT  94.781 35.184 95.845 35.208 ;
     RECT  95.821 31.344 95.861 33.336 ;
     RECT  95.861 31.632 95.891 33.336 ;
     RECT  95.677 64.416 95.891 64.44 ;
     RECT  95.713 58.128 95.893 58.632 ;
     RECT  95.795 0.096 95.897 0.12 ;
     RECT  95.891 31.632 95.897 31.752 ;
     RECT  95.893 53.376 95.929 53.4 ;
     RECT  94.504 36.192 95.939 36.792 ;
     RECT  95.929 52.992 95.969 53.4 ;
     RECT  95.893 58.128 96.085 58.728 ;
     RECT  95.969 52.992 96.131 53.016 ;
     RECT  95.681 62.112 96.149 62.712 ;
     RECT  96.149 62.112 96.179 62.184 ;
     RECT  96.085 51.888 96.181 51.912 ;
     RECT  96.181 51.888 96.227 52.584 ;
     RECT  96.253 63.84 96.289 63.864 ;
     RECT  96.227 51.888 96.365 51.912 ;
     RECT  96.289 63.264 96.371 63.864 ;
     RECT  95.845 34.848 96.401 35.208 ;
     RECT  96.085 58.128 96.401 58.776 ;
     RECT  96.179 62.112 96.401 62.136 ;
     RECT  96.371 63.84 96.467 63.864 ;
     RECT  96.401 58.128 96.757 58.728 ;
     RECT  96.721 46.512 96.803 46.776 ;
     RECT  96.805 1.728 96.901 1.752 ;
     RECT  96.709 2.88 96.901 2.904 ;
     RECT  96.997 0.576 97.049 0.6 ;
     RECT  95.701 16.176 97.153 16.2 ;
     RECT  95.939 36.768 97.187 36.792 ;
     RECT  95.789 38.304 97.189 41.016 ;
     RECT  97.153 15.888 97.193 16.2 ;
     RECT  97.193 15.888 97.235 15.912 ;
     RECT  97.189 60.432 97.283 60.456 ;
     RECT  95.897 31.632 97.369 31.656 ;
     RECT  95.891 32.787 97.369 33.336 ;
     RECT  97.225 52.56 97.369 52.584 ;
     RECT  96.901 1.728 97.381 2.904 ;
     RECT  96.757 57.84 97.381 58.728 ;
     RECT  97.285 62.688 97.381 62.712 ;
     RECT  97.369 31.632 97.409 33.336 ;
     RECT  97.369 52.32 97.427 52.584 ;
     RECT  94.637 7.632 97.477 7.656 ;
     RECT  97.429 53.568 97.481 53.592 ;
     RECT  97.477 15.408 97.523 15.432 ;
     RECT  97.381 1.728 97.573 2.952 ;
     RECT  97.381 57.84 97.589 58.872 ;
     RECT  97.427 52.56 97.667 52.584 ;
     RECT  97.693 53.376 97.763 53.4 ;
     RECT  97.381 62.64 97.765 62.712 ;
     RECT  95.677 42.144 97.861 43.56 ;
     RECT  97.861 42.144 97.873 44.616 ;
     RECT  97.873 42.144 97.913 44.904 ;
     RECT  97.589 57.84 97.913 58.776 ;
     RECT  96.803 46.752 97.945 46.776 ;
     RECT  94.691 27.936 97.949 28.824 ;
     RECT  97.945 46.656 97.985 46.776 ;
     RECT  97.189 38.256 98.017 41.016 ;
     RECT  95.825 56.736 98.053 56.76 ;
     RECT  97.913 57.84 98.053 58.728 ;
     RECT  98.017 37.68 98.089 41.016 ;
     RECT  97.913 42.144 98.089 43.848 ;
     RECT  97.573 1.152 98.093 2.952 ;
     RECT  97.949 28.8 98.093 28.824 ;
     RECT  98.053 56.736 98.099 58.728 ;
     RECT  98.245 64.464 98.341 64.488 ;
     RECT  98.053 0.096 98.345 0.12 ;
     RECT  98.341 64.464 98.413 64.584 ;
     RECT  97.765 62.592 98.437 62.712 ;
     RECT  98.093 1.152 98.489 2.28 ;
     RECT  98.089 37.68 98.525 43.848 ;
     RECT  98.305 60.96 98.557 60.984 ;
     RECT  97.913 44.88 98.561 44.904 ;
     RECT  97.409 31.92 98.593 33.336 ;
     RECT  97.945 47.856 98.629 47.88 ;
     RECT  98.557 60.384 98.665 60.984 ;
     RECT  98.413 64.464 98.677 64.68 ;
     RECT  97.985 46.656 98.701 46.68 ;
     RECT  98.629 6.288 98.821 6.312 ;
     RECT  98.665 60.048 98.821 60.984 ;
     RECT  98.821 5.712 98.917 6.312 ;
     RECT  98.821 52.464 98.917 52.488 ;
     RECT  98.677 64.416 98.917 64.68 ;
     RECT  98.099 57.312 98.953 58.728 ;
     RECT  98.821 59.856 98.953 60.984 ;
     RECT  98.593 31.92 99.109 33.912 ;
     RECT  96.401 35.184 99.109 35.208 ;
     RECT  98.917 64.368 99.155 64.68 ;
     RECT  98.377 27.072 99.157 27.096 ;
     RECT  99.157 27.072 99.169 27.624 ;
     RECT  98.953 57.312 99.205 60.984 ;
     RECT  98.437 62.112 99.205 62.712 ;
     RECT  97.477 7.632 99.421 8.472 ;
     RECT  99.349 9.504 99.421 9.528 ;
     RECT  99.061 3.408 99.457 3.432 ;
     RECT  98.725 4.56 99.457 4.584 ;
     RECT  99.457 3.408 99.493 4.584 ;
     RECT  98.917 5.712 99.493 6.36 ;
     RECT  94.504 14.112 99.493 14.136 ;
     RECT  98.917 20.208 99.493 20.232 ;
     RECT  95.753 21.408 99.493 21.432 ;
     RECT  99.061 22.8 99.493 22.824 ;
     RECT  98.525 38.4 99.493 43.848 ;
     RECT  99.169 26.736 99.601 27.624 ;
     RECT  98.489 1.68 99.608 2.28 ;
     RECT  99.493 3.408 99.608 6.36 ;
     RECT  99.421 7.632 99.608 9.528 ;
     RECT  99.445 10.608 99.608 10.632 ;
     RECT  99.493 13.008 99.608 14.136 ;
     RECT  99.493 20.064 99.608 22.824 ;
     RECT  98.845 24.48 99.608 24.504 ;
     RECT  99.601 26.736 99.608 28.44 ;
     RECT  99.601 30.336 99.608 30.36 ;
     RECT  99.109 31.92 99.608 35.208 ;
     RECT  99.493 38.16 99.608 43.848 ;
     RECT  98.701 45.024 99.608 46.68 ;
     RECT  98.629 47.856 99.608 48.84 ;
     RECT  98.917 52.464 99.608 52.824 ;
     RECT  99.493 54.672 99.608 54.696 ;
     RECT  99.205 57.312 99.608 62.712 ;
     RECT  99.608 1.68 99.685 62.712 ;
     RECT  99.685 1.68 99.731 62.808 ;
     RECT  99.313 0.528 99.781 0.552 ;
     RECT  99.781 0.288 99.877 0.552 ;
     RECT  99.731 1.728 99.904 62.808 ;
     RECT  99.904 21.072 99.965 23.352 ;
     RECT  99.877 0.288 99.973 0.6 ;
     RECT  99.904 18 100.019 18.024 ;
     RECT  99.965 21.072 100.019 21.096 ;
     RECT  99.973 0.192 100.033 0.6 ;
     RECT  99.904 55.392 100.037 62.808 ;
     RECT  99.904 42.24 100.073 44.472 ;
     RECT  99.904 1.728 100.115 3.432 ;
     RECT  99.155 64.368 100.115 64.632 ;
     RECT  100.115 64.416 100.141 64.632 ;
     RECT  99.904 8.448 100.145 9.096 ;
     RECT  100.115 1.728 100.211 2.904 ;
     RECT  100.141 64.416 100.211 64.68 ;
     RECT  99.965 22.128 100.259 23.352 ;
     RECT  100.145 8.448 100.289 9.048 ;
     RECT  100.211 2.88 100.307 2.904 ;
     RECT  99.904 19.92 100.307 20.088 ;
     RECT  99.904 52.8 100.307 52.824 ;
     RECT  100.211 64.416 100.307 64.632 ;
     RECT  99.904 45.696 100.325 46.728 ;
     RECT  99.904 5.664 100.355 6.36 ;
     RECT  100.325 45.696 100.397 46.392 ;
     RECT  100.259 22.128 100.505 22.536 ;
     RECT  100.355 6.336 100.613 6.36 ;
     RECT  100.037 55.392 100.691 62.712 ;
     RECT  99.904 26.784 100.721 26.808 ;
     RECT  99.904 28.416 100.721 35.832 ;
     RECT  99.904 37.44 100.757 41.064 ;
     RECT  100.307 64.416 100.787 64.536 ;
     RECT  100.691 59.232 100.829 62.712 ;
     RECT  100.721 28.416 100.835 33.624 ;
     RECT  100.835 28.416 100.865 33.336 ;
     RECT  100.721 34.752 100.883 35.832 ;
     RECT  100.865 28.416 100.901 31.752 ;
     RECT  100.505 22.176 100.937 22.536 ;
     RECT  100.901 30 100.937 31.752 ;
     RECT  99.904 24.48 100.969 24.648 ;
     RECT  100.307 19.92 100.973 19.944 ;
     RECT  100.937 30.48 100.973 31.752 ;
     RECT  99.904 54.336 100.973 54.36 ;
     RECT  100.757 37.44 101.005 40.968 ;
     RECT  100.969 23.952 101.009 24.648 ;
     RECT  100.973 30.48 101.009 31.32 ;
     RECT  100.883 34.848 101.009 35.832 ;
     RECT  100.397 45.696 101.009 45.72 ;
     RECT  101.009 23.952 101.027 23.976 ;
     RECT  100.691 55.392 101.045 57.864 ;
     RECT  100.033 0.096 101.125 0.6 ;
     RECT  101.009 34.848 101.153 35.304 ;
     RECT  101.041 6.72 101.261 6.744 ;
     RECT  101.153 35.28 101.267 35.304 ;
     RECT  101.005 37.056 101.369 40.968 ;
     RECT  100.211 1.728 101.401 1.848 ;
     RECT  101.009 30.48 101.405 30.84 ;
     RECT  100.829 59.28 101.405 62.712 ;
     RECT  100.289 8.448 101.413 8.904 ;
     RECT  101.401 17.664 101.459 17.688 ;
     RECT  100.073 42.432 101.477 44.472 ;
     RECT  101.413 8.448 101.513 9.432 ;
     RECT  101.405 30.48 101.555 30.504 ;
     RECT  101.473 51.216 101.555 51.24 ;
     RECT  101.125 0.096 101.605 0.696 ;
     RECT  101.401 1.728 101.605 2.28 ;
     RECT  100.901 28.416 101.653 28.44 ;
     RECT  101.045 57.024 101.653 57.864 ;
     RECT  101.605 0.096 101.657 2.28 ;
     RECT  101.653 27.888 101.699 28.44 ;
     RECT  101.653 57.024 101.701 58.056 ;
     RECT  101.369 37.632 101.729 40.968 ;
     RECT  101.405 59.808 101.729 62.712 ;
     RECT  101.689 52.464 101.747 52.488 ;
     RECT  101.729 59.808 101.747 60.456 ;
     RECT  101.701 57.024 101.845 58.152 ;
     RECT  101.797 52.992 101.891 53.016 ;
     RECT  101.845 57.024 101.945 58.728 ;
     RECT  101.747 60.288 101.945 60.456 ;
     RECT  101.945 57.84 102.089 58.728 ;
     RECT  101.729 38.4 102.125 40.968 ;
     RECT  101.945 60.288 102.131 60.312 ;
     RECT  101.657 1.728 102.323 2.28 ;
     RECT  101.477 42.432 102.449 43.944 ;
     RECT  101.729 61.488 102.515 62.712 ;
     RECT  101.657 0.096 102.757 0.6 ;
     RECT  102.515 61.536 102.803 62.712 ;
     RECT  101.045 55.392 102.949 55.416 ;
     RECT  102.949 54.672 102.995 55.416 ;
     RECT  102.757 0.096 103.025 0.648 ;
     RECT  102.449 42.432 103.025 43.56 ;
     RECT  102.089 57.84 103.093 57.864 ;
     RECT  102.949 59.28 103.093 59.304 ;
     RECT  103.093 52.992 103.139 53.016 ;
     RECT  102.323 1.728 103.187 1.896 ;
     RECT  102.125 38.4 103.235 40.68 ;
     RECT  103.237 51.888 103.273 51.912 ;
     RECT  103.273 51.888 103.331 52.44 ;
     RECT  103.331 51.888 103.421 51.912 ;
     RECT  103.093 57.84 103.621 59.304 ;
     RECT  103.597 51.264 103.667 51.528 ;
     RECT  103.621 57.6 103.669 59.304 ;
     RECT  103.025 43.392 103.717 43.56 ;
     RECT  102.481 50.16 103.717 50.184 ;
     RECT  103.597 45.6 103.763 45.624 ;
     RECT  103.525 48.432 103.763 48.456 ;
     RECT  103.717 50.16 103.763 50.328 ;
     RECT  103.025 0.096 103.961 0.6 ;
     RECT  102.995 54.912 104.173 55.416 ;
     RECT  103.961 0.096 104.249 0.168 ;
     RECT  103.235 40.416 104.317 40.68 ;
     RECT  103.921 42.192 104.317 42.216 ;
     RECT  103.667 51.504 104.389 51.528 ;
     RECT  103.669 57.6 104.437 59.88 ;
     RECT  104.245 53.568 104.461 53.592 ;
     RECT  104.437 57.6 104.497 60.456 ;
     RECT  102.803 61.584 104.497 62.712 ;
     RECT  104.317 40.416 104.533 42.216 ;
     RECT  104.497 57.6 104.533 62.712 ;
     RECT  103.273 35.904 104.569 35.928 ;
     RECT  104.389 51.504 104.569 51.864 ;
     RECT  104.461 52.992 104.569 53.592 ;
     RECT  104.249 0.144 104.573 0.168 ;
     RECT  104.389 64.608 104.579 64.632 ;
     RECT  104.533 40.368 104.581 42.216 ;
     RECT  103.717 43.392 104.581 44.376 ;
     RECT  100.865 32.736 104.749 33.336 ;
     RECT  103.235 38.4 104.785 39.336 ;
     RECT  104.581 40.368 104.785 44.376 ;
     RECT  104.533 57.6 104.785 62.856 ;
     RECT  104.785 38.4 104.893 44.376 ;
     RECT  103.187 1.728 105.008 1.848 ;
     RECT  102.853 2.88 105.008 2.904 ;
     RECT  101.513 8.448 105.008 8.472 ;
     RECT  99.904 14.112 105.008 14.136 ;
     RECT  103.993 17.088 105.008 17.112 ;
     RECT  100.937 22.512 105.008 22.536 ;
     RECT  101.699 28.416 105.008 28.44 ;
     RECT  104.749 32.208 105.008 33.336 ;
     RECT  104.569 35.904 105.008 36.024 ;
     RECT  104.893 38.256 105.008 44.376 ;
     RECT  103.763 50.304 105.008 50.328 ;
     RECT  104.569 51.504 105.008 53.592 ;
     RECT  104.173 54.672 105.008 55.416 ;
     RECT  104.785 57.6 105.008 62.904 ;
     RECT  105.008 1.728 105.011 62.904 ;
     RECT  105.011 1.728 105.304 62.856 ;
     RECT  105.304 28.416 105.401 29.352 ;
     RECT  105.304 59.232 105.401 62.856 ;
     RECT  105.401 29.328 105.443 29.352 ;
     RECT  105.304 1.728 105.445 3.432 ;
     RECT  105.304 31.344 105.473 33.432 ;
     RECT  105.304 55.776 105.491 55.8 ;
     RECT  105.304 18.768 105.587 18.792 ;
     RECT  105.445 1.104 105.617 3.432 ;
     RECT  105.401 59.232 105.617 62.76 ;
     RECT  105.304 25.488 105.689 26.232 ;
     RECT  105.473 31.92 105.725 31.944 ;
     RECT  105.304 22.512 105.731 23.352 ;
     RECT  105.304 36 105.797 36.024 ;
     RECT  105.829 64.656 105.865 64.68 ;
     RECT  105.689 25.488 105.869 25.704 ;
     RECT  105.865 63.84 105.905 64.68 ;
     RECT  105.905 63.84 105.923 64.632 ;
     RECT  105.304 13.584 106.067 14.136 ;
     RECT  105.304 54.576 106.067 54.696 ;
     RECT  105.304 37.008 106.157 42.216 ;
     RECT  106.157 41.664 106.193 42.216 ;
     RECT  106.193 41.664 106.265 41.976 ;
     RECT  105.937 0.48 106.333 0.552 ;
     RECT  105.617 1.728 106.355 3.432 ;
     RECT  106.309 51.504 106.373 51.528 ;
     RECT  105.304 57.312 106.373 58.152 ;
     RECT  105.304 6.816 106.405 6.888 ;
     RECT  106.373 57.6 106.441 58.152 ;
     RECT  105.617 59.232 106.441 62.712 ;
     RECT  106.405 51.84 106.481 51.864 ;
     RECT  106.441 57.6 106.517 62.712 ;
     RECT  106.067 13.584 106.549 13.608 ;
     RECT  106.355 1.728 106.553 2.904 ;
     RECT  106.549 13.056 106.595 13.608 ;
     RECT  106.517 57.84 106.595 62.712 ;
     RECT  105.304 43.536 106.645 44.376 ;
     RECT  106.067 54.576 106.645 54.6 ;
     RECT  105.473 32.976 106.657 33.432 ;
     RECT  105.304 34.896 106.657 34.92 ;
     RECT  106.645 43.536 106.697 44.76 ;
     RECT  106.645 54.144 106.697 54.6 ;
     RECT  106.405 6.768 106.733 6.888 ;
     RECT  106.657 32.976 106.739 34.92 ;
     RECT  106.693 30.816 106.841 30.84 ;
     RECT  105.304 50.304 106.883 50.328 ;
     RECT  106.157 37.008 106.933 40.68 ;
     RECT  106.739 34.656 106.945 34.92 ;
     RECT  106.741 49.008 106.949 49.032 ;
     RECT  105.304 8.064 106.981 8.472 ;
     RECT  106.945 34.656 106.985 35.112 ;
     RECT  106.933 36.432 106.985 40.68 ;
     RECT  106.595 59.28 107.129 62.712 ;
     RECT  106.733 6.768 107.161 6.792 ;
     RECT  106.985 36.528 107.161 40.68 ;
     RECT  106.265 41.664 107.161 41.688 ;
     RECT  106.933 47.904 107.165 47.928 ;
     RECT  106.333 0.096 107.173 0.552 ;
     RECT  106.553 1.728 107.173 2.76 ;
     RECT  106.981 8.064 107.173 8.52 ;
     RECT  105.923 64.608 107.173 64.632 ;
     RECT  107.161 6.24 107.219 6.792 ;
     RECT  107.173 0.096 107.237 2.76 ;
     RECT  106.985 34.896 107.267 35.112 ;
     RECT  107.267 35.088 107.269 35.112 ;
     RECT  105.304 11.088 107.341 11.112 ;
     RECT  107.161 36.528 107.341 41.688 ;
     RECT  107.173 64.464 107.341 64.632 ;
     RECT  107.341 10.848 107.365 11.112 ;
     RECT  107.365 10.128 107.381 11.112 ;
     RECT  107.381 10.128 107.411 10.872 ;
     RECT  107.341 64.464 107.411 64.68 ;
     RECT  106.739 32.976 107.521 33.624 ;
     RECT  106.837 52.176 107.525 52.2 ;
     RECT  107.173 8.016 107.557 8.52 ;
     RECT  107.341 36.528 107.593 42.024 ;
     RECT  106.697 43.536 107.593 44.472 ;
     RECT  107.557 8.016 107.653 9.096 ;
     RECT  107.411 64.464 107.699 64.632 ;
     RECT  107.237 1.728 107.701 2.76 ;
     RECT  106.513 4.896 107.701 4.92 ;
     RECT  107.593 36.528 107.749 44.472 ;
     RECT  107.219 6.768 107.773 6.792 ;
     RECT  107.701 4.56 107.797 4.92 ;
     RECT  107.773 6.768 107.843 6.984 ;
     RECT  107.749 36.528 107.845 44.52 ;
     RECT  107.653 8.016 107.885 9.144 ;
     RECT  107.701 1.728 107.941 3.24 ;
     RECT  107.797 4.368 107.941 5.208 ;
     RECT  107.885 9.072 107.941 9.144 ;
     RECT  107.411 10.128 107.941 10.248 ;
     RECT  107.699 64.512 107.987 64.632 ;
     RECT  107.941 1.728 108.025 5.208 ;
     RECT  106.909 30.576 108.025 30.6 ;
     RECT  107.845 36.528 108.035 44.568 ;
     RECT  107.521 32.448 108.061 33.624 ;
     RECT  107.269 35.088 108.131 35.16 ;
     RECT  105.731 22.512 108.133 22.536 ;
     RECT  108.025 30.576 108.133 31.32 ;
     RECT  108.061 32.448 108.133 33.672 ;
     RECT  107.129 59.28 108.229 61.176 ;
     RECT  107.129 62.16 108.229 62.712 ;
     RECT  108.133 30.576 108.241 33.672 ;
     RECT  108.035 36.528 108.245 44.52 ;
     RECT  106.595 57.84 108.277 57.864 ;
     RECT  108.229 59.28 108.277 62.712 ;
     RECT  107.941 9.072 108.281 10.248 ;
     RECT  107.237 0.096 108.313 0.552 ;
     RECT  108.133 22.512 108.317 22.776 ;
     RECT  108.281 9.072 108.389 9.096 ;
     RECT  108.131 35.136 108.421 35.16 ;
     RECT  108.313 0.096 108.467 0.6 ;
     RECT  108.241 30.24 108.497 33.672 ;
     RECT  108.421 35.136 108.497 35.88 ;
     RECT  108.245 37.056 108.569 44.52 ;
     RECT  108.467 0.096 108.659 0.552 ;
     RECT  108.569 37.056 108.713 44.376 ;
     RECT  106.697 54.576 108.745 54.6 ;
     RECT  108.497 31.92 108.755 33.672 ;
     RECT  108.025 1.728 108.805 5.688 ;
     RECT  108.805 1.728 108.821 5.736 ;
     RECT  107.843 6.768 108.821 6.792 ;
     RECT  108.745 54.576 108.851 55.272 ;
     RECT  108.821 5.712 108.857 5.736 ;
     RECT  108.821 1.728 108.893 4.008 ;
     RECT  108.277 57.84 108.901 62.712 ;
     RECT  108.755 31.92 108.965 31.944 ;
     RECT  108.497 35.808 108.965 35.88 ;
     RECT  108.805 53.376 108.965 53.4 ;
     RECT  106.595 13.584 108.995 13.608 ;
     RECT  108.949 14.64 108.997 14.664 ;
     RECT  108.497 30.24 109.033 30.744 ;
     RECT  108.893 1.728 109.037 3.912 ;
     RECT  108.997 14.64 109.037 15.576 ;
     RECT  108.713 37.056 109.037 43.848 ;
     RECT  109.037 14.784 109.043 15.576 ;
     RECT  108.317 22.512 109.043 22.536 ;
     RECT  108.997 19.92 109.073 19.944 ;
     RECT  108.659 0.096 109.109 0.216 ;
     RECT  107.987 64.608 109.177 64.632 ;
     RECT  109.037 37.056 109.181 43.56 ;
     RECT  108.097 52.32 109.253 52.344 ;
     RECT  109.109 0.096 109.361 0.12 ;
     RECT  108.901 57.84 109.397 62.76 ;
     RECT  109.177 64.608 109.477 64.68 ;
     RECT  109.033 30.048 109.609 30.744 ;
     RECT  109.477 64.512 109.619 64.68 ;
     RECT  109.037 1.728 109.645 2.904 ;
     RECT  109.321 46.128 109.645 46.152 ;
     RECT  109.397 59.328 109.681 62.76 ;
     RECT  108.755 32.976 109.825 33.672 ;
     RECT  109.609 30.048 109.861 31.416 ;
     RECT  109.681 59.328 109.933 63.288 ;
     RECT  109.619 64.512 109.933 64.632 ;
     RECT  109.933 59.328 110.003 64.632 ;
     RECT  110.003 59.328 110.099 63.864 ;
     RECT  109.825 32.976 110.113 34.488 ;
     RECT  109.645 1.104 110.149 2.904 ;
     RECT  109.037 3.888 110.149 3.912 ;
     RECT  110.149 1.104 110.221 3.912 ;
     RECT  109.861 29.472 110.293 31.416 ;
     RECT  110.113 32.832 110.293 34.488 ;
     RECT  108.965 35.856 110.293 35.88 ;
     RECT  109.181 37.872 110.293 43.56 ;
     RECT  110.221 0.528 110.408 3.912 ;
     RECT  107.885 8.016 110.408 8.04 ;
     RECT  108.281 10.128 110.408 10.152 ;
     RECT  109.043 15.552 110.408 15.576 ;
     RECT  108.997 20.928 110.408 20.952 ;
     RECT  105.869 25.488 110.408 25.512 ;
     RECT  110.005 28.464 110.408 28.488 ;
     RECT  110.293 29.472 110.408 34.776 ;
     RECT  110.293 35.856 110.408 43.56 ;
     RECT  109.645 46.128 110.408 46.632 ;
     RECT  109.933 52.272 110.408 52.296 ;
     RECT  108.851 55.248 110.408 55.272 ;
     RECT  109.525 56.4 110.408 56.424 ;
     RECT  109.397 57.84 110.408 58.152 ;
     RECT  110.099 59.328 110.408 63.816 ;
     RECT  110.408 0.528 110.483 63.816 ;
     RECT  110.483 0.528 110.704 62.856 ;
     RECT  110.704 0.528 110.765 4.248 ;
     RECT  110.704 10.032 110.801 10.152 ;
     RECT  110.704 57.84 110.801 62.856 ;
     RECT  110.704 55.248 110.819 56.184 ;
     RECT  110.801 57.84 110.819 62.76 ;
     RECT  110.765 0.528 110.821 0.6 ;
     RECT  110.704 42.288 110.867 43.944 ;
     RECT  110.704 26.784 110.873 26.808 ;
     RECT  110.867 43.92 110.873 43.944 ;
     RECT  110.867 42.288 110.909 42.744 ;
     RECT  110.704 20.928 110.915 22.824 ;
     RECT  110.704 37.2 110.945 40.872 ;
     RECT  110.915 20.928 110.981 22.248 ;
     RECT  110.765 1.728 111.059 4.248 ;
     RECT  110.704 50.016 111.059 50.472 ;
     RECT  110.704 52.272 111.059 53.112 ;
     RECT  111.059 1.728 111.089 3.672 ;
     RECT  110.819 59.184 111.125 62.712 ;
     RECT  110.704 29.712 111.161 31.368 ;
     RECT  110.704 46.224 111.233 47.88 ;
     RECT  111.161 29.712 111.413 30.456 ;
     RECT  111.089 1.728 111.443 2.904 ;
     RECT  110.981 20.928 111.443 21.672 ;
     RECT  111.059 52.992 111.443 53.112 ;
     RECT  111.443 53.088 111.449 53.112 ;
     RECT  111.085 63.84 111.493 63.864 ;
     RECT  111.493 63.744 111.539 63.864 ;
     RECT  111.413 29.712 111.593 30.264 ;
     RECT  111.443 1.728 111.635 2.376 ;
     RECT  111.539 63.744 111.731 63.768 ;
     RECT  110.821 0.096 111.769 0.6 ;
     RECT  111.635 1.728 111.769 1.848 ;
     RECT  111.125 59.232 111.809 62.712 ;
     RECT  111.769 0.096 111.827 1.848 ;
     RECT  111.809 60.288 111.953 62.712 ;
     RECT  111.059 50.016 111.989 50.184 ;
     RECT  110.704 15.552 112.237 15.576 ;
     RECT  110.704 34.464 112.237 34.488 ;
     RECT  111.233 46.224 112.237 46.632 ;
     RECT  111.593 29.712 112.261 29.736 ;
     RECT  110.704 36 112.261 36.024 ;
     RECT  111.827 0.096 112.277 0.6 ;
     RECT  112.237 15.552 112.307 16.536 ;
     RECT  112.237 34.368 112.307 34.488 ;
     RECT  112.261 29.088 112.385 29.736 ;
     RECT  112.385 29.088 112.421 29.64 ;
     RECT  112.261 35.904 112.453 36.024 ;
     RECT  112.421 29.616 112.595 29.64 ;
     RECT  110.945 40.656 112.669 40.872 ;
     RECT  112.453 35.04 112.705 36.024 ;
     RECT  110.945 37.2 112.705 39.528 ;
     RECT  111.953 61.536 112.709 62.712 ;
     RECT  112.705 35.04 112.741 39.528 ;
     RECT  112.669 40.656 112.741 41.064 ;
     RECT  112.709 62.112 112.787 62.712 ;
     RECT  112.741 35.04 112.789 41.64 ;
     RECT  112.813 63.84 112.837 63.864 ;
     RECT  112.057 44.928 112.885 44.952 ;
     RECT  112.237 46.08 112.885 46.632 ;
     RECT  112.277 0.576 112.889 0.6 ;
     RECT  112.885 44.928 112.931 46.824 ;
     RECT  112.837 63.84 112.933 64.536 ;
     RECT  112.549 31.92 112.961 31.944 ;
     RECT  112.933 63.84 112.997 64.68 ;
     RECT  110.704 32.976 113.065 33.336 ;
     RECT  110.819 55.248 113.101 55.272 ;
     RECT  112.997 63.84 113.123 64.584 ;
     RECT  113.101 54.912 113.141 55.272 ;
     RECT  110.909 42.72 113.171 42.744 ;
     RECT  112.931 44.928 113.171 45.048 ;
     RECT  111.233 47.856 113.209 47.88 ;
     RECT  111.443 20.928 113.365 20.952 ;
     RECT  113.365 20.064 113.411 20.952 ;
     RECT  112.789 35.04 113.411 41.736 ;
     RECT  111.809 59.232 113.533 59.256 ;
     RECT  111.953 60.288 113.533 60.312 ;
     RECT  113.125 43.776 113.557 43.8 ;
     RECT  113.533 59.232 113.603 60.312 ;
     RECT  113.557 43.344 113.645 43.8 ;
     RECT  112.597 23.904 113.701 23.928 ;
     RECT  110.704 25.488 113.701 25.512 ;
     RECT  113.701 23.904 113.747 24.504 ;
     RECT  113.701 25.488 113.747 26.28 ;
     RECT  113.603 60.288 113.749 60.312 ;
     RECT  113.411 36.432 113.785 41.736 ;
     RECT  113.747 25.824 113.789 26.28 ;
     RECT  113.209 47.856 113.797 48.264 ;
     RECT  113.171 44.928 113.843 44.952 ;
     RECT  111.827 1.728 113.857 1.848 ;
     RECT  113.797 47.712 113.893 48.264 ;
     RECT  110.819 57.84 113.893 57.864 ;
     RECT  113.785 36.432 113.897 42.264 ;
     RECT  113.857 1.728 113.939 2.28 ;
     RECT  113.893 47.712 113.941 48.552 ;
     RECT  113.701 27.552 113.969 27.576 ;
     RECT  112.307 15.552 114.001 15.576 ;
     RECT  113.749 60.288 114.001 60.456 ;
     RECT  112.787 62.16 114.001 62.712 ;
     RECT  114.001 15.072 114.083 15.576 ;
     RECT  113.509 0.096 114.085 0.168 ;
     RECT  113.941 47.712 114.149 48.648 ;
     RECT  113.893 57.84 114.149 58.728 ;
     RECT  113.411 20.064 114.217 20.088 ;
     RECT  114.001 60.288 114.227 62.712 ;
     RECT  114.217 19.92 114.275 20.088 ;
     RECT  113.897 37.008 114.289 42.264 ;
     RECT  113.645 43.776 114.289 43.8 ;
     RECT  113.789 25.824 114.293 26.232 ;
     RECT  114.227 61.488 114.323 62.712 ;
     RECT  114.289 43.776 114.329 43.896 ;
     RECT  114.229 27.936 114.373 27.96 ;
     RECT  113.411 35.04 114.373 35.352 ;
     RECT  114.275 20.064 114.397 20.088 ;
     RECT  114.373 27.936 114.421 28.056 ;
     RECT  114.289 31.344 114.433 31.368 ;
     RECT  114.323 62.112 114.437 62.712 ;
     RECT  114.397 20.064 114.467 20.52 ;
     RECT  114.437 62.16 114.505 62.712 ;
     RECT  113.123 63.84 114.505 63.864 ;
     RECT  114.433 31.344 114.565 31.56 ;
     RECT  113.065 32.736 114.565 33.336 ;
     RECT  114.421 27.936 114.577 28.584 ;
     RECT  114.289 37.008 114.581 42.744 ;
     RECT  114.577 27.936 114.617 28.824 ;
     RECT  114.373 34.8 114.649 35.352 ;
     RECT  114.649 34.8 114.653 35.928 ;
     RECT  114.617 28.56 114.707 28.824 ;
     RECT  114.505 62.16 114.707 63.864 ;
     RECT  114.581 37.008 114.725 41.64 ;
     RECT  114.581 42.72 114.761 42.744 ;
     RECT  114.707 28.56 114.797 28.584 ;
     RECT  114.517 52.464 114.865 52.488 ;
     RECT  114.565 31.344 114.937 33.336 ;
     RECT  114.085 0.096 115.085 0.6 ;
     RECT  114.707 63.84 115.187 63.864 ;
     RECT  114.467 20.064 115.297 20.088 ;
     RECT  114.653 35.856 115.369 35.928 ;
     RECT  114.725 37.008 115.369 41.544 ;
     RECT  114.083 15.552 115.477 15.576 ;
     RECT  114.707 62.16 115.517 62.712 ;
     RECT  113.939 1.728 115.808 1.8 ;
     RECT  110.704 8.016 115.808 8.04 ;
     RECT  110.801 10.032 115.808 10.056 ;
     RECT  115.477 15.312 115.808 15.576 ;
     RECT  115.297 19.104 115.808 20.088 ;
     RECT  113.747 24.48 115.808 24.504 ;
     RECT  114.293 25.824 115.808 25.848 ;
     RECT  114.937 31.344 115.808 33.624 ;
     RECT  114.653 34.8 115.808 34.872 ;
     RECT  115.369 35.856 115.808 41.544 ;
     RECT  114.329 43.872 115.808 43.896 ;
     RECT  112.931 46.176 115.808 46.2 ;
     RECT  114.149 47.712 115.808 47.88 ;
     RECT  111.989 50.016 115.808 50.04 ;
     RECT  114.865 52.464 115.808 52.872 ;
     RECT  113.141 54.912 115.808 54.936 ;
     RECT  114.149 57.84 115.808 58.152 ;
     RECT  114.227 60.288 115.808 60.312 ;
     RECT  115.517 62.16 115.808 62.652 ;
     RECT  115.085 0.576 115.985 0.6 ;
     RECT  115.808 1.728 116.104 62.652 ;
     RECT  116.293 0.096 116.345 0.12 ;
     RECT  116.197 64.656 116.389 64.68 ;
     RECT  116.104 51.792 116.531 51.816 ;
     RECT  116.104 50.016 116.675 50.76 ;
     RECT  116.104 52.848 116.675 53.4 ;
     RECT  116.104 62.16 116.773 62.652 ;
     RECT  116.104 32.304 116.867 35.352 ;
     RECT  116.773 62.16 116.869 62.664 ;
     RECT  116.104 15.312 116.915 15.576 ;
     RECT  116.675 50.736 116.921 50.76 ;
     RECT  116.104 1.728 116.993 2.184 ;
     RECT  116.389 64.608 117.029 64.68 ;
     RECT  116.867 34.32 117.065 35.352 ;
     RECT  117.065 34.32 117.101 34.776 ;
     RECT  116.675 53.376 117.107 53.4 ;
     RECT  116.867 32.304 117.137 33.336 ;
     RECT  117.101 34.512 117.203 34.536 ;
     RECT  116.104 25.824 117.301 25.848 ;
     RECT  117.301 25.824 117.347 26.472 ;
     RECT  116.104 28.512 117.347 28.536 ;
     RECT  116.993 1.728 117.353 1.944 ;
     RECT  117.347 25.92 117.353 26.472 ;
     RECT  116.915 15.312 117.395 15.336 ;
     RECT  117.313 22.752 117.395 22.776 ;
     RECT  117.353 25.92 117.395 26.28 ;
     RECT  116.104 57.84 117.425 58.728 ;
     RECT  117.205 0.528 117.445 0.552 ;
     RECT  117.313 36.288 117.457 36.312 ;
     RECT  116.104 47.712 117.493 47.736 ;
     RECT  117.029 64.656 117.497 64.68 ;
     RECT  116.104 60.288 117.529 60.312 ;
     RECT  117.493 47.712 117.533 47.88 ;
     RECT  117.445 0.528 117.541 0.6 ;
     RECT  117.541 0.096 117.569 0.6 ;
     RECT  117.529 60.288 117.673 61.032 ;
     RECT  116.869 62.16 117.673 62.712 ;
     RECT  116.104 48.96 117.713 48.984 ;
     RECT  117.353 1.728 117.733 1.896 ;
     RECT  116.104 42.72 117.781 44.472 ;
     RECT  116.104 54.912 117.781 54.936 ;
     RECT  116.104 20.064 117.877 20.088 ;
     RECT  116.104 38.016 117.877 41.592 ;
     RECT  117.877 20.064 117.929 20.232 ;
     RECT  117.425 57.84 117.971 57.912 ;
     RECT  117.971 57.84 117.997 57.864 ;
     RECT  117.781 42.72 118.037 45 ;
     RECT  117.997 59.04 118.067 59.064 ;
     RECT  117.997 57.456 118.115 57.864 ;
     RECT  117.925 5.136 118.117 5.16 ;
     RECT  118.069 59.28 118.177 59.304 ;
     RECT  117.673 60.288 118.177 62.712 ;
     RECT  117.877 38.016 118.217 41.64 ;
     RECT  118.249 55.92 118.307 55.944 ;
     RECT  118.037 43.296 118.361 45 ;
     RECT  118.177 59.28 118.397 62.712 ;
     RECT  117.457 36.288 118.429 36.696 ;
     RECT  118.217 38.016 118.429 40.872 ;
     RECT  118.429 36.288 118.465 40.872 ;
     RECT  118.465 35.712 118.499 40.872 ;
     RECT  118.069 46.8 118.573 46.824 ;
     RECT  117.529 23.856 118.597 23.88 ;
     RECT  117.395 26.256 118.597 26.28 ;
     RECT  117.781 54.144 118.609 54.936 ;
     RECT  118.597 23.856 118.643 23.976 ;
     RECT  117.137 32.448 118.645 33.336 ;
     RECT  118.597 25.92 118.649 26.28 ;
     RECT  118.499 35.712 118.649 36.312 ;
     RECT  117.637 52.944 118.649 52.968 ;
     RECT  117.733 1.152 118.681 1.896 ;
     RECT  118.609 28.464 118.691 28.488 ;
     RECT  118.609 54.144 118.691 55.848 ;
     RECT  118.649 26.256 118.717 26.28 ;
     RECT  118.117 5.136 118.721 5.208 ;
     RECT  118.645 31.92 118.793 33.336 ;
     RECT  117.929 20.064 118.835 20.088 ;
     RECT  118.361 43.872 118.837 45 ;
     RECT  118.573 46.176 118.837 46.824 ;
     RECT  118.825 52.992 118.837 53.016 ;
     RECT  118.837 43.872 118.883 46.824 ;
     RECT  118.837 52.992 118.883 53.592 ;
     RECT  118.681 1.104 118.885 1.896 ;
     RECT  118.793 32.064 118.885 33.336 ;
     RECT  118.885 32.064 118.931 34.248 ;
     RECT  118.789 18.576 118.933 18.6 ;
     RECT  118.933 17.856 118.979 18.6 ;
     RECT  118.453 42.144 119.041 42.216 ;
     RECT  118.885 1.104 119.045 2.184 ;
     RECT  118.931 32.448 119.045 34.248 ;
     RECT  118.717 26.256 119.123 26.952 ;
     RECT  118.691 54.72 119.123 55.848 ;
     RECT  118.979 18.576 119.153 18.6 ;
     RECT  119.041 63.84 119.219 63.864 ;
     RECT  118.499 37.584 119.221 40.872 ;
     RECT  119.041 42.144 119.221 42.312 ;
     RECT  118.115 57.84 119.257 57.864 ;
     RECT  119.045 1.632 119.261 2.184 ;
     RECT  119.185 6.192 119.267 6.216 ;
     RECT  117.569 0.096 119.269 0.12 ;
     RECT  119.257 18.768 119.315 18.792 ;
     RECT  118.649 35.712 119.317 36.216 ;
     RECT  118.721 5.184 119.329 5.208 ;
     RECT  119.257 57.84 119.365 58.68 ;
     RECT  118.397 59.664 119.365 62.712 ;
     RECT  119.329 5.184 119.369 6.072 ;
     RECT  119.317 34.752 119.369 36.216 ;
     RECT  119.365 57.84 119.411 62.712 ;
     RECT  119.221 37.584 119.437 42.312 ;
     RECT  118.883 43.872 119.441 45.288 ;
     RECT  119.269 0.096 119.477 0.6 ;
     RECT  119.123 26.784 119.477 26.952 ;
     RECT  119.437 37.584 119.477 42.744 ;
     RECT  119.477 41.616 119.509 42.744 ;
     RECT  119.441 43.872 119.509 44.472 ;
     RECT  119.029 50.16 119.549 50.184 ;
     RECT  119.509 41.616 119.555 44.472 ;
     RECT  119.509 64.512 119.701 64.536 ;
     RECT  119.555 41.616 119.729 42.744 ;
     RECT  119.555 43.92 119.729 44.472 ;
     RECT  119.729 41.616 119.873 42.216 ;
     RECT  118.883 53.568 119.941 53.592 ;
     RECT  119.123 54.72 119.941 55.368 ;
     RECT  117.533 47.856 119.977 47.88 ;
     RECT  119.729 43.968 119.981 43.992 ;
     RECT  118.883 46.8 120.121 46.824 ;
     RECT  119.869 30.72 120.157 30.744 ;
     RECT  119.477 37.584 120.161 40.104 ;
     RECT  120.121 45.744 120.179 46.824 ;
     RECT  119.045 32.448 120.181 33.576 ;
     RECT  119.261 1.632 120.197 1.848 ;
     RECT  120.157 30.48 120.227 30.744 ;
     RECT  119.941 53.568 120.227 55.368 ;
     RECT  119.369 35.712 120.229 36.216 ;
     RECT  120.229 35.712 120.233 36.84 ;
     RECT  118.643 23.952 120.301 23.976 ;
     RECT  120.197 1.632 120.325 1.8 ;
     RECT  120.227 30.72 120.409 30.744 ;
     RECT  119.411 57.84 120.481 58.68 ;
     RECT  120.325 1.152 120.589 1.8 ;
     RECT  120.589 1.104 120.659 1.8 ;
     RECT  119.873 41.616 120.709 42.168 ;
     RECT  120.161 38.4 120.805 40.104 ;
     RECT  120.709 41.28 120.805 42.168 ;
     RECT  120.409 30.72 120.841 30.84 ;
     RECT  120.181 32.448 120.841 33.672 ;
     RECT  119.977 47.856 120.901 48.456 ;
     RECT  119.701 64.512 120.949 64.632 ;
     RECT  120.949 64.368 121.021 64.632 ;
     RECT  119.477 0.096 121.093 0.12 ;
     RECT  120.841 30.72 121.093 33.672 ;
     RECT  121.021 64.32 121.139 64.632 ;
     RECT  120.659 1.728 121.208 1.8 ;
     RECT  120.229 2.88 121.208 2.904 ;
     RECT  119.369 6.048 121.208 6.072 ;
     RECT  116.104 8.016 121.208 8.04 ;
     RECT  116.104 10.032 121.208 10.056 ;
     RECT  116.104 16.56 121.208 16.584 ;
     RECT  118.393 22.8 121.208 22.824 ;
     RECT  120.301 23.952 121.208 24.456 ;
     RECT  119.477 26.832 121.208 26.952 ;
     RECT  120.277 28.272 121.208 28.296 ;
     RECT  121.093 30.72 121.208 34.152 ;
     RECT  120.233 35.856 121.208 36.84 ;
     RECT  120.805 38.4 121.208 42.168 ;
     RECT  120.179 45.744 121.208 45.768 ;
     RECT  120.179 46.8 121.208 46.824 ;
     RECT  120.901 47.856 121.208 48.504 ;
     RECT  120.277 50.736 121.208 50.76 ;
     RECT  120.227 53.568 121.208 54.504 ;
     RECT  120.481 57.168 121.208 58.68 ;
     RECT  119.411 59.664 121.208 62.712 ;
     RECT  121.139 64.368 121.331 64.632 ;
     RECT  121.208 1.728 121.381 62.712 ;
     RECT  121.381 1.728 121.427 62.76 ;
     RECT  121.427 1.728 121.504 62.712 ;
     RECT  121.093 0.096 121.601 0.6 ;
     RECT  121.504 6.048 121.601 6.168 ;
     RECT  121.504 51.648 121.619 52.584 ;
     RECT  121.331 64.464 121.633 64.632 ;
     RECT  121.504 47.856 121.667 49.56 ;
     RECT  121.601 0.528 121.669 0.6 ;
     RECT  121.504 41.616 121.673 42.168 ;
     RECT  121.667 49.2 121.673 49.56 ;
     RECT  121.504 46.752 121.763 46.776 ;
     RECT  121.673 49.248 121.763 49.32 ;
     RECT  121.504 31.824 121.859 34.2 ;
     RECT  121.633 64.464 121.907 64.68 ;
     RECT  121.504 50.544 121.997 50.568 ;
     RECT  121.504 35.328 122.003 37.656 ;
     RECT  121.907 64.56 122.003 64.68 ;
     RECT  122.003 35.856 122.033 37.656 ;
     RECT  121.859 32.208 122.069 34.2 ;
     RECT  121.504 59.04 122.147 62.712 ;
     RECT  121.669 0.528 122.149 0.648 ;
     RECT  121.504 1.728 122.149 2.28 ;
     RECT  122.033 35.856 122.243 35.88 ;
     RECT  122.147 59.616 122.243 62.712 ;
     RECT  122.149 0.528 122.321 2.28 ;
     RECT  121.504 28.272 122.465 28.968 ;
     RECT  122.033 37.152 122.465 37.656 ;
     RECT  121.504 38.688 122.533 40.104 ;
     RECT  122.321 1.728 122.537 2.28 ;
     RECT  122.465 37.152 122.537 37.32 ;
     RECT  122.321 0.528 122.579 0.552 ;
     RECT  122.243 59.712 122.717 62.712 ;
     RECT  121.504 16.56 122.867 16.584 ;
     RECT  122.533 38.496 122.893 40.104 ;
     RECT  122.717 62.544 122.917 62.712 ;
     RECT  122.893 38.496 122.933 40.488 ;
     RECT  122.917 62.544 122.969 62.76 ;
     RECT  122.725 0.096 123.077 0.168 ;
     RECT  121.504 56.208 123.149 56.232 ;
     RECT  123.109 64.464 123.205 64.488 ;
     RECT  123.205 64.464 123.217 64.584 ;
     RECT  123.217 64.416 123.289 64.584 ;
     RECT  123.145 5.04 123.329 5.064 ;
     RECT  123.077 0.144 123.473 0.168 ;
     RECT  122.537 1.728 123.541 2.184 ;
     RECT  121.504 53.568 123.577 53.592 ;
     RECT  123.577 53.568 123.617 54.12 ;
     RECT  123.289 64.416 123.617 64.68 ;
     RECT  123.541 1.68 123.635 2.184 ;
     RECT  123.433 56.16 123.635 56.184 ;
     RECT  123.617 64.656 123.635 64.68 ;
     RECT  122.933 38.64 123.725 40.488 ;
     RECT  123.725 38.688 123.757 40.488 ;
     RECT  121.673 41.616 123.797 41.64 ;
     RECT  122.717 59.712 123.901 61.56 ;
     RECT  122.969 62.544 123.901 62.712 ;
     RECT  122.069 32.208 123.973 34.104 ;
     RECT  121.504 24.432 124.045 24.456 ;
     RECT  124.045 23.904 124.085 24.456 ;
     RECT  123.635 1.728 124.357 2.184 ;
     RECT  122.537 37.296 124.481 37.32 ;
     RECT  121.601 6.144 124.645 6.168 ;
     RECT  124.645 5.616 124.691 6.168 ;
     RECT  124.691 5.616 124.693 6.12 ;
     RECT  123.901 59.712 124.697 62.712 ;
     RECT  124.357 1.728 124.741 2.904 ;
     RECT  124.741 1.728 124.769 2.952 ;
     RECT  124.693 4.896 124.841 6.12 ;
     RECT  124.697 59.712 124.841 62.664 ;
     RECT  123.757 35.712 124.877 35.736 ;
     RECT  123.757 38.688 124.909 40.536 ;
     RECT  124.585 41.712 124.909 41.736 ;
     RECT  124.837 64.368 124.933 64.392 ;
     RECT  124.933 64.368 124.979 64.584 ;
     RECT  122.465 28.944 124.981 28.968 ;
     RECT  124.979 64.464 125.017 64.584 ;
     RECT  124.981 21.072 125.027 21.096 ;
     RECT  123.781 0.576 125.029 0.6 ;
     RECT  121.504 45.744 125.053 45.768 ;
     RECT  125.029 0.576 125.093 0.696 ;
     RECT  124.909 38.688 125.125 41.736 ;
     RECT  125.125 0.144 125.161 0.168 ;
     RECT  124.841 5.808 125.165 6.12 ;
     RECT  124.981 28.944 125.417 29.112 ;
     RECT  125.053 44.784 125.453 45.768 ;
     RECT  124.693 43.296 125.485 43.32 ;
     RECT  125.453 44.784 125.485 44.808 ;
     RECT  123.973 32.208 125.521 34.248 ;
     RECT  125.521 31.248 125.525 34.248 ;
     RECT  121.504 22.8 125.557 22.824 ;
     RECT  124.769 1.728 125.605 1.8 ;
     RECT  125.525 31.248 125.665 34.104 ;
     RECT  121.763 49.248 125.737 49.272 ;
     RECT  124.909 56.352 125.737 56.376 ;
     RECT  121.504 57.84 125.737 57.864 ;
     RECT  125.165 6.096 125.773 6.12 ;
     RECT  125.125 38.688 125.773 42.168 ;
     RECT  125.485 43.296 125.773 44.808 ;
     RECT  125.605 1.152 125.777 1.8 ;
     RECT  125.777 1.728 125.797 1.8 ;
     RECT  121.504 8.016 125.809 8.04 ;
     RECT  121.504 55.152 125.881 55.176 ;
     RECT  125.737 56.352 125.881 57.864 ;
     RECT  124.769 2.88 125.893 2.952 ;
     RECT  121.667 47.856 125.893 47.88 ;
     RECT  125.737 49.248 125.893 50.04 ;
     RECT  125.629 35.856 125.917 36.552 ;
     RECT  125.881 55.152 125.917 57.864 ;
     RECT  125.557 22.608 125.989 22.824 ;
     RECT  124.085 23.904 125.989 23.928 ;
     RECT  125.017 64.464 125.989 64.68 ;
     RECT  125.161 0.048 126.085 0.168 ;
     RECT  123.617 54.096 126.085 54.12 ;
     RECT  124.841 59.712 126.085 62.616 ;
     RECT  125.989 64.416 126.085 64.68 ;
     RECT  125.773 38.688 126.097 44.808 ;
     RECT  125.809 8.016 126.133 8.52 ;
     RECT  121.504 10.032 126.133 10.056 ;
     RECT  125.917 35.856 126.133 37.08 ;
     RECT  126.097 38.16 126.133 44.808 ;
     RECT  125.893 2.88 126.169 3.336 ;
     RECT  126.085 64.32 126.227 64.68 ;
     RECT  126.085 59.28 126.277 62.616 ;
     RECT  126.227 64.464 126.323 64.68 ;
     RECT  126.133 8.016 126.325 10.056 ;
     RECT  125.773 6.096 126.421 6.888 ;
     RECT  125.917 12.528 126.421 12.552 ;
     RECT  125.893 47.856 126.421 50.04 ;
     RECT  126.277 59.28 126.421 62.664 ;
     RECT  126.085 0.048 126.425 0.6 ;
     RECT  126.133 35.856 126.457 44.808 ;
     RECT  126.421 59.232 126.457 62.664 ;
     RECT  125.797 1.728 126.469 1.848 ;
     RECT  126.169 2.88 126.469 3.432 ;
     RECT  126.421 12.528 126.469 13.128 ;
     RECT  126.457 59.232 126.565 62.76 ;
     RECT  126.469 1.728 126.608 3.432 ;
     RECT  125.305 4.512 126.608 4.536 ;
     RECT  126.421 5.616 126.608 6.888 ;
     RECT  126.325 8.016 126.608 10.152 ;
     RECT  126.469 12.528 126.608 13.608 ;
     RECT  122.821 15.264 126.608 15.288 ;
     RECT  126.469 19.968 126.608 19.992 ;
     RECT  125.989 22.608 126.608 23.928 ;
     RECT  125.417 28.944 126.608 28.968 ;
     RECT  125.665 30.816 126.608 34.104 ;
     RECT  126.457 35.328 126.608 44.808 ;
     RECT  125.845 46.128 126.608 46.152 ;
     RECT  126.421 47.328 126.608 50.04 ;
     RECT  126.085 53.376 126.608 54.12 ;
     RECT  125.917 55.152 126.608 58.152 ;
     RECT  126.565 59.232 126.608 62.856 ;
     RECT  126.608 1.728 126.611 62.856 ;
     RECT  126.611 1.728 126.904 62.808 ;
     RECT  126.904 10.848 127.043 12.552 ;
     RECT  126.904 18.768 127.043 18.792 ;
     RECT  126.904 22.704 127.043 23.208 ;
     RECT  126.904 45.696 127.043 49.08 ;
     RECT  126.904 55.488 127.043 56.088 ;
     RECT  126.904 8.496 127.073 9.72 ;
     RECT  127.043 55.488 127.073 55.752 ;
     RECT  126.904 59.184 127.109 62.808 ;
     RECT  126.904 26.208 127.145 26.232 ;
     RECT  127.073 9.072 127.217 9.72 ;
     RECT  127.073 55.488 127.217 55.512 ;
     RECT  126.904 31.68 127.235 44.712 ;
     RECT  126.323 64.464 127.237 64.632 ;
     RECT  127.043 10.848 127.289 11.88 ;
     RECT  127.235 38.304 127.289 44.712 ;
     RECT  126.904 5.712 127.325 6.888 ;
     RECT  127.043 22.8 127.325 23.208 ;
     RECT  127.289 38.688 127.325 44.712 ;
     RECT  127.237 64.416 127.333 64.632 ;
     RECT  126.904 53.04 127.397 54.504 ;
     RECT  127.333 64.416 127.429 64.68 ;
     RECT  127.109 59.184 127.433 62.616 ;
     RECT  127.325 38.784 127.469 44.712 ;
     RECT  127.397 53.04 127.505 53.064 ;
     RECT  126.904 51.264 127.613 51.864 ;
     RECT  126.904 1.728 127.681 3.816 ;
     RECT  127.235 31.68 127.721 37.032 ;
     RECT  127.433 59.184 127.757 62.568 ;
     RECT  127.325 5.712 127.829 6.648 ;
     RECT  127.043 45.696 127.829 48.024 ;
     RECT  127.397 54.048 127.829 54.504 ;
     RECT  127.043 49.056 127.907 49.08 ;
     RECT  127.829 45.84 127.937 48.024 ;
     RECT  127.757 59.232 127.937 62.568 ;
     RECT  127.937 45.84 127.973 47.736 ;
     RECT  127.681 1.68 128.005 3.816 ;
     RECT  127.325 23.184 128.005 23.208 ;
     RECT  126.904 57.84 128.081 58.152 ;
     RECT  128.077 30.24 128.147 30.264 ;
     RECT  127.937 59.28 128.153 62.568 ;
     RECT  127.829 5.712 128.221 5.736 ;
     RECT  128.005 23.184 128.293 23.352 ;
     RECT  127.429 64.368 128.293 64.68 ;
     RECT  128.101 16.944 128.297 16.968 ;
     RECT  128.293 23.184 128.341 23.736 ;
     RECT  128.341 22.224 128.369 23.736 ;
     RECT  128.245 30.816 128.369 30.84 ;
     RECT  128.293 64.32 128.389 64.68 ;
     RECT  127.721 32.448 128.405 37.032 ;
     RECT  128.405 32.976 128.441 37.032 ;
     RECT  128.441 32.976 128.477 35.64 ;
     RECT  128.005 1.68 128.531 3.96 ;
     RECT  127.973 46.224 128.531 47.736 ;
     RECT  126.425 0.048 128.545 0.552 ;
     RECT  128.531 1.68 128.545 3.048 ;
     RECT  128.369 22.224 128.549 23.448 ;
     RECT  128.221 4.944 128.693 5.736 ;
     RECT  127.469 38.784 128.725 43.32 ;
     RECT  128.531 46.224 128.729 47.352 ;
     RECT  128.441 37.008 128.869 37.032 ;
     RECT  128.725 38.016 128.869 43.32 ;
     RECT  128.549 22.224 128.909 22.776 ;
     RECT  126.904 28.944 128.909 28.968 ;
     RECT  128.869 37.008 128.915 43.32 ;
     RECT  128.915 38.016 128.965 43.32 ;
     RECT  127.289 11.664 128.977 11.88 ;
     RECT  127.829 54.048 128.977 54.072 ;
     RECT  128.477 32.976 128.981 35.256 ;
     RECT  128.977 54.048 129.017 54.168 ;
     RECT  128.965 38.016 129.053 43.368 ;
     RECT  128.909 22.752 129.059 22.776 ;
     RECT  128.153 59.52 129.109 62.568 ;
     RECT  128.693 4.944 129.125 5.208 ;
     RECT  128.981 32.976 129.125 34.344 ;
     RECT  127.469 44.448 129.157 44.712 ;
     RECT  129.109 59.52 129.203 62.616 ;
     RECT  128.389 64.224 129.229 64.68 ;
     RECT  129.157 44.448 129.301 44.904 ;
     RECT  128.915 37.008 129.305 37.032 ;
     RECT  128.977 11.664 129.377 12.552 ;
     RECT  129.053 38.208 129.377 43.368 ;
     RECT  129.229 63.84 129.395 64.68 ;
     RECT  126.904 15.264 129.397 15.288 ;
     RECT  129.301 44.448 129.397 44.952 ;
     RECT  129.397 14.4 129.443 15.288 ;
     RECT  129.373 46.176 129.443 46.2 ;
     RECT  127.217 9.696 129.445 9.72 ;
     RECT  129.017 54.144 129.481 54.168 ;
     RECT  128.485 55.296 129.481 55.32 ;
     RECT  129.481 54.144 129.517 55.32 ;
     RECT  129.517 54.144 129.521 55.56 ;
     RECT  129.397 43.92 129.557 44.952 ;
     RECT  129.395 63.84 129.557 64.632 ;
     RECT  129.589 58.656 129.635 58.68 ;
     RECT  128.545 0.048 129.683 3.048 ;
     RECT  129.203 59.712 129.697 62.616 ;
     RECT  129.557 63.84 129.697 63.912 ;
     RECT  129.661 35.808 129.731 36.168 ;
     RECT  128.329 57.024 129.769 57.048 ;
     RECT  129.769 57.024 129.809 58.008 ;
     RECT  129.377 38.208 129.827 42.744 ;
     RECT  129.125 5.088 129.829 5.208 ;
     RECT  129.829 5.088 129.877 5.736 ;
     RECT  127.613 51.84 129.877 51.864 ;
     RECT  129.827 38.208 129.917 41.64 ;
     RECT  129.731 35.808 129.923 35.832 ;
     RECT  129.443 14.4 129.925 14.424 ;
     RECT  128.401 50.544 129.925 50.568 ;
     RECT  129.877 51.84 129.925 52.776 ;
     RECT  129.925 50.16 129.971 50.568 ;
     RECT  129.925 51.6 129.971 52.776 ;
     RECT  129.877 5.088 130.061 5.88 ;
     RECT  129.925 13.536 130.097 14.424 ;
     RECT  129.971 50.16 130.165 50.184 ;
     RECT  129.697 59.712 130.165 63.912 ;
     RECT  129.917 38.736 130.205 41.64 ;
     RECT  130.165 49.488 130.205 50.184 ;
     RECT  130.165 59.616 130.259 63.912 ;
     RECT  129.971 52.752 130.261 52.776 ;
     RECT  129.265 7.968 130.309 7.992 ;
     RECT  130.237 35.616 130.309 35.64 ;
     RECT  130.261 52.752 130.313 53.544 ;
     RECT  130.309 35.52 130.349 35.64 ;
     RECT  129.377 12.528 130.355 12.552 ;
     RECT  130.061 5.088 130.453 5.208 ;
     RECT  129.445 9.696 130.457 9.912 ;
     RECT  130.349 35.52 130.493 35.544 ;
     RECT  129.521 54.624 130.493 55.56 ;
     RECT  130.453 5.04 130.499 5.208 ;
     RECT  129.557 43.92 130.525 43.944 ;
     RECT  130.205 38.736 130.529 40.488 ;
     RECT  129.125 32.976 130.565 33.528 ;
     RECT  130.493 54.624 130.565 54.648 ;
     RECT  130.525 56.112 130.595 56.136 ;
     RECT  130.565 33.075 130.601 33.528 ;
     RECT  129.683 0.048 130.669 0.696 ;
     RECT  129.683 1.728 130.669 3.048 ;
     RECT  130.309 7.968 130.673 8.328 ;
     RECT  130.549 64.32 130.693 64.536 ;
     RECT  129.809 57.312 130.741 58.008 ;
     RECT  130.499 5.184 130.781 5.208 ;
     RECT  130.529 38.736 130.781 40.2 ;
     RECT  130.453 6.288 130.817 6.312 ;
     RECT  130.741 57.312 130.835 58.152 ;
     RECT  130.525 43.824 130.921 43.944 ;
     RECT  129.557 44.928 130.921 44.952 ;
     RECT  129.971 51.6 130.961 51.624 ;
     RECT  130.259 59.616 131.027 63.288 ;
     RECT  131.027 59.712 131.269 63.288 ;
     RECT  130.693 64.32 131.269 64.584 ;
     RECT  128.341 24.864 131.425 24.888 ;
     RECT  131.425 24.864 131.461 25.176 ;
     RECT  131.389 8.928 131.497 8.952 ;
     RECT  130.205 41.616 131.497 41.64 ;
     RECT  131.269 59.712 131.507 64.584 ;
     RECT  131.461 24.096 131.605 25.176 ;
     RECT  130.921 43.824 131.677 44.952 ;
     RECT  131.065 17.856 131.701 17.88 ;
     RECT  131.507 64.368 131.701 64.584 ;
     RECT  129.827 42.72 131.749 42.744 ;
     RECT  131.677 43.824 131.749 45.192 ;
     RECT  131.605 6.192 131.893 6.216 ;
     RECT  130.669 0.048 132.008 3.048 ;
     RECT  131.893 5.76 132.008 6.216 ;
     RECT  131.605 7.44 132.008 7.464 ;
     RECT  131.497 8.928 132.008 9.048 ;
     RECT  130.669 10.656 132.008 10.68 ;
     RECT  130.097 14.4 132.008 14.424 ;
     RECT  131.701 17.856 132.008 18.264 ;
     RECT  131.605 24.096 132.008 25.368 ;
     RECT  128.977 28.992 132.008 29.016 ;
     RECT  131.497 30.816 132.008 30.84 ;
     RECT  130.601 33.075 132.008 33.336 ;
     RECT  130.781 39.072 132.008 40.2 ;
     RECT  131.497 41.28 132.008 41.64 ;
     RECT  131.749 42.72 132.008 45.192 ;
     RECT  130.205 49.488 132.008 49.512 ;
     RECT  131.029 51.312 132.008 51.336 ;
     RECT  130.313 52.752 132.008 52.776 ;
     RECT  130.835 57.312 132.008 57.336 ;
     RECT  131.507 59.712 132.008 63.288 ;
     RECT  132.008 0.048 132.275 63.288 ;
     RECT  132.275 0.048 132.304 62.616 ;
     RECT  132.304 18.72 132.419 18.744 ;
     RECT  132.304 28.992 132.419 29.112 ;
     RECT  131.701 64.368 132.421 64.632 ;
     RECT  132.421 64.368 132.473 64.68 ;
     RECT  132.304 20.496 132.515 20.52 ;
     RECT  132.304 24.096 132.515 24.12 ;
     RECT  132.473 64.368 132.755 64.536 ;
     RECT  132.755 64.368 132.805 64.392 ;
     RECT  132.304 0.048 132.869 2.808 ;
     RECT  132.805 64.128 132.869 64.392 ;
     RECT  132.869 64.128 132.899 64.248 ;
     RECT  132.869 0.048 133.043 2.28 ;
     RECT  132.304 44.448 133.121 45.192 ;
     RECT  133.121 44.448 133.333 45.048 ;
     RECT  132.304 59.712 133.427 62.616 ;
     RECT  132.899 64.128 133.513 64.152 ;
     RECT  133.427 61.776 133.523 62.616 ;
     RECT  133.523 62.16 133.549 62.616 ;
     RECT  132.304 39.072 133.553 40.056 ;
     RECT  132.304 49.488 133.553 49.512 ;
     RECT  133.549 54.672 133.619 54.696 ;
     RECT  133.427 59.712 133.667 60.648 ;
     RECT  133.043 0.048 133.715 2.232 ;
     RECT  133.549 62.16 133.765 62.664 ;
     RECT  133.333 44.352 133.837 45.048 ;
     RECT  133.513 63.84 133.861 64.152 ;
     RECT  133.837 43.824 133.907 45.048 ;
     RECT  133.553 39.072 133.949 39.864 ;
     RECT  133.861 63.84 133.985 64.68 ;
     RECT  133.715 0.048 134.003 2.088 ;
     RECT  134.003 1.632 134.057 2.088 ;
     RECT  133.907 44.352 134.057 45.048 ;
     RECT  133.985 63.84 134.099 63.864 ;
     RECT  133.667 59.712 134.195 60.168 ;
     RECT  134.057 44.448 134.201 44.472 ;
     RECT  134.057 1.632 134.237 2.04 ;
     RECT  134.237 1.632 134.483 1.752 ;
     RECT  133.765 62.16 134.483 62.712 ;
     RECT  132.304 33.075 134.485 33.336 ;
     RECT  134.485 33.072 134.525 33.336 ;
     RECT  134.003 0.048 134.579 0.6 ;
     RECT  133.949 39.072 134.597 39.336 ;
     RECT  134.485 26.64 134.677 26.664 ;
     RECT  134.677 26.208 134.725 26.664 ;
     RECT  134.449 31.008 134.725 31.032 ;
     RECT  134.725 27.936 134.777 27.96 ;
     RECT  134.725 30.192 134.777 31.032 ;
     RECT  134.725 26.112 135.097 26.664 ;
     RECT  134.579 0.048 135.137 0.072 ;
     RECT  134.483 1.728 135.205 1.752 ;
     RECT  134.483 62.544 135.493 62.712 ;
     RECT  135.205 1.728 135.589 1.8 ;
     RECT  134.195 59.712 135.589 59.736 ;
     RECT  135.493 61.488 135.589 62.712 ;
     RECT  135.565 25.008 135.635 25.032 ;
     RECT  132.419 28.992 135.637 29.016 ;
     RECT  135.589 59.712 135.637 62.712 ;
     RECT  135.637 28.224 135.673 29.016 ;
     RECT  134.777 30.384 135.673 31.032 ;
     RECT  135.637 59.232 135.685 62.712 ;
     RECT  135.673 28.224 135.731 29.064 ;
     RECT  135.673 54.672 135.731 54.696 ;
     RECT  135.685 58.704 135.749 62.76 ;
     RECT  135.097 26.112 135.817 26.76 ;
     RECT  135.817 26.016 135.829 26.76 ;
     RECT  135.589 1.728 135.877 1.848 ;
     RECT  135.829 25.056 135.961 26.76 ;
     RECT  135.817 8.496 135.997 8.52 ;
     RECT  135.961 25.056 135.997 26.856 ;
     RECT  135.997 8.448 136.067 8.52 ;
     RECT  135.997 25.056 136.069 27.24 ;
     RECT  135.731 28.224 136.069 28.824 ;
     RECT  135.673 30.384 136.069 31.8 ;
     RECT  135.685 0.096 136.109 0.12 ;
     RECT  135.877 1.728 136.141 1.896 ;
     RECT  135.397 2.88 136.141 2.904 ;
     RECT  136.069 25.056 136.145 28.824 ;
     RECT  134.525 33.315 136.213 33.333 ;
     RECT  136.069 30.288 136.249 31.8 ;
     RECT  136.213 3.936 136.259 3.96 ;
     RECT  136.213 33.315 136.289 34.248 ;
     RECT  135.749 58.704 136.309 62.712 ;
     RECT  136.141 1.728 136.325 2.904 ;
     RECT  136.325 1.728 136.357 2.28 ;
     RECT  136.033 41.808 136.357 41.832 ;
     RECT  136.357 41.04 136.393 41.832 ;
     RECT  136.357 1.68 136.453 2.28 ;
     RECT  136.249 30.24 136.573 31.8 ;
     RECT  136.393 40.368 136.753 41.832 ;
     RECT  135.421 43.248 136.753 43.272 ;
     RECT  134.597 39.072 136.789 39.096 ;
     RECT  136.753 40.368 136.789 42.024 ;
     RECT  136.309 58.512 136.789 62.712 ;
     RECT  135.889 54.432 136.825 54.456 ;
     RECT  136.453 1.152 136.837 2.28 ;
     RECT  136.717 13.68 136.837 13.704 ;
     RECT  136.789 64.608 136.837 64.632 ;
     RECT  135.457 18.192 136.861 18.216 ;
     RECT  136.825 54.432 136.969 55.272 ;
     RECT  136.861 21.648 137.005 21.672 ;
     RECT  136.837 64.464 137.005 64.632 ;
     RECT  136.067 8.496 137.041 8.52 ;
     RECT  136.753 43.248 137.077 44.376 ;
     RECT  136.069 47.328 137.077 47.352 ;
     RECT  137.005 64.464 137.077 64.68 ;
     RECT  136.145 25.104 137.113 28.824 ;
     RECT  137.077 64.416 137.149 64.68 ;
     RECT  137.041 8.496 137.185 9.192 ;
     RECT  136.837 13.68 137.221 14.04 ;
     RECT  136.789 39.072 137.221 42.024 ;
     RECT  136.969 53.568 137.221 55.272 ;
     RECT  136.789 58.512 137.257 62.76 ;
     RECT  137.149 64.368 137.257 64.68 ;
     RECT  137.257 64.272 137.315 64.68 ;
     RECT  137.221 39.072 137.401 42.216 ;
     RECT  137.077 43.248 137.401 44.76 ;
     RECT  136.837 0.576 137.408 2.28 ;
     RECT  137.401 5.04 137.408 5.064 ;
     RECT  137.185 8.496 137.408 9.672 ;
     RECT  136.285 12.528 137.408 12.552 ;
     RECT  137.221 13.68 137.408 14.856 ;
     RECT  137.149 16.272 137.408 16.296 ;
     RECT  136.861 18.192 137.408 18.792 ;
     RECT  137.005 21.12 137.408 21.672 ;
     RECT  135.565 22.8 137.408 22.824 ;
     RECT  137.113 24.48 137.408 28.824 ;
     RECT  136.573 30.048 137.408 31.8 ;
     RECT  136.289 33.315 137.408 33.333 ;
     RECT  135.997 35.424 137.408 35.448 ;
     RECT  136.885 37.632 137.408 37.656 ;
     RECT  137.401 39.072 137.408 44.76 ;
     RECT  137.077 46.464 137.408 47.352 ;
     RECT  135.457 48.384 137.408 48.408 ;
     RECT  137.221 51.888 137.408 55.272 ;
     RECT  136.789 56.64 137.408 56.664 ;
     RECT  137.257 58.128 137.408 62.76 ;
     RECT  137.408 0.576 137.509 62.76 ;
     RECT  137.509 0.384 137.704 62.808 ;
     RECT  137.704 0.384 137.749 3.96 ;
     RECT  137.749 0.288 137.797 3.96 ;
     RECT  137.704 5.04 137.843 5.064 ;
     RECT  137.797 0.192 137.869 3.96 ;
     RECT  137.704 32.784 137.891 44.76 ;
     RECT  137.704 54.432 137.891 55.992 ;
     RECT  137.704 7.2 137.939 7.416 ;
     RECT  137.869 0.096 137.987 3.96 ;
     RECT  137.704 19.92 137.987 31.8 ;
     RECT  137.987 19.92 138.035 27.384 ;
     RECT  137.987 0.096 138.053 3.768 ;
     RECT  137.891 32.784 138.089 42.168 ;
     RECT  137.704 58.512 138.089 62.808 ;
     RECT  138.053 0.096 138.121 1.848 ;
     RECT  137.987 28.56 138.131 31.8 ;
     RECT  138.089 36 138.197 42.168 ;
     RECT  137.891 43.296 138.275 44.76 ;
     RECT  138.197 40.896 138.323 42.168 ;
     RECT  138.323 40.896 138.341 42.072 ;
     RECT  137.315 64.32 138.373 64.68 ;
     RECT  138.089 58.704 138.419 62.808 ;
     RECT  137.891 54.432 138.467 55.896 ;
     RECT  138.089 32.784 138.485 35.016 ;
     RECT  137.704 10.752 138.521 16.536 ;
     RECT  138.197 36 138.521 39.912 ;
     RECT  138.341 40.992 138.521 42.072 ;
     RECT  138.275 43.824 138.521 44.76 ;
     RECT  138.131 28.56 138.563 30.168 ;
     RECT  137.704 47.328 138.563 49.608 ;
     RECT  138.521 43.824 138.593 43.848 ;
     RECT  138.563 49.152 138.593 49.608 ;
     RECT  138.521 10.752 138.611 16.296 ;
     RECT  138.521 36.672 138.665 39.912 ;
     RECT  138.593 49.584 138.697 49.608 ;
     RECT  137.704 50.688 138.697 50.712 ;
     RECT  138.665 36.672 138.707 37.656 ;
     RECT  137.704 52.56 138.707 52.584 ;
     RECT  138.707 37.056 138.737 37.656 ;
     RECT  138.697 49.584 138.755 50.712 ;
     RECT  138.419 59.04 138.769 62.808 ;
     RECT  138.373 63.84 138.769 64.68 ;
     RECT  138.485 32.784 138.773 34.824 ;
     RECT  138.053 2.832 138.803 3.768 ;
     RECT  138.563 47.328 138.805 47.88 ;
     RECT  137.704 8.496 138.809 8.52 ;
     RECT  138.521 41.04 138.809 42.072 ;
     RECT  138.131 31.296 138.845 31.8 ;
     RECT  138.467 55.872 138.845 55.896 ;
     RECT  138.755 50.688 138.851 50.712 ;
     RECT  138.467 54.432 138.851 54.6 ;
     RECT  138.769 59.04 138.899 64.68 ;
     RECT  138.563 28.56 138.947 29.928 ;
     RECT  137.704 18.24 138.985 18.936 ;
     RECT  138.805 47.28 138.995 47.88 ;
     RECT  138.121 0.048 139.025 1.848 ;
     RECT  138.611 12.528 139.025 16.296 ;
     RECT  138.985 17.52 139.043 18.936 ;
     RECT  138.803 2.88 139.061 3.768 ;
     RECT  138.035 21.504 139.061 27.384 ;
     RECT  139.061 21.504 139.097 23.112 ;
     RECT  138.899 59.04 139.097 63.336 ;
     RECT  139.061 24.096 139.141 27.384 ;
     RECT  138.035 19.92 139.165 20.088 ;
     RECT  138.947 28.56 139.169 29.88 ;
     RECT  139.097 59.04 139.187 63.288 ;
     RECT  139.165 19.92 139.235 20.184 ;
     RECT  138.611 10.752 139.237 11.064 ;
     RECT  139.237 10.032 139.241 11.064 ;
     RECT  139.169 28.8 139.241 29.88 ;
     RECT  139.043 18.048 139.309 18.936 ;
     RECT  139.235 19.92 139.309 20.088 ;
     RECT  139.309 18.048 139.313 20.088 ;
     RECT  138.773 32.784 139.313 34.248 ;
     RECT  137.939 7.2 139.333 7.224 ;
     RECT  139.241 10.032 139.379 10.152 ;
     RECT  138.809 41.04 139.379 41.064 ;
     RECT  138.899 64.416 139.379 64.68 ;
     RECT  139.061 2.928 139.385 3.768 ;
     RECT  139.025 12.528 139.385 16.008 ;
     RECT  139.097 21.504 139.385 22.92 ;
     RECT  139.333 8.688 139.421 8.712 ;
     RECT  139.141 24.096 139.421 27.432 ;
     RECT  138.755 49.584 139.427 49.608 ;
     RECT  138.995 47.856 139.457 47.88 ;
     RECT  139.379 10.128 139.475 10.152 ;
     RECT  139.187 59.04 139.489 62.616 ;
     RECT  138.845 31.296 139.493 31.368 ;
     RECT  139.385 12.528 139.523 15.672 ;
     RECT  139.385 22.176 139.523 22.92 ;
     RECT  139.421 24.768 139.525 27.432 ;
     RECT  139.523 12.528 139.529 14.28 ;
     RECT  139.529 12.528 139.565 12.888 ;
     RECT  139.429 21.12 139.565 21.144 ;
     RECT  139.525 54.144 139.571 54.168 ;
     RECT  139.565 12.528 139.597 12.552 ;
     RECT  139.241 28.8 139.601 29.688 ;
     RECT  139.489 58.704 139.601 62.616 ;
     RECT  138.665 39.072 139.637 39.912 ;
     RECT  139.313 18.048 139.667 19.992 ;
     RECT  139.525 24.768 139.667 27.48 ;
     RECT  139.637 39.264 139.667 39.912 ;
     RECT  139.667 19.968 139.673 19.992 ;
     RECT  139.597 11.856 139.715 12.552 ;
     RECT  139.667 18.048 139.745 18.168 ;
     RECT  138.737 37.056 139.745 37.224 ;
     RECT  139.523 22.224 139.763 22.92 ;
     RECT  139.025 0.048 139.781 1.752 ;
     RECT  139.529 14.112 139.781 14.136 ;
     RECT  139.493 31.344 139.781 31.368 ;
     RECT  139.333 6.864 139.813 7.224 ;
     RECT  139.667 39.408 139.813 39.912 ;
     RECT  139.385 2.928 139.853 2.952 ;
     RECT  139.523 15.648 139.853 15.672 ;
     RECT  139.813 6.864 139.859 7.992 ;
     RECT  139.813 39.408 139.859 40.2 ;
     RECT  139.601 59.04 139.907 62.616 ;
     RECT  139.715 12 139.925 12.552 ;
     RECT  139.763 22.224 139.925 22.824 ;
     RECT  139.885 3.936 139.955 3.96 ;
     RECT  139.859 39.408 139.961 39.912 ;
     RECT  139.993 56.4 140.029 56.424 ;
     RECT  140.029 56.4 140.051 56.664 ;
     RECT  139.859 6.864 140.069 7.464 ;
     RECT  139.961 39.888 140.069 39.912 ;
     RECT  140.051 56.64 140.099 56.664 ;
     RECT  139.667 24.768 140.141 27.384 ;
     RECT  139.907 59.28 140.141 62.616 ;
     RECT  140.053 17.952 140.177 17.976 ;
     RECT  140.141 59.28 140.177 60.552 ;
     RECT  140.177 59.376 140.213 60.552 ;
     RECT  140.213 59.76 140.243 60.552 ;
     RECT  139.601 28.8 140.249 29.112 ;
     RECT  140.141 24.768 140.285 26.856 ;
     RECT  140.245 6.672 140.291 6.696 ;
     RECT  140.245 37.44 140.291 37.464 ;
     RECT  139.909 52.272 140.317 52.296 ;
     RECT  139.925 12.528 140.357 12.552 ;
     RECT  140.317 51.84 140.387 52.296 ;
     RECT  140.245 9.12 140.393 9.144 ;
     RECT  140.141 61.728 140.533 62.616 ;
     RECT  139.781 0.096 140.627 1.752 ;
     RECT  140.533 61.728 140.627 62.664 ;
     RECT  139.379 64.416 140.641 64.632 ;
     RECT  139.925 22.224 140.645 22.248 ;
     RECT  140.285 26.832 140.681 26.856 ;
     RECT  140.243 59.808 140.723 60.552 ;
     RECT  140.641 63.84 140.869 64.632 ;
     RECT  140.627 0.096 140.915 1.128 ;
     RECT  140.869 63.84 140.965 64.68 ;
     RECT  140.627 61.728 141.011 62.616 ;
     RECT  140.915 0.096 141.107 0.12 ;
     RECT  140.965 63.744 141.107 64.68 ;
     RECT  140.915 1.104 141.203 1.128 ;
     RECT  140.723 60.528 141.205 60.552 ;
     RECT  141.107 64.416 141.347 64.68 ;
     RECT  141.347 64.512 141.401 64.68 ;
     RECT  141.011 62.592 141.491 62.616 ;
     RECT  141.205 60.528 141.587 61.56 ;
     RECT  141.587 60.528 141.617 60.552 ;
     RECT  141.587 61.536 141.779 61.56 ;
     RECT  141.721 62.64 141.875 62.664 ;
     RECT  141.401 64.656 141.875 64.68 ;
     RECT  140.285 24.768 142.808 25.8 ;
     RECT  140.249 28.8 142.808 28.824 ;
     RECT  139.313 32.784 142.808 33.333 ;
     RECT  138.809 42.048 142.808 42.072 ;
     RECT  140.387 52.272 142.808 52.296 ;
     RECT  141.875 62.64 142.808 62.652 ;
     RECT  142.808 2.148 142.912 62.652 ;
     RECT  142.912 2.418 143.104 62.382 ;
     RECT  143.104 24.768 148.208 25.8 ;
     RECT  143.104 28.8 148.208 28.824 ;
     RECT  143.104 32.784 148.208 33.333 ;
     RECT  143.104 42.048 148.208 42.072 ;
     RECT  143.104 52.272 148.208 52.296 ;
     RECT  148.208 2.148 148.312 62.652 ;
     RECT  148.312 2.418 148.504 62.382 ;
     RECT  148.504 24.768 153.608 25.8 ;
     RECT  148.504 28.8 153.608 28.824 ;
     RECT  148.504 32.784 153.608 33.333 ;
     RECT  148.504 42.048 153.608 42.072 ;
     RECT  148.504 52.272 153.608 52.296 ;
     RECT  153.608 2.148 153.712 62.652 ;
     RECT  153.712 2.418 153.904 62.382 ;
     RECT  153.904 24.768 159.008 25.8 ;
     RECT  153.904 28.8 159.008 28.824 ;
     RECT  153.904 32.784 159.008 33.333 ;
     RECT  153.904 42.048 159.008 42.072 ;
     RECT  153.904 52.272 159.008 52.296 ;
     RECT  159.008 2.148 159.112 62.652 ;
     RECT  159.112 2.418 159.304 62.382 ;
     RECT  159.304 24.768 164.408 25.8 ;
     RECT  159.304 28.8 164.408 28.824 ;
     RECT  159.304 32.784 164.408 33.333 ;
     RECT  159.304 42.048 164.408 42.072 ;
     RECT  159.304 52.272 164.408 52.296 ;
     RECT  164.408 2.148 164.512 62.652 ;
     RECT  164.512 2.418 164.704 62.382 ;
     RECT  164.704 32.784 168.757 33.333 ;
     RECT  168.757 32.784 168.797 33.336 ;
     RECT  164.704 24.768 169.808 25.8 ;
     RECT  164.704 28.8 169.808 28.824 ;
     RECT  168.797 32.784 169.808 32.808 ;
     RECT  164.704 42.048 169.808 42.072 ;
     RECT  164.704 52.272 169.808 52.296 ;
     RECT  169.808 2.148 169.912 62.652 ;
     RECT  169.912 2.418 170.104 62.382 ;
     RECT  170.104 32.784 170.345 33.336 ;
     RECT  170.104 24.768 175.208 25.8 ;
     RECT  170.104 28.8 175.208 28.824 ;
     RECT  170.345 32.784 175.208 33.333 ;
     RECT  170.104 42.048 175.208 42.072 ;
     RECT  170.104 52.272 175.208 52.296 ;
     RECT  175.208 2.148 175.312 62.652 ;
     RECT  175.312 2.418 175.504 62.382 ;
     RECT  175.504 24.768 177.781 25.8 ;
     RECT  175.504 42.048 180.277 42.072 ;
     RECT  177.781 24.768 180.608 26.28 ;
     RECT  175.504 28.8 180.608 28.824 ;
     RECT  175.504 32.784 180.608 33.333 ;
     RECT  180.277 41.904 180.608 42.072 ;
     RECT  175.504 52.272 180.608 52.296 ;
     RECT  180.608 2.148 180.712 62.652 ;
     RECT  180.712 2.418 180.904 62.382 ;
     RECT  180.904 24.768 186.008 26.28 ;
     RECT  180.904 28.8 186.008 28.824 ;
     RECT  180.904 32.784 186.008 33.333 ;
     RECT  180.904 41.904 186.008 42.072 ;
     RECT  180.904 52.272 186.008 52.296 ;
     RECT  186.008 2.148 186.112 62.652 ;
     RECT  186.112 2.418 186.304 62.382 ;
     RECT  186.304 24.768 191.408 26.28 ;
     RECT  186.304 28.8 191.408 28.824 ;
     RECT  186.304 32.784 191.408 33.333 ;
     RECT  186.304 41.904 191.408 42.072 ;
     RECT  186.304 52.272 191.408 52.296 ;
     RECT  191.408 2.148 191.512 62.652 ;
     RECT  191.512 2.418 191.704 62.382 ;
     RECT  191.704 24.768 196.808 26.28 ;
     RECT  191.704 28.8 196.808 28.824 ;
     RECT  191.704 32.784 196.808 33.333 ;
     RECT  191.704 41.904 196.808 42.072 ;
     RECT  191.704 52.272 196.808 52.296 ;
     RECT  196.808 2.148 196.912 62.652 ;
     RECT  196.912 2.418 197.104 62.382 ;
     RECT  197.104 24.768 202.208 26.28 ;
     RECT  197.104 28.8 202.208 28.824 ;
     RECT  197.104 32.784 202.208 33.333 ;
     RECT  197.104 41.904 202.208 42.072 ;
     RECT  197.104 52.272 202.208 52.296 ;
     RECT  202.208 2.148 202.312 62.652 ;
     RECT  202.312 2.418 202.504 62.382 ;
     RECT  202.504 32.784 206.341 33.333 ;
     RECT  202.504 28.8 206.521 28.824 ;
     RECT  206.341 32.784 206.531 33.576 ;
     RECT  206.521 27.84 206.579 28.824 ;
     RECT  206.531 32.784 206.579 33.24 ;
     RECT  206.485 35.904 206.633 35.928 ;
     RECT  202.504 24.768 207.608 26.28 ;
     RECT  206.579 28.8 207.608 28.824 ;
     RECT  206.579 32.784 207.608 32.808 ;
     RECT  206.773 36.432 207.608 36.456 ;
     RECT  206.773 40.56 207.608 40.584 ;
     RECT  202.504 41.904 207.608 42.072 ;
     RECT  202.504 52.272 207.608 52.296 ;
     RECT  207.608 2.148 207.712 62.652 ;
     RECT  207.712 2.418 207.904 62.382 ;
     RECT  207.904 27.36 208.115 27.384 ;
     RECT  207.904 32.784 212.821 32.808 ;
     RECT  207.904 24.768 213.008 26.28 ;
     RECT  207.904 28.8 213.008 28.824 ;
     RECT  212.785 29.904 213.008 29.928 ;
     RECT  212.821 31.2 213.008 32.808 ;
     RECT  207.904 40.56 213.008 40.584 ;
     RECT  207.904 41.904 213.008 41.928 ;
     RECT  207.904 52.272 213.008 52.296 ;
     RECT  213.008 2.148 213.112 62.652 ;
     RECT  213.112 2.418 213.304 62.382 ;
     RECT  213.304 28.176 213.581 32.808 ;
     RECT  213.581 28.176 213.905 31.176 ;
     RECT  213.905 30.192 214.115 31.176 ;
     RECT  213.905 28.176 214.309 29.064 ;
     RECT  213.304 39.744 214.373 40.584 ;
     RECT  213.304 24.768 214.693 26.28 ;
     RECT  214.309 27.888 214.693 29.064 ;
     RECT  213.581 32.16 214.801 32.808 ;
     RECT  214.693 24.768 214.949 29.064 ;
     RECT  214.373 39.888 215.021 40.584 ;
     RECT  214.949 24.768 215.273 27.336 ;
     RECT  214.949 28.416 215.413 29.064 ;
     RECT  214.115 30.192 215.449 30.792 ;
     RECT  215.413 28.416 215.741 29.112 ;
     RECT  214.801 31.92 215.845 32.808 ;
     RECT  215.741 29.04 215.917 29.112 ;
     RECT  215.449 30.096 215.917 30.792 ;
     RECT  215.021 40.464 215.989 40.584 ;
     RECT  215.989 39.648 216.061 40.584 ;
     RECT  215.273 27.312 216.065 27.336 ;
     RECT  215.917 29.04 216.065 30.792 ;
     RECT  216.065 29.04 216.245 30.408 ;
     RECT  215.845 31.872 216.349 32.808 ;
     RECT  216.061 39.408 216.601 40.584 ;
     RECT  216.245 29.424 216.749 30.408 ;
     RECT  216.349 31.488 217.073 32.808 ;
     RECT  215.273 24.768 217.217 26.28 ;
     RECT  216.601 39.408 217.253 40.632 ;
     RECT  216.673 35.712 217.285 35.736 ;
     RECT  215.017 37.44 217.321 37.464 ;
     RECT  217.321 37.44 217.573 37.608 ;
     RECT  217.285 34.896 217.717 35.736 ;
     RECT  217.573 37.44 217.717 37.752 ;
     RECT  217.253 39.408 217.717 39.528 ;
     RECT  217.717 34.896 217.765 36.024 ;
     RECT  217.717 37.152 217.765 39.528 ;
     RECT  217.753 33.888 218.149 33.912 ;
     RECT  217.765 34.896 218.149 39.528 ;
     RECT  217.217 25.728 218.293 26.28 ;
     RECT  217.073 31.92 218.293 32.808 ;
     RECT  218.149 33.888 218.293 39.528 ;
     RECT  218.293 25.728 218.408 27.336 ;
     RECT  216.749 29.76 218.408 30.408 ;
     RECT  218.293 31.92 218.408 39.528 ;
     RECT  217.253 40.56 218.408 40.632 ;
     RECT  213.304 41.904 218.408 41.928 ;
     RECT  213.304 52.272 218.408 52.296 ;
     RECT  218.408 2.148 218.512 62.652 ;
     RECT  218.512 2.418 218.704 62.382 ;
     RECT  218.704 32.832 218.909 39.192 ;
     RECT  218.909 34.224 218.981 39.192 ;
     RECT  218.981 38.688 219.557 39.192 ;
     RECT  218.704 25.056 219.769 28.584 ;
     RECT  218.704 29.664 219.769 30.408 ;
     RECT  219.557 39.168 219.779 39.192 ;
     RECT  218.909 32.832 219.781 33.144 ;
     RECT  218.704 40.32 219.881 40.872 ;
     RECT  219.769 25.056 220.069 30.408 ;
     RECT  219.781 32.544 220.069 33.144 ;
     RECT  218.981 34.224 220.069 37.56 ;
     RECT  220.069 25.056 220.307 31.176 ;
     RECT  220.069 32.544 220.637 37.56 ;
     RECT  220.637 32.544 220.691 33.624 ;
     RECT  220.637 34.656 220.691 37.56 ;
     RECT  220.691 32.544 221.221 33.528 ;
     RECT  220.691 34.992 221.393 37.56 ;
     RECT  220.307 25.056 221.533 30.888 ;
     RECT  221.393 35.136 221.537 37.56 ;
     RECT  221.533 24.768 221.605 30.888 ;
     RECT  221.221 32.256 221.641 33.528 ;
     RECT  221.641 32.16 221.701 33.528 ;
     RECT  221.537 35.184 221.717 35.64 ;
     RECT  221.605 24.768 221.857 31.176 ;
     RECT  221.701 32.16 221.857 33.624 ;
     RECT  221.857 24.768 221.939 33.624 ;
     RECT  221.537 36.816 222.073 37.56 ;
     RECT  221.939 29.472 222.109 33.624 ;
     RECT  222.073 36.816 222.145 38.232 ;
     RECT  222.109 29.472 222.179 33.96 ;
     RECT  222.145 36.816 222.179 38.28 ;
     RECT  221.717 35.232 222.221 35.64 ;
     RECT  222.179 38.208 222.253 38.28 ;
     RECT  222.221 35.232 222.293 35.496 ;
     RECT  222.293 35.28 222.329 35.496 ;
     RECT  222.179 36.816 222.545 37.08 ;
     RECT  221.939 24.768 223.045 28.488 ;
     RECT  222.179 29.472 223.045 33.624 ;
     RECT  219.881 40.56 223.189 40.872 ;
     RECT  223.189 40.128 223.261 40.872 ;
     RECT  222.545 36.96 223.477 37.08 ;
     RECT  222.253 38.208 223.477 38.76 ;
     RECT  223.045 24.768 223.525 33.624 ;
     RECT  223.525 24.672 223.549 33.624 ;
     RECT  222.329 35.28 223.585 35.448 ;
     RECT  223.261 40.032 223.585 40.872 ;
     RECT  218.704 41.904 223.585 41.928 ;
     RECT  223.585 35.28 223.669 35.496 ;
     RECT  223.549 24.48 223.808 33.624 ;
     RECT  223.669 35.28 223.808 35.928 ;
     RECT  223.477 36.96 223.808 38.76 ;
     RECT  223.585 40.032 223.808 41.928 ;
     RECT  218.704 52.272 223.808 52.296 ;
     RECT  223.808 2.148 223.912 62.652 ;
     RECT  223.912 2.418 224.104 62.382 ;
     RECT  224.104 23.664 224.771 27.72 ;
     RECT  224.771 27.36 224.777 27.72 ;
     RECT  224.777 27.648 224.849 27.72 ;
     RECT  224.104 28.704 225.155 32.424 ;
     RECT  224.771 23.664 225.157 25.896 ;
     RECT  224.104 33.552 225.157 35.928 ;
     RECT  224.104 36.912 225.157 36.936 ;
     RECT  225.157 33.552 225.203 36.936 ;
     RECT  225.155 29.328 225.245 32.424 ;
     RECT  225.203 33.552 225.245 36.408 ;
     RECT  225.245 29.328 225.299 32.232 ;
     RECT  225.299 29.328 225.317 31.944 ;
     RECT  224.104 37.968 225.461 41.928 ;
     RECT  225.245 33.552 225.493 35.832 ;
     RECT  225.317 29.328 225.539 30.792 ;
     RECT  225.157 23.328 225.713 25.896 ;
     RECT  225.493 33.216 225.713 35.832 ;
     RECT  225.713 33.552 225.749 35.832 ;
     RECT  225.713 23.52 225.779 25.896 ;
     RECT  224.104 52.272 225.997 52.296 ;
     RECT  225.539 30.768 226.217 30.792 ;
     RECT  225.997 51.504 226.285 52.296 ;
     RECT  226.285 51.408 226.307 52.296 ;
     RECT  226.285 20.976 226.309 21 ;
     RECT  226.285 22.464 226.309 22.488 ;
     RECT  225.539 29.328 226.309 29.688 ;
     RECT  226.309 20.976 226.355 22.488 ;
     RECT  225.779 24.912 226.397 25.896 ;
     RECT  225.749 33.552 226.469 35.496 ;
     RECT  224.849 27.696 226.541 27.72 ;
     RECT  225.461 37.968 226.757 41.256 ;
     RECT  226.309 29.04 226.789 29.688 ;
     RECT  226.789 29.04 226.829 30.6 ;
     RECT  226.829 29.328 226.835 30.6 ;
     RECT  225.317 31.92 226.837 31.944 ;
     RECT  226.835 30.576 226.865 30.6 ;
     RECT  226.835 29.328 226.883 29.592 ;
     RECT  226.469 33.552 226.883 34.968 ;
     RECT  225.779 23.52 227.041 23.688 ;
     RECT  226.397 24.912 227.041 25.848 ;
     RECT  227.005 36.816 227.113 36.84 ;
     RECT  227.041 23.52 227.189 25.848 ;
     RECT  226.355 20.976 227.221 22.056 ;
     RECT  227.221 20.928 227.315 22.056 ;
     RECT  226.609 43.536 227.329 43.56 ;
     RECT  226.883 33.6 227.473 34.968 ;
     RECT  227.113 36.432 227.473 36.84 ;
     RECT  227.189 23.52 227.509 25.8 ;
     RECT  227.329 42.576 227.509 43.56 ;
     RECT  227.509 42.576 227.555 43.896 ;
     RECT  227.555 42.576 227.585 43.848 ;
     RECT  226.837 31.872 227.765 31.944 ;
     RECT  227.765 31.92 227.797 31.944 ;
     RECT  227.473 33.6 227.797 36.84 ;
     RECT  226.757 37.968 227.797 37.992 ;
     RECT  227.797 31.92 227.837 32.184 ;
     RECT  227.509 23.136 227.869 25.8 ;
     RECT  227.269 19.584 227.977 19.608 ;
     RECT  227.317 45.6 227.989 45.624 ;
     RECT  227.797 33.6 228.013 37.992 ;
     RECT  226.757 39.6 228.013 41.256 ;
     RECT  227.585 43.536 228.035 43.848 ;
     RECT  227.869 22.752 228.053 25.8 ;
     RECT  228.013 39.6 228.053 42.024 ;
     RECT  228.035 43.536 228.053 43.56 ;
     RECT  227.315 20.928 228.161 21.624 ;
     RECT  227.977 19.248 228.229 19.608 ;
     RECT  227.837 32.016 228.409 32.184 ;
     RECT  226.717 27.36 228.481 27.384 ;
     RECT  226.883 29.568 228.481 29.592 ;
     RECT  227.989 45.6 228.517 45.768 ;
     RECT  228.481 27.168 228.553 27.384 ;
     RECT  228.161 20.928 228.841 20.952 ;
     RECT  228.229 18.768 228.877 19.608 ;
     RECT  228.841 20.592 228.877 20.952 ;
     RECT  228.013 33.6 228.949 38.424 ;
     RECT  228.053 39.6 228.949 40.824 ;
     RECT  228.481 29.376 228.985 29.592 ;
     RECT  228.985 29.376 229.021 30.072 ;
     RECT  228.409 32.016 229.093 32.232 ;
     RECT  228.877 18.768 229.208 20.952 ;
     RECT  228.949 21.984 229.208 22.008 ;
     RECT  228.053 23.136 229.208 25.8 ;
     RECT  228.553 27.168 229.208 28.008 ;
     RECT  229.021 29.376 229.208 30.36 ;
     RECT  229.093 32.016 229.208 32.52 ;
     RECT  228.949 33.6 229.208 40.824 ;
     RECT  228.053 42 229.208 42.024 ;
     RECT  228.517 45.216 229.208 45.768 ;
     RECT  227.509 46.848 229.208 46.872 ;
     RECT  226.307 51.408 229.208 51.672 ;
     RECT  229.208 2.148 229.312 62.652 ;
     RECT  229.312 2.418 229.504 62.382 ;
     RECT  229.504 46.752 229.601 46.872 ;
     RECT  229.504 32.016 229.817 38.232 ;
     RECT  229.817 32.016 229.955 38.04 ;
     RECT  229.955 32.016 229.961 34.152 ;
     RECT  229.504 51.408 230.003 51.672 ;
     RECT  229.504 39.744 230.147 42.168 ;
     RECT  229.504 20.592 230.321 25.8 ;
     RECT  229.504 28.368 230.393 28.392 ;
     RECT  230.321 20.592 230.677 20.856 ;
     RECT  230.147 40.032 230.717 42.168 ;
     RECT  229.955 35.472 230.897 38.04 ;
     RECT  230.321 21.984 231.001 25.8 ;
     RECT  229.504 27.168 231.001 27.192 ;
     RECT  229.504 30.048 231.013 30.36 ;
     RECT  231.013 28.464 231.037 30.36 ;
     RECT  231.001 21.984 231.059 27.192 ;
     RECT  230.897 36 231.059 38.04 ;
     RECT  231.037 28.464 231.077 30.456 ;
     RECT  229.961 32.496 231.077 34.152 ;
     RECT  229.504 18.432 231.253 19.416 ;
     RECT  230.677 20.544 231.253 20.856 ;
     RECT  231.077 29.904 231.253 30.456 ;
     RECT  231.077 32.496 231.253 33.672 ;
     RECT  231.253 18.432 231.469 20.856 ;
     RECT  231.469 18.24 231.725 20.856 ;
     RECT  231.725 18.24 231.731 19.416 ;
     RECT  231.077 28.464 231.757 28.872 ;
     RECT  230.717 40.032 231.757 41.064 ;
     RECT  230.717 42.144 231.757 42.168 ;
     RECT  231.901 35.136 232.013 35.16 ;
     RECT  229.504 45.216 232.081 45.768 ;
     RECT  229.601 46.752 232.081 46.776 ;
     RECT  231.757 40.032 232.153 42.168 ;
     RECT  231.059 26.784 232.189 27.192 ;
     RECT  231.253 29.904 232.213 33.672 ;
     RECT  232.153 39.792 232.225 42.168 ;
     RECT  232.213 29.904 232.259 33.72 ;
     RECT  231.757 28.224 232.261 28.872 ;
     RECT  232.259 29.904 232.261 32.568 ;
     RECT  232.261 28.224 232.307 32.568 ;
     RECT  231.059 36.24 232.309 38.04 ;
     RECT  232.225 39.216 232.373 42.168 ;
     RECT  232.309 36.24 232.441 38.136 ;
     RECT  231.725 20.544 232.549 20.856 ;
     RECT  231.059 21.984 232.549 25.752 ;
     RECT  232.189 26.784 232.549 27.24 ;
     RECT  232.441 36.048 232.549 38.136 ;
     RECT  232.549 36.048 232.585 38.232 ;
     RECT  232.549 21.984 232.765 27.24 ;
     RECT  232.307 28.224 232.765 30.984 ;
     RECT  232.373 40.032 232.841 42.168 ;
     RECT  232.513 43.776 232.945 43.8 ;
     RECT  232.841 40.56 233.077 42.168 ;
     RECT  232.259 33.6 233.173 33.72 ;
     RECT  232.765 21.984 233.237 30.984 ;
     RECT  233.173 33.6 233.237 34.344 ;
     RECT  232.585 36.048 233.309 39.048 ;
     RECT  232.945 43.248 233.309 43.8 ;
     RECT  233.237 27.888 233.417 30.984 ;
     RECT  233.309 43.248 233.633 43.272 ;
     RECT  233.417 27.984 233.773 30.984 ;
     RECT  233.077 40.56 233.845 42.216 ;
     RECT  232.081 45.216 233.845 46.776 ;
     RECT  231.731 18.24 233.941 19.032 ;
     RECT  232.549 20.544 233.941 20.952 ;
     RECT  233.941 18.24 233.953 20.952 ;
     RECT  233.845 40.56 233.953 42.648 ;
     RECT  233.953 40.416 234.025 42.648 ;
     RECT  232.307 32.544 234.169 32.568 ;
     RECT  233.237 33.6 234.169 33.912 ;
     RECT  233.309 37.584 234.169 39.048 ;
     RECT  234.169 37.584 234.205 39.096 ;
     RECT  234.025 40.368 234.205 42.648 ;
     RECT  234.169 32.544 234.241 33.912 ;
     RECT  233.309 36.048 234.241 36.12 ;
     RECT  233.773 27.984 234.421 31.512 ;
     RECT  234.241 32.496 234.421 33.912 ;
     RECT  233.953 17.616 234.608 20.952 ;
     RECT  233.237 21.984 234.608 26.808 ;
     RECT  234.421 27.984 234.608 33.912 ;
     RECT  234.241 35.232 234.608 36.12 ;
     RECT  234.205 37.584 234.608 42.648 ;
     RECT  233.845 44.736 234.608 46.776 ;
     RECT  230.003 51.648 234.608 51.672 ;
     RECT  234.608 2.148 234.712 62.652 ;
     RECT  234.712 2.418 234.904 62.382 ;
     RECT  234.904 17.376 235.091 34.104 ;
     RECT  235.091 17.376 235.109 31.752 ;
     RECT  235.091 32.784 235.361 34.104 ;
     RECT  234.904 44.832 235.433 46.776 ;
     RECT  234.904 35.232 235.969 36.744 ;
     RECT  234.904 37.824 235.969 43.512 ;
     RECT  235.361 32.928 236.101 34.104 ;
     RECT  235.969 35.232 236.101 43.512 ;
     RECT  235.109 17.376 236.437 17.928 ;
     RECT  235.109 19.008 236.437 31.752 ;
     RECT  236.101 32.928 236.689 43.512 ;
     RECT  235.433 44.928 236.689 46.776 ;
     RECT  236.689 32.928 236.771 46.776 ;
     RECT  236.437 17.376 236.977 31.752 ;
     RECT  236.771 44.928 236.977 46.776 ;
     RECT  236.977 17.376 237.229 31.8 ;
     RECT  236.771 32.928 237.229 43.752 ;
     RECT  237.229 17.376 237.665 43.752 ;
     RECT  236.977 44.928 237.697 47.064 ;
     RECT  237.665 17.376 237.737 29.64 ;
     RECT  237.665 30.912 237.737 43.752 ;
     RECT  237.697 44.928 237.809 47.256 ;
     RECT  237.809 44.928 238.021 47.16 ;
     RECT  238.501 48.672 238.705 48.696 ;
     RECT  237.737 31.392 238.709 43.752 ;
     RECT  238.709 31.392 238.745 32.328 ;
     RECT  238.745 32.016 238.781 32.328 ;
     RECT  238.709 33.648 238.813 43.752 ;
     RECT  238.021 44.88 238.813 47.16 ;
     RECT  237.737 18.672 238.889 29.64 ;
     RECT  237.737 17.376 238.993 17.64 ;
     RECT  238.889 28.176 238.997 29.64 ;
     RECT  238.993 17.184 239.065 17.64 ;
     RECT  238.889 18.672 239.065 27.192 ;
     RECT  238.705 48.672 239.245 48.936 ;
     RECT  238.813 33.648 239.413 47.16 ;
     RECT  239.245 48.672 239.413 48.984 ;
     RECT  238.781 32.016 239.821 32.04 ;
     RECT  239.413 33.648 239.821 48.984 ;
     RECT  239.389 30.624 239.845 30.648 ;
     RECT  239.821 32.016 239.845 48.984 ;
     RECT  239.065 17.184 240.008 27.192 ;
     RECT  238.997 28.224 240.008 29.64 ;
     RECT  239.845 30.624 240.008 48.984 ;
     RECT  234.904 51.648 240.008 51.672 ;
     RECT  240.008 2.148 240.112 62.652 ;
     RECT  240.112 2.418 240.304 62.382 ;
     RECT  240.304 32.16 240.473 49.8 ;
     RECT  240.304 17.376 241.405 31.176 ;
     RECT  240.473 32.16 241.405 47.352 ;
     RECT  241.405 17.376 241.477 47.352 ;
     RECT  241.477 17.376 241.873 47.4 ;
     RECT  240.473 48.384 241.873 49.8 ;
     RECT  241.873 17.376 242.243 49.8 ;
     RECT  242.243 32.352 242.737 49.8 ;
     RECT  242.737 32.352 242.777 50.088 ;
     RECT  242.777 48.384 242.849 50.088 ;
     RECT  242.849 50.064 242.993 50.088 ;
     RECT  242.777 32.352 243.493 47.4 ;
     RECT  242.849 48.384 243.889 48.936 ;
     RECT  242.243 17.376 244.181 31.176 ;
     RECT  244.181 23.28 244.453 31.176 ;
     RECT  243.493 32.256 244.453 47.4 ;
     RECT  244.453 23.28 244.753 47.4 ;
     RECT  243.889 48.384 244.753 49.896 ;
     RECT  244.753 23.28 245.113 49.896 ;
     RECT  244.181 17.376 245.149 22.056 ;
     RECT  245.113 23.28 245.149 50.184 ;
     RECT  245.149 17.376 245.408 50.184 ;
     RECT  240.304 51.648 245.408 51.672 ;
     RECT  245.408 2.148 245.512 62.652 ;
     RECT  245.512 2.418 245.704 62.382 ;
     RECT  245.704 17.424 246.757 49.512 ;
     RECT  246.757 16.56 246.845 49.512 ;
     RECT  246.845 16.56 247.061 19.848 ;
     RECT  247.061 16.56 247.133 17.64 ;
     RECT  246.845 21.168 247.565 49.512 ;
     RECT  245.704 50.592 248.249 50.616 ;
     RECT  247.133 17.616 248.281 17.64 ;
     RECT  247.061 18.72 248.281 19.848 ;
     RECT  247.565 21.216 248.425 49.512 ;
     RECT  248.425 21.216 248.677 50.568 ;
     RECT  248.677 21.12 248.771 50.568 ;
     RECT  248.771 21.12 248.789 49.368 ;
     RECT  248.281 17.616 248.965 19.848 ;
     RECT  248.789 21.12 248.965 49.32 ;
     RECT  248.965 17.616 250.477 49.32 ;
     RECT  247.133 16.56 250.549 16.584 ;
     RECT  250.477 17.568 250.549 49.32 ;
     RECT  250.549 16.56 250.808 49.32 ;
     RECT  248.771 50.544 250.808 50.568 ;
     RECT  245.704 51.648 250.808 51.672 ;
     RECT  250.808 2.148 250.912 62.652 ;
     RECT  250.912 2.418 251.104 62.382 ;
     RECT  251.104 16.56 251.273 47.688 ;
     RECT  251.104 48.72 251.741 50.568 ;
     RECT  251.741 48.72 251.777 49.8 ;
     RECT  251.273 18.72 251.813 47.688 ;
     RECT  251.104 51.648 251.843 51.672 ;
     RECT  251.273 16.56 252.749 17.64 ;
     RECT  252.749 17.616 252.781 17.64 ;
     RECT  251.813 18.72 252.781 43.128 ;
     RECT  251.813 44.112 252.853 47.688 ;
     RECT  251.777 48.72 252.853 49.272 ;
     RECT  252.853 44.112 252.899 49.272 ;
     RECT  252.899 44.112 252.929 49.224 ;
     RECT  252.929 44.112 253.091 47.448 ;
     RECT  252.929 48.432 253.091 49.224 ;
     RECT  252.781 17.616 253.249 43.128 ;
     RECT  253.091 44.112 253.249 47.352 ;
     RECT  253.249 17.616 253.757 47.352 ;
     RECT  253.757 17.616 253.811 47.16 ;
     RECT  253.811 18.624 254.333 47.16 ;
     RECT  254.333 44.16 255.049 47.16 ;
     RECT  252.749 16.56 255.157 16.584 ;
     RECT  253.811 17.616 255.157 17.64 ;
     RECT  254.333 18.624 255.197 43.128 ;
     RECT  255.197 23.808 255.301 43.128 ;
     RECT  255.049 44.16 255.301 47.4 ;
     RECT  255.157 16.56 255.589 17.64 ;
     RECT  255.197 18.624 255.589 22.776 ;
     RECT  255.589 16.56 256.208 22.776 ;
     RECT  255.301 23.808 256.208 47.4 ;
     RECT  253.091 48.432 256.208 48.984 ;
     RECT  256.208 2.148 256.312 62.652 ;
     RECT  256.312 2.418 256.504 62.382 ;
     RECT  256.504 22.848 256.529 46.536 ;
     RECT  256.504 48.96 256.673 48.984 ;
     RECT  256.529 23.904 256.925 46.536 ;
     RECT  256.925 42.96 257.105 46.536 ;
     RECT  256.925 23.904 257.213 41.976 ;
     RECT  256.504 17.088 257.249 21.864 ;
     RECT  257.249 17.088 257.605 19.848 ;
     RECT  257.213 23.904 257.681 41.784 ;
     RECT  256.504 47.856 257.681 47.88 ;
     RECT  257.105 42.96 257.861 46.296 ;
     RECT  256.529 22.848 257.893 22.872 ;
     RECT  257.681 23.904 257.893 31.32 ;
     RECT  257.249 21.12 258.037 21.864 ;
     RECT  257.893 22.848 258.037 31.32 ;
     RECT  257.681 32.544 258.077 41.784 ;
     RECT  258.037 21.12 258.185 31.32 ;
     RECT  257.605 15.408 258.217 15.432 ;
     RECT  257.605 16.512 258.217 19.848 ;
     RECT  258.077 32.544 258.257 41.688 ;
     RECT  257.861 43.248 258.257 46.296 ;
     RECT  258.257 40.08 258.329 41.688 ;
     RECT  258.257 32.544 258.365 39.096 ;
     RECT  258.365 32.544 258.371 34.536 ;
     RECT  258.185 21.12 258.473 26.088 ;
     RECT  258.257 44.928 258.473 46.296 ;
     RECT  258.473 44.928 258.545 45 ;
     RECT  258.371 32.544 258.581 34.152 ;
     RECT  258.545 44.976 258.689 45 ;
     RECT  258.217 15.408 258.725 19.848 ;
     RECT  258.185 27.12 258.757 31.32 ;
     RECT  258.581 32.544 258.757 34.104 ;
     RECT  258.757 27.12 258.803 34.104 ;
     RECT  258.365 35.664 258.833 39.096 ;
     RECT  258.329 41.376 258.869 41.688 ;
     RECT  258.257 43.248 258.869 43.272 ;
     RECT  258.869 41.376 258.977 41.4 ;
     RECT  258.833 35.76 259.121 39.096 ;
     RECT  258.329 40.08 259.139 40.152 ;
     RECT  258.803 33.552 259.157 34.104 ;
     RECT  259.139 40.128 259.235 40.152 ;
     RECT  258.725 15.552 259.261 19.848 ;
     RECT  259.261 15.552 259.331 20.088 ;
     RECT  258.473 21.408 259.373 26.088 ;
     RECT  259.121 36.624 259.475 39.096 ;
     RECT  259.331 19.056 259.513 20.088 ;
     RECT  259.373 21.408 259.513 21.864 ;
     RECT  259.513 19.056 260.057 21.864 ;
     RECT  259.475 36.624 260.165 37.992 ;
     RECT  259.373 23.088 260.305 26.088 ;
     RECT  258.803 27.12 260.305 31.896 ;
     RECT  260.057 21.408 260.389 21.864 ;
     RECT  260.305 23.088 260.389 31.896 ;
     RECT  260.389 21.408 260.435 31.896 ;
     RECT  259.157 34.08 260.881 34.104 ;
     RECT  260.881 34.08 260.965 34.776 ;
     RECT  260.965 33.6 260.989 34.776 ;
     RECT  259.331 15.552 261.025 17.928 ;
     RECT  260.057 19.056 261.025 20.424 ;
     RECT  260.989 33.264 261.397 34.776 ;
     RECT  260.165 36.624 261.397 36.648 ;
     RECT  261.025 15.552 261.445 20.424 ;
     RECT  261.445 15.456 261.608 20.424 ;
     RECT  260.435 21.504 261.608 31.896 ;
     RECT  261.397 33.264 261.608 36.648 ;
     RECT  260.165 37.968 261.608 37.992 ;
     RECT  259.475 39.072 261.608 39.096 ;
     RECT  258.473 46.272 261.608 46.296 ;
     RECT  261.608 2.148 261.712 62.652 ;
     RECT  261.712 2.418 261.904 62.382 ;
     RECT  261.904 15.456 262.115 36.936 ;
     RECT  262.115 28.272 262.217 36.936 ;
     RECT  262.217 28.272 262.433 34.632 ;
     RECT  262.433 29.664 262.931 34.632 ;
     RECT  261.904 37.968 263.221 37.992 ;
     RECT  261.904 39.072 263.221 39.096 ;
     RECT  262.931 32.4 263.257 34.632 ;
     RECT  263.221 37.968 263.261 39.096 ;
     RECT  263.261 38.592 263.267 39.096 ;
     RECT  261.904 46.272 263.267 46.296 ;
     RECT  262.115 15.456 263.293 27.144 ;
     RECT  263.257 32.4 263.315 34.776 ;
     RECT  263.293 15.36 263.329 27.144 ;
     RECT  262.433 28.272 263.329 28.44 ;
     RECT  263.329 15.36 263.411 28.44 ;
     RECT  263.315 32.4 263.441 34.728 ;
     RECT  262.931 29.664 264.193 30.984 ;
     RECT  264.193 29.664 264.409 31.368 ;
     RECT  263.441 32.4 264.409 34.392 ;
     RECT  264.409 29.664 264.661 34.392 ;
     RECT  262.217 36.192 264.661 36.936 ;
     RECT  264.661 36 264.917 36.936 ;
     RECT  264.661 29.664 264.949 34.488 ;
     RECT  264.917 36.48 264.989 36.936 ;
     RECT  264.949 29.616 265.057 34.488 ;
     RECT  263.411 15.456 265.237 28.44 ;
     RECT  265.237 15.312 265.489 28.44 ;
     RECT  265.057 29.616 265.489 34.92 ;
     RECT  265.489 15.312 265.573 34.92 ;
     RECT  265.057 37.728 265.673 37.752 ;
     RECT  265.573 15.312 265.849 35.352 ;
     RECT  263.267 39.072 266.033 39.096 ;
     RECT  265.765 13.824 266.149 13.848 ;
     RECT  265.849 15.168 266.149 35.352 ;
     RECT  266.149 13.824 266.293 35.352 ;
     RECT  266.293 13.824 266.749 35.448 ;
     RECT  264.989 36.48 266.749 36.504 ;
     RECT  266.749 13.824 266.821 36.504 ;
     RECT  266.821 13.824 266.869 36.6 ;
     RECT  266.869 13.824 267.008 37.08 ;
     RECT  267.008 2.148 267.112 62.652 ;
     RECT  267.112 2.418 267.304 62.382 ;
     RECT  267.304 13.824 267.365 34.392 ;
     RECT  267.365 26.016 267.509 34.296 ;
     RECT  267.304 37.056 267.509 37.08 ;
     RECT  267.365 13.824 267.587 24.936 ;
     RECT  267.509 26.112 267.617 34.296 ;
     RECT  267.587 13.824 267.653 14.568 ;
     RECT  267.587 15.648 267.653 24.936 ;
     RECT  267.617 26.832 267.683 34.296 ;
     RECT  267.653 15.648 267.689 24.216 ;
     RECT  267.689 15.648 267.725 23.976 ;
     RECT  267.683 26.832 267.725 33.672 ;
     RECT  267.304 35.424 267.725 35.448 ;
     RECT  267.653 14.112 267.779 14.568 ;
     RECT  267.779 14.112 267.827 14.136 ;
     RECT  267.725 28.8 267.827 33.672 ;
     RECT  267.725 16.08 267.875 23.976 ;
     RECT  267.827 29.232 267.875 33.672 ;
     RECT  267.875 16.08 267.923 23.064 ;
     RECT  267.875 29.232 267.923 33.096 ;
     RECT  267.923 16.08 268.481 22.92 ;
     RECT  268.481 16.08 269.881 22.824 ;
     RECT  269.881 16.08 269.964 22.92 ;
     RECT  267.923 29.232 269.964 32.136 ;
    LAYER M5 ;
     RECT  89.808 0.016 141.192 0.131 ;
     RECT  89.904 0.131 141.192 0.611 ;
     RECT  90 0.611 114.984 1.091 ;
     RECT  90 1.091 95.688 1.139 ;
     RECT  116.016 0.611 141.192 1.139 ;
     RECT  90 1.139 95.592 1.763 ;
     RECT  116.016 1.139 140.616 1.763 ;
     RECT  90.096 1.763 94.512 1.811 ;
     RECT  96.72 1.091 114.984 1.811 ;
     RECT  116.016 1.763 130.536 1.811 ;
     RECT  135.216 1.763 139.08 1.811 ;
     RECT  90.384 1.811 94.512 1.859 ;
     RECT  96.72 1.811 113.928 1.859 ;
     RECT  116.016 1.811 119.112 1.859 ;
     RECT  120.144 1.811 124.776 1.859 ;
     RECT  125.808 1.811 130.536 1.859 ;
     RECT  101.424 1.859 103.176 1.907 ;
     RECT  116.016 1.859 118.92 1.955 ;
     RECT  120.24 1.859 124.776 1.955 ;
     RECT  116.016 1.955 116.808 2.137 ;
     RECT  2.4 2.137 2.52 2.151 ;
     RECT  7.8 2.137 7.92 2.151 ;
     RECT  13.2 2.137 13.32 2.151 ;
     RECT  18.6 2.137 18.72 2.151 ;
     RECT  24 2.137 24.12 2.151 ;
     RECT  29.4 2.137 29.52 2.151 ;
     RECT  34.8 2.137 34.92 2.151 ;
     RECT  40.2 2.137 40.32 2.151 ;
     RECT  45.6 2.137 45.72 2.151 ;
     RECT  51 2.137 51.12 2.151 ;
     RECT  56.4 2.137 56.52 2.151 ;
     RECT  61.8 2.137 61.92 2.151 ;
     RECT  67.2 2.137 67.32 2.151 ;
     RECT  72.6 2.137 72.72 2.151 ;
     RECT  78 2.137 78.12 2.151 ;
     RECT  83.4 2.137 83.52 2.151 ;
     RECT  88.8 2.137 88.92 2.151 ;
     RECT  142.8 2.137 142.92 2.151 ;
     RECT  148.2 2.137 148.32 2.151 ;
     RECT  153.6 2.137 153.72 2.151 ;
     RECT  159 2.137 159.12 2.151 ;
     RECT  164.4 2.137 164.52 2.151 ;
     RECT  169.8 2.137 169.92 2.151 ;
     RECT  175.2 2.137 175.32 2.151 ;
     RECT  180.6 2.137 180.72 2.151 ;
     RECT  186 2.137 186.12 2.151 ;
     RECT  191.4 2.137 191.52 2.151 ;
     RECT  196.8 2.137 196.92 2.151 ;
     RECT  202.2 2.137 202.32 2.151 ;
     RECT  207.6 2.137 207.72 2.151 ;
     RECT  213 2.137 213.12 2.151 ;
     RECT  218.4 2.137 218.52 2.151 ;
     RECT  223.8 2.137 223.92 2.151 ;
     RECT  229.2 2.137 229.32 2.151 ;
     RECT  234.6 2.137 234.72 2.151 ;
     RECT  240 2.137 240.12 2.151 ;
     RECT  245.4 2.137 245.52 2.151 ;
     RECT  250.8 2.137 250.92 2.151 ;
     RECT  256.2 2.137 256.32 2.151 ;
     RECT  261.6 2.137 261.72 2.151 ;
     RECT  267 2.137 267.12 2.151 ;
     RECT  115.8 2.137 116.808 2.195 ;
     RECT  117.936 1.955 118.92 2.195 ;
     RECT  120.24 1.955 123.24 2.195 ;
     RECT  131.904 1.763 133.704 2.243 ;
     RECT  90.48 1.859 94.512 2.291 ;
     RECT  96.72 1.859 100.296 2.291 ;
     RECT  101.424 1.907 102.888 2.291 ;
     RECT  113.904 1.859 113.928 2.291 ;
     RECT  120.24 2.195 121.992 2.291 ;
     RECT  125.904 1.859 129.96 2.291 ;
     RECT  131.904 2.243 133.032 2.291 ;
     RECT  135.408 1.811 139.08 2.291 ;
     RECT  105 1.859 111.624 2.339 ;
     RECT  107.664 2.339 111.624 2.387 ;
     RECT  107.664 2.387 111.432 2.435 ;
     RECT  125.904 2.291 128.52 2.675 ;
     RECT  105 2.339 106.536 2.771 ;
     RECT  125.904 2.675 127.368 2.771 ;
     RECT  129.84 2.291 129.96 2.821 ;
     RECT  90.48 2.291 92.712 2.915 ;
     RECT  96.72 2.291 97.416 2.915 ;
     RECT  98.64 2.291 100.296 2.915 ;
     RECT  102.864 2.291 102.888 2.915 ;
     RECT  106.32 2.771 106.536 2.915 ;
     RECT  107.664 2.435 109.128 2.915 ;
     RECT  110.16 2.435 111.432 2.915 ;
     RECT  120.24 2.291 121.512 2.915 ;
     RECT  124.368 1.955 124.776 2.915 ;
     RECT  135.408 2.291 135.432 2.915 ;
     RECT  97.392 2.915 97.416 2.963 ;
     RECT  124.752 2.915 124.776 2.963 ;
     RECT  91.44 2.915 92.712 3.059 ;
     RECT  125.904 2.771 126.912 3.347 ;
     RECT  137.4 2.291 139.08 3.397 ;
     RECT  106.32 2.915 106.344 3.443 ;
     RECT  110.16 2.915 110.904 3.539 ;
     RECT  128.352 2.675 128.52 3.733 ;
     RECT  137.4 3.397 139.368 3.925 ;
     RECT  128.304 3.733 128.52 3.971 ;
     RECT  107.664 2.915 108.84 4.019 ;
     RECT  110.4 3.539 110.904 4.213 ;
     RECT  129.84 2.821 130.584 5.077 ;
     RECT  117.936 2.195 118.152 5.171 ;
     RECT  118.128 5.171 118.152 5.219 ;
     RECT  98.64 2.915 100.104 5.653 ;
     RECT  107.664 4.019 107.832 5.653 ;
     RECT  108.816 4.019 108.84 5.653 ;
     RECT  91.44 3.059 92.136 5.747 ;
     RECT  107.664 5.653 108.84 5.747 ;
     RECT  126.192 3.347 126.912 6.085 ;
     RECT  124.656 5.605 124.68 6.179 ;
     RECT  131.904 2.291 132.312 6.181 ;
     RECT  107.664 5.747 108.072 6.229 ;
     RECT  98.64 5.653 100.344 6.323 ;
     RECT  98.928 6.323 100.344 6.371 ;
     RECT  137.4 3.925 139.944 6.661 ;
     RECT  105 2.771 105.312 6.805 ;
     RECT  126.192 6.085 127.128 6.899 ;
     RECT  94.2 2.291 94.512 7.237 ;
     RECT  131.616 6.181 132.312 7.475 ;
     RECT  129.744 5.077 130.584 8.051 ;
     RECT  136.224 3.925 136.248 8.437 ;
     RECT  107.184 6.229 108.072 8.483 ;
     RECT  136.032 8.437 136.248 8.485 ;
     RECT  137.4 6.661 140.28 8.485 ;
     RECT  99.072 6.371 100.344 8.869 ;
     RECT  126.192 6.899 126.912 9.061 ;
     RECT  107.664 8.483 108.072 9.155 ;
     RECT  136.032 8.485 140.28 9.155 ;
     RECT  136.032 9.155 139.848 9.203 ;
     RECT  99.072 8.869 100.536 9.397 ;
     RECT  129.744 8.051 130.344 9.779 ;
     RECT  129.888 9.779 130.344 9.923 ;
     RECT  107.952 9.155 108.072 10.117 ;
     RECT  107.376 10.117 108.072 10.213 ;
     RECT  126.144 9.061 126.912 10.837 ;
     RECT  107.376 10.213 108.216 10.883 ;
     RECT  126.144 10.837 127.032 11.845 ;
     RECT  137.232 9.203 139.848 12.035 ;
     RECT  130.32 9.923 130.344 12.517 ;
     RECT  129.936 12.517 130.344 12.563 ;
     RECT  105 6.805 105.912 13.045 ;
     RECT  107.952 10.883 108.216 13.573 ;
     RECT  105 13.045 106.584 13.619 ;
     RECT  136.032 9.203 136.248 14.005 ;
     RECT  137.232 12.035 139.704 14.005 ;
     RECT  105 13.619 106.056 14.101 ;
     RECT  267 2.151 267.312 14.101 ;
     RECT  104.016 14.101 106.056 14.147 ;
     RECT  129.936 12.563 129.96 14.389 ;
     RECT  132 7.475 132.312 14.389 ;
     RECT  129.408 14.389 129.96 14.435 ;
     RECT  266.832 14.101 267.816 14.581 ;
     RECT  265.776 13.813 265.8 14.629 ;
     RECT  266.784 14.581 267.816 14.629 ;
     RECT  107.952 13.573 108.984 14.773 ;
     RECT  129.408 14.435 129.432 15.299 ;
     RECT  265.776 14.629 267.816 15.301 ;
     RECT  115.8 2.195 116.112 15.349 ;
     RECT  117.36 15.301 117.384 15.349 ;
     RECT  97.488 8.437 97.512 15.443 ;
     RECT  261.6 2.151 261.912 15.445 ;
     RECT  261.456 15.445 261.912 15.493 ;
     RECT  263.376 15.349 263.4 15.493 ;
     RECT  107.952 14.773 109.032 15.587 ;
     RECT  261.456 15.493 263.4 15.877 ;
     RECT  261.456 15.877 264.12 15.925 ;
     RECT  265.248 15.301 267.816 15.925 ;
     RECT  91.44 5.747 92.088 16.117 ;
     RECT  261.456 15.925 267.816 16.309 ;
     RECT  119.232 6.181 119.256 16.549 ;
     RECT  115.8 15.349 117.384 16.595 ;
     RECT  122.832 15.253 122.856 16.595 ;
     RECT  261.456 16.309 267.864 16.885 ;
     RECT  128.304 3.971 128.376 16.933 ;
     RECT  261.456 16.885 267.912 16.933 ;
     RECT  104.016 14.147 105.912 17.123 ;
     RECT  260.736 16.933 267.912 17.123 ;
     RECT  250.8 2.151 251.112 17.461 ;
     RECT  246.768 16.549 246.792 17.603 ;
     RECT  99.072 9.397 101.448 17.699 ;
     RECT  257.616 16.501 257.64 17.699 ;
     RECT  261.504 17.123 267.912 17.699 ;
     RECT  261.6 17.699 267.912 17.843 ;
     RECT  136.032 14.005 139.704 17.941 ;
     RECT  256.2 2.151 256.512 17.941 ;
     RECT  252.48 17.557 252.504 18.181 ;
     RECT  131.712 14.389 132.312 18.275 ;
     RECT  261.6 17.843 267.864 18.323 ;
     RECT  240 2.151 240.312 18.421 ;
     RECT  252.48 18.181 252.888 18.421 ;
     RECT  118.944 16.549 119.256 18.565 ;
     RECT  252.48 18.421 253.8 18.613 ;
     RECT  132 18.275 132.312 18.709 ;
     RECT  229.2 2.151 229.512 18.709 ;
     RECT  245.4 2.151 245.712 18.709 ;
     RECT  252.48 18.613 254.472 18.709 ;
     RECT  118.8 18.565 119.256 18.757 ;
     RECT  229.2 18.709 229.608 18.757 ;
     RECT  255.6 17.941 256.512 18.757 ;
     RECT  261.6 18.323 267.312 18.805 ;
     RECT  250.56 17.461 251.112 18.899 ;
     RECT  261.216 18.805 267.312 18.899 ;
     RECT  245.4 18.709 246.264 18.901 ;
     RECT  115.8 16.595 116.112 19.093 ;
     RECT  231.696 18.757 231.72 19.237 ;
     RECT  228.24 18.757 229.608 19.283 ;
     RECT  252.48 18.709 254.568 19.285 ;
     RECT  255.6 18.757 257.16 19.285 ;
     RECT  234.6 2.151 234.912 19.333 ;
     RECT  231.264 19.237 231.72 19.427 ;
     RECT  264.432 18.899 267.312 19.427 ;
     RECT  264.672 19.427 267.312 19.475 ;
     RECT  265.008 19.475 267.312 19.523 ;
     RECT  228.24 19.283 229.512 19.573 ;
     RECT  250.8 18.899 251.112 19.573 ;
     RECT  252.48 19.285 257.496 19.573 ;
     RECT  227.28 19.573 229.512 19.619 ;
     RECT  93.264 7.237 94.512 19.621 ;
     RECT  234.6 19.333 235.272 19.621 ;
     RECT  265.248 19.523 267.312 19.717 ;
     RECT  265.248 19.717 267.864 19.763 ;
     RECT  261.216 18.899 263.304 19.811 ;
     RECT  239.088 18.421 240.312 19.813 ;
     RECT  242.256 19.717 242.28 19.861 ;
     RECT  107.952 15.587 108.216 19.909 ;
     RECT  114.048 15.061 114.072 19.909 ;
     RECT  91.248 16.117 92.088 20.003 ;
     RECT  231.264 19.427 231.288 20.003 ;
     RECT  114.048 19.909 114.264 20.053 ;
     RECT  259.296 18.757 259.32 20.099 ;
     RECT  117.36 16.595 117.384 20.197 ;
     RECT  118.8 18.757 119.304 20.197 ;
     RECT  236.784 17.605 236.808 20.293 ;
     RECT  113.376 20.053 114.264 20.485 ;
     RECT  115.344 19.093 116.112 20.485 ;
     RECT  132 18.709 132.408 20.485 ;
     RECT  233.952 19.621 235.272 20.579 ;
     RECT  261.6 19.811 263.304 20.771 ;
     RECT  113.376 20.485 116.112 20.963 ;
     RECT  227.28 19.619 227.304 20.965 ;
     RECT  242.256 19.861 242.376 21.013 ;
     RECT  265.344 19.763 267.864 21.013 ;
     RECT  269.808 20.101 269.832 21.059 ;
     RECT  264.336 20.725 264.36 21.061 ;
     RECT  265.344 21.013 267.912 21.061 ;
     RECT  238.512 19.813 240.312 21.109 ;
     RECT  242.112 21.013 242.376 21.109 ;
     RECT  238.512 21.109 242.376 21.157 ;
     RECT  249.12 20.053 249.144 21.205 ;
     RECT  236.784 20.293 237.24 21.301 ;
     RECT  245.4 18.901 246.552 21.443 ;
     RECT  249.12 21.205 249.192 21.491 ;
     RECT  250.8 19.573 257.496 21.589 ;
     RECT  238.512 21.157 242.424 21.635 ;
     RECT  110.4 4.213 111.048 21.637 ;
     RECT  112.272 16.501 112.296 21.637 ;
     RECT  229.2 19.619 229.512 21.637 ;
     RECT  261.6 20.771 263.256 21.683 ;
     RECT  242.112 21.635 242.424 21.779 ;
     RECT  236.304 21.301 237.24 21.925 ;
     RECT  249.12 21.491 249.144 22.021 ;
     RECT  263.184 21.683 263.256 22.069 ;
     RECT  264.336 21.061 267.912 22.069 ;
     RECT  136.032 17.941 140.088 22.259 ;
     RECT  260.4 21.397 260.424 22.259 ;
     RECT  245.4 21.443 246.36 22.453 ;
     RECT  99.072 17.699 100.536 22.501 ;
     RECT  238.512 21.635 240.408 22.501 ;
     RECT  107.952 19.909 109.032 22.547 ;
     RECT  248.496 22.021 249.144 22.549 ;
     RECT  124.992 21.061 125.016 22.597 ;
     RECT  126.144 11.845 127.08 22.597 ;
     RECT  238.224 22.501 240.408 22.643 ;
     RECT  128.112 16.933 128.376 22.741 ;
     RECT  250.8 21.589 258.216 22.741 ;
     RECT  259.296 21.637 259.32 22.741 ;
     RECT  136.032 22.259 139.752 22.789 ;
     RECT  91.248 20.003 92.04 22.835 ;
     RECT  99.072 22.501 101.016 22.835 ;
     RECT  117.36 20.197 119.304 22.835 ;
     RECT  234.6 20.579 234.912 22.981 ;
     RECT  235.968 21.925 237.24 22.981 ;
     RECT  263.184 22.069 267.912 23.075 ;
     RECT  91.68 22.835 92.04 23.173 ;
     RECT  93.216 19.621 94.512 23.173 ;
     RECT  124.992 22.597 127.08 23.173 ;
     RECT  128.112 22.741 129.048 23.173 ;
     RECT  229.2 21.637 229.752 23.317 ;
     RECT  228.528 23.317 229.752 23.363 ;
     RECT  234.6 22.981 237.432 23.363 ;
     RECT  250.8 22.741 259.32 23.363 ;
     RECT  226.32 20.965 227.304 23.555 ;
     RECT  226.32 23.555 226.344 23.699 ;
     RECT  239.184 22.643 240.408 23.843 ;
     RECT  117.36 22.835 117.912 23.845 ;
     RECT  119.232 22.835 119.304 23.845 ;
     RECT  245.4 22.453 246.408 23.845 ;
     RECT  114.048 20.963 116.112 23.893 ;
     RECT  99.36 22.835 101.016 23.987 ;
     RECT  231.456 22.645 231.48 23.987 ;
     RECT  235.968 23.363 237.432 23.987 ;
     RECT  263.184 23.075 267.864 23.987 ;
     RECT  132 20.485 132.504 24.085 ;
     RECT  131.472 24.085 132.504 24.131 ;
     RECT  225.168 23.317 225.192 24.131 ;
     RECT  239.184 23.843 240.312 24.179 ;
     RECT  261.6 21.683 261.912 24.325 ;
     RECT  263.184 23.987 267.528 24.325 ;
     RECT  252.72 23.363 259.32 24.421 ;
     RECT  113.712 23.893 116.112 24.515 ;
     RECT  228.528 23.363 229.512 24.515 ;
     RECT  248.496 22.549 249.48 24.517 ;
     RECT  223.8 2.151 224.112 24.661 ;
     RECT  252.72 24.421 259.656 24.707 ;
     RECT  245.4 23.845 246.504 24.709 ;
     RECT  242.256 21.779 242.424 24.805 ;
     RECT  207.6 2.151 207.912 24.901 ;
     RECT  225.264 24.469 225.768 24.995 ;
     RECT  135.6 22.789 139.752 25.043 ;
     RECT  241.776 24.805 242.424 25.043 ;
     RECT  218.4 2.151 218.712 25.045 ;
     RECT  261.6 24.325 267.528 25.139 ;
     RECT  243.744 22.549 243.768 25.141 ;
     RECT  245.4 24.709 247.272 25.141 ;
     RECT  131.472 24.131 132.408 25.187 ;
     RECT  258.912 24.707 259.656 25.189 ;
     RECT  258.912 25.189 259.8 25.333 ;
     RECT  114.048 24.515 116.112 25.477 ;
     RECT  248.448 24.517 249.48 25.477 ;
     RECT  250.8 23.363 251.736 25.477 ;
     RECT  231.648 25.045 231.672 25.525 ;
     RECT  218.4 25.045 218.808 25.573 ;
     RECT  258.912 25.333 260.376 25.573 ;
     RECT  261.6 25.139 261.912 25.573 ;
     RECT  91.68 23.173 94.512 25.669 ;
     RECT  95.712 16.165 95.736 25.669 ;
     RECT  91.68 25.669 95.736 25.715 ;
     RECT  225.744 24.995 225.768 25.715 ;
     RECT  231.024 25.525 231.672 25.715 ;
     RECT  242.256 25.043 242.424 25.717 ;
     RECT  265.536 25.139 267.528 25.763 ;
     RECT  221.664 25.237 221.688 25.765 ;
     RECT  117.36 23.845 119.304 25.813 ;
     RECT  223.536 24.661 224.112 25.861 ;
     RECT  135.84 25.043 139.752 26.051 ;
     RECT  258.912 25.573 261.912 26.099 ;
     RECT  134.736 26.101 134.76 26.197 ;
     RECT  218.4 25.573 219.24 26.243 ;
     RECT  220.272 25.045 220.296 26.245 ;
     RECT  248.448 25.477 251.736 26.245 ;
     RECT  252.72 24.707 257.928 26.245 ;
     RECT  117.312 25.813 119.304 26.291 ;
     RECT  177.792 25.237 177.816 26.291 ;
     RECT  266.064 25.763 267.528 26.339 ;
     RECT  239.856 24.179 240.312 26.485 ;
     RECT  218.4 26.243 218.808 26.533 ;
     RECT  218.304 26.533 218.808 26.579 ;
     RECT  248.448 26.245 257.928 26.627 ;
     RECT  134.688 26.197 134.76 26.675 ;
     RECT  262.896 25.139 264.264 26.723 ;
     RECT  223.536 25.861 224.76 26.725 ;
     RECT  266.112 26.339 267.528 26.819 ;
     RECT  121.2 2.915 121.512 26.917 ;
     RECT  119.088 26.291 119.304 26.963 ;
     RECT  99.36 23.987 100.536 27.061 ;
     RECT  238.656 25.861 238.68 27.061 ;
     RECT  243.744 25.141 247.272 27.061 ;
     RECT  248.448 26.627 251.976 27.061 ;
     RECT  259.44 26.099 261.912 27.061 ;
     RECT  229.2 24.515 229.512 27.157 ;
     RECT  231.024 25.715 231.048 27.157 ;
     RECT  242.256 25.717 242.568 27.301 ;
     RECT  242.016 27.301 242.568 27.347 ;
     RECT  259.44 27.061 262.104 27.347 ;
     RECT  207.6 24.901 208.104 27.395 ;
     RECT  221.664 25.765 222.024 27.395 ;
     RECT  223.152 26.725 224.76 27.395 ;
     RECT  239.856 26.485 240.408 27.443 ;
     RECT  243.744 27.061 251.976 27.445 ;
     RECT  242.016 27.347 242.376 27.491 ;
     RECT  243.6 27.445 251.976 27.491 ;
     RECT  113.712 25.477 116.112 27.587 ;
     RECT  99.168 27.061 100.536 27.635 ;
     RECT  220.176 26.245 220.296 27.637 ;
     RECT  266.112 26.819 267.312 27.829 ;
     RECT  206.544 27.829 206.568 27.875 ;
     RECT  253.056 26.627 257.928 27.875 ;
     RECT  214.704 27.205 214.728 27.877 ;
     RECT  265.968 27.829 267.312 27.877 ;
     RECT  248.448 27.491 251.976 27.923 ;
     RECT  91.68 25.715 95.448 27.925 ;
     RECT  91.68 27.925 95.832 27.971 ;
     RECT  114.24 27.587 116.112 27.971 ;
     RECT  134.736 26.675 134.76 27.971 ;
     RECT  263.664 26.723 264.264 27.971 ;
     RECT  233.376 25.573 233.4 28.019 ;
     RECT  264.192 27.971 264.264 28.163 ;
     RECT  136.176 26.051 139.752 28.213 ;
     RECT  219.888 27.637 220.296 28.213 ;
     RECT  221.664 27.395 221.928 28.213 ;
     RECT  238.656 27.061 238.824 28.213 ;
     RECT  239.856 27.443 240.312 28.213 ;
     RECT  214.32 27.877 214.728 28.259 ;
     RECT  120.288 26.917 121.512 28.307 ;
     RECT  229.2 27.157 231.048 28.403 ;
     RECT  99.36 27.635 100.536 28.405 ;
     RECT  101.664 27.877 101.688 28.405 ;
     RECT  265.584 27.877 267.312 28.405 ;
     RECT  110.4 21.637 112.296 28.453 ;
     RECT  117.312 26.291 117.912 28.453 ;
     RECT  119.232 26.963 119.304 28.453 ;
     RECT  231.024 28.403 231.048 28.453 ;
     RECT  242.016 27.491 242.28 28.453 ;
     RECT  243.6 27.491 247.416 28.453 ;
     RECT  265.536 28.405 267.312 28.453 ;
     RECT  91.68 27.971 94.68 28.547 ;
     RECT  117.312 28.453 119.304 28.547 ;
     RECT  249.168 27.923 251.976 28.739 ;
     RECT  219.888 28.213 221.928 28.741 ;
     RECT  234.6 23.363 234.912 28.789 ;
     RECT  235.968 23.987 236.616 28.789 ;
     RECT  265.536 28.453 267.576 28.789 ;
     RECT  234.6 28.789 236.616 29.075 ;
     RECT  92.064 28.547 94.68 29.123 ;
     RECT  110.016 28.453 112.296 29.123 ;
     RECT  124.992 23.173 129.048 29.123 ;
     RECT  131.616 25.187 132.408 29.123 ;
     RECT  238.656 28.213 240.312 29.123 ;
     RECT  242.016 28.453 247.416 29.123 ;
     RECT  259.776 27.347 262.104 29.123 ;
     RECT  226.32 29.029 226.344 29.317 ;
     RECT  226.32 29.317 226.872 29.363 ;
     RECT  213 2.151 213.312 29.365 ;
     RECT  229.2 28.403 229.512 29.365 ;
     RECT  231.024 28.453 231.384 29.365 ;
     RECT  253.296 27.875 257.928 29.365 ;
     RECT  259.776 29.123 259.944 29.365 ;
     RECT  245.04 29.123 247.416 29.509 ;
     RECT  253.296 29.365 259.944 29.509 ;
     RECT  234.6 29.075 234.912 29.605 ;
     RECT  264.24 28.163 264.264 29.605 ;
     RECT  265.536 28.789 267.816 29.605 ;
     RECT  235.968 29.075 236.616 29.651 ;
     RECT  238.416 29.125 238.44 29.651 ;
     RECT  242.016 29.123 243.768 29.699 ;
     RECT  219.84 28.741 221.928 29.701 ;
     RECT  264.24 29.605 267.816 29.701 ;
     RECT  223.8 27.395 224.112 29.797 ;
     RECT  225.12 28.693 225.144 29.797 ;
     RECT  213 29.365 213.624 29.893 ;
     RECT  245.04 29.509 247.656 30.035 ;
     RECT  110.016 29.123 111.432 30.083 ;
     RECT  236.592 29.651 236.616 30.083 ;
     RECT  261.024 29.123 262.104 30.133 ;
     RECT  135.696 28.213 139.752 30.181 ;
     RECT  247.632 30.035 247.656 30.181 ;
     RECT  252.72 29.509 259.944 30.181 ;
     RECT  261.024 30.133 262.2 30.181 ;
     RECT  110.4 30.083 111.432 30.275 ;
     RECT  125.76 29.123 129.048 30.275 ;
     RECT  216 29.125 216.024 30.275 ;
     RECT  264.24 29.701 267.912 30.275 ;
     RECT  229.104 29.365 229.512 30.371 ;
     RECT  223.8 29.797 225.144 30.421 ;
     RECT  117.36 28.547 119.304 30.469 ;
     RECT  226.8 29.363 226.872 30.611 ;
     RECT  243.6 29.699 243.768 30.611 ;
     RECT  219.792 29.701 221.928 30.661 ;
     RECT  107.952 22.547 108.216 30.709 ;
     RECT  117.36 30.469 120.216 30.709 ;
     RECT  121.2 28.307 121.512 30.709 ;
     RECT  214.704 28.259 214.728 30.757 ;
     RECT  219.792 30.661 222.264 30.803 ;
     RECT  128.256 30.275 129.048 30.851 ;
     RECT  131.616 29.123 132.312 30.851 ;
     RECT  264.24 30.275 267.864 30.851 ;
     RECT  134.736 30.181 139.752 30.947 ;
     RECT  269.808 30.757 269.832 30.947 ;
     RECT  231.024 29.365 232.296 30.995 ;
     RECT  233.76 29.605 234.912 30.995 ;
     RECT  252.72 30.181 262.2 30.995 ;
     RECT  134.736 30.947 134.76 31.043 ;
     RECT  265.584 30.851 267.864 31.139 ;
     RECT  212.832 29.893 213.624 31.141 ;
     RECT  214.704 30.757 215.256 31.141 ;
     RECT  219.792 30.803 221.928 31.187 ;
     RECT  243.744 30.611 243.768 31.285 ;
     RECT  245.04 30.035 246.504 31.285 ;
     RECT  95.808 27.971 95.832 31.379 ;
     RECT  136.224 30.947 139.752 31.379 ;
     RECT  260.64 30.995 262.2 31.379 ;
     RECT  264.24 30.851 264.264 31.379 ;
     RECT  261.6 31.379 262.2 31.477 ;
     RECT  234.048 30.995 234.912 31.525 ;
     RECT  232.272 30.995 232.296 31.619 ;
     RECT  266.592 31.139 267.864 31.717 ;
     RECT  242.016 29.699 242.52 31.765 ;
     RECT  247.632 30.181 247.944 31.811 ;
     RECT  117.36 30.709 121.512 31.813 ;
     RECT  110.4 30.275 111.384 31.861 ;
     RECT  237.456 31.765 237.48 31.861 ;
     RECT  247.68 31.811 247.944 31.861 ;
     RECT  265.584 31.139 265.608 31.909 ;
     RECT  112.56 29.605 112.584 31.955 ;
     RECT  117.36 31.813 121.848 31.955 ;
     RECT  125.76 30.275 127.224 31.955 ;
     RECT  212.832 31.141 215.256 31.955 ;
     RECT  243.744 31.285 246.504 31.955 ;
     RECT  213 31.955 215.256 32.195 ;
     RECT  213 32.195 214.104 32.243 ;
     RECT  223.8 30.421 225.528 32.243 ;
     RECT  221.232 31.187 221.928 32.291 ;
     RECT  107.952 30.709 108.408 32.341 ;
     RECT  107.952 32.341 108.744 32.437 ;
     RECT  247.68 31.861 247.992 32.437 ;
     RECT  249.168 28.739 251.304 32.437 ;
     RECT  265.056 31.909 265.608 32.437 ;
     RECT  118.896 31.955 121.848 32.483 ;
     RECT  241.776 31.765 242.52 32.485 ;
     RECT  243.744 31.955 246.024 32.485 ;
     RECT  99.36 28.405 101.688 32.531 ;
     RECT  117.36 31.955 117.912 32.531 ;
     RECT  221.616 32.291 221.928 32.531 ;
     RECT  215.232 32.195 215.256 32.579 ;
     RECT  231.024 30.995 231.288 32.579 ;
     RECT  241.776 32.485 246.024 32.629 ;
     RECT  241.632 32.629 246.024 32.771 ;
     RECT  87.456 32.773 87.48 32.819 ;
     RECT  218.304 26.579 218.712 32.819 ;
     RECT  110.304 31.861 111.384 32.821 ;
     RECT  218.4 32.819 218.712 32.821 ;
     RECT  219.792 31.187 220.104 32.821 ;
     RECT  264.816 32.437 265.608 32.821 ;
     RECT  266.592 31.717 267.912 32.821 ;
     RECT  97.2 15.877 97.224 32.869 ;
     RECT  241.632 32.771 245.712 32.869 ;
     RECT  97.2 32.869 97.464 32.965 ;
     RECT  97.152 32.965 97.464 33.011 ;
     RECT  92.064 29.123 94.512 33.013 ;
     RECT  229.2 30.371 229.512 33.013 ;
     RECT  231.024 32.579 231.048 33.013 ;
     RECT  239.472 29.123 240.312 33.013 ;
     RECT  241.44 32.869 245.712 33.013 ;
     RECT  234.048 31.525 235.08 33.061 ;
     RECT  264.816 32.821 267.912 33.107 ;
     RECT  105 17.123 105.912 33.109 ;
     RECT  92.064 33.013 94.728 33.155 ;
     RECT  99.36 32.531 100.536 33.157 ;
     RECT  206.547 27.875 206.565 33.205 ;
     RECT  206.352 33.205 206.568 33.251 ;
     RECT  225.264 32.243 225.528 33.251 ;
     RECT  222.72 33.013 222.744 33.253 ;
     RECT  223.8 32.243 224.232 33.253 ;
     RECT  221.616 32.531 221.736 33.301 ;
     RECT  234.048 33.061 235.896 33.301 ;
     RECT  218.4 32.821 220.104 33.445 ;
     RECT  221.184 33.301 221.736 33.445 ;
     RECT  218.4 33.445 221.736 33.493 ;
     RECT  222.72 33.253 224.232 33.493 ;
     RECT  206.352 33.251 206.52 33.587 ;
     RECT  98.64 33.157 100.536 33.589 ;
     RECT  101.52 32.531 101.688 33.589 ;
     RECT  107.568 32.437 108.744 33.589 ;
     RECT  114.384 27.971 116.112 33.589 ;
     RECT  118.896 32.483 120.216 33.589 ;
     RECT  121.2 32.483 121.848 33.589 ;
     RECT  225.264 33.251 225.288 33.589 ;
     RECT  232.224 33.013 232.248 33.589 ;
     RECT  234.048 33.301 236.136 33.589 ;
     RECT  261.6 31.477 262.92 33.589 ;
     RECT  264.816 33.107 267.864 33.635 ;
     RECT  118.896 33.589 121.848 33.683 ;
     RECT  265.92 33.635 267.864 33.683 ;
     RECT  226.848 30.611 226.872 33.779 ;
     RECT  239.472 33.013 245.712 33.829 ;
     RECT  239.472 33.829 246.024 33.875 ;
     RECT  260.976 33.589 262.92 33.875 ;
     RECT  98.64 33.589 101.688 33.923 ;
     RECT  105 33.109 105.96 33.973 ;
     RECT  107.232 33.589 108.744 33.973 ;
     RECT  125.904 31.955 127.224 34.069 ;
     RECT  247.68 32.437 251.544 34.069 ;
     RECT  252.72 30.995 259.464 34.069 ;
     RECT  232.224 33.589 236.136 34.115 ;
     RECT  260.976 33.875 262.2 34.115 ;
     RECT  229.2 33.013 231.048 34.163 ;
     RECT  120.816 33.683 121.848 34.165 ;
     RECT  237.456 31.861 238.344 34.165 ;
     RECT  239.472 33.875 240.6 34.165 ;
     RECT  225.216 33.589 225.288 34.213 ;
     RECT  92.064 33.155 94.632 34.259 ;
     RECT  118.896 33.683 119.304 34.259 ;
     RECT  136.224 31.379 139.656 34.259 ;
     RECT  265.92 33.683 267.672 34.307 ;
     RECT  236.112 34.115 236.136 34.309 ;
     RECT  237.456 34.165 240.6 34.309 ;
     RECT  114.384 33.589 116.856 34.355 ;
     RECT  232.224 34.115 234.912 34.355 ;
     RECT  236.112 34.309 240.6 34.355 ;
     RECT  110.16 32.821 111.384 34.357 ;
     RECT  113.184 32.917 113.208 34.357 ;
     RECT  264.816 33.635 264.84 34.403 ;
     RECT  117.888 32.531 117.912 34.501 ;
     RECT  265.92 34.307 267.312 34.645 ;
     RECT  241.632 33.875 246.024 34.691 ;
     RECT  125.664 34.069 127.224 34.693 ;
     RECT  128.304 30.851 129.048 34.693 ;
     RECT  119.232 34.259 119.304 34.741 ;
     RECT  95.856 31.861 95.88 34.837 ;
     RECT  95.856 34.837 96.024 34.883 ;
     RECT  229.2 34.163 229.944 34.933 ;
     RECT  236.112 34.355 236.904 35.075 ;
     RECT  218.4 33.493 224.232 35.123 ;
     RECT  247.68 34.069 259.464 35.171 ;
     RECT  114.384 34.355 116.112 35.317 ;
     RECT  110.16 34.357 113.208 35.363 ;
     RECT  265.584 34.645 267.312 35.363 ;
     RECT  222.144 35.123 224.232 35.459 ;
     RECT  266.304 35.363 267.312 35.459 ;
     RECT  225.216 34.213 225.432 35.507 ;
     RECT  114.24 35.317 116.112 35.557 ;
     RECT  225.216 35.507 225.24 35.795 ;
     RECT  125.664 34.693 129.048 35.797 ;
     RECT  119.232 34.741 119.352 35.845 ;
     RECT  120.816 34.165 121.992 35.845 ;
     RECT  242.016 34.691 246.024 35.893 ;
     RECT  110.16 35.363 112.296 35.939 ;
     RECT  206.496 33.587 206.52 35.939 ;
     RECT  223.68 35.459 224.232 35.939 ;
     RECT  258.336 35.171 259.464 35.939 ;
     RECT  218.4 35.123 220.776 35.987 ;
     RECT  218.4 35.987 220.104 35.989 ;
     RECT  236.88 35.075 236.904 35.989 ;
     RECT  231.024 34.163 231.048 36.035 ;
     RECT  217.728 35.989 220.104 36.083 ;
     RECT  247.68 35.171 257.304 36.083 ;
     RECT  228.24 34.933 229.944 36.085 ;
     RECT  95.904 34.883 96.024 36.227 ;
     RECT  228.24 36.085 230.136 36.227 ;
     RECT  263.28 34.741 263.304 36.227 ;
     RECT  232.224 34.355 232.248 36.229 ;
     RECT  247.68 36.083 257.208 36.325 ;
     RECT  113.376 35.557 116.112 36.373 ;
     RECT  223.8 35.939 224.232 36.373 ;
     RECT  207.6 27.395 207.912 36.421 ;
     RECT  247.536 36.325 257.208 36.421 ;
     RECT  261.408 34.115 262.2 36.515 ;
     RECT  266.784 35.459 267.312 36.515 ;
     RECT  247.392 36.421 257.208 36.611 ;
     RECT  266.832 36.515 267.312 36.611 ;
     RECT  261.6 36.515 262.2 36.659 ;
     RECT  97.152 33.011 97.176 36.803 ;
     RECT  238.32 34.355 240.6 36.805 ;
     RECT  247.536 36.611 257.208 36.899 ;
     RECT  87.459 32.819 87.477 36.997 ;
     RECT  232.128 36.229 232.248 36.997 ;
     RECT  87.456 36.997 87.768 37.043 ;
     RECT  247.68 36.899 257.208 37.091 ;
     RECT  266.88 36.611 267.312 37.091 ;
     RECT  217.728 36.083 219.768 37.187 ;
     RECT  117.168 34.501 117.912 37.237 ;
     RECT  119.232 35.845 122.232 37.237 ;
     RECT  242.016 35.893 246.312 37.283 ;
     RECT  247.68 37.091 257.112 37.427 ;
     RECT  136.368 34.259 139.656 37.429 ;
     RECT  258.72 35.939 259.464 37.429 ;
     RECT  222.144 35.459 222.168 37.571 ;
     RECT  110.16 35.939 111.384 37.573 ;
     RECT  236.88 35.989 237.144 37.621 ;
     RECT  238.272 36.805 240.6 37.621 ;
     RECT  112.752 36.373 116.112 37.667 ;
     RECT  117.168 37.237 122.232 37.667 ;
     RECT  242.016 37.283 246.216 37.763 ;
     RECT  242.112 37.763 246.216 37.811 ;
     RECT  90.864 35.317 90.888 37.813 ;
     RECT  92.064 34.259 94.512 37.813 ;
     RECT  236.88 37.621 240.6 37.813 ;
     RECT  258.24 37.429 259.464 37.813 ;
     RECT  90.864 37.813 94.512 37.859 ;
     RECT  242.544 37.811 246.216 37.859 ;
     RECT  232.128 36.997 232.344 37.907 ;
     RECT  223.8 36.373 225.192 38.003 ;
     RECT  228.288 36.227 230.136 38.003 ;
     RECT  258.24 37.813 259.656 38.003 ;
     RECT  242.736 37.859 242.76 38.099 ;
     RECT  258.24 38.003 259.464 38.147 ;
     RECT  117.168 37.667 121.704 38.435 ;
     RECT  2.4 2.151 2.712 38.533 ;
     RECT  236.736 37.813 240.936 38.581 ;
     RECT  217.728 37.187 218.712 38.723 ;
     RECT  236.736 38.581 240.984 38.723 ;
     RECT  0.192 33.301 0.216 38.771 ;
     RECT  2.4 38.533 2.808 38.771 ;
     RECT  110.16 37.573 111.576 38.819 ;
     RECT  125.664 35.797 129.912 38.819 ;
     RECT  243.744 37.859 246.216 38.917 ;
     RECT  96 36.227 96.024 39.109 ;
     RECT  218.4 38.723 218.712 39.157 ;
     RECT  219.744 37.187 219.768 39.157 ;
     RECT  218.4 39.157 219.768 39.203 ;
     RECT  236.736 38.723 240.936 39.203 ;
     RECT  2.4 38.771 2.712 39.205 ;
     RECT  91.488 37.859 94.512 39.251 ;
     RECT  232.32 37.907 232.344 39.251 ;
     RECT  243.168 38.917 246.216 39.251 ;
     RECT  103.248 39.205 103.272 39.301 ;
     RECT  234.048 34.355 234.912 39.301 ;
     RECT  112.752 37.667 114.264 39.349 ;
     RECT  115.296 37.667 116.112 39.349 ;
     RECT  120.816 38.435 121.704 39.443 ;
     RECT  243.84 39.251 246.216 39.587 ;
     RECT  110.16 38.819 111.48 39.589 ;
     RECT  225.36 38.725 225.384 39.635 ;
     RECT  236.736 39.203 240.408 39.731 ;
     RECT  112.752 39.349 116.112 39.781 ;
     RECT  117.168 38.435 119.304 39.781 ;
     RECT  239.52 39.731 240.408 39.827 ;
     RECT  120.816 39.443 121.512 39.829 ;
     RECT  125.712 38.819 129.912 39.829 ;
     RECT  234.048 39.301 235.032 39.875 ;
     RECT  2.304 39.205 2.712 39.877 ;
     RECT  122.784 39.301 122.808 39.923 ;
     RECT  103.2 39.301 103.272 40.019 ;
     RECT  96 39.109 96.12 40.021 ;
     RECT  229.2 38.003 230.136 40.021 ;
     RECT  236.736 39.731 238.536 40.067 ;
     RECT  0.288 39.877 0.312 40.115 ;
     RECT  125.28 39.829 130.392 40.163 ;
     RECT  243.84 39.587 246.072 40.163 ;
     RECT  258.24 38.147 259.224 40.163 ;
     RECT  228.528 40.021 230.136 40.355 ;
     RECT  105 33.973 108.744 40.357 ;
     RECT  2.304 39.877 3.432 40.451 ;
     RECT  125.712 40.163 129.912 40.499 ;
     RECT  223.8 38.003 224.232 40.547 ;
     RECT  247.68 37.427 256.968 40.595 ;
     RECT  247.68 40.595 256.512 40.789 ;
     RECT  112.752 39.781 119.304 40.835 ;
     RECT  228.528 40.355 230.088 40.835 ;
     RECT  258.24 40.163 258.744 40.835 ;
     RECT  234.048 39.875 234.912 40.837 ;
     RECT  96 40.021 96.792 40.883 ;
     RECT  92.064 39.251 94.512 40.981 ;
     RECT  229.2 40.835 230.088 41.027 ;
     RECT  232.56 40.837 234.912 41.027 ;
     RECT  247.632 40.789 256.512 41.027 ;
     RECT  0.192 40.405 0.216 41.029 ;
     RECT  247.632 41.027 253.032 41.029 ;
     RECT  112.752 40.835 114.648 41.075 ;
     RECT  115.8 40.835 119.304 41.075 ;
     RECT  247.488 41.029 253.032 41.123 ;
     RECT  236.736 40.067 237.288 41.125 ;
     RECT  238.32 40.067 238.536 41.125 ;
     RECT  92.064 40.981 94.632 41.171 ;
     RECT  247.488 41.123 252.792 41.171 ;
     RECT  0.144 41.029 0.216 41.221 ;
     RECT  132 30.851 132.312 41.269 ;
     RECT  243.84 40.163 246.024 41.365 ;
     RECT  115.8 41.075 116.568 41.459 ;
     RECT  0.144 41.221 0.264 41.461 ;
     RECT  0.144 41.461 0.312 41.509 ;
     RECT  243.648 41.365 246.024 41.555 ;
     RECT  92.064 41.171 94.512 41.651 ;
     RECT  104.592 40.357 108.744 41.651 ;
     RECT  112.752 41.075 114.552 41.651 ;
     RECT  117.888 41.075 119.304 41.651 ;
     RECT  126.096 40.499 129.912 41.651 ;
     RECT  258.72 40.835 258.744 41.651 ;
     RECT  112.8 41.651 114.552 41.747 ;
     RECT  136.368 37.429 140.28 41.797 ;
     RECT  236.736 41.125 238.536 41.843 ;
     RECT  247.584 41.171 252.792 41.891 ;
     RECT  218.4 39.203 219.48 41.939 ;
     RECT  206.784 36.421 207.912 42.083 ;
     RECT  120.288 39.829 121.512 42.133 ;
     RECT  2.304 40.451 2.952 42.227 ;
     RECT  104.592 41.651 108.552 42.227 ;
     RECT  110.016 39.589 111.48 42.227 ;
     RECT  118.464 41.651 119.304 42.227 ;
     RECT  233.088 41.027 234.912 42.227 ;
     RECT  0.144 41.509 0.552 42.323 ;
     RECT  254.112 41.027 256.512 42.467 ;
     RECT  118.512 42.227 119.304 42.565 ;
     RECT  120.288 42.133 121.656 42.565 ;
     RECT  227.328 39.637 227.352 42.565 ;
     RECT  103.248 40.019 103.272 42.709 ;
     RECT  106.704 42.227 108.552 42.709 ;
     RECT  113.568 41.747 114.552 42.709 ;
     RECT  115.8 41.459 116.112 42.709 ;
     RECT  247.584 41.891 248.52 42.709 ;
     RECT  104.592 42.227 105.672 42.803 ;
     RECT  236.736 41.843 237.288 42.803 ;
     RECT  99.12 33.923 101.688 42.853 ;
     RECT  92.544 41.651 94.512 42.997 ;
     RECT  99.12 42.853 101.832 43.285 ;
     RECT  2.304 42.227 2.856 43.379 ;
     RECT  87.744 37.043 87.768 43.379 ;
     RECT  247.056 42.709 248.52 43.379 ;
     RECT  102.912 42.709 103.272 43.427 ;
     RECT  126.192 41.651 129.912 43.573 ;
     RECT  106.704 42.709 108.84 43.811 ;
     RECT  227.328 42.565 227.544 43.813 ;
     RECT  0.144 42.323 0.168 43.955 ;
     RECT  98.928 43.285 101.832 43.955 ;
     RECT  125.856 43.573 129.912 43.955 ;
     RECT  2.304 43.379 2.712 44.003 ;
     RECT  254.976 42.467 256.512 44.147 ;
     RECT  257.856 43.285 257.88 44.339 ;
     RECT  103.248 43.427 103.272 44.341 ;
     RECT  133.872 43.813 133.896 44.341 ;
     RECT  131.616 41.269 132.312 44.437 ;
     RECT  238.32 41.843 238.536 44.437 ;
     RECT  239.52 39.827 240.312 44.437 ;
     RECT  98.928 43.955 100.68 44.483 ;
     RECT  115.8 42.709 117.048 44.483 ;
     RECT  118.512 42.565 121.656 44.483 ;
     RECT  236.736 42.803 236.904 44.483 ;
     RECT  254.976 44.147 255.192 44.483 ;
     RECT  247.056 43.379 248.424 44.533 ;
     RECT  255.072 44.483 255.192 44.579 ;
     RECT  97.872 43.285 97.896 44.627 ;
     RECT  106.704 43.811 108.696 44.725 ;
     RECT  247.056 44.533 248.52 44.819 ;
     RECT  238.32 44.437 240.312 44.821 ;
     RECT  256.2 44.147 256.512 44.869 ;
     RECT  257.664 44.389 257.688 44.869 ;
     RECT  238.32 44.821 240.456 44.917 ;
     RECT  118.512 44.483 119.064 44.965 ;
     RECT  242.64 42.133 242.664 44.965 ;
     RECT  243.744 41.555 246.024 44.965 ;
     RECT  133.344 44.341 133.896 45.059 ;
     RECT  242.64 44.965 246.024 45.155 ;
     RECT  249.6 41.891 252.792 45.155 ;
     RECT  238.32 44.917 240.504 45.157 ;
     RECT  233.856 42.227 234.912 45.299 ;
     RECT  92.448 42.997 94.512 45.349 ;
     RECT  236.88 44.483 236.904 45.349 ;
     RECT  238.224 45.157 240.504 45.349 ;
     RECT  236.88 45.349 240.504 45.491 ;
     RECT  252.768 45.155 252.792 45.491 ;
     RECT  256.2 44.869 257.688 45.539 ;
     RECT  113.136 42.709 114.552 45.541 ;
     RECT  103.248 44.341 103.752 45.635 ;
     RECT  227.328 43.813 228.024 45.635 ;
     RECT  236.88 45.491 236.904 45.635 ;
     RECT  256.2 45.539 257.064 45.635 ;
     RECT  247.056 44.819 247.848 45.685 ;
     RECT  242.64 45.155 245.712 45.731 ;
     RECT  120.288 44.483 121.656 45.733 ;
     RECT  227.52 45.635 228.024 45.779 ;
     RECT  242.64 45.731 242.664 45.781 ;
     RECT  98.928 44.483 99.912 45.877 ;
     RECT  234.048 45.299 234.912 45.971 ;
     RECT  243.744 45.731 245.712 45.971 ;
     RECT  243.744 45.971 243.96 46.019 ;
     RECT  249.6 45.155 251.112 46.067 ;
     RECT  110.16 42.227 111.48 46.069 ;
     RECT  112.896 45.541 114.552 46.069 ;
     RECT  238.224 45.491 240.504 46.069 ;
     RECT  245.088 45.971 245.712 46.211 ;
     RECT  120.144 45.733 121.656 46.259 ;
     RECT  232.56 45.253 232.584 46.259 ;
     RECT  110.16 46.069 114.552 46.307 ;
     RECT  263.232 38.581 263.256 46.307 ;
     RECT  241.92 45.781 242.664 46.355 ;
     RECT  98.832 45.877 99.912 46.357 ;
     RECT  253.872 46.117 253.896 46.547 ;
     RECT  238.224 46.069 240.552 46.549 ;
     RECT  246.768 45.685 247.848 46.549 ;
     RECT  110.4 46.307 114.552 46.643 ;
     RECT  237.984 46.549 240.552 46.691 ;
     RECT  249.888 46.067 251.112 46.693 ;
     RECT  241.92 46.355 241.944 46.739 ;
     RECT  120.288 46.259 121.656 46.741 ;
     RECT  243.936 46.019 243.96 46.787 ;
     RECT  246.768 46.549 248.472 46.787 ;
     RECT  255.168 44.579 255.192 46.787 ;
     RECT  112.896 46.643 114.552 46.835 ;
     RECT  227.52 45.779 227.544 46.883 ;
     RECT  238.224 46.691 240.552 46.883 ;
     RECT  238.224 46.883 240.456 47.075 ;
     RECT  136.08 41.797 140.28 47.363 ;
     RECT  247.344 46.787 248.472 47.363 ;
     RECT  249.888 46.693 251.928 47.363 ;
     RECT  248.448 47.363 248.472 47.411 ;
     RECT  247.344 47.363 247.368 47.459 ;
     RECT  249.888 47.363 251.112 47.605 ;
     RECT  249.408 47.605 251.112 47.651 ;
     RECT  98.832 46.357 100.344 47.845 ;
     RECT  253.056 47.413 253.08 47.845 ;
     RECT  238.512 47.075 240.456 47.939 ;
     RECT  249.408 47.651 249.672 48.179 ;
     RECT  113.76 46.835 114.552 48.229 ;
     RECT  103.248 45.635 103.272 48.421 ;
     RECT  238.512 47.939 238.536 48.707 ;
     RECT  250.8 47.651 251.112 48.805 ;
     RECT  98.64 47.845 100.344 48.851 ;
     RECT  115.8 44.483 116.112 48.949 ;
     RECT  250.8 48.805 251.64 48.997 ;
     RECT  249.648 48.179 249.672 49.235 ;
     RECT  252.864 47.845 253.08 49.235 ;
     RECT  252.864 49.235 252.888 49.283 ;
     RECT  120.288 46.741 121.752 49.331 ;
     RECT  96.096 40.883 96.792 49.525 ;
     RECT  240 47.939 240.456 49.811 ;
     RECT  113.232 48.229 114.552 50.051 ;
     RECT  92.016 45.349 94.512 50.053 ;
     RECT  95.616 49.525 96.792 50.053 ;
     RECT  125.856 43.955 129.672 50.149 ;
     RECT  117.792 44.965 119.064 50.195 ;
     RECT  245.136 46.211 245.712 50.195 ;
     RECT  92.016 50.053 96.792 50.291 ;
     RECT  103.248 48.421 103.752 50.339 ;
     RECT  248.736 49.333 248.76 50.579 ;
     RECT  115.8 48.949 116.664 50.771 ;
     RECT  120.288 49.331 121.656 50.771 ;
     RECT  101.808 43.955 101.832 51.205 ;
     RECT  131.04 44.437 132.312 51.347 ;
     RECT  229.2 41.027 229.992 51.443 ;
     RECT  103.248 50.339 103.656 51.493 ;
     RECT  104.88 42.803 105.672 51.493 ;
     RECT  106.656 44.725 108.696 51.493 ;
     RECT  250.8 48.997 251.832 51.683 ;
     RECT  115.8 50.771 116.112 51.781 ;
     RECT  136.944 47.363 140.28 51.829 ;
     RECT  103.248 51.493 108.696 51.923 ;
     RECT  226.272 51.637 226.296 52.307 ;
     RECT  92.64 50.291 96.792 52.309 ;
     RECT  98.832 48.851 100.344 52.499 ;
     RECT  113.76 50.051 114.552 52.499 ;
     RECT  92.64 52.309 97.416 52.549 ;
     RECT  125.856 50.149 129.96 52.741 ;
     RECT  98.928 52.499 100.344 52.835 ;
     RECT  91.488 52.549 91.512 52.837 ;
     RECT  115.8 51.781 116.52 52.837 ;
     RECT  101.52 51.205 101.832 52.981 ;
     RECT  103.296 51.923 108.696 52.981 ;
     RECT  92.64 52.549 97.656 53.365 ;
     RECT  103.104 52.981 108.696 53.365 ;
     RECT  114.912 52.837 116.664 53.365 ;
     RECT  117.792 50.195 118.92 53.365 ;
     RECT  125.856 52.741 130.296 53.555 ;
     RECT  92.64 53.365 97.752 53.557 ;
     RECT  114.912 53.365 118.92 54.179 ;
     RECT  92.592 53.557 97.752 54.181 ;
     RECT  119.952 53.557 119.976 54.277 ;
     RECT  119.952 54.277 120.216 54.323 ;
     RECT  120.192 54.323 120.216 54.469 ;
     RECT  121.2 50.771 121.656 54.469 ;
     RECT  103.104 53.365 108.84 54.611 ;
     RECT  103.104 54.611 108.696 54.661 ;
     RECT  120.192 54.469 121.656 55.379 ;
     RECT  99.024 52.835 100.344 55.381 ;
     RECT  101.52 52.981 101.88 55.381 ;
     RECT  92.544 54.181 97.752 55.811 ;
     RECT  118.272 54.179 118.92 55.813 ;
     RECT  118.272 55.813 119.112 55.955 ;
     RECT  125.856 53.555 129.672 56.101 ;
     RECT  123.6 54.085 123.624 56.195 ;
     RECT  125.856 56.101 130.584 56.341 ;
     RECT  102.96 54.661 108.696 56.389 ;
     RECT  110.4 46.643 111.48 56.389 ;
     RECT  136.944 51.829 140.376 56.629 ;
     RECT  92.64 55.811 97.752 56.725 ;
     RECT  99.024 55.381 101.88 56.725 ;
     RECT  92.64 56.725 101.88 57.059 ;
     RECT  120.624 55.379 121.656 57.157 ;
     RECT  118.656 55.955 119.112 57.445 ;
     RECT  92.64 57.059 100.344 57.587 ;
     RECT  101.52 57.059 101.88 57.635 ;
     RECT  114.912 54.179 117.096 57.877 ;
     RECT  118.08 57.445 119.112 57.877 ;
     RECT  124.944 56.341 130.584 58.117 ;
     RECT  131.616 51.347 132.312 58.117 ;
     RECT  91.392 52.837 91.512 58.163 ;
     RECT  92.64 57.587 97.752 58.163 ;
     RECT  114.912 57.877 119.112 58.163 ;
     RECT  92.64 58.163 96.216 58.259 ;
     RECT  135.696 54.661 135.72 58.501 ;
     RECT  136.8 56.629 140.376 58.501 ;
     RECT  91.392 58.163 91.464 58.549 ;
     RECT  98.832 57.587 100.344 58.645 ;
     RECT  120.528 57.157 121.656 58.645 ;
     RECT  101.664 57.635 101.88 58.739 ;
     RECT  113.76 52.499 113.928 58.739 ;
     RECT  115.8 58.163 119.112 58.739 ;
     RECT  92.64 58.259 96.12 58.787 ;
     RECT  97.248 58.163 97.752 58.787 ;
     RECT  91.344 58.549 91.464 58.835 ;
     RECT  97.248 58.787 97.416 58.883 ;
     RECT  120.288 58.645 121.656 59.029 ;
     RECT  98.832 58.645 100.68 59.221 ;
     RECT  101.664 58.739 101.688 59.221 ;
     RECT  117.936 58.739 119.112 59.221 ;
     RECT  120.288 59.029 122.136 59.221 ;
     RECT  135.696 58.501 140.376 59.221 ;
     RECT  102.96 56.389 111.48 59.315 ;
     RECT  113.76 58.739 113.784 59.605 ;
     RECT  117.936 59.221 122.136 59.605 ;
     RECT  98.832 59.221 101.688 59.797 ;
     RECT  135.648 59.221 140.376 59.797 ;
     RECT  103.152 59.315 111.48 59.891 ;
     RECT  98.832 59.797 101.736 60.037 ;
     RECT  117.936 59.605 122.232 60.133 ;
     RECT  124.944 58.117 132.312 60.133 ;
     RECT  133.584 54.661 133.608 60.133 ;
     RECT  91.344 58.835 91.368 60.181 ;
     RECT  92.64 58.787 95.592 60.181 ;
     RECT  98.688 60.037 101.736 60.277 ;
     RECT  117.936 60.133 122.472 60.277 ;
     RECT  113.568 59.605 113.784 60.323 ;
     RECT  124.944 60.133 132.408 60.325 ;
     RECT  133.584 60.133 134.184 60.325 ;
     RECT  91.344 60.181 95.592 60.373 ;
     RECT  98.688 60.277 102.12 60.373 ;
     RECT  135.648 59.797 140.712 60.373 ;
     RECT  97.248 58.883 97.272 60.467 ;
     RECT  113.76 60.323 113.784 60.467 ;
     RECT  135.6 60.373 140.712 60.613 ;
     RECT  117.552 60.277 122.472 60.661 ;
     RECT  104.16 59.891 111.48 60.853 ;
     RECT  98.592 60.373 102.12 60.949 ;
     RECT  104.16 60.853 111.528 60.949 ;
     RECT  117.552 60.661 123.24 60.949 ;
     RECT  124.944 60.325 134.184 60.949 ;
     RECT  90.816 60.373 95.592 61.043 ;
     RECT  117.552 60.949 134.184 61.043 ;
     RECT  114.096 60.949 114.12 61.093 ;
     RECT  104.16 60.949 111.72 61.189 ;
     RECT  90.816 61.043 91.368 61.477 ;
     RECT  98.352 60.949 102.12 61.477 ;
     RECT  103.152 59.891 103.176 61.477 ;
     RECT  114.096 61.093 114.216 61.477 ;
     RECT  135.6 60.613 141.576 61.477 ;
     RECT  104.16 61.189 111.912 61.525 ;
     RECT  135.504 61.477 141.576 61.525 ;
     RECT  90.384 61.477 91.368 62.101 ;
     RECT  92.64 61.043 95.592 62.101 ;
     RECT  104.16 61.525 112.68 62.101 ;
     RECT  114.096 61.477 114.312 62.101 ;
     RECT  98.352 61.477 103.176 62.149 ;
     RECT  104.16 62.101 112.776 62.149 ;
     RECT  114.096 62.101 114.408 62.149 ;
     RECT  115.8 58.739 116.112 62.149 ;
     RECT  117.936 61.043 134.184 62.149 ;
     RECT  98.352 62.149 134.472 62.533 ;
     RECT  135.504 61.525 141.768 62.533 ;
     RECT  98.352 62.533 141.768 62.581 ;
     RECT  97.776 62.581 141.768 62.629 ;
     RECT  142.8 2.151 143.112 62.629 ;
     RECT  2.4 44.003 2.712 62.649 ;
     RECT  7.8 2.151 8.112 62.649 ;
     RECT  13.2 2.151 13.512 62.649 ;
     RECT  18.6 2.151 18.912 62.649 ;
     RECT  24 2.151 24.312 62.649 ;
     RECT  29.4 2.151 29.712 62.649 ;
     RECT  34.8 2.151 35.112 62.649 ;
     RECT  40.2 2.151 40.512 62.649 ;
     RECT  45.6 2.151 45.912 62.649 ;
     RECT  51 2.151 51.312 62.649 ;
     RECT  56.4 2.151 56.712 62.649 ;
     RECT  61.8 2.151 62.112 62.649 ;
     RECT  67.2 2.151 67.512 62.649 ;
     RECT  72.6 2.151 72.912 62.649 ;
     RECT  78 2.151 78.312 62.649 ;
     RECT  83.4 2.151 83.712 62.649 ;
     RECT  88.8 2.151 89.112 62.649 ;
     RECT  97.392 62.629 143.112 62.649 ;
     RECT  148.2 2.151 148.512 62.649 ;
     RECT  153.6 2.151 153.912 62.649 ;
     RECT  159 2.151 159.312 62.649 ;
     RECT  164.4 2.151 164.712 62.649 ;
     RECT  169.8 2.151 170.112 62.649 ;
     RECT  175.2 2.151 175.512 62.649 ;
     RECT  180.6 2.151 180.912 62.649 ;
     RECT  186 2.151 186.312 62.649 ;
     RECT  191.4 2.151 191.712 62.649 ;
     RECT  196.8 2.151 197.112 62.649 ;
     RECT  202.2 2.151 202.512 62.649 ;
     RECT  207.6 42.083 207.912 62.649 ;
     RECT  213 32.243 213.312 62.649 ;
     RECT  218.4 41.939 218.712 62.649 ;
     RECT  223.8 40.547 224.112 62.649 ;
     RECT  229.2 51.443 229.512 62.649 ;
     RECT  234.6 45.971 234.912 62.649 ;
     RECT  240 49.811 240.312 62.649 ;
     RECT  245.4 50.195 245.712 62.649 ;
     RECT  250.8 51.683 251.112 62.649 ;
     RECT  256.2 45.635 256.512 62.649 ;
     RECT  261.6 36.659 261.912 62.649 ;
     RECT  267 37.091 267.312 62.649 ;
     RECT  2.4 62.649 2.52 62.663 ;
     RECT  7.8 62.649 7.92 62.663 ;
     RECT  13.2 62.649 13.32 62.663 ;
     RECT  18.6 62.649 18.72 62.663 ;
     RECT  24 62.649 24.12 62.663 ;
     RECT  29.4 62.649 29.52 62.663 ;
     RECT  34.8 62.649 34.92 62.663 ;
     RECT  40.2 62.649 40.32 62.663 ;
     RECT  45.6 62.649 45.72 62.663 ;
     RECT  51 62.649 51.12 62.663 ;
     RECT  56.4 62.649 56.52 62.663 ;
     RECT  61.8 62.649 61.92 62.663 ;
     RECT  67.2 62.649 67.32 62.663 ;
     RECT  72.6 62.649 72.72 62.663 ;
     RECT  78 62.649 78.12 62.663 ;
     RECT  83.4 62.649 83.52 62.663 ;
     RECT  88.8 62.649 88.92 62.663 ;
     RECT  97.392 62.649 142.92 62.663 ;
     RECT  148.2 62.649 148.32 62.663 ;
     RECT  153.6 62.649 153.72 62.663 ;
     RECT  159 62.649 159.12 62.663 ;
     RECT  164.4 62.649 164.52 62.663 ;
     RECT  169.8 62.649 169.92 62.663 ;
     RECT  175.2 62.649 175.32 62.663 ;
     RECT  180.6 62.649 180.72 62.663 ;
     RECT  186 62.649 186.12 62.663 ;
     RECT  191.4 62.649 191.52 62.663 ;
     RECT  196.8 62.649 196.92 62.663 ;
     RECT  202.2 62.649 202.32 62.663 ;
     RECT  207.6 62.649 207.72 62.663 ;
     RECT  213 62.649 213.12 62.663 ;
     RECT  218.4 62.649 218.52 62.663 ;
     RECT  223.8 62.649 223.92 62.663 ;
     RECT  229.2 62.649 229.32 62.663 ;
     RECT  234.6 62.649 234.72 62.663 ;
     RECT  240 62.649 240.12 62.663 ;
     RECT  245.4 62.649 245.52 62.663 ;
     RECT  250.8 62.649 250.92 62.663 ;
     RECT  256.2 62.649 256.32 62.663 ;
     RECT  261.6 62.649 261.72 62.663 ;
     RECT  267 62.649 267.12 62.663 ;
     RECT  97.392 62.663 141.864 62.677 ;
     RECT  90.384 62.101 96.264 63.253 ;
     RECT  97.296 62.677 141.864 63.253 ;
     RECT  90.384 63.253 141.864 64.691 ;
     RECT  90.384 64.691 141.768 64.784 ;
  END
END dsfd_svcio_job
END LIBRARY
